VERSION 5.8 ;
BUSBITCHARS "[]" ;
DIVIDERCHAR "/" ;
UNITS
    DATABASE MICRONS 1000 ;
END UNITS

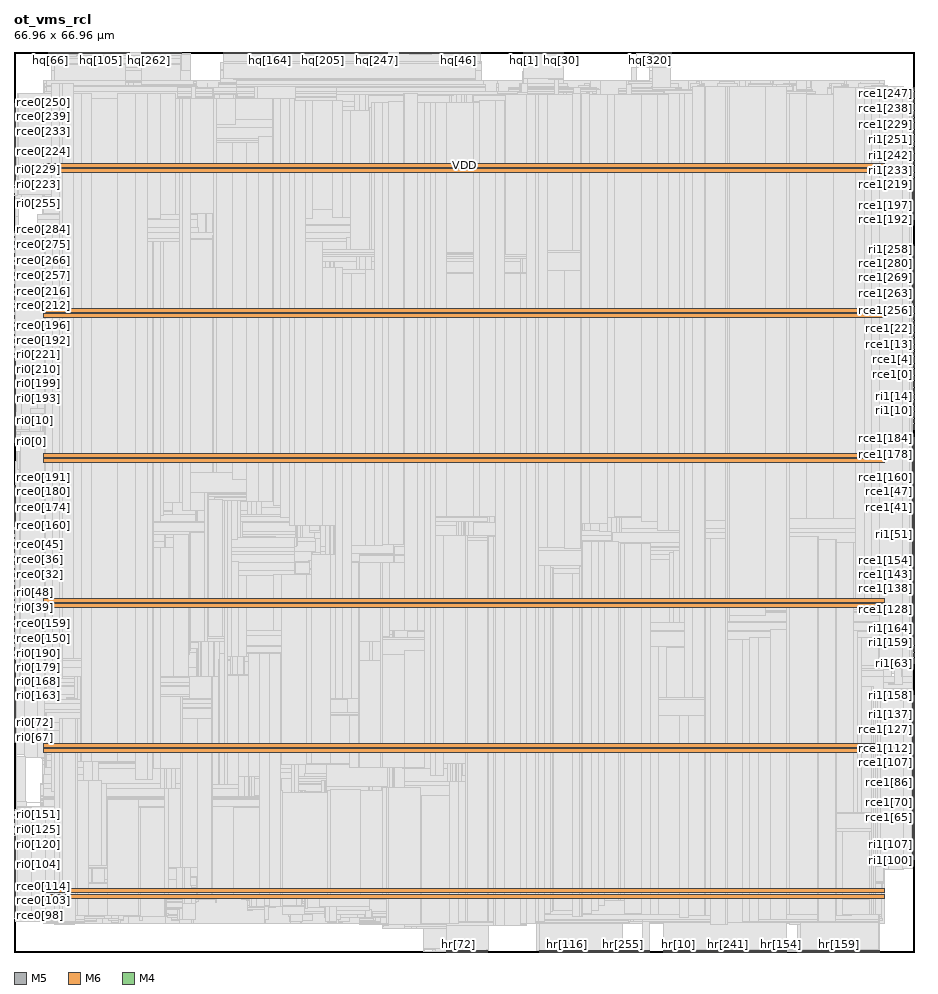
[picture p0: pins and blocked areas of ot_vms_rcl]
MACRO ot_vms_rcl
  FOREIGN ot_vms_rcl 0 0 ;
  CLASS BLOCK ;
  SIZE 66.96 BY 66.96 ;
  PIN clk
    DIRECTION INPUT ;
    USE SIGNAL ;
    PORT
      LAYER M5 ;
        RECT  48.336 0 48.36 0.084 ;
    END
  END clk
  PIN hq[0]
    DIRECTION OUTPUT ;
    USE SIGNAL ;
    PORT
      LAYER M5 ;
        RECT  37.872 66.876 37.896 66.96 ;
    END
  END hq[0]
  PIN hq[100]
    DIRECTION OUTPUT ;
    USE SIGNAL ;
    PORT
      LAYER M5 ;
        RECT  6 66.876 6.024 66.96 ;
    END
  END hq[100]
  PIN hq[101]
    DIRECTION OUTPUT ;
    USE SIGNAL ;
    PORT
      LAYER M5 ;
        RECT  6.096 66.876 6.12 66.96 ;
    END
  END hq[101]
  PIN hq[102]
    DIRECTION OUTPUT ;
    USE SIGNAL ;
    PORT
      LAYER M5 ;
        RECT  6.192 66.876 6.216 66.96 ;
    END
  END hq[102]
  PIN hq[103]
    DIRECTION OUTPUT ;
    USE SIGNAL ;
    PORT
      LAYER M5 ;
        RECT  6.288 66.876 6.312 66.96 ;
    END
  END hq[103]
  PIN hq[104]
    DIRECTION OUTPUT ;
    USE SIGNAL ;
    PORT
      LAYER M5 ;
        RECT  6.384 66.876 6.408 66.96 ;
    END
  END hq[104]
  PIN hq[105]
    DIRECTION OUTPUT ;
    USE SIGNAL ;
    PORT
      LAYER M5 ;
        RECT  6.48 66.876 6.504 66.96 ;
    END
  END hq[105]
  PIN hq[106]
    DIRECTION OUTPUT ;
    USE SIGNAL ;
    PORT
      LAYER M5 ;
        RECT  6.576 66.876 6.6 66.96 ;
    END
  END hq[106]
  PIN hq[107]
    DIRECTION OUTPUT ;
    USE SIGNAL ;
    PORT
      LAYER M5 ;
        RECT  6.672 66.876 6.696 66.96 ;
    END
  END hq[107]
  PIN hq[108]
    DIRECTION OUTPUT ;
    USE SIGNAL ;
    PORT
      LAYER M5 ;
        RECT  6.768 66.876 6.792 66.96 ;
    END
  END hq[108]
  PIN hq[109]
    DIRECTION OUTPUT ;
    USE SIGNAL ;
    PORT
      LAYER M5 ;
        RECT  6.864 66.876 6.888 66.96 ;
    END
  END hq[109]
  PIN hq[10]
    DIRECTION OUTPUT ;
    USE SIGNAL ;
    PORT
      LAYER M5 ;
        RECT  38.832 66.876 38.856 66.96 ;
    END
  END hq[10]
  PIN hq[110]
    DIRECTION OUTPUT ;
    USE SIGNAL ;
    PORT
      LAYER M5 ;
        RECT  6.96 66.876 6.984 66.96 ;
    END
  END hq[110]
  PIN hq[111]
    DIRECTION OUTPUT ;
    USE SIGNAL ;
    PORT
      LAYER M5 ;
        RECT  7.056 66.876 7.08 66.96 ;
    END
  END hq[111]
  PIN hq[112]
    DIRECTION OUTPUT ;
    USE SIGNAL ;
    PORT
      LAYER M5 ;
        RECT  7.152 66.876 7.176 66.96 ;
    END
  END hq[112]
  PIN hq[113]
    DIRECTION OUTPUT ;
    USE SIGNAL ;
    PORT
      LAYER M5 ;
        RECT  7.248 66.876 7.272 66.96 ;
    END
  END hq[113]
  PIN hq[114]
    DIRECTION OUTPUT ;
    USE SIGNAL ;
    PORT
      LAYER M5 ;
        RECT  7.344 66.876 7.368 66.96 ;
    END
  END hq[114]
  PIN hq[115]
    DIRECTION OUTPUT ;
    USE SIGNAL ;
    PORT
      LAYER M5 ;
        RECT  7.44 66.876 7.464 66.96 ;
    END
  END hq[115]
  PIN hq[116]
    DIRECTION OUTPUT ;
    USE SIGNAL ;
    PORT
      LAYER M5 ;
        RECT  7.536 66.876 7.56 66.96 ;
    END
  END hq[116]
  PIN hq[117]
    DIRECTION OUTPUT ;
    USE SIGNAL ;
    PORT
      LAYER M5 ;
        RECT  7.632 66.876 7.656 66.96 ;
    END
  END hq[117]
  PIN hq[118]
    DIRECTION OUTPUT ;
    USE SIGNAL ;
    PORT
      LAYER M5 ;
        RECT  7.728 66.876 7.752 66.96 ;
    END
  END hq[118]
  PIN hq[119]
    DIRECTION OUTPUT ;
    USE SIGNAL ;
    PORT
      LAYER M5 ;
        RECT  7.824 66.876 7.848 66.96 ;
    END
  END hq[119]
  PIN hq[11]
    DIRECTION OUTPUT ;
    USE SIGNAL ;
    PORT
      LAYER M5 ;
        RECT  38.928 66.876 38.952 66.96 ;
    END
  END hq[11]
  PIN hq[120]
    DIRECTION OUTPUT ;
    USE SIGNAL ;
    PORT
      LAYER M5 ;
        RECT  7.92 66.876 7.944 66.96 ;
    END
  END hq[120]
  PIN hq[121]
    DIRECTION OUTPUT ;
    USE SIGNAL ;
    PORT
      LAYER M5 ;
        RECT  8.016 66.876 8.04 66.96 ;
    END
  END hq[121]
  PIN hq[122]
    DIRECTION OUTPUT ;
    USE SIGNAL ;
    PORT
      LAYER M5 ;
        RECT  8.112 66.876 8.136 66.96 ;
    END
  END hq[122]
  PIN hq[123]
    DIRECTION OUTPUT ;
    USE SIGNAL ;
    PORT
      LAYER M5 ;
        RECT  8.208 66.876 8.232 66.96 ;
    END
  END hq[123]
  PIN hq[124]
    DIRECTION OUTPUT ;
    USE SIGNAL ;
    PORT
      LAYER M5 ;
        RECT  8.304 66.876 8.328 66.96 ;
    END
  END hq[124]
  PIN hq[125]
    DIRECTION OUTPUT ;
    USE SIGNAL ;
    PORT
      LAYER M5 ;
        RECT  8.4 66.876 8.424 66.96 ;
    END
  END hq[125]
  PIN hq[126]
    DIRECTION OUTPUT ;
    USE SIGNAL ;
    PORT
      LAYER M5 ;
        RECT  8.496 66.876 8.52 66.96 ;
    END
  END hq[126]
  PIN hq[127]
    DIRECTION OUTPUT ;
    USE SIGNAL ;
    PORT
      LAYER M5 ;
        RECT  8.592 66.876 8.616 66.96 ;
    END
  END hq[127]
  PIN hq[128]
    DIRECTION OUTPUT ;
    USE SIGNAL ;
    PORT
      LAYER M5 ;
        RECT  15.6 66.876 15.624 66.96 ;
    END
  END hq[128]
  PIN hq[129]
    DIRECTION OUTPUT ;
    USE SIGNAL ;
    PORT
      LAYER M5 ;
        RECT  15.696 66.876 15.72 66.96 ;
    END
  END hq[129]
  PIN hq[12]
    DIRECTION OUTPUT ;
    USE SIGNAL ;
    PORT
      LAYER M5 ;
        RECT  39.024 66.876 39.048 66.96 ;
    END
  END hq[12]
  PIN hq[130]
    DIRECTION OUTPUT ;
    USE SIGNAL ;
    PORT
      LAYER M5 ;
        RECT  15.792 66.876 15.816 66.96 ;
    END
  END hq[130]
  PIN hq[131]
    DIRECTION OUTPUT ;
    USE SIGNAL ;
    PORT
      LAYER M5 ;
        RECT  15.888 66.876 15.912 66.96 ;
    END
  END hq[131]
  PIN hq[132]
    DIRECTION OUTPUT ;
    USE SIGNAL ;
    PORT
      LAYER M5 ;
        RECT  15.984 66.876 16.008 66.96 ;
    END
  END hq[132]
  PIN hq[133]
    DIRECTION OUTPUT ;
    USE SIGNAL ;
    PORT
      LAYER M5 ;
        RECT  16.08 66.876 16.104 66.96 ;
    END
  END hq[133]
  PIN hq[134]
    DIRECTION OUTPUT ;
    USE SIGNAL ;
    PORT
      LAYER M5 ;
        RECT  16.176 66.876 16.2 66.96 ;
    END
  END hq[134]
  PIN hq[135]
    DIRECTION OUTPUT ;
    USE SIGNAL ;
    PORT
      LAYER M5 ;
        RECT  16.272 66.876 16.296 66.96 ;
    END
  END hq[135]
  PIN hq[136]
    DIRECTION OUTPUT ;
    USE SIGNAL ;
    PORT
      LAYER M5 ;
        RECT  16.368 66.876 16.392 66.96 ;
    END
  END hq[136]
  PIN hq[137]
    DIRECTION OUTPUT ;
    USE SIGNAL ;
    PORT
      LAYER M5 ;
        RECT  16.464 66.876 16.488 66.96 ;
    END
  END hq[137]
  PIN hq[138]
    DIRECTION OUTPUT ;
    USE SIGNAL ;
    PORT
      LAYER M5 ;
        RECT  16.56 66.876 16.584 66.96 ;
    END
  END hq[138]
  PIN hq[139]
    DIRECTION OUTPUT ;
    USE SIGNAL ;
    PORT
      LAYER M5 ;
        RECT  16.656 66.876 16.68 66.96 ;
    END
  END hq[139]
  PIN hq[13]
    DIRECTION OUTPUT ;
    USE SIGNAL ;
    PORT
      LAYER M5 ;
        RECT  39.12 66.876 39.144 66.96 ;
    END
  END hq[13]
  PIN hq[140]
    DIRECTION OUTPUT ;
    USE SIGNAL ;
    PORT
      LAYER M5 ;
        RECT  16.752 66.876 16.776 66.96 ;
    END
  END hq[140]
  PIN hq[141]
    DIRECTION OUTPUT ;
    USE SIGNAL ;
    PORT
      LAYER M5 ;
        RECT  16.848 66.876 16.872 66.96 ;
    END
  END hq[141]
  PIN hq[142]
    DIRECTION OUTPUT ;
    USE SIGNAL ;
    PORT
      LAYER M5 ;
        RECT  16.944 66.876 16.968 66.96 ;
    END
  END hq[142]
  PIN hq[143]
    DIRECTION OUTPUT ;
    USE SIGNAL ;
    PORT
      LAYER M5 ;
        RECT  17.04 66.876 17.064 66.96 ;
    END
  END hq[143]
  PIN hq[144]
    DIRECTION OUTPUT ;
    USE SIGNAL ;
    PORT
      LAYER M5 ;
        RECT  17.136 66.876 17.16 66.96 ;
    END
  END hq[144]
  PIN hq[145]
    DIRECTION OUTPUT ;
    USE SIGNAL ;
    PORT
      LAYER M5 ;
        RECT  17.232 66.876 17.256 66.96 ;
    END
  END hq[145]
  PIN hq[146]
    DIRECTION OUTPUT ;
    USE SIGNAL ;
    PORT
      LAYER M5 ;
        RECT  17.328 66.876 17.352 66.96 ;
    END
  END hq[146]
  PIN hq[147]
    DIRECTION OUTPUT ;
    USE SIGNAL ;
    PORT
      LAYER M5 ;
        RECT  17.424 66.876 17.448 66.96 ;
    END
  END hq[147]
  PIN hq[148]
    DIRECTION OUTPUT ;
    USE SIGNAL ;
    PORT
      LAYER M5 ;
        RECT  17.52 66.876 17.544 66.96 ;
    END
  END hq[148]
  PIN hq[149]
    DIRECTION OUTPUT ;
    USE SIGNAL ;
    PORT
      LAYER M5 ;
        RECT  17.616 66.876 17.64 66.96 ;
    END
  END hq[149]
  PIN hq[14]
    DIRECTION OUTPUT ;
    USE SIGNAL ;
    PORT
      LAYER M5 ;
        RECT  39.216 66.876 39.24 66.96 ;
    END
  END hq[14]
  PIN hq[150]
    DIRECTION OUTPUT ;
    USE SIGNAL ;
    PORT
      LAYER M5 ;
        RECT  17.712 66.876 17.736 66.96 ;
    END
  END hq[150]
  PIN hq[151]
    DIRECTION OUTPUT ;
    USE SIGNAL ;
    PORT
      LAYER M5 ;
        RECT  17.808 66.876 17.832 66.96 ;
    END
  END hq[151]
  PIN hq[152]
    DIRECTION OUTPUT ;
    USE SIGNAL ;
    PORT
      LAYER M5 ;
        RECT  17.904 66.876 17.928 66.96 ;
    END
  END hq[152]
  PIN hq[153]
    DIRECTION OUTPUT ;
    USE SIGNAL ;
    PORT
      LAYER M5 ;
        RECT  18 66.876 18.024 66.96 ;
    END
  END hq[153]
  PIN hq[154]
    DIRECTION OUTPUT ;
    USE SIGNAL ;
    PORT
      LAYER M5 ;
        RECT  18.096 66.876 18.12 66.96 ;
    END
  END hq[154]
  PIN hq[155]
    DIRECTION OUTPUT ;
    USE SIGNAL ;
    PORT
      LAYER M5 ;
        RECT  18.192 66.876 18.216 66.96 ;
    END
  END hq[155]
  PIN hq[156]
    DIRECTION OUTPUT ;
    USE SIGNAL ;
    PORT
      LAYER M5 ;
        RECT  18.288 66.876 18.312 66.96 ;
    END
  END hq[156]
  PIN hq[157]
    DIRECTION OUTPUT ;
    USE SIGNAL ;
    PORT
      LAYER M5 ;
        RECT  18.384 66.876 18.408 66.96 ;
    END
  END hq[157]
  PIN hq[158]
    DIRECTION OUTPUT ;
    USE SIGNAL ;
    PORT
      LAYER M5 ;
        RECT  18.48 66.876 18.504 66.96 ;
    END
  END hq[158]
  PIN hq[159]
    DIRECTION OUTPUT ;
    USE SIGNAL ;
    PORT
      LAYER M5 ;
        RECT  18.576 66.876 18.6 66.96 ;
    END
  END hq[159]
  PIN hq[15]
    DIRECTION OUTPUT ;
    USE SIGNAL ;
    PORT
      LAYER M5 ;
        RECT  39.312 66.876 39.336 66.96 ;
    END
  END hq[15]
  PIN hq[160]
    DIRECTION OUTPUT ;
    USE SIGNAL ;
    PORT
      LAYER M5 ;
        RECT  18.672 66.876 18.696 66.96 ;
    END
  END hq[160]
  PIN hq[161]
    DIRECTION OUTPUT ;
    USE SIGNAL ;
    PORT
      LAYER M5 ;
        RECT  18.768 66.876 18.792 66.96 ;
    END
  END hq[161]
  PIN hq[162]
    DIRECTION OUTPUT ;
    USE SIGNAL ;
    PORT
      LAYER M5 ;
        RECT  18.864 66.876 18.888 66.96 ;
    END
  END hq[162]
  PIN hq[163]
    DIRECTION OUTPUT ;
    USE SIGNAL ;
    PORT
      LAYER M5 ;
        RECT  18.96 66.876 18.984 66.96 ;
    END
  END hq[163]
  PIN hq[164]
    DIRECTION OUTPUT ;
    USE SIGNAL ;
    PORT
      LAYER M5 ;
        RECT  19.056 66.876 19.08 66.96 ;
    END
  END hq[164]
  PIN hq[165]
    DIRECTION OUTPUT ;
    USE SIGNAL ;
    PORT
      LAYER M5 ;
        RECT  19.152 66.876 19.176 66.96 ;
    END
  END hq[165]
  PIN hq[166]
    DIRECTION OUTPUT ;
    USE SIGNAL ;
    PORT
      LAYER M5 ;
        RECT  19.248 66.876 19.272 66.96 ;
    END
  END hq[166]
  PIN hq[167]
    DIRECTION OUTPUT ;
    USE SIGNAL ;
    PORT
      LAYER M5 ;
        RECT  19.344 66.876 19.368 66.96 ;
    END
  END hq[167]
  PIN hq[168]
    DIRECTION OUTPUT ;
    USE SIGNAL ;
    PORT
      LAYER M5 ;
        RECT  19.44 66.876 19.464 66.96 ;
    END
  END hq[168]
  PIN hq[169]
    DIRECTION OUTPUT ;
    USE SIGNAL ;
    PORT
      LAYER M5 ;
        RECT  19.536 66.876 19.56 66.96 ;
    END
  END hq[169]
  PIN hq[16]
    DIRECTION OUTPUT ;
    USE SIGNAL ;
    PORT
      LAYER M5 ;
        RECT  39.408 66.876 39.432 66.96 ;
    END
  END hq[16]
  PIN hq[170]
    DIRECTION OUTPUT ;
    USE SIGNAL ;
    PORT
      LAYER M5 ;
        RECT  19.632 66.876 19.656 66.96 ;
    END
  END hq[170]
  PIN hq[171]
    DIRECTION OUTPUT ;
    USE SIGNAL ;
    PORT
      LAYER M5 ;
        RECT  19.728 66.876 19.752 66.96 ;
    END
  END hq[171]
  PIN hq[172]
    DIRECTION OUTPUT ;
    USE SIGNAL ;
    PORT
      LAYER M5 ;
        RECT  19.824 66.876 19.848 66.96 ;
    END
  END hq[172]
  PIN hq[173]
    DIRECTION OUTPUT ;
    USE SIGNAL ;
    PORT
      LAYER M5 ;
        RECT  19.92 66.876 19.944 66.96 ;
    END
  END hq[173]
  PIN hq[174]
    DIRECTION OUTPUT ;
    USE SIGNAL ;
    PORT
      LAYER M5 ;
        RECT  20.016 66.876 20.04 66.96 ;
    END
  END hq[174]
  PIN hq[175]
    DIRECTION OUTPUT ;
    USE SIGNAL ;
    PORT
      LAYER M5 ;
        RECT  20.112 66.876 20.136 66.96 ;
    END
  END hq[175]
  PIN hq[176]
    DIRECTION OUTPUT ;
    USE SIGNAL ;
    PORT
      LAYER M5 ;
        RECT  20.208 66.876 20.232 66.96 ;
    END
  END hq[176]
  PIN hq[177]
    DIRECTION OUTPUT ;
    USE SIGNAL ;
    PORT
      LAYER M5 ;
        RECT  20.304 66.876 20.328 66.96 ;
    END
  END hq[177]
  PIN hq[178]
    DIRECTION OUTPUT ;
    USE SIGNAL ;
    PORT
      LAYER M5 ;
        RECT  20.4 66.876 20.424 66.96 ;
    END
  END hq[178]
  PIN hq[179]
    DIRECTION OUTPUT ;
    USE SIGNAL ;
    PORT
      LAYER M5 ;
        RECT  20.496 66.876 20.52 66.96 ;
    END
  END hq[179]
  PIN hq[17]
    DIRECTION OUTPUT ;
    USE SIGNAL ;
    PORT
      LAYER M5 ;
        RECT  39.504 66.876 39.528 66.96 ;
    END
  END hq[17]
  PIN hq[180]
    DIRECTION OUTPUT ;
    USE SIGNAL ;
    PORT
      LAYER M5 ;
        RECT  20.592 66.876 20.616 66.96 ;
    END
  END hq[180]
  PIN hq[181]
    DIRECTION OUTPUT ;
    USE SIGNAL ;
    PORT
      LAYER M5 ;
        RECT  20.688 66.876 20.712 66.96 ;
    END
  END hq[181]
  PIN hq[182]
    DIRECTION OUTPUT ;
    USE SIGNAL ;
    PORT
      LAYER M5 ;
        RECT  20.784 66.876 20.808 66.96 ;
    END
  END hq[182]
  PIN hq[183]
    DIRECTION OUTPUT ;
    USE SIGNAL ;
    PORT
      LAYER M5 ;
        RECT  20.88 66.876 20.904 66.96 ;
    END
  END hq[183]
  PIN hq[184]
    DIRECTION OUTPUT ;
    USE SIGNAL ;
    PORT
      LAYER M5 ;
        RECT  20.976 66.876 21 66.96 ;
    END
  END hq[184]
  PIN hq[185]
    DIRECTION OUTPUT ;
    USE SIGNAL ;
    PORT
      LAYER M5 ;
        RECT  21.072 66.876 21.096 66.96 ;
    END
  END hq[185]
  PIN hq[186]
    DIRECTION OUTPUT ;
    USE SIGNAL ;
    PORT
      LAYER M5 ;
        RECT  21.168 66.876 21.192 66.96 ;
    END
  END hq[186]
  PIN hq[187]
    DIRECTION OUTPUT ;
    USE SIGNAL ;
    PORT
      LAYER M5 ;
        RECT  21.264 66.876 21.288 66.96 ;
    END
  END hq[187]
  PIN hq[188]
    DIRECTION OUTPUT ;
    USE SIGNAL ;
    PORT
      LAYER M5 ;
        RECT  21.36 66.876 21.384 66.96 ;
    END
  END hq[188]
  PIN hq[189]
    DIRECTION OUTPUT ;
    USE SIGNAL ;
    PORT
      LAYER M5 ;
        RECT  21.456 66.876 21.48 66.96 ;
    END
  END hq[189]
  PIN hq[18]
    DIRECTION OUTPUT ;
    USE SIGNAL ;
    PORT
      LAYER M5 ;
        RECT  39.6 66.876 39.624 66.96 ;
    END
  END hq[18]
  PIN hq[190]
    DIRECTION OUTPUT ;
    USE SIGNAL ;
    PORT
      LAYER M5 ;
        RECT  21.552 66.876 21.576 66.96 ;
    END
  END hq[190]
  PIN hq[191]
    DIRECTION OUTPUT ;
    USE SIGNAL ;
    PORT
      LAYER M5 ;
        RECT  21.648 66.876 21.672 66.96 ;
    END
  END hq[191]
  PIN hq[192]
    DIRECTION OUTPUT ;
    USE SIGNAL ;
    PORT
      LAYER M5 ;
        RECT  21.744 66.876 21.768 66.96 ;
    END
  END hq[192]
  PIN hq[193]
    DIRECTION OUTPUT ;
    USE SIGNAL ;
    PORT
      LAYER M5 ;
        RECT  21.84 66.876 21.864 66.96 ;
    END
  END hq[193]
  PIN hq[194]
    DIRECTION OUTPUT ;
    USE SIGNAL ;
    PORT
      LAYER M5 ;
        RECT  21.936 66.876 21.96 66.96 ;
    END
  END hq[194]
  PIN hq[195]
    DIRECTION OUTPUT ;
    USE SIGNAL ;
    PORT
      LAYER M5 ;
        RECT  22.032 66.876 22.056 66.96 ;
    END
  END hq[195]
  PIN hq[196]
    DIRECTION OUTPUT ;
    USE SIGNAL ;
    PORT
      LAYER M5 ;
        RECT  22.128 66.876 22.152 66.96 ;
    END
  END hq[196]
  PIN hq[197]
    DIRECTION OUTPUT ;
    USE SIGNAL ;
    PORT
      LAYER M5 ;
        RECT  22.224 66.876 22.248 66.96 ;
    END
  END hq[197]
  PIN hq[198]
    DIRECTION OUTPUT ;
    USE SIGNAL ;
    PORT
      LAYER M5 ;
        RECT  22.32 66.876 22.344 66.96 ;
    END
  END hq[198]
  PIN hq[199]
    DIRECTION OUTPUT ;
    USE SIGNAL ;
    PORT
      LAYER M5 ;
        RECT  22.416 66.876 22.44 66.96 ;
    END
  END hq[199]
  PIN hq[19]
    DIRECTION OUTPUT ;
    USE SIGNAL ;
    PORT
      LAYER M5 ;
        RECT  39.696 66.876 39.72 66.96 ;
    END
  END hq[19]
  PIN hq[1]
    DIRECTION OUTPUT ;
    USE SIGNAL ;
    PORT
      LAYER M5 ;
        RECT  37.968 66.876 37.992 66.96 ;
    END
  END hq[1]
  PIN hq[200]
    DIRECTION OUTPUT ;
    USE SIGNAL ;
    PORT
      LAYER M5 ;
        RECT  22.512 66.876 22.536 66.96 ;
    END
  END hq[200]
  PIN hq[201]
    DIRECTION OUTPUT ;
    USE SIGNAL ;
    PORT
      LAYER M5 ;
        RECT  22.608 66.876 22.632 66.96 ;
    END
  END hq[201]
  PIN hq[202]
    DIRECTION OUTPUT ;
    USE SIGNAL ;
    PORT
      LAYER M5 ;
        RECT  22.704 66.876 22.728 66.96 ;
    END
  END hq[202]
  PIN hq[203]
    DIRECTION OUTPUT ;
    USE SIGNAL ;
    PORT
      LAYER M5 ;
        RECT  22.8 66.876 22.824 66.96 ;
    END
  END hq[203]
  PIN hq[204]
    DIRECTION OUTPUT ;
    USE SIGNAL ;
    PORT
      LAYER M5 ;
        RECT  22.896 66.876 22.92 66.96 ;
    END
  END hq[204]
  PIN hq[205]
    DIRECTION OUTPUT ;
    USE SIGNAL ;
    PORT
      LAYER M5 ;
        RECT  22.992 66.876 23.016 66.96 ;
    END
  END hq[205]
  PIN hq[206]
    DIRECTION OUTPUT ;
    USE SIGNAL ;
    PORT
      LAYER M5 ;
        RECT  23.088 66.876 23.112 66.96 ;
    END
  END hq[206]
  PIN hq[207]
    DIRECTION OUTPUT ;
    USE SIGNAL ;
    PORT
      LAYER M5 ;
        RECT  23.184 66.876 23.208 66.96 ;
    END
  END hq[207]
  PIN hq[208]
    DIRECTION OUTPUT ;
    USE SIGNAL ;
    PORT
      LAYER M5 ;
        RECT  23.28 66.876 23.304 66.96 ;
    END
  END hq[208]
  PIN hq[209]
    DIRECTION OUTPUT ;
    USE SIGNAL ;
    PORT
      LAYER M5 ;
        RECT  23.376 66.876 23.4 66.96 ;
    END
  END hq[209]
  PIN hq[20]
    DIRECTION OUTPUT ;
    USE SIGNAL ;
    PORT
      LAYER M5 ;
        RECT  39.792 66.876 39.816 66.96 ;
    END
  END hq[20]
  PIN hq[210]
    DIRECTION OUTPUT ;
    USE SIGNAL ;
    PORT
      LAYER M5 ;
        RECT  23.472 66.876 23.496 66.96 ;
    END
  END hq[210]
  PIN hq[211]
    DIRECTION OUTPUT ;
    USE SIGNAL ;
    PORT
      LAYER M5 ;
        RECT  23.568 66.876 23.592 66.96 ;
    END
  END hq[211]
  PIN hq[212]
    DIRECTION OUTPUT ;
    USE SIGNAL ;
    PORT
      LAYER M5 ;
        RECT  23.664 66.876 23.688 66.96 ;
    END
  END hq[212]
  PIN hq[213]
    DIRECTION OUTPUT ;
    USE SIGNAL ;
    PORT
      LAYER M5 ;
        RECT  23.76 66.876 23.784 66.96 ;
    END
  END hq[213]
  PIN hq[214]
    DIRECTION OUTPUT ;
    USE SIGNAL ;
    PORT
      LAYER M5 ;
        RECT  23.856 66.876 23.88 66.96 ;
    END
  END hq[214]
  PIN hq[215]
    DIRECTION OUTPUT ;
    USE SIGNAL ;
    PORT
      LAYER M5 ;
        RECT  23.952 66.876 23.976 66.96 ;
    END
  END hq[215]
  PIN hq[216]
    DIRECTION OUTPUT ;
    USE SIGNAL ;
    PORT
      LAYER M5 ;
        RECT  24.048 66.876 24.072 66.96 ;
    END
  END hq[216]
  PIN hq[217]
    DIRECTION OUTPUT ;
    USE SIGNAL ;
    PORT
      LAYER M5 ;
        RECT  24.144 66.876 24.168 66.96 ;
    END
  END hq[217]
  PIN hq[218]
    DIRECTION OUTPUT ;
    USE SIGNAL ;
    PORT
      LAYER M5 ;
        RECT  24.24 66.876 24.264 66.96 ;
    END
  END hq[218]
  PIN hq[219]
    DIRECTION OUTPUT ;
    USE SIGNAL ;
    PORT
      LAYER M5 ;
        RECT  24.336 66.876 24.36 66.96 ;
    END
  END hq[219]
  PIN hq[21]
    DIRECTION OUTPUT ;
    USE SIGNAL ;
    PORT
      LAYER M5 ;
        RECT  39.888 66.876 39.912 66.96 ;
    END
  END hq[21]
  PIN hq[220]
    DIRECTION OUTPUT ;
    USE SIGNAL ;
    PORT
      LAYER M5 ;
        RECT  24.432 66.876 24.456 66.96 ;
    END
  END hq[220]
  PIN hq[221]
    DIRECTION OUTPUT ;
    USE SIGNAL ;
    PORT
      LAYER M5 ;
        RECT  24.528 66.876 24.552 66.96 ;
    END
  END hq[221]
  PIN hq[222]
    DIRECTION OUTPUT ;
    USE SIGNAL ;
    PORT
      LAYER M5 ;
        RECT  24.624 66.876 24.648 66.96 ;
    END
  END hq[222]
  PIN hq[223]
    DIRECTION OUTPUT ;
    USE SIGNAL ;
    PORT
      LAYER M5 ;
        RECT  24.72 66.876 24.744 66.96 ;
    END
  END hq[223]
  PIN hq[224]
    DIRECTION OUTPUT ;
    USE SIGNAL ;
    PORT
      LAYER M5 ;
        RECT  24.816 66.876 24.84 66.96 ;
    END
  END hq[224]
  PIN hq[225]
    DIRECTION OUTPUT ;
    USE SIGNAL ;
    PORT
      LAYER M5 ;
        RECT  24.912 66.876 24.936 66.96 ;
    END
  END hq[225]
  PIN hq[226]
    DIRECTION OUTPUT ;
    USE SIGNAL ;
    PORT
      LAYER M5 ;
        RECT  25.008 66.876 25.032 66.96 ;
    END
  END hq[226]
  PIN hq[227]
    DIRECTION OUTPUT ;
    USE SIGNAL ;
    PORT
      LAYER M5 ;
        RECT  25.104 66.876 25.128 66.96 ;
    END
  END hq[227]
  PIN hq[228]
    DIRECTION OUTPUT ;
    USE SIGNAL ;
    PORT
      LAYER M5 ;
        RECT  25.2 66.876 25.224 66.96 ;
    END
  END hq[228]
  PIN hq[229]
    DIRECTION OUTPUT ;
    USE SIGNAL ;
    PORT
      LAYER M5 ;
        RECT  25.296 66.876 25.32 66.96 ;
    END
  END hq[229]
  PIN hq[22]
    DIRECTION OUTPUT ;
    USE SIGNAL ;
    PORT
      LAYER M5 ;
        RECT  39.984 66.876 40.008 66.96 ;
    END
  END hq[22]
  PIN hq[230]
    DIRECTION OUTPUT ;
    USE SIGNAL ;
    PORT
      LAYER M5 ;
        RECT  25.392 66.876 25.416 66.96 ;
    END
  END hq[230]
  PIN hq[231]
    DIRECTION OUTPUT ;
    USE SIGNAL ;
    PORT
      LAYER M5 ;
        RECT  25.488 66.876 25.512 66.96 ;
    END
  END hq[231]
  PIN hq[232]
    DIRECTION OUTPUT ;
    USE SIGNAL ;
    PORT
      LAYER M5 ;
        RECT  25.584 66.876 25.608 66.96 ;
    END
  END hq[232]
  PIN hq[233]
    DIRECTION OUTPUT ;
    USE SIGNAL ;
    PORT
      LAYER M5 ;
        RECT  25.68 66.876 25.704 66.96 ;
    END
  END hq[233]
  PIN hq[234]
    DIRECTION OUTPUT ;
    USE SIGNAL ;
    PORT
      LAYER M5 ;
        RECT  25.776 66.876 25.8 66.96 ;
    END
  END hq[234]
  PIN hq[235]
    DIRECTION OUTPUT ;
    USE SIGNAL ;
    PORT
      LAYER M5 ;
        RECT  25.872 66.876 25.896 66.96 ;
    END
  END hq[235]
  PIN hq[236]
    DIRECTION OUTPUT ;
    USE SIGNAL ;
    PORT
      LAYER M5 ;
        RECT  25.968 66.876 25.992 66.96 ;
    END
  END hq[236]
  PIN hq[237]
    DIRECTION OUTPUT ;
    USE SIGNAL ;
    PORT
      LAYER M5 ;
        RECT  26.064 66.876 26.088 66.96 ;
    END
  END hq[237]
  PIN hq[238]
    DIRECTION OUTPUT ;
    USE SIGNAL ;
    PORT
      LAYER M5 ;
        RECT  26.16 66.876 26.184 66.96 ;
    END
  END hq[238]
  PIN hq[239]
    DIRECTION OUTPUT ;
    USE SIGNAL ;
    PORT
      LAYER M5 ;
        RECT  26.256 66.876 26.28 66.96 ;
    END
  END hq[239]
  PIN hq[23]
    DIRECTION OUTPUT ;
    USE SIGNAL ;
    PORT
      LAYER M5 ;
        RECT  40.08 66.876 40.104 66.96 ;
    END
  END hq[23]
  PIN hq[240]
    DIRECTION OUTPUT ;
    USE SIGNAL ;
    PORT
      LAYER M5 ;
        RECT  26.352 66.876 26.376 66.96 ;
    END
  END hq[240]
  PIN hq[241]
    DIRECTION OUTPUT ;
    USE SIGNAL ;
    PORT
      LAYER M5 ;
        RECT  26.448 66.876 26.472 66.96 ;
    END
  END hq[241]
  PIN hq[242]
    DIRECTION OUTPUT ;
    USE SIGNAL ;
    PORT
      LAYER M5 ;
        RECT  26.544 66.876 26.568 66.96 ;
    END
  END hq[242]
  PIN hq[243]
    DIRECTION OUTPUT ;
    USE SIGNAL ;
    PORT
      LAYER M5 ;
        RECT  26.64 66.876 26.664 66.96 ;
    END
  END hq[243]
  PIN hq[244]
    DIRECTION OUTPUT ;
    USE SIGNAL ;
    PORT
      LAYER M5 ;
        RECT  26.736 66.876 26.76 66.96 ;
    END
  END hq[244]
  PIN hq[245]
    DIRECTION OUTPUT ;
    USE SIGNAL ;
    PORT
      LAYER M5 ;
        RECT  26.832 66.876 26.856 66.96 ;
    END
  END hq[245]
  PIN hq[246]
    DIRECTION OUTPUT ;
    USE SIGNAL ;
    PORT
      LAYER M5 ;
        RECT  26.928 66.876 26.952 66.96 ;
    END
  END hq[246]
  PIN hq[247]
    DIRECTION OUTPUT ;
    USE SIGNAL ;
    PORT
      LAYER M5 ;
        RECT  27.024 66.876 27.048 66.96 ;
    END
  END hq[247]
  PIN hq[248]
    DIRECTION OUTPUT ;
    USE SIGNAL ;
    PORT
      LAYER M5 ;
        RECT  27.12 66.876 27.144 66.96 ;
    END
  END hq[248]
  PIN hq[249]
    DIRECTION OUTPUT ;
    USE SIGNAL ;
    PORT
      LAYER M5 ;
        RECT  27.216 66.876 27.24 66.96 ;
    END
  END hq[249]
  PIN hq[24]
    DIRECTION OUTPUT ;
    USE SIGNAL ;
    PORT
      LAYER M5 ;
        RECT  40.176 66.876 40.2 66.96 ;
    END
  END hq[24]
  PIN hq[250]
    DIRECTION OUTPUT ;
    USE SIGNAL ;
    PORT
      LAYER M5 ;
        RECT  27.312 66.876 27.336 66.96 ;
    END
  END hq[250]
  PIN hq[251]
    DIRECTION OUTPUT ;
    USE SIGNAL ;
    PORT
      LAYER M5 ;
        RECT  27.408 66.876 27.432 66.96 ;
    END
  END hq[251]
  PIN hq[252]
    DIRECTION OUTPUT ;
    USE SIGNAL ;
    PORT
      LAYER M5 ;
        RECT  27.504 66.876 27.528 66.96 ;
    END
  END hq[252]
  PIN hq[253]
    DIRECTION OUTPUT ;
    USE SIGNAL ;
    PORT
      LAYER M5 ;
        RECT  27.6 66.876 27.624 66.96 ;
    END
  END hq[253]
  PIN hq[254]
    DIRECTION OUTPUT ;
    USE SIGNAL ;
    PORT
      LAYER M5 ;
        RECT  27.696 66.876 27.72 66.96 ;
    END
  END hq[254]
  PIN hq[255]
    DIRECTION OUTPUT ;
    USE SIGNAL ;
    PORT
      LAYER M5 ;
        RECT  27.792 66.876 27.816 66.96 ;
    END
  END hq[255]
  PIN hq[256]
    DIRECTION OUTPUT ;
    USE SIGNAL ;
    PORT
      LAYER M5 ;
        RECT  9.456 66.876 9.48 66.96 ;
    END
  END hq[256]
  PIN hq[257]
    DIRECTION OUTPUT ;
    USE SIGNAL ;
    PORT
      LAYER M5 ;
        RECT  9.552 66.876 9.576 66.96 ;
    END
  END hq[257]
  PIN hq[258]
    DIRECTION OUTPUT ;
    USE SIGNAL ;
    PORT
      LAYER M5 ;
        RECT  9.648 66.876 9.672 66.96 ;
    END
  END hq[258]
  PIN hq[259]
    DIRECTION OUTPUT ;
    USE SIGNAL ;
    PORT
      LAYER M5 ;
        RECT  9.744 66.876 9.768 66.96 ;
    END
  END hq[259]
  PIN hq[25]
    DIRECTION OUTPUT ;
    USE SIGNAL ;
    PORT
      LAYER M5 ;
        RECT  40.272 66.876 40.296 66.96 ;
    END
  END hq[25]
  PIN hq[260]
    DIRECTION OUTPUT ;
    USE SIGNAL ;
    PORT
      LAYER M5 ;
        RECT  9.84 66.876 9.864 66.96 ;
    END
  END hq[260]
  PIN hq[261]
    DIRECTION OUTPUT ;
    USE SIGNAL ;
    PORT
      LAYER M5 ;
        RECT  9.936 66.876 9.96 66.96 ;
    END
  END hq[261]
  PIN hq[262]
    DIRECTION OUTPUT ;
    USE SIGNAL ;
    PORT
      LAYER M5 ;
        RECT  10.032 66.876 10.056 66.96 ;
    END
  END hq[262]
  PIN hq[263]
    DIRECTION OUTPUT ;
    USE SIGNAL ;
    PORT
      LAYER M5 ;
        RECT  10.128 66.876 10.152 66.96 ;
    END
  END hq[263]
  PIN hq[264]
    DIRECTION OUTPUT ;
    USE SIGNAL ;
    PORT
      LAYER M5 ;
        RECT  10.224 66.876 10.248 66.96 ;
    END
  END hq[264]
  PIN hq[265]
    DIRECTION OUTPUT ;
    USE SIGNAL ;
    PORT
      LAYER M5 ;
        RECT  10.32 66.876 10.344 66.96 ;
    END
  END hq[265]
  PIN hq[266]
    DIRECTION OUTPUT ;
    USE SIGNAL ;
    PORT
      LAYER M5 ;
        RECT  10.416 66.876 10.44 66.96 ;
    END
  END hq[266]
  PIN hq[267]
    DIRECTION OUTPUT ;
    USE SIGNAL ;
    PORT
      LAYER M5 ;
        RECT  10.512 66.876 10.536 66.96 ;
    END
  END hq[267]
  PIN hq[268]
    DIRECTION OUTPUT ;
    USE SIGNAL ;
    PORT
      LAYER M5 ;
        RECT  10.608 66.876 10.632 66.96 ;
    END
  END hq[268]
  PIN hq[269]
    DIRECTION OUTPUT ;
    USE SIGNAL ;
    PORT
      LAYER M5 ;
        RECT  10.704 66.876 10.728 66.96 ;
    END
  END hq[269]
  PIN hq[26]
    DIRECTION OUTPUT ;
    USE SIGNAL ;
    PORT
      LAYER M5 ;
        RECT  40.368 66.876 40.392 66.96 ;
    END
  END hq[26]
  PIN hq[270]
    DIRECTION OUTPUT ;
    USE SIGNAL ;
    PORT
      LAYER M5 ;
        RECT  10.8 66.876 10.824 66.96 ;
    END
  END hq[270]
  PIN hq[271]
    DIRECTION OUTPUT ;
    USE SIGNAL ;
    PORT
      LAYER M5 ;
        RECT  10.896 66.876 10.92 66.96 ;
    END
  END hq[271]
  PIN hq[272]
    DIRECTION OUTPUT ;
    USE SIGNAL ;
    PORT
      LAYER M5 ;
        RECT  10.992 66.876 11.016 66.96 ;
    END
  END hq[272]
  PIN hq[273]
    DIRECTION OUTPUT ;
    USE SIGNAL ;
    PORT
      LAYER M5 ;
        RECT  11.088 66.876 11.112 66.96 ;
    END
  END hq[273]
  PIN hq[274]
    DIRECTION OUTPUT ;
    USE SIGNAL ;
    PORT
      LAYER M5 ;
        RECT  11.184 66.876 11.208 66.96 ;
    END
  END hq[274]
  PIN hq[275]
    DIRECTION OUTPUT ;
    USE SIGNAL ;
    PORT
      LAYER M5 ;
        RECT  11.28 66.876 11.304 66.96 ;
    END
  END hq[275]
  PIN hq[276]
    DIRECTION OUTPUT ;
    USE SIGNAL ;
    PORT
      LAYER M5 ;
        RECT  11.376 66.876 11.4 66.96 ;
    END
  END hq[276]
  PIN hq[277]
    DIRECTION OUTPUT ;
    USE SIGNAL ;
    PORT
      LAYER M5 ;
        RECT  11.472 66.876 11.496 66.96 ;
    END
  END hq[277]
  PIN hq[278]
    DIRECTION OUTPUT ;
    USE SIGNAL ;
    PORT
      LAYER M5 ;
        RECT  11.568 66.876 11.592 66.96 ;
    END
  END hq[278]
  PIN hq[279]
    DIRECTION OUTPUT ;
    USE SIGNAL ;
    PORT
      LAYER M5 ;
        RECT  11.664 66.876 11.688 66.96 ;
    END
  END hq[279]
  PIN hq[27]
    DIRECTION OUTPUT ;
    USE SIGNAL ;
    PORT
      LAYER M5 ;
        RECT  40.464 66.876 40.488 66.96 ;
    END
  END hq[27]
  PIN hq[280]
    DIRECTION OUTPUT ;
    USE SIGNAL ;
    PORT
      LAYER M5 ;
        RECT  11.76 66.876 11.784 66.96 ;
    END
  END hq[280]
  PIN hq[281]
    DIRECTION OUTPUT ;
    USE SIGNAL ;
    PORT
      LAYER M5 ;
        RECT  11.856 66.876 11.88 66.96 ;
    END
  END hq[281]
  PIN hq[282]
    DIRECTION OUTPUT ;
    USE SIGNAL ;
    PORT
      LAYER M5 ;
        RECT  11.952 66.876 11.976 66.96 ;
    END
  END hq[282]
  PIN hq[283]
    DIRECTION OUTPUT ;
    USE SIGNAL ;
    PORT
      LAYER M5 ;
        RECT  12.048 66.876 12.072 66.96 ;
    END
  END hq[283]
  PIN hq[284]
    DIRECTION OUTPUT ;
    USE SIGNAL ;
    PORT
      LAYER M5 ;
        RECT  12.144 66.876 12.168 66.96 ;
    END
  END hq[284]
  PIN hq[285]
    DIRECTION OUTPUT ;
    USE SIGNAL ;
    PORT
      LAYER M5 ;
        RECT  12.24 66.876 12.264 66.96 ;
    END
  END hq[285]
  PIN hq[286]
    DIRECTION OUTPUT ;
    USE SIGNAL ;
    PORT
      LAYER M5 ;
        RECT  12.336 66.876 12.36 66.96 ;
    END
  END hq[286]
  PIN hq[287]
    DIRECTION OUTPUT ;
    USE SIGNAL ;
    PORT
      LAYER M5 ;
        RECT  12.432 66.876 12.456 66.96 ;
    END
  END hq[287]
  PIN hq[288]
    DIRECTION OUTPUT ;
    USE SIGNAL ;
    PORT
      LAYER M5 ;
        RECT  28.656 66.876 28.68 66.96 ;
    END
  END hq[288]
  PIN hq[289]
    DIRECTION OUTPUT ;
    USE SIGNAL ;
    PORT
      LAYER M5 ;
        RECT  28.752 66.876 28.776 66.96 ;
    END
  END hq[289]
  PIN hq[28]
    DIRECTION OUTPUT ;
    USE SIGNAL ;
    PORT
      LAYER M5 ;
        RECT  40.56 66.876 40.584 66.96 ;
    END
  END hq[28]
  PIN hq[290]
    DIRECTION OUTPUT ;
    USE SIGNAL ;
    PORT
      LAYER M5 ;
        RECT  28.848 66.876 28.872 66.96 ;
    END
  END hq[290]
  PIN hq[291]
    DIRECTION OUTPUT ;
    USE SIGNAL ;
    PORT
      LAYER M5 ;
        RECT  28.944 66.876 28.968 66.96 ;
    END
  END hq[291]
  PIN hq[292]
    DIRECTION OUTPUT ;
    USE SIGNAL ;
    PORT
      LAYER M5 ;
        RECT  29.04 66.876 29.064 66.96 ;
    END
  END hq[292]
  PIN hq[293]
    DIRECTION OUTPUT ;
    USE SIGNAL ;
    PORT
      LAYER M5 ;
        RECT  29.136 66.876 29.16 66.96 ;
    END
  END hq[293]
  PIN hq[294]
    DIRECTION OUTPUT ;
    USE SIGNAL ;
    PORT
      LAYER M5 ;
        RECT  29.232 66.876 29.256 66.96 ;
    END
  END hq[294]
  PIN hq[295]
    DIRECTION OUTPUT ;
    USE SIGNAL ;
    PORT
      LAYER M5 ;
        RECT  29.328 66.876 29.352 66.96 ;
    END
  END hq[295]
  PIN hq[296]
    DIRECTION OUTPUT ;
    USE SIGNAL ;
    PORT
      LAYER M5 ;
        RECT  29.424 66.876 29.448 66.96 ;
    END
  END hq[296]
  PIN hq[297]
    DIRECTION OUTPUT ;
    USE SIGNAL ;
    PORT
      LAYER M5 ;
        RECT  29.52 66.876 29.544 66.96 ;
    END
  END hq[297]
  PIN hq[298]
    DIRECTION OUTPUT ;
    USE SIGNAL ;
    PORT
      LAYER M5 ;
        RECT  29.616 66.876 29.64 66.96 ;
    END
  END hq[298]
  PIN hq[299]
    DIRECTION OUTPUT ;
    USE SIGNAL ;
    PORT
      LAYER M5 ;
        RECT  29.712 66.876 29.736 66.96 ;
    END
  END hq[299]
  PIN hq[29]
    DIRECTION OUTPUT ;
    USE SIGNAL ;
    PORT
      LAYER M5 ;
        RECT  40.656 66.876 40.68 66.96 ;
    END
  END hq[29]
  PIN hq[2]
    DIRECTION OUTPUT ;
    USE SIGNAL ;
    PORT
      LAYER M5 ;
        RECT  38.064 66.876 38.088 66.96 ;
    END
  END hq[2]
  PIN hq[300]
    DIRECTION OUTPUT ;
    USE SIGNAL ;
    PORT
      LAYER M5 ;
        RECT  29.808 66.876 29.832 66.96 ;
    END
  END hq[300]
  PIN hq[301]
    DIRECTION OUTPUT ;
    USE SIGNAL ;
    PORT
      LAYER M5 ;
        RECT  29.904 66.876 29.928 66.96 ;
    END
  END hq[301]
  PIN hq[302]
    DIRECTION OUTPUT ;
    USE SIGNAL ;
    PORT
      LAYER M5 ;
        RECT  30 66.876 30.024 66.96 ;
    END
  END hq[302]
  PIN hq[303]
    DIRECTION OUTPUT ;
    USE SIGNAL ;
    PORT
      LAYER M5 ;
        RECT  30.096 66.876 30.12 66.96 ;
    END
  END hq[303]
  PIN hq[304]
    DIRECTION OUTPUT ;
    USE SIGNAL ;
    PORT
      LAYER M5 ;
        RECT  30.192 66.876 30.216 66.96 ;
    END
  END hq[304]
  PIN hq[305]
    DIRECTION OUTPUT ;
    USE SIGNAL ;
    PORT
      LAYER M5 ;
        RECT  30.288 66.876 30.312 66.96 ;
    END
  END hq[305]
  PIN hq[306]
    DIRECTION OUTPUT ;
    USE SIGNAL ;
    PORT
      LAYER M5 ;
        RECT  30.384 66.876 30.408 66.96 ;
    END
  END hq[306]
  PIN hq[307]
    DIRECTION OUTPUT ;
    USE SIGNAL ;
    PORT
      LAYER M5 ;
        RECT  30.48 66.876 30.504 66.96 ;
    END
  END hq[307]
  PIN hq[308]
    DIRECTION OUTPUT ;
    USE SIGNAL ;
    PORT
      LAYER M5 ;
        RECT  30.576 66.876 30.6 66.96 ;
    END
  END hq[308]
  PIN hq[309]
    DIRECTION OUTPUT ;
    USE SIGNAL ;
    PORT
      LAYER M5 ;
        RECT  30.672 66.876 30.696 66.96 ;
    END
  END hq[309]
  PIN hq[30]
    DIRECTION OUTPUT ;
    USE SIGNAL ;
    PORT
      LAYER M5 ;
        RECT  40.752 66.876 40.776 66.96 ;
    END
  END hq[30]
  PIN hq[310]
    DIRECTION OUTPUT ;
    USE SIGNAL ;
    PORT
      LAYER M5 ;
        RECT  30.768 66.876 30.792 66.96 ;
    END
  END hq[310]
  PIN hq[311]
    DIRECTION OUTPUT ;
    USE SIGNAL ;
    PORT
      LAYER M5 ;
        RECT  30.864 66.876 30.888 66.96 ;
    END
  END hq[311]
  PIN hq[312]
    DIRECTION OUTPUT ;
    USE SIGNAL ;
    PORT
      LAYER M5 ;
        RECT  30.96 66.876 30.984 66.96 ;
    END
  END hq[312]
  PIN hq[313]
    DIRECTION OUTPUT ;
    USE SIGNAL ;
    PORT
      LAYER M5 ;
        RECT  31.056 66.876 31.08 66.96 ;
    END
  END hq[313]
  PIN hq[314]
    DIRECTION OUTPUT ;
    USE SIGNAL ;
    PORT
      LAYER M5 ;
        RECT  31.152 66.876 31.176 66.96 ;
    END
  END hq[314]
  PIN hq[315]
    DIRECTION OUTPUT ;
    USE SIGNAL ;
    PORT
      LAYER M5 ;
        RECT  31.248 66.876 31.272 66.96 ;
    END
  END hq[315]
  PIN hq[316]
    DIRECTION OUTPUT ;
    USE SIGNAL ;
    PORT
      LAYER M5 ;
        RECT  31.344 66.876 31.368 66.96 ;
    END
  END hq[316]
  PIN hq[317]
    DIRECTION OUTPUT ;
    USE SIGNAL ;
    PORT
      LAYER M5 ;
        RECT  31.44 66.876 31.464 66.96 ;
    END
  END hq[317]
  PIN hq[318]
    DIRECTION OUTPUT ;
    USE SIGNAL ;
    PORT
      LAYER M5 ;
        RECT  31.536 66.876 31.56 66.96 ;
    END
  END hq[318]
  PIN hq[319]
    DIRECTION OUTPUT ;
    USE SIGNAL ;
    PORT
      LAYER M5 ;
        RECT  31.632 66.876 31.656 66.96 ;
    END
  END hq[319]
  PIN hq[31]
    DIRECTION OUTPUT ;
    USE SIGNAL ;
    PORT
      LAYER M5 ;
        RECT  40.848 66.876 40.872 66.96 ;
    END
  END hq[31]
  PIN hq[320]
    DIRECTION OUTPUT ;
    USE SIGNAL ;
    PORT
      LAYER M5 ;
        RECT  47.28 66.876 47.304 66.96 ;
    END
  END hq[320]
  PIN hq[321]
    DIRECTION OUTPUT ;
    USE SIGNAL ;
    PORT
      LAYER M5 ;
        RECT  47.376 66.876 47.4 66.96 ;
    END
  END hq[321]
  PIN hq[322]
    DIRECTION OUTPUT ;
    USE SIGNAL ;
    PORT
      LAYER M5 ;
        RECT  47.472 66.876 47.496 66.96 ;
    END
  END hq[322]
  PIN hq[323]
    DIRECTION OUTPUT ;
    USE SIGNAL ;
    PORT
      LAYER M5 ;
        RECT  47.568 66.876 47.592 66.96 ;
    END
  END hq[323]
  PIN hq[324]
    DIRECTION OUTPUT ;
    USE SIGNAL ;
    PORT
      LAYER M5 ;
        RECT  47.664 66.876 47.688 66.96 ;
    END
  END hq[324]
  PIN hq[325]
    DIRECTION OUTPUT ;
    USE SIGNAL ;
    PORT
      LAYER M5 ;
        RECT  47.76 66.876 47.784 66.96 ;
    END
  END hq[325]
  PIN hq[326]
    DIRECTION OUTPUT ;
    USE SIGNAL ;
    PORT
      LAYER M5 ;
        RECT  47.856 66.876 47.88 66.96 ;
    END
  END hq[326]
  PIN hq[327]
    DIRECTION OUTPUT ;
    USE SIGNAL ;
    PORT
      LAYER M5 ;
        RECT  47.952 66.876 47.976 66.96 ;
    END
  END hq[327]
  PIN hq[328]
    DIRECTION OUTPUT ;
    USE SIGNAL ;
    PORT
      LAYER M5 ;
        RECT  48.048 66.876 48.072 66.96 ;
    END
  END hq[328]
  PIN hq[329]
    DIRECTION OUTPUT ;
    USE SIGNAL ;
    PORT
      LAYER M5 ;
        RECT  48.144 66.876 48.168 66.96 ;
    END
  END hq[329]
  PIN hq[32]
    DIRECTION OUTPUT ;
    USE SIGNAL ;
    PORT
      LAYER M5 ;
        RECT  31.728 66.876 31.752 66.96 ;
    END
  END hq[32]
  PIN hq[330]
    DIRECTION OUTPUT ;
    USE SIGNAL ;
    PORT
      LAYER M5 ;
        RECT  48.24 66.876 48.264 66.96 ;
    END
  END hq[330]
  PIN hq[331]
    DIRECTION OUTPUT ;
    USE SIGNAL ;
    PORT
      LAYER M5 ;
        RECT  48.336 66.876 48.36 66.96 ;
    END
  END hq[331]
  PIN hq[332]
    DIRECTION OUTPUT ;
    USE SIGNAL ;
    PORT
      LAYER M5 ;
        RECT  48.432 66.876 48.456 66.96 ;
    END
  END hq[332]
  PIN hq[333]
    DIRECTION OUTPUT ;
    USE SIGNAL ;
    PORT
      LAYER M5 ;
        RECT  48.528 66.876 48.552 66.96 ;
    END
  END hq[333]
  PIN hq[334]
    DIRECTION OUTPUT ;
    USE SIGNAL ;
    PORT
      LAYER M5 ;
        RECT  48.624 66.876 48.648 66.96 ;
    END
  END hq[334]
  PIN hq[335]
    DIRECTION OUTPUT ;
    USE SIGNAL ;
    PORT
      LAYER M5 ;
        RECT  48.72 66.876 48.744 66.96 ;
    END
  END hq[335]
  PIN hq[336]
    DIRECTION OUTPUT ;
    USE SIGNAL ;
    PORT
      LAYER M5 ;
        RECT  48.816 66.876 48.84 66.96 ;
    END
  END hq[336]
  PIN hq[337]
    DIRECTION OUTPUT ;
    USE SIGNAL ;
    PORT
      LAYER M5 ;
        RECT  48.912 66.876 48.936 66.96 ;
    END
  END hq[337]
  PIN hq[33]
    DIRECTION OUTPUT ;
    USE SIGNAL ;
    PORT
      LAYER M5 ;
        RECT  31.824 66.876 31.848 66.96 ;
    END
  END hq[33]
  PIN hq[34]
    DIRECTION OUTPUT ;
    USE SIGNAL ;
    PORT
      LAYER M5 ;
        RECT  31.92 66.876 31.944 66.96 ;
    END
  END hq[34]
  PIN hq[35]
    DIRECTION OUTPUT ;
    USE SIGNAL ;
    PORT
      LAYER M5 ;
        RECT  32.016 66.876 32.04 66.96 ;
    END
  END hq[35]
  PIN hq[36]
    DIRECTION OUTPUT ;
    USE SIGNAL ;
    PORT
      LAYER M5 ;
        RECT  32.112 66.876 32.136 66.96 ;
    END
  END hq[36]
  PIN hq[37]
    DIRECTION OUTPUT ;
    USE SIGNAL ;
    PORT
      LAYER M5 ;
        RECT  32.208 66.876 32.232 66.96 ;
    END
  END hq[37]
  PIN hq[38]
    DIRECTION OUTPUT ;
    USE SIGNAL ;
    PORT
      LAYER M5 ;
        RECT  32.304 66.876 32.328 66.96 ;
    END
  END hq[38]
  PIN hq[39]
    DIRECTION OUTPUT ;
    USE SIGNAL ;
    PORT
      LAYER M5 ;
        RECT  32.4 66.876 32.424 66.96 ;
    END
  END hq[39]
  PIN hq[3]
    DIRECTION OUTPUT ;
    USE SIGNAL ;
    PORT
      LAYER M5 ;
        RECT  38.16 66.876 38.184 66.96 ;
    END
  END hq[3]
  PIN hq[40]
    DIRECTION OUTPUT ;
    USE SIGNAL ;
    PORT
      LAYER M5 ;
        RECT  32.496 66.876 32.52 66.96 ;
    END
  END hq[40]
  PIN hq[41]
    DIRECTION OUTPUT ;
    USE SIGNAL ;
    PORT
      LAYER M5 ;
        RECT  32.592 66.876 32.616 66.96 ;
    END
  END hq[41]
  PIN hq[42]
    DIRECTION OUTPUT ;
    USE SIGNAL ;
    PORT
      LAYER M5 ;
        RECT  32.688 66.876 32.712 66.96 ;
    END
  END hq[42]
  PIN hq[43]
    DIRECTION OUTPUT ;
    USE SIGNAL ;
    PORT
      LAYER M5 ;
        RECT  32.784 66.876 32.808 66.96 ;
    END
  END hq[43]
  PIN hq[44]
    DIRECTION OUTPUT ;
    USE SIGNAL ;
    PORT
      LAYER M5 ;
        RECT  32.88 66.876 32.904 66.96 ;
    END
  END hq[44]
  PIN hq[45]
    DIRECTION OUTPUT ;
    USE SIGNAL ;
    PORT
      LAYER M5 ;
        RECT  32.976 66.876 33 66.96 ;
    END
  END hq[45]
  PIN hq[46]
    DIRECTION OUTPUT ;
    USE SIGNAL ;
    PORT
      LAYER M5 ;
        RECT  33.072 66.876 33.096 66.96 ;
    END
  END hq[46]
  PIN hq[47]
    DIRECTION OUTPUT ;
    USE SIGNAL ;
    PORT
      LAYER M5 ;
        RECT  33.168 66.876 33.192 66.96 ;
    END
  END hq[47]
  PIN hq[48]
    DIRECTION OUTPUT ;
    USE SIGNAL ;
    PORT
      LAYER M5 ;
        RECT  33.264 66.876 33.288 66.96 ;
    END
  END hq[48]
  PIN hq[49]
    DIRECTION OUTPUT ;
    USE SIGNAL ;
    PORT
      LAYER M5 ;
        RECT  33.36 66.876 33.384 66.96 ;
    END
  END hq[49]
  PIN hq[4]
    DIRECTION OUTPUT ;
    USE SIGNAL ;
    PORT
      LAYER M5 ;
        RECT  38.256 66.876 38.28 66.96 ;
    END
  END hq[4]
  PIN hq[50]
    DIRECTION OUTPUT ;
    USE SIGNAL ;
    PORT
      LAYER M5 ;
        RECT  33.456 66.876 33.48 66.96 ;
    END
  END hq[50]
  PIN hq[51]
    DIRECTION OUTPUT ;
    USE SIGNAL ;
    PORT
      LAYER M5 ;
        RECT  33.552 66.876 33.576 66.96 ;
    END
  END hq[51]
  PIN hq[52]
    DIRECTION OUTPUT ;
    USE SIGNAL ;
    PORT
      LAYER M5 ;
        RECT  33.648 66.876 33.672 66.96 ;
    END
  END hq[52]
  PIN hq[53]
    DIRECTION OUTPUT ;
    USE SIGNAL ;
    PORT
      LAYER M5 ;
        RECT  33.744 66.876 33.768 66.96 ;
    END
  END hq[53]
  PIN hq[54]
    DIRECTION OUTPUT ;
    USE SIGNAL ;
    PORT
      LAYER M5 ;
        RECT  33.84 66.876 33.864 66.96 ;
    END
  END hq[54]
  PIN hq[55]
    DIRECTION OUTPUT ;
    USE SIGNAL ;
    PORT
      LAYER M5 ;
        RECT  33.936 66.876 33.96 66.96 ;
    END
  END hq[55]
  PIN hq[56]
    DIRECTION OUTPUT ;
    USE SIGNAL ;
    PORT
      LAYER M5 ;
        RECT  34.032 66.876 34.056 66.96 ;
    END
  END hq[56]
  PIN hq[57]
    DIRECTION OUTPUT ;
    USE SIGNAL ;
    PORT
      LAYER M5 ;
        RECT  34.128 66.876 34.152 66.96 ;
    END
  END hq[57]
  PIN hq[58]
    DIRECTION OUTPUT ;
    USE SIGNAL ;
    PORT
      LAYER M5 ;
        RECT  34.224 66.876 34.248 66.96 ;
    END
  END hq[58]
  PIN hq[59]
    DIRECTION OUTPUT ;
    USE SIGNAL ;
    PORT
      LAYER M5 ;
        RECT  34.32 66.876 34.344 66.96 ;
    END
  END hq[59]
  PIN hq[5]
    DIRECTION OUTPUT ;
    USE SIGNAL ;
    PORT
      LAYER M5 ;
        RECT  38.352 66.876 38.376 66.96 ;
    END
  END hq[5]
  PIN hq[60]
    DIRECTION OUTPUT ;
    USE SIGNAL ;
    PORT
      LAYER M5 ;
        RECT  34.416 66.876 34.44 66.96 ;
    END
  END hq[60]
  PIN hq[61]
    DIRECTION OUTPUT ;
    USE SIGNAL ;
    PORT
      LAYER M5 ;
        RECT  34.512 66.876 34.536 66.96 ;
    END
  END hq[61]
  PIN hq[62]
    DIRECTION OUTPUT ;
    USE SIGNAL ;
    PORT
      LAYER M5 ;
        RECT  34.608 66.876 34.632 66.96 ;
    END
  END hq[62]
  PIN hq[63]
    DIRECTION OUTPUT ;
    USE SIGNAL ;
    PORT
      LAYER M5 ;
        RECT  34.704 66.876 34.728 66.96 ;
    END
  END hq[63]
  PIN hq[64]
    DIRECTION OUTPUT ;
    USE SIGNAL ;
    PORT
      LAYER M5 ;
        RECT  2.544 66.876 2.568 66.96 ;
    END
  END hq[64]
  PIN hq[65]
    DIRECTION OUTPUT ;
    USE SIGNAL ;
    PORT
      LAYER M5 ;
        RECT  2.64 66.876 2.664 66.96 ;
    END
  END hq[65]
  PIN hq[66]
    DIRECTION OUTPUT ;
    USE SIGNAL ;
    PORT
      LAYER M5 ;
        RECT  2.736 66.876 2.76 66.96 ;
    END
  END hq[66]
  PIN hq[67]
    DIRECTION OUTPUT ;
    USE SIGNAL ;
    PORT
      LAYER M5 ;
        RECT  2.832 66.876 2.856 66.96 ;
    END
  END hq[67]
  PIN hq[68]
    DIRECTION OUTPUT ;
    USE SIGNAL ;
    PORT
      LAYER M5 ;
        RECT  2.928 66.876 2.952 66.96 ;
    END
  END hq[68]
  PIN hq[69]
    DIRECTION OUTPUT ;
    USE SIGNAL ;
    PORT
      LAYER M5 ;
        RECT  3.024 66.876 3.048 66.96 ;
    END
  END hq[69]
  PIN hq[6]
    DIRECTION OUTPUT ;
    USE SIGNAL ;
    PORT
      LAYER M5 ;
        RECT  38.448 66.876 38.472 66.96 ;
    END
  END hq[6]
  PIN hq[70]
    DIRECTION OUTPUT ;
    USE SIGNAL ;
    PORT
      LAYER M5 ;
        RECT  3.12 66.876 3.144 66.96 ;
    END
  END hq[70]
  PIN hq[71]
    DIRECTION OUTPUT ;
    USE SIGNAL ;
    PORT
      LAYER M5 ;
        RECT  3.216 66.876 3.24 66.96 ;
    END
  END hq[71]
  PIN hq[72]
    DIRECTION OUTPUT ;
    USE SIGNAL ;
    PORT
      LAYER M5 ;
        RECT  3.312 66.876 3.336 66.96 ;
    END
  END hq[72]
  PIN hq[73]
    DIRECTION OUTPUT ;
    USE SIGNAL ;
    PORT
      LAYER M5 ;
        RECT  3.408 66.876 3.432 66.96 ;
    END
  END hq[73]
  PIN hq[74]
    DIRECTION OUTPUT ;
    USE SIGNAL ;
    PORT
      LAYER M5 ;
        RECT  3.504 66.876 3.528 66.96 ;
    END
  END hq[74]
  PIN hq[75]
    DIRECTION OUTPUT ;
    USE SIGNAL ;
    PORT
      LAYER M5 ;
        RECT  3.6 66.876 3.624 66.96 ;
    END
  END hq[75]
  PIN hq[76]
    DIRECTION OUTPUT ;
    USE SIGNAL ;
    PORT
      LAYER M5 ;
        RECT  3.696 66.876 3.72 66.96 ;
    END
  END hq[76]
  PIN hq[77]
    DIRECTION OUTPUT ;
    USE SIGNAL ;
    PORT
      LAYER M5 ;
        RECT  3.792 66.876 3.816 66.96 ;
    END
  END hq[77]
  PIN hq[78]
    DIRECTION OUTPUT ;
    USE SIGNAL ;
    PORT
      LAYER M5 ;
        RECT  3.888 66.876 3.912 66.96 ;
    END
  END hq[78]
  PIN hq[79]
    DIRECTION OUTPUT ;
    USE SIGNAL ;
    PORT
      LAYER M5 ;
        RECT  3.984 66.876 4.008 66.96 ;
    END
  END hq[79]
  PIN hq[7]
    DIRECTION OUTPUT ;
    USE SIGNAL ;
    PORT
      LAYER M5 ;
        RECT  38.544 66.876 38.568 66.96 ;
    END
  END hq[7]
  PIN hq[80]
    DIRECTION OUTPUT ;
    USE SIGNAL ;
    PORT
      LAYER M5 ;
        RECT  4.08 66.876 4.104 66.96 ;
    END
  END hq[80]
  PIN hq[81]
    DIRECTION OUTPUT ;
    USE SIGNAL ;
    PORT
      LAYER M5 ;
        RECT  4.176 66.876 4.2 66.96 ;
    END
  END hq[81]
  PIN hq[82]
    DIRECTION OUTPUT ;
    USE SIGNAL ;
    PORT
      LAYER M5 ;
        RECT  4.272 66.876 4.296 66.96 ;
    END
  END hq[82]
  PIN hq[83]
    DIRECTION OUTPUT ;
    USE SIGNAL ;
    PORT
      LAYER M5 ;
        RECT  4.368 66.876 4.392 66.96 ;
    END
  END hq[83]
  PIN hq[84]
    DIRECTION OUTPUT ;
    USE SIGNAL ;
    PORT
      LAYER M5 ;
        RECT  4.464 66.876 4.488 66.96 ;
    END
  END hq[84]
  PIN hq[85]
    DIRECTION OUTPUT ;
    USE SIGNAL ;
    PORT
      LAYER M5 ;
        RECT  4.56 66.876 4.584 66.96 ;
    END
  END hq[85]
  PIN hq[86]
    DIRECTION OUTPUT ;
    USE SIGNAL ;
    PORT
      LAYER M5 ;
        RECT  4.656 66.876 4.68 66.96 ;
    END
  END hq[86]
  PIN hq[87]
    DIRECTION OUTPUT ;
    USE SIGNAL ;
    PORT
      LAYER M5 ;
        RECT  4.752 66.876 4.776 66.96 ;
    END
  END hq[87]
  PIN hq[88]
    DIRECTION OUTPUT ;
    USE SIGNAL ;
    PORT
      LAYER M5 ;
        RECT  4.848 66.876 4.872 66.96 ;
    END
  END hq[88]
  PIN hq[89]
    DIRECTION OUTPUT ;
    USE SIGNAL ;
    PORT
      LAYER M5 ;
        RECT  4.944 66.876 4.968 66.96 ;
    END
  END hq[89]
  PIN hq[8]
    DIRECTION OUTPUT ;
    USE SIGNAL ;
    PORT
      LAYER M5 ;
        RECT  38.64 66.876 38.664 66.96 ;
    END
  END hq[8]
  PIN hq[90]
    DIRECTION OUTPUT ;
    USE SIGNAL ;
    PORT
      LAYER M5 ;
        RECT  5.04 66.876 5.064 66.96 ;
    END
  END hq[90]
  PIN hq[91]
    DIRECTION OUTPUT ;
    USE SIGNAL ;
    PORT
      LAYER M5 ;
        RECT  5.136 66.876 5.16 66.96 ;
    END
  END hq[91]
  PIN hq[92]
    DIRECTION OUTPUT ;
    USE SIGNAL ;
    PORT
      LAYER M5 ;
        RECT  5.232 66.876 5.256 66.96 ;
    END
  END hq[92]
  PIN hq[93]
    DIRECTION OUTPUT ;
    USE SIGNAL ;
    PORT
      LAYER M5 ;
        RECT  5.328 66.876 5.352 66.96 ;
    END
  END hq[93]
  PIN hq[94]
    DIRECTION OUTPUT ;
    USE SIGNAL ;
    PORT
      LAYER M5 ;
        RECT  5.424 66.876 5.448 66.96 ;
    END
  END hq[94]
  PIN hq[95]
    DIRECTION OUTPUT ;
    USE SIGNAL ;
    PORT
      LAYER M5 ;
        RECT  5.52 66.876 5.544 66.96 ;
    END
  END hq[95]
  PIN hq[96]
    DIRECTION OUTPUT ;
    USE SIGNAL ;
    PORT
      LAYER M5 ;
        RECT  5.616 66.876 5.64 66.96 ;
    END
  END hq[96]
  PIN hq[97]
    DIRECTION OUTPUT ;
    USE SIGNAL ;
    PORT
      LAYER M5 ;
        RECT  5.712 66.876 5.736 66.96 ;
    END
  END hq[97]
  PIN hq[98]
    DIRECTION OUTPUT ;
    USE SIGNAL ;
    PORT
      LAYER M5 ;
        RECT  5.808 66.876 5.832 66.96 ;
    END
  END hq[98]
  PIN hq[99]
    DIRECTION OUTPUT ;
    USE SIGNAL ;
    PORT
      LAYER M5 ;
        RECT  5.904 66.876 5.928 66.96 ;
    END
  END hq[99]
  PIN hq[9]
    DIRECTION OUTPUT ;
    USE SIGNAL ;
    PORT
      LAYER M5 ;
        RECT  38.736 66.876 38.76 66.96 ;
    END
  END hq[9]
  PIN hr[0]
    DIRECTION INPUT ;
    USE SIGNAL ;
    PORT
      LAYER M5 ;
        RECT  48.432 0 48.456 0.084 ;
    END
  END hr[0]
  PIN hr[100]
    DIRECTION INPUT ;
    USE SIGNAL ;
    PORT
      LAYER M5 ;
        RECT  39.6 0 39.624 0.084 ;
    END
  END hr[100]
  PIN hr[101]
    DIRECTION INPUT ;
    USE SIGNAL ;
    PORT
      LAYER M5 ;
        RECT  39.696 0 39.72 0.084 ;
    END
  END hr[101]
  PIN hr[102]
    DIRECTION INPUT ;
    USE SIGNAL ;
    PORT
      LAYER M5 ;
        RECT  39.792 0 39.816 0.084 ;
    END
  END hr[102]
  PIN hr[103]
    DIRECTION INPUT ;
    USE SIGNAL ;
    PORT
      LAYER M5 ;
        RECT  39.888 0 39.912 0.084 ;
    END
  END hr[103]
  PIN hr[104]
    DIRECTION INPUT ;
    USE SIGNAL ;
    PORT
      LAYER M5 ;
        RECT  39.984 0 40.008 0.084 ;
    END
  END hr[104]
  PIN hr[105]
    DIRECTION INPUT ;
    USE SIGNAL ;
    PORT
      LAYER M5 ;
        RECT  40.08 0 40.104 0.084 ;
    END
  END hr[105]
  PIN hr[106]
    DIRECTION INPUT ;
    USE SIGNAL ;
    PORT
      LAYER M5 ;
        RECT  40.176 0 40.2 0.084 ;
    END
  END hr[106]
  PIN hr[107]
    DIRECTION INPUT ;
    USE SIGNAL ;
    PORT
      LAYER M5 ;
        RECT  40.272 0 40.296 0.084 ;
    END
  END hr[107]
  PIN hr[108]
    DIRECTION INPUT ;
    USE SIGNAL ;
    PORT
      LAYER M5 ;
        RECT  40.368 0 40.392 0.084 ;
    END
  END hr[108]
  PIN hr[109]
    DIRECTION INPUT ;
    USE SIGNAL ;
    PORT
      LAYER M5 ;
        RECT  40.464 0 40.488 0.084 ;
    END
  END hr[109]
  PIN hr[10]
    DIRECTION INPUT ;
    USE SIGNAL ;
    PORT
      LAYER M5 ;
        RECT  49.392 0 49.416 0.084 ;
    END
  END hr[10]
  PIN hr[110]
    DIRECTION INPUT ;
    USE SIGNAL ;
    PORT
      LAYER M5 ;
        RECT  40.56 0 40.584 0.084 ;
    END
  END hr[110]
  PIN hr[111]
    DIRECTION INPUT ;
    USE SIGNAL ;
    PORT
      LAYER M5 ;
        RECT  40.656 0 40.68 0.084 ;
    END
  END hr[111]
  PIN hr[112]
    DIRECTION INPUT ;
    USE SIGNAL ;
    PORT
      LAYER M5 ;
        RECT  40.752 0 40.776 0.084 ;
    END
  END hr[112]
  PIN hr[113]
    DIRECTION INPUT ;
    USE SIGNAL ;
    PORT
      LAYER M5 ;
        RECT  40.848 0 40.872 0.084 ;
    END
  END hr[113]
  PIN hr[114]
    DIRECTION INPUT ;
    USE SIGNAL ;
    PORT
      LAYER M5 ;
        RECT  40.944 0 40.968 0.084 ;
    END
  END hr[114]
  PIN hr[115]
    DIRECTION INPUT ;
    USE SIGNAL ;
    PORT
      LAYER M5 ;
        RECT  41.04 0 41.064 0.084 ;
    END
  END hr[115]
  PIN hr[116]
    DIRECTION INPUT ;
    USE SIGNAL ;
    PORT
      LAYER M5 ;
        RECT  41.136 0 41.16 0.084 ;
    END
  END hr[116]
  PIN hr[117]
    DIRECTION INPUT ;
    USE SIGNAL ;
    PORT
      LAYER M5 ;
        RECT  41.232 0 41.256 0.084 ;
    END
  END hr[117]
  PIN hr[118]
    DIRECTION INPUT ;
    USE SIGNAL ;
    PORT
      LAYER M5 ;
        RECT  41.328 0 41.352 0.084 ;
    END
  END hr[118]
  PIN hr[119]
    DIRECTION INPUT ;
    USE SIGNAL ;
    PORT
      LAYER M5 ;
        RECT  41.424 0 41.448 0.084 ;
    END
  END hr[119]
  PIN hr[11]
    DIRECTION INPUT ;
    USE SIGNAL ;
    PORT
      LAYER M5 ;
        RECT  49.488 0 49.512 0.084 ;
    END
  END hr[11]
  PIN hr[120]
    DIRECTION INPUT ;
    USE SIGNAL ;
    PORT
      LAYER M5 ;
        RECT  41.52 0 41.544 0.084 ;
    END
  END hr[120]
  PIN hr[121]
    DIRECTION INPUT ;
    USE SIGNAL ;
    PORT
      LAYER M5 ;
        RECT  41.616 0 41.64 0.084 ;
    END
  END hr[121]
  PIN hr[122]
    DIRECTION INPUT ;
    USE SIGNAL ;
    PORT
      LAYER M5 ;
        RECT  41.712 0 41.736 0.084 ;
    END
  END hr[122]
  PIN hr[123]
    DIRECTION INPUT ;
    USE SIGNAL ;
    PORT
      LAYER M5 ;
        RECT  41.808 0 41.832 0.084 ;
    END
  END hr[123]
  PIN hr[124]
    DIRECTION INPUT ;
    USE SIGNAL ;
    PORT
      LAYER M5 ;
        RECT  41.904 0 41.928 0.084 ;
    END
  END hr[124]
  PIN hr[125]
    DIRECTION INPUT ;
    USE SIGNAL ;
    PORT
      LAYER M5 ;
        RECT  42 0 42.024 0.084 ;
    END
  END hr[125]
  PIN hr[126]
    DIRECTION INPUT ;
    USE SIGNAL ;
    PORT
      LAYER M5 ;
        RECT  42.096 0 42.12 0.084 ;
    END
  END hr[126]
  PIN hr[127]
    DIRECTION INPUT ;
    USE SIGNAL ;
    PORT
      LAYER M5 ;
        RECT  54.48 0 54.504 0.084 ;
    END
  END hr[127]
  PIN hr[128]
    DIRECTION INPUT ;
    USE SIGNAL ;
    PORT
      LAYER M5 ;
        RECT  54.576 0 54.6 0.084 ;
    END
  END hr[128]
  PIN hr[129]
    DIRECTION INPUT ;
    USE SIGNAL ;
    PORT
      LAYER M5 ;
        RECT  54.672 0 54.696 0.084 ;
    END
  END hr[129]
  PIN hr[12]
    DIRECTION INPUT ;
    USE SIGNAL ;
    PORT
      LAYER M5 ;
        RECT  49.584 0 49.608 0.084 ;
    END
  END hr[12]
  PIN hr[130]
    DIRECTION INPUT ;
    USE SIGNAL ;
    PORT
      LAYER M5 ;
        RECT  54.768 0 54.792 0.084 ;
    END
  END hr[130]
  PIN hr[131]
    DIRECTION INPUT ;
    USE SIGNAL ;
    PORT
      LAYER M5 ;
        RECT  54.864 0 54.888 0.084 ;
    END
  END hr[131]
  PIN hr[132]
    DIRECTION INPUT ;
    USE SIGNAL ;
    PORT
      LAYER M5 ;
        RECT  54.96 0 54.984 0.084 ;
    END
  END hr[132]
  PIN hr[133]
    DIRECTION INPUT ;
    USE SIGNAL ;
    PORT
      LAYER M5 ;
        RECT  55.056 0 55.08 0.084 ;
    END
  END hr[133]
  PIN hr[134]
    DIRECTION INPUT ;
    USE SIGNAL ;
    PORT
      LAYER M5 ;
        RECT  55.152 0 55.176 0.084 ;
    END
  END hr[134]
  PIN hr[135]
    DIRECTION INPUT ;
    USE SIGNAL ;
    PORT
      LAYER M5 ;
        RECT  55.248 0 55.272 0.084 ;
    END
  END hr[135]
  PIN hr[136]
    DIRECTION INPUT ;
    USE SIGNAL ;
    PORT
      LAYER M5 ;
        RECT  55.344 0 55.368 0.084 ;
    END
  END hr[136]
  PIN hr[137]
    DIRECTION INPUT ;
    USE SIGNAL ;
    PORT
      LAYER M5 ;
        RECT  55.44 0 55.464 0.084 ;
    END
  END hr[137]
  PIN hr[138]
    DIRECTION INPUT ;
    USE SIGNAL ;
    PORT
      LAYER M5 ;
        RECT  55.536 0 55.56 0.084 ;
    END
  END hr[138]
  PIN hr[139]
    DIRECTION INPUT ;
    USE SIGNAL ;
    PORT
      LAYER M5 ;
        RECT  55.632 0 55.656 0.084 ;
    END
  END hr[139]
  PIN hr[13]
    DIRECTION INPUT ;
    USE SIGNAL ;
    PORT
      LAYER M5 ;
        RECT  49.68 0 49.704 0.084 ;
    END
  END hr[13]
  PIN hr[140]
    DIRECTION INPUT ;
    USE SIGNAL ;
    PORT
      LAYER M5 ;
        RECT  55.728 0 55.752 0.084 ;
    END
  END hr[140]
  PIN hr[141]
    DIRECTION INPUT ;
    USE SIGNAL ;
    PORT
      LAYER M5 ;
        RECT  55.824 0 55.848 0.084 ;
    END
  END hr[141]
  PIN hr[142]
    DIRECTION INPUT ;
    USE SIGNAL ;
    PORT
      LAYER M5 ;
        RECT  55.92 0 55.944 0.084 ;
    END
  END hr[142]
  PIN hr[143]
    DIRECTION INPUT ;
    USE SIGNAL ;
    PORT
      LAYER M5 ;
        RECT  56.016 0 56.04 0.084 ;
    END
  END hr[143]
  PIN hr[144]
    DIRECTION INPUT ;
    USE SIGNAL ;
    PORT
      LAYER M5 ;
        RECT  56.112 0 56.136 0.084 ;
    END
  END hr[144]
  PIN hr[145]
    DIRECTION INPUT ;
    USE SIGNAL ;
    PORT
      LAYER M5 ;
        RECT  56.208 0 56.232 0.084 ;
    END
  END hr[145]
  PIN hr[146]
    DIRECTION INPUT ;
    USE SIGNAL ;
    PORT
      LAYER M5 ;
        RECT  56.304 0 56.328 0.084 ;
    END
  END hr[146]
  PIN hr[147]
    DIRECTION INPUT ;
    USE SIGNAL ;
    PORT
      LAYER M5 ;
        RECT  56.4 0 56.424 0.084 ;
    END
  END hr[147]
  PIN hr[148]
    DIRECTION INPUT ;
    USE SIGNAL ;
    PORT
      LAYER M5 ;
        RECT  56.496 0 56.52 0.084 ;
    END
  END hr[148]
  PIN hr[149]
    DIRECTION INPUT ;
    USE SIGNAL ;
    PORT
      LAYER M5 ;
        RECT  56.592 0 56.616 0.084 ;
    END
  END hr[149]
  PIN hr[14]
    DIRECTION INPUT ;
    USE SIGNAL ;
    PORT
      LAYER M5 ;
        RECT  49.776 0 49.8 0.084 ;
    END
  END hr[14]
  PIN hr[150]
    DIRECTION INPUT ;
    USE SIGNAL ;
    PORT
      LAYER M5 ;
        RECT  56.688 0 56.712 0.084 ;
    END
  END hr[150]
  PIN hr[151]
    DIRECTION INPUT ;
    USE SIGNAL ;
    PORT
      LAYER M5 ;
        RECT  56.784 0 56.808 0.084 ;
    END
  END hr[151]
  PIN hr[152]
    DIRECTION INPUT ;
    USE SIGNAL ;
    PORT
      LAYER M5 ;
        RECT  56.88 0 56.904 0.084 ;
    END
  END hr[152]
  PIN hr[153]
    DIRECTION INPUT ;
    USE SIGNAL ;
    PORT
      LAYER M5 ;
        RECT  56.976 0 57 0.084 ;
    END
  END hr[153]
  PIN hr[154]
    DIRECTION INPUT ;
    USE SIGNAL ;
    PORT
      LAYER M5 ;
        RECT  57.072 0 57.096 0.084 ;
    END
  END hr[154]
  PIN hr[155]
    DIRECTION INPUT ;
    USE SIGNAL ;
    PORT
      LAYER M5 ;
        RECT  57.168 0 57.192 0.084 ;
    END
  END hr[155]
  PIN hr[156]
    DIRECTION INPUT ;
    USE SIGNAL ;
    PORT
      LAYER M5 ;
        RECT  57.264 0 57.288 0.084 ;
    END
  END hr[156]
  PIN hr[157]
    DIRECTION INPUT ;
    USE SIGNAL ;
    PORT
      LAYER M5 ;
        RECT  57.36 0 57.384 0.084 ;
    END
  END hr[157]
  PIN hr[158]
    DIRECTION INPUT ;
    USE SIGNAL ;
    PORT
      LAYER M5 ;
        RECT  57.456 0 57.48 0.084 ;
    END
  END hr[158]
  PIN hr[159]
    DIRECTION INPUT ;
    USE SIGNAL ;
    PORT
      LAYER M5 ;
        RECT  61.392 0 61.416 0.084 ;
    END
  END hr[159]
  PIN hr[15]
    DIRECTION INPUT ;
    USE SIGNAL ;
    PORT
      LAYER M5 ;
        RECT  49.872 0 49.896 0.084 ;
    END
  END hr[15]
  PIN hr[160]
    DIRECTION INPUT ;
    USE SIGNAL ;
    PORT
      LAYER M5 ;
        RECT  61.488 0 61.512 0.084 ;
    END
  END hr[160]
  PIN hr[161]
    DIRECTION INPUT ;
    USE SIGNAL ;
    PORT
      LAYER M5 ;
        RECT  61.584 0 61.608 0.084 ;
    END
  END hr[161]
  PIN hr[162]
    DIRECTION INPUT ;
    USE SIGNAL ;
    PORT
      LAYER M5 ;
        RECT  61.68 0 61.704 0.084 ;
    END
  END hr[162]
  PIN hr[163]
    DIRECTION INPUT ;
    USE SIGNAL ;
    PORT
      LAYER M5 ;
        RECT  61.776 0 61.8 0.084 ;
    END
  END hr[163]
  PIN hr[164]
    DIRECTION INPUT ;
    USE SIGNAL ;
    PORT
      LAYER M5 ;
        RECT  61.872 0 61.896 0.084 ;
    END
  END hr[164]
  PIN hr[165]
    DIRECTION INPUT ;
    USE SIGNAL ;
    PORT
      LAYER M5 ;
        RECT  61.968 0 61.992 0.084 ;
    END
  END hr[165]
  PIN hr[166]
    DIRECTION INPUT ;
    USE SIGNAL ;
    PORT
      LAYER M5 ;
        RECT  62.064 0 62.088 0.084 ;
    END
  END hr[166]
  PIN hr[167]
    DIRECTION INPUT ;
    USE SIGNAL ;
    PORT
      LAYER M5 ;
        RECT  62.16 0 62.184 0.084 ;
    END
  END hr[167]
  PIN hr[168]
    DIRECTION INPUT ;
    USE SIGNAL ;
    PORT
      LAYER M5 ;
        RECT  62.256 0 62.28 0.084 ;
    END
  END hr[168]
  PIN hr[169]
    DIRECTION INPUT ;
    USE SIGNAL ;
    PORT
      LAYER M5 ;
        RECT  62.352 0 62.376 0.084 ;
    END
  END hr[169]
  PIN hr[16]
    DIRECTION INPUT ;
    USE SIGNAL ;
    PORT
      LAYER M5 ;
        RECT  49.968 0 49.992 0.084 ;
    END
  END hr[16]
  PIN hr[170]
    DIRECTION INPUT ;
    USE SIGNAL ;
    PORT
      LAYER M5 ;
        RECT  62.448 0 62.472 0.084 ;
    END
  END hr[170]
  PIN hr[171]
    DIRECTION INPUT ;
    USE SIGNAL ;
    PORT
      LAYER M5 ;
        RECT  62.544 0 62.568 0.084 ;
    END
  END hr[171]
  PIN hr[172]
    DIRECTION INPUT ;
    USE SIGNAL ;
    PORT
      LAYER M5 ;
        RECT  62.64 0 62.664 0.084 ;
    END
  END hr[172]
  PIN hr[173]
    DIRECTION INPUT ;
    USE SIGNAL ;
    PORT
      LAYER M5 ;
        RECT  62.736 0 62.76 0.084 ;
    END
  END hr[173]
  PIN hr[174]
    DIRECTION INPUT ;
    USE SIGNAL ;
    PORT
      LAYER M5 ;
        RECT  62.832 0 62.856 0.084 ;
    END
  END hr[174]
  PIN hr[175]
    DIRECTION INPUT ;
    USE SIGNAL ;
    PORT
      LAYER M5 ;
        RECT  62.928 0 62.952 0.084 ;
    END
  END hr[175]
  PIN hr[176]
    DIRECTION INPUT ;
    USE SIGNAL ;
    PORT
      LAYER M5 ;
        RECT  63.024 0 63.048 0.084 ;
    END
  END hr[176]
  PIN hr[177]
    DIRECTION INPUT ;
    USE SIGNAL ;
    PORT
      LAYER M5 ;
        RECT  63.12 0 63.144 0.084 ;
    END
  END hr[177]
  PIN hr[178]
    DIRECTION INPUT ;
    USE SIGNAL ;
    PORT
      LAYER M5 ;
        RECT  63.216 0 63.24 0.084 ;
    END
  END hr[178]
  PIN hr[179]
    DIRECTION INPUT ;
    USE SIGNAL ;
    PORT
      LAYER M5 ;
        RECT  63.312 0 63.336 0.084 ;
    END
  END hr[179]
  PIN hr[17]
    DIRECTION INPUT ;
    USE SIGNAL ;
    PORT
      LAYER M5 ;
        RECT  50.064 0 50.088 0.084 ;
    END
  END hr[17]
  PIN hr[180]
    DIRECTION INPUT ;
    USE SIGNAL ;
    PORT
      LAYER M5 ;
        RECT  63.408 0 63.432 0.084 ;
    END
  END hr[180]
  PIN hr[181]
    DIRECTION INPUT ;
    USE SIGNAL ;
    PORT
      LAYER M5 ;
        RECT  63.504 0 63.528 0.084 ;
    END
  END hr[181]
  PIN hr[182]
    DIRECTION INPUT ;
    USE SIGNAL ;
    PORT
      LAYER M5 ;
        RECT  63.6 0 63.624 0.084 ;
    END
  END hr[182]
  PIN hr[183]
    DIRECTION INPUT ;
    USE SIGNAL ;
    PORT
      LAYER M5 ;
        RECT  63.696 0 63.72 0.084 ;
    END
  END hr[183]
  PIN hr[184]
    DIRECTION INPUT ;
    USE SIGNAL ;
    PORT
      LAYER M5 ;
        RECT  63.792 0 63.816 0.084 ;
    END
  END hr[184]
  PIN hr[185]
    DIRECTION INPUT ;
    USE SIGNAL ;
    PORT
      LAYER M5 ;
        RECT  63.888 0 63.912 0.084 ;
    END
  END hr[185]
  PIN hr[186]
    DIRECTION INPUT ;
    USE SIGNAL ;
    PORT
      LAYER M5 ;
        RECT  63.984 0 64.008 0.084 ;
    END
  END hr[186]
  PIN hr[187]
    DIRECTION INPUT ;
    USE SIGNAL ;
    PORT
      LAYER M5 ;
        RECT  64.08 0 64.104 0.084 ;
    END
  END hr[187]
  PIN hr[188]
    DIRECTION INPUT ;
    USE SIGNAL ;
    PORT
      LAYER M5 ;
        RECT  64.176 0 64.2 0.084 ;
    END
  END hr[188]
  PIN hr[189]
    DIRECTION INPUT ;
    USE SIGNAL ;
    PORT
      LAYER M5 ;
        RECT  64.272 0 64.296 0.084 ;
    END
  END hr[189]
  PIN hr[18]
    DIRECTION INPUT ;
    USE SIGNAL ;
    PORT
      LAYER M5 ;
        RECT  50.16 0 50.184 0.084 ;
    END
  END hr[18]
  PIN hr[190]
    DIRECTION INPUT ;
    USE SIGNAL ;
    PORT
      LAYER M5 ;
        RECT  64.368 0 64.392 0.084 ;
    END
  END hr[190]
  PIN hr[191]
    DIRECTION INPUT ;
    USE SIGNAL ;
    PORT
      LAYER M5 ;
        RECT  58.32 0 58.344 0.084 ;
    END
  END hr[191]
  PIN hr[192]
    DIRECTION INPUT ;
    USE SIGNAL ;
    PORT
      LAYER M5 ;
        RECT  58.416 0 58.44 0.084 ;
    END
  END hr[192]
  PIN hr[193]
    DIRECTION INPUT ;
    USE SIGNAL ;
    PORT
      LAYER M5 ;
        RECT  58.512 0 58.536 0.084 ;
    END
  END hr[193]
  PIN hr[194]
    DIRECTION INPUT ;
    USE SIGNAL ;
    PORT
      LAYER M5 ;
        RECT  58.608 0 58.632 0.084 ;
    END
  END hr[194]
  PIN hr[195]
    DIRECTION INPUT ;
    USE SIGNAL ;
    PORT
      LAYER M5 ;
        RECT  58.704 0 58.728 0.084 ;
    END
  END hr[195]
  PIN hr[196]
    DIRECTION INPUT ;
    USE SIGNAL ;
    PORT
      LAYER M5 ;
        RECT  58.8 0 58.824 0.084 ;
    END
  END hr[196]
  PIN hr[197]
    DIRECTION INPUT ;
    USE SIGNAL ;
    PORT
      LAYER M5 ;
        RECT  58.896 0 58.92 0.084 ;
    END
  END hr[197]
  PIN hr[198]
    DIRECTION INPUT ;
    USE SIGNAL ;
    PORT
      LAYER M5 ;
        RECT  58.992 0 59.016 0.084 ;
    END
  END hr[198]
  PIN hr[199]
    DIRECTION INPUT ;
    USE SIGNAL ;
    PORT
      LAYER M5 ;
        RECT  59.088 0 59.112 0.084 ;
    END
  END hr[199]
  PIN hr[19]
    DIRECTION INPUT ;
    USE SIGNAL ;
    PORT
      LAYER M5 ;
        RECT  50.256 0 50.28 0.084 ;
    END
  END hr[19]
  PIN hr[1]
    DIRECTION INPUT ;
    USE SIGNAL ;
    PORT
      LAYER M5 ;
        RECT  48.528 0 48.552 0.084 ;
    END
  END hr[1]
  PIN hr[200]
    DIRECTION INPUT ;
    USE SIGNAL ;
    PORT
      LAYER M5 ;
        RECT  59.184 0 59.208 0.084 ;
    END
  END hr[200]
  PIN hr[201]
    DIRECTION INPUT ;
    USE SIGNAL ;
    PORT
      LAYER M5 ;
        RECT  59.28 0 59.304 0.084 ;
    END
  END hr[201]
  PIN hr[202]
    DIRECTION INPUT ;
    USE SIGNAL ;
    PORT
      LAYER M5 ;
        RECT  59.376 0 59.4 0.084 ;
    END
  END hr[202]
  PIN hr[203]
    DIRECTION INPUT ;
    USE SIGNAL ;
    PORT
      LAYER M5 ;
        RECT  59.472 0 59.496 0.084 ;
    END
  END hr[203]
  PIN hr[204]
    DIRECTION INPUT ;
    USE SIGNAL ;
    PORT
      LAYER M5 ;
        RECT  59.568 0 59.592 0.084 ;
    END
  END hr[204]
  PIN hr[205]
    DIRECTION INPUT ;
    USE SIGNAL ;
    PORT
      LAYER M5 ;
        RECT  59.664 0 59.688 0.084 ;
    END
  END hr[205]
  PIN hr[206]
    DIRECTION INPUT ;
    USE SIGNAL ;
    PORT
      LAYER M5 ;
        RECT  59.76 0 59.784 0.084 ;
    END
  END hr[206]
  PIN hr[207]
    DIRECTION INPUT ;
    USE SIGNAL ;
    PORT
      LAYER M5 ;
        RECT  59.856 0 59.88 0.084 ;
    END
  END hr[207]
  PIN hr[208]
    DIRECTION INPUT ;
    USE SIGNAL ;
    PORT
      LAYER M5 ;
        RECT  59.952 0 59.976 0.084 ;
    END
  END hr[208]
  PIN hr[209]
    DIRECTION INPUT ;
    USE SIGNAL ;
    PORT
      LAYER M5 ;
        RECT  60.048 0 60.072 0.084 ;
    END
  END hr[209]
  PIN hr[20]
    DIRECTION INPUT ;
    USE SIGNAL ;
    PORT
      LAYER M5 ;
        RECT  50.352 0 50.376 0.084 ;
    END
  END hr[20]
  PIN hr[210]
    DIRECTION INPUT ;
    USE SIGNAL ;
    PORT
      LAYER M5 ;
        RECT  60.144 0 60.168 0.084 ;
    END
  END hr[210]
  PIN hr[211]
    DIRECTION INPUT ;
    USE SIGNAL ;
    PORT
      LAYER M5 ;
        RECT  60.24 0 60.264 0.084 ;
    END
  END hr[211]
  PIN hr[212]
    DIRECTION INPUT ;
    USE SIGNAL ;
    PORT
      LAYER M5 ;
        RECT  60.336 0 60.36 0.084 ;
    END
  END hr[212]
  PIN hr[213]
    DIRECTION INPUT ;
    USE SIGNAL ;
    PORT
      LAYER M5 ;
        RECT  60.432 0 60.456 0.084 ;
    END
  END hr[213]
  PIN hr[214]
    DIRECTION INPUT ;
    USE SIGNAL ;
    PORT
      LAYER M5 ;
        RECT  60.528 0 60.552 0.084 ;
    END
  END hr[214]
  PIN hr[215]
    DIRECTION INPUT ;
    USE SIGNAL ;
    PORT
      LAYER M5 ;
        RECT  60.624 0 60.648 0.084 ;
    END
  END hr[215]
  PIN hr[216]
    DIRECTION INPUT ;
    USE SIGNAL ;
    PORT
      LAYER M5 ;
        RECT  60.72 0 60.744 0.084 ;
    END
  END hr[216]
  PIN hr[217]
    DIRECTION INPUT ;
    USE SIGNAL ;
    PORT
      LAYER M5 ;
        RECT  60.816 0 60.84 0.084 ;
    END
  END hr[217]
  PIN hr[218]
    DIRECTION INPUT ;
    USE SIGNAL ;
    PORT
      LAYER M5 ;
        RECT  60.912 0 60.936 0.084 ;
    END
  END hr[218]
  PIN hr[219]
    DIRECTION INPUT ;
    USE SIGNAL ;
    PORT
      LAYER M5 ;
        RECT  61.008 0 61.032 0.084 ;
    END
  END hr[219]
  PIN hr[21]
    DIRECTION INPUT ;
    USE SIGNAL ;
    PORT
      LAYER M5 ;
        RECT  50.448 0 50.472 0.084 ;
    END
  END hr[21]
  PIN hr[220]
    DIRECTION INPUT ;
    USE SIGNAL ;
    PORT
      LAYER M5 ;
        RECT  61.104 0 61.128 0.084 ;
    END
  END hr[220]
  PIN hr[221]
    DIRECTION INPUT ;
    USE SIGNAL ;
    PORT
      LAYER M5 ;
        RECT  61.2 0 61.224 0.084 ;
    END
  END hr[221]
  PIN hr[222]
    DIRECTION INPUT ;
    USE SIGNAL ;
    PORT
      LAYER M5 ;
        RECT  61.296 0 61.32 0.084 ;
    END
  END hr[222]
  PIN hr[223]
    DIRECTION INPUT ;
    USE SIGNAL ;
    PORT
      LAYER M5 ;
        RECT  51.408 0 51.432 0.084 ;
    END
  END hr[223]
  PIN hr[224]
    DIRECTION INPUT ;
    USE SIGNAL ;
    PORT
      LAYER M5 ;
        RECT  51.504 0 51.528 0.084 ;
    END
  END hr[224]
  PIN hr[225]
    DIRECTION INPUT ;
    USE SIGNAL ;
    PORT
      LAYER M5 ;
        RECT  51.6 0 51.624 0.084 ;
    END
  END hr[225]
  PIN hr[226]
    DIRECTION INPUT ;
    USE SIGNAL ;
    PORT
      LAYER M5 ;
        RECT  51.696 0 51.72 0.084 ;
    END
  END hr[226]
  PIN hr[227]
    DIRECTION INPUT ;
    USE SIGNAL ;
    PORT
      LAYER M5 ;
        RECT  51.792 0 51.816 0.084 ;
    END
  END hr[227]
  PIN hr[228]
    DIRECTION INPUT ;
    USE SIGNAL ;
    PORT
      LAYER M5 ;
        RECT  51.888 0 51.912 0.084 ;
    END
  END hr[228]
  PIN hr[229]
    DIRECTION INPUT ;
    USE SIGNAL ;
    PORT
      LAYER M5 ;
        RECT  51.984 0 52.008 0.084 ;
    END
  END hr[229]
  PIN hr[22]
    DIRECTION INPUT ;
    USE SIGNAL ;
    PORT
      LAYER M5 ;
        RECT  50.544 0 50.568 0.084 ;
    END
  END hr[22]
  PIN hr[230]
    DIRECTION INPUT ;
    USE SIGNAL ;
    PORT
      LAYER M5 ;
        RECT  52.08 0 52.104 0.084 ;
    END
  END hr[230]
  PIN hr[231]
    DIRECTION INPUT ;
    USE SIGNAL ;
    PORT
      LAYER M5 ;
        RECT  52.176 0 52.2 0.084 ;
    END
  END hr[231]
  PIN hr[232]
    DIRECTION INPUT ;
    USE SIGNAL ;
    PORT
      LAYER M5 ;
        RECT  52.272 0 52.296 0.084 ;
    END
  END hr[232]
  PIN hr[233]
    DIRECTION INPUT ;
    USE SIGNAL ;
    PORT
      LAYER M5 ;
        RECT  52.368 0 52.392 0.084 ;
    END
  END hr[233]
  PIN hr[234]
    DIRECTION INPUT ;
    USE SIGNAL ;
    PORT
      LAYER M5 ;
        RECT  52.464 0 52.488 0.084 ;
    END
  END hr[234]
  PIN hr[235]
    DIRECTION INPUT ;
    USE SIGNAL ;
    PORT
      LAYER M5 ;
        RECT  52.56 0 52.584 0.084 ;
    END
  END hr[235]
  PIN hr[236]
    DIRECTION INPUT ;
    USE SIGNAL ;
    PORT
      LAYER M5 ;
        RECT  52.656 0 52.68 0.084 ;
    END
  END hr[236]
  PIN hr[237]
    DIRECTION INPUT ;
    USE SIGNAL ;
    PORT
      LAYER M5 ;
        RECT  52.752 0 52.776 0.084 ;
    END
  END hr[237]
  PIN hr[238]
    DIRECTION INPUT ;
    USE SIGNAL ;
    PORT
      LAYER M5 ;
        RECT  52.848 0 52.872 0.084 ;
    END
  END hr[238]
  PIN hr[239]
    DIRECTION INPUT ;
    USE SIGNAL ;
    PORT
      LAYER M5 ;
        RECT  52.944 0 52.968 0.084 ;
    END
  END hr[239]
  PIN hr[23]
    DIRECTION INPUT ;
    USE SIGNAL ;
    PORT
      LAYER M5 ;
        RECT  50.64 0 50.664 0.084 ;
    END
  END hr[23]
  PIN hr[240]
    DIRECTION INPUT ;
    USE SIGNAL ;
    PORT
      LAYER M5 ;
        RECT  53.04 0 53.064 0.084 ;
    END
  END hr[240]
  PIN hr[241]
    DIRECTION INPUT ;
    USE SIGNAL ;
    PORT
      LAYER M5 ;
        RECT  53.136 0 53.16 0.084 ;
    END
  END hr[241]
  PIN hr[242]
    DIRECTION INPUT ;
    USE SIGNAL ;
    PORT
      LAYER M5 ;
        RECT  53.232 0 53.256 0.084 ;
    END
  END hr[242]
  PIN hr[243]
    DIRECTION INPUT ;
    USE SIGNAL ;
    PORT
      LAYER M5 ;
        RECT  53.328 0 53.352 0.084 ;
    END
  END hr[243]
  PIN hr[244]
    DIRECTION INPUT ;
    USE SIGNAL ;
    PORT
      LAYER M5 ;
        RECT  53.424 0 53.448 0.084 ;
    END
  END hr[244]
  PIN hr[245]
    DIRECTION INPUT ;
    USE SIGNAL ;
    PORT
      LAYER M5 ;
        RECT  53.52 0 53.544 0.084 ;
    END
  END hr[245]
  PIN hr[246]
    DIRECTION INPUT ;
    USE SIGNAL ;
    PORT
      LAYER M5 ;
        RECT  53.616 0 53.64 0.084 ;
    END
  END hr[246]
  PIN hr[247]
    DIRECTION INPUT ;
    USE SIGNAL ;
    PORT
      LAYER M5 ;
        RECT  53.712 0 53.736 0.084 ;
    END
  END hr[247]
  PIN hr[248]
    DIRECTION INPUT ;
    USE SIGNAL ;
    PORT
      LAYER M5 ;
        RECT  53.808 0 53.832 0.084 ;
    END
  END hr[248]
  PIN hr[249]
    DIRECTION INPUT ;
    USE SIGNAL ;
    PORT
      LAYER M5 ;
        RECT  53.904 0 53.928 0.084 ;
    END
  END hr[249]
  PIN hr[24]
    DIRECTION INPUT ;
    USE SIGNAL ;
    PORT
      LAYER M5 ;
        RECT  50.736 0 50.76 0.084 ;
    END
  END hr[24]
  PIN hr[250]
    DIRECTION INPUT ;
    USE SIGNAL ;
    PORT
      LAYER M5 ;
        RECT  54 0 54.024 0.084 ;
    END
  END hr[250]
  PIN hr[251]
    DIRECTION INPUT ;
    USE SIGNAL ;
    PORT
      LAYER M5 ;
        RECT  54.096 0 54.12 0.084 ;
    END
  END hr[251]
  PIN hr[252]
    DIRECTION INPUT ;
    USE SIGNAL ;
    PORT
      LAYER M5 ;
        RECT  54.192 0 54.216 0.084 ;
    END
  END hr[252]
  PIN hr[253]
    DIRECTION INPUT ;
    USE SIGNAL ;
    PORT
      LAYER M5 ;
        RECT  54.288 0 54.312 0.084 ;
    END
  END hr[253]
  PIN hr[254]
    DIRECTION INPUT ;
    USE SIGNAL ;
    PORT
      LAYER M5 ;
        RECT  54.384 0 54.408 0.084 ;
    END
  END hr[254]
  PIN hr[255]
    DIRECTION INPUT ;
    USE SIGNAL ;
    PORT
      LAYER M5 ;
        RECT  45.264 0 45.288 0.084 ;
    END
  END hr[255]
  PIN hr[256]
    DIRECTION INPUT ;
    USE SIGNAL ;
    PORT
      LAYER M5 ;
        RECT  45.36 0 45.384 0.084 ;
    END
  END hr[256]
  PIN hr[257]
    DIRECTION INPUT ;
    USE SIGNAL ;
    PORT
      LAYER M5 ;
        RECT  45.456 0 45.48 0.084 ;
    END
  END hr[257]
  PIN hr[258]
    DIRECTION INPUT ;
    USE SIGNAL ;
    PORT
      LAYER M5 ;
        RECT  45.552 0 45.576 0.084 ;
    END
  END hr[258]
  PIN hr[259]
    DIRECTION INPUT ;
    USE SIGNAL ;
    PORT
      LAYER M5 ;
        RECT  45.648 0 45.672 0.084 ;
    END
  END hr[259]
  PIN hr[25]
    DIRECTION INPUT ;
    USE SIGNAL ;
    PORT
      LAYER M5 ;
        RECT  50.832 0 50.856 0.084 ;
    END
  END hr[25]
  PIN hr[260]
    DIRECTION INPUT ;
    USE SIGNAL ;
    PORT
      LAYER M5 ;
        RECT  45.744 0 45.768 0.084 ;
    END
  END hr[260]
  PIN hr[261]
    DIRECTION INPUT ;
    USE SIGNAL ;
    PORT
      LAYER M5 ;
        RECT  45.84 0 45.864 0.084 ;
    END
  END hr[261]
  PIN hr[262]
    DIRECTION INPUT ;
    USE SIGNAL ;
    PORT
      LAYER M5 ;
        RECT  45.936 0 45.96 0.084 ;
    END
  END hr[262]
  PIN hr[263]
    DIRECTION INPUT ;
    USE SIGNAL ;
    PORT
      LAYER M5 ;
        RECT  46.032 0 46.056 0.084 ;
    END
  END hr[263]
  PIN hr[264]
    DIRECTION INPUT ;
    USE SIGNAL ;
    PORT
      LAYER M5 ;
        RECT  46.128 0 46.152 0.084 ;
    END
  END hr[264]
  PIN hr[265]
    DIRECTION INPUT ;
    USE SIGNAL ;
    PORT
      LAYER M5 ;
        RECT  46.224 0 46.248 0.084 ;
    END
  END hr[265]
  PIN hr[266]
    DIRECTION INPUT ;
    USE SIGNAL ;
    PORT
      LAYER M5 ;
        RECT  46.32 0 46.344 0.084 ;
    END
  END hr[266]
  PIN hr[267]
    DIRECTION INPUT ;
    USE SIGNAL ;
    PORT
      LAYER M5 ;
        RECT  46.416 0 46.44 0.084 ;
    END
  END hr[267]
  PIN hr[268]
    DIRECTION INPUT ;
    USE SIGNAL ;
    PORT
      LAYER M5 ;
        RECT  46.512 0 46.536 0.084 ;
    END
  END hr[268]
  PIN hr[269]
    DIRECTION INPUT ;
    USE SIGNAL ;
    PORT
      LAYER M5 ;
        RECT  46.608 0 46.632 0.084 ;
    END
  END hr[269]
  PIN hr[26]
    DIRECTION INPUT ;
    USE SIGNAL ;
    PORT
      LAYER M5 ;
        RECT  50.928 0 50.952 0.084 ;
    END
  END hr[26]
  PIN hr[270]
    DIRECTION INPUT ;
    USE SIGNAL ;
    PORT
      LAYER M5 ;
        RECT  46.704 0 46.728 0.084 ;
    END
  END hr[270]
  PIN hr[271]
    DIRECTION INPUT ;
    USE SIGNAL ;
    PORT
      LAYER M5 ;
        RECT  46.8 0 46.824 0.084 ;
    END
  END hr[271]
  PIN hr[272]
    DIRECTION INPUT ;
    USE SIGNAL ;
    PORT
      LAYER M5 ;
        RECT  46.896 0 46.92 0.084 ;
    END
  END hr[272]
  PIN hr[273]
    DIRECTION INPUT ;
    USE SIGNAL ;
    PORT
      LAYER M5 ;
        RECT  46.992 0 47.016 0.084 ;
    END
  END hr[273]
  PIN hr[27]
    DIRECTION INPUT ;
    USE SIGNAL ;
    PORT
      LAYER M5 ;
        RECT  51.024 0 51.048 0.084 ;
    END
  END hr[27]
  PIN hr[28]
    DIRECTION INPUT ;
    USE SIGNAL ;
    PORT
      LAYER M5 ;
        RECT  51.12 0 51.144 0.084 ;
    END
  END hr[28]
  PIN hr[29]
    DIRECTION INPUT ;
    USE SIGNAL ;
    PORT
      LAYER M5 ;
        RECT  51.216 0 51.24 0.084 ;
    END
  END hr[29]
  PIN hr[2]
    DIRECTION INPUT ;
    USE SIGNAL ;
    PORT
      LAYER M5 ;
        RECT  48.624 0 48.648 0.084 ;
    END
  END hr[2]
  PIN hr[30]
    DIRECTION INPUT ;
    USE SIGNAL ;
    PORT
      LAYER M5 ;
        RECT  51.312 0 51.336 0.084 ;
    END
  END hr[30]
  PIN hr[31]
    DIRECTION INPUT ;
    USE SIGNAL ;
    PORT
      LAYER M5 ;
        RECT  42.192 0 42.216 0.084 ;
    END
  END hr[31]
  PIN hr[32]
    DIRECTION INPUT ;
    USE SIGNAL ;
    PORT
      LAYER M5 ;
        RECT  42.288 0 42.312 0.084 ;
    END
  END hr[32]
  PIN hr[33]
    DIRECTION INPUT ;
    USE SIGNAL ;
    PORT
      LAYER M5 ;
        RECT  42.384 0 42.408 0.084 ;
    END
  END hr[33]
  PIN hr[34]
    DIRECTION INPUT ;
    USE SIGNAL ;
    PORT
      LAYER M5 ;
        RECT  42.48 0 42.504 0.084 ;
    END
  END hr[34]
  PIN hr[35]
    DIRECTION INPUT ;
    USE SIGNAL ;
    PORT
      LAYER M5 ;
        RECT  42.576 0 42.6 0.084 ;
    END
  END hr[35]
  PIN hr[36]
    DIRECTION INPUT ;
    USE SIGNAL ;
    PORT
      LAYER M5 ;
        RECT  42.672 0 42.696 0.084 ;
    END
  END hr[36]
  PIN hr[37]
    DIRECTION INPUT ;
    USE SIGNAL ;
    PORT
      LAYER M5 ;
        RECT  42.768 0 42.792 0.084 ;
    END
  END hr[37]
  PIN hr[38]
    DIRECTION INPUT ;
    USE SIGNAL ;
    PORT
      LAYER M5 ;
        RECT  42.864 0 42.888 0.084 ;
    END
  END hr[38]
  PIN hr[39]
    DIRECTION INPUT ;
    USE SIGNAL ;
    PORT
      LAYER M5 ;
        RECT  42.96 0 42.984 0.084 ;
    END
  END hr[39]
  PIN hr[3]
    DIRECTION INPUT ;
    USE SIGNAL ;
    PORT
      LAYER M5 ;
        RECT  48.72 0 48.744 0.084 ;
    END
  END hr[3]
  PIN hr[40]
    DIRECTION INPUT ;
    USE SIGNAL ;
    PORT
      LAYER M5 ;
        RECT  43.056 0 43.08 0.084 ;
    END
  END hr[40]
  PIN hr[41]
    DIRECTION INPUT ;
    USE SIGNAL ;
    PORT
      LAYER M5 ;
        RECT  43.152 0 43.176 0.084 ;
    END
  END hr[41]
  PIN hr[42]
    DIRECTION INPUT ;
    USE SIGNAL ;
    PORT
      LAYER M5 ;
        RECT  43.248 0 43.272 0.084 ;
    END
  END hr[42]
  PIN hr[43]
    DIRECTION INPUT ;
    USE SIGNAL ;
    PORT
      LAYER M5 ;
        RECT  43.344 0 43.368 0.084 ;
    END
  END hr[43]
  PIN hr[44]
    DIRECTION INPUT ;
    USE SIGNAL ;
    PORT
      LAYER M5 ;
        RECT  43.44 0 43.464 0.084 ;
    END
  END hr[44]
  PIN hr[45]
    DIRECTION INPUT ;
    USE SIGNAL ;
    PORT
      LAYER M5 ;
        RECT  43.536 0 43.56 0.084 ;
    END
  END hr[45]
  PIN hr[46]
    DIRECTION INPUT ;
    USE SIGNAL ;
    PORT
      LAYER M5 ;
        RECT  43.632 0 43.656 0.084 ;
    END
  END hr[46]
  PIN hr[47]
    DIRECTION INPUT ;
    USE SIGNAL ;
    PORT
      LAYER M5 ;
        RECT  43.728 0 43.752 0.084 ;
    END
  END hr[47]
  PIN hr[48]
    DIRECTION INPUT ;
    USE SIGNAL ;
    PORT
      LAYER M5 ;
        RECT  43.824 0 43.848 0.084 ;
    END
  END hr[48]
  PIN hr[49]
    DIRECTION INPUT ;
    USE SIGNAL ;
    PORT
      LAYER M5 ;
        RECT  43.92 0 43.944 0.084 ;
    END
  END hr[49]
  PIN hr[4]
    DIRECTION INPUT ;
    USE SIGNAL ;
    PORT
      LAYER M5 ;
        RECT  48.816 0 48.84 0.084 ;
    END
  END hr[4]
  PIN hr[50]
    DIRECTION INPUT ;
    USE SIGNAL ;
    PORT
      LAYER M5 ;
        RECT  44.016 0 44.04 0.084 ;
    END
  END hr[50]
  PIN hr[51]
    DIRECTION INPUT ;
    USE SIGNAL ;
    PORT
      LAYER M5 ;
        RECT  44.112 0 44.136 0.084 ;
    END
  END hr[51]
  PIN hr[52]
    DIRECTION INPUT ;
    USE SIGNAL ;
    PORT
      LAYER M5 ;
        RECT  44.208 0 44.232 0.084 ;
    END
  END hr[52]
  PIN hr[53]
    DIRECTION INPUT ;
    USE SIGNAL ;
    PORT
      LAYER M5 ;
        RECT  44.304 0 44.328 0.084 ;
    END
  END hr[53]
  PIN hr[54]
    DIRECTION INPUT ;
    USE SIGNAL ;
    PORT
      LAYER M5 ;
        RECT  44.4 0 44.424 0.084 ;
    END
  END hr[54]
  PIN hr[55]
    DIRECTION INPUT ;
    USE SIGNAL ;
    PORT
      LAYER M5 ;
        RECT  44.496 0 44.52 0.084 ;
    END
  END hr[55]
  PIN hr[56]
    DIRECTION INPUT ;
    USE SIGNAL ;
    PORT
      LAYER M5 ;
        RECT  44.592 0 44.616 0.084 ;
    END
  END hr[56]
  PIN hr[57]
    DIRECTION INPUT ;
    USE SIGNAL ;
    PORT
      LAYER M5 ;
        RECT  44.688 0 44.712 0.084 ;
    END
  END hr[57]
  PIN hr[58]
    DIRECTION INPUT ;
    USE SIGNAL ;
    PORT
      LAYER M5 ;
        RECT  44.784 0 44.808 0.084 ;
    END
  END hr[58]
  PIN hr[59]
    DIRECTION INPUT ;
    USE SIGNAL ;
    PORT
      LAYER M5 ;
        RECT  44.88 0 44.904 0.084 ;
    END
  END hr[59]
  PIN hr[5]
    DIRECTION INPUT ;
    USE SIGNAL ;
    PORT
      LAYER M5 ;
        RECT  48.912 0 48.936 0.084 ;
    END
  END hr[5]
  PIN hr[60]
    DIRECTION INPUT ;
    USE SIGNAL ;
    PORT
      LAYER M5 ;
        RECT  44.976 0 45 0.084 ;
    END
  END hr[60]
  PIN hr[61]
    DIRECTION INPUT ;
    USE SIGNAL ;
    PORT
      LAYER M5 ;
        RECT  45.072 0 45.096 0.084 ;
    END
  END hr[61]
  PIN hr[62]
    DIRECTION INPUT ;
    USE SIGNAL ;
    PORT
      LAYER M5 ;
        RECT  45.168 0 45.192 0.084 ;
    END
  END hr[62]
  PIN hr[63]
    DIRECTION INPUT ;
    USE SIGNAL ;
    PORT
      LAYER M5 ;
        RECT  32.208 0 32.232 0.084 ;
    END
  END hr[63]
  PIN hr[64]
    DIRECTION INPUT ;
    USE SIGNAL ;
    PORT
      LAYER M5 ;
        RECT  32.304 0 32.328 0.084 ;
    END
  END hr[64]
  PIN hr[65]
    DIRECTION INPUT ;
    USE SIGNAL ;
    PORT
      LAYER M5 ;
        RECT  32.4 0 32.424 0.084 ;
    END
  END hr[65]
  PIN hr[66]
    DIRECTION INPUT ;
    USE SIGNAL ;
    PORT
      LAYER M5 ;
        RECT  32.496 0 32.52 0.084 ;
    END
  END hr[66]
  PIN hr[67]
    DIRECTION INPUT ;
    USE SIGNAL ;
    PORT
      LAYER M5 ;
        RECT  32.592 0 32.616 0.084 ;
    END
  END hr[67]
  PIN hr[68]
    DIRECTION INPUT ;
    USE SIGNAL ;
    PORT
      LAYER M5 ;
        RECT  32.688 0 32.712 0.084 ;
    END
  END hr[68]
  PIN hr[69]
    DIRECTION INPUT ;
    USE SIGNAL ;
    PORT
      LAYER M5 ;
        RECT  32.784 0 32.808 0.084 ;
    END
  END hr[69]
  PIN hr[6]
    DIRECTION INPUT ;
    USE SIGNAL ;
    PORT
      LAYER M5 ;
        RECT  49.008 0 49.032 0.084 ;
    END
  END hr[6]
  PIN hr[70]
    DIRECTION INPUT ;
    USE SIGNAL ;
    PORT
      LAYER M5 ;
        RECT  32.88 0 32.904 0.084 ;
    END
  END hr[70]
  PIN hr[71]
    DIRECTION INPUT ;
    USE SIGNAL ;
    PORT
      LAYER M5 ;
        RECT  32.976 0 33 0.084 ;
    END
  END hr[71]
  PIN hr[72]
    DIRECTION INPUT ;
    USE SIGNAL ;
    PORT
      LAYER M5 ;
        RECT  33.072 0 33.096 0.084 ;
    END
  END hr[72]
  PIN hr[73]
    DIRECTION INPUT ;
    USE SIGNAL ;
    PORT
      LAYER M5 ;
        RECT  33.168 0 33.192 0.084 ;
    END
  END hr[73]
  PIN hr[74]
    DIRECTION INPUT ;
    USE SIGNAL ;
    PORT
      LAYER M5 ;
        RECT  33.264 0 33.288 0.084 ;
    END
  END hr[74]
  PIN hr[75]
    DIRECTION INPUT ;
    USE SIGNAL ;
    PORT
      LAYER M5 ;
        RECT  33.36 0 33.384 0.084 ;
    END
  END hr[75]
  PIN hr[76]
    DIRECTION INPUT ;
    USE SIGNAL ;
    PORT
      LAYER M5 ;
        RECT  33.456 0 33.48 0.084 ;
    END
  END hr[76]
  PIN hr[77]
    DIRECTION INPUT ;
    USE SIGNAL ;
    PORT
      LAYER M5 ;
        RECT  33.552 0 33.576 0.084 ;
    END
  END hr[77]
  PIN hr[78]
    DIRECTION INPUT ;
    USE SIGNAL ;
    PORT
      LAYER M5 ;
        RECT  33.648 0 33.672 0.084 ;
    END
  END hr[78]
  PIN hr[79]
    DIRECTION INPUT ;
    USE SIGNAL ;
    PORT
      LAYER M5 ;
        RECT  33.744 0 33.768 0.084 ;
    END
  END hr[79]
  PIN hr[7]
    DIRECTION INPUT ;
    USE SIGNAL ;
    PORT
      LAYER M5 ;
        RECT  49.104 0 49.128 0.084 ;
    END
  END hr[7]
  PIN hr[80]
    DIRECTION INPUT ;
    USE SIGNAL ;
    PORT
      LAYER M5 ;
        RECT  33.84 0 33.864 0.084 ;
    END
  END hr[80]
  PIN hr[81]
    DIRECTION INPUT ;
    USE SIGNAL ;
    PORT
      LAYER M5 ;
        RECT  33.936 0 33.96 0.084 ;
    END
  END hr[81]
  PIN hr[82]
    DIRECTION INPUT ;
    USE SIGNAL ;
    PORT
      LAYER M5 ;
        RECT  34.032 0 34.056 0.084 ;
    END
  END hr[82]
  PIN hr[83]
    DIRECTION INPUT ;
    USE SIGNAL ;
    PORT
      LAYER M5 ;
        RECT  34.128 0 34.152 0.084 ;
    END
  END hr[83]
  PIN hr[84]
    DIRECTION INPUT ;
    USE SIGNAL ;
    PORT
      LAYER M5 ;
        RECT  34.224 0 34.248 0.084 ;
    END
  END hr[84]
  PIN hr[85]
    DIRECTION INPUT ;
    USE SIGNAL ;
    PORT
      LAYER M5 ;
        RECT  34.32 0 34.344 0.084 ;
    END
  END hr[85]
  PIN hr[86]
    DIRECTION INPUT ;
    USE SIGNAL ;
    PORT
      LAYER M5 ;
        RECT  34.416 0 34.44 0.084 ;
    END
  END hr[86]
  PIN hr[87]
    DIRECTION INPUT ;
    USE SIGNAL ;
    PORT
      LAYER M5 ;
        RECT  34.512 0 34.536 0.084 ;
    END
  END hr[87]
  PIN hr[88]
    DIRECTION INPUT ;
    USE SIGNAL ;
    PORT
      LAYER M5 ;
        RECT  34.608 0 34.632 0.084 ;
    END
  END hr[88]
  PIN hr[89]
    DIRECTION INPUT ;
    USE SIGNAL ;
    PORT
      LAYER M5 ;
        RECT  34.704 0 34.728 0.084 ;
    END
  END hr[89]
  PIN hr[8]
    DIRECTION INPUT ;
    USE SIGNAL ;
    PORT
      LAYER M5 ;
        RECT  49.2 0 49.224 0.084 ;
    END
  END hr[8]
  PIN hr[90]
    DIRECTION INPUT ;
    USE SIGNAL ;
    PORT
      LAYER M5 ;
        RECT  34.8 0 34.824 0.084 ;
    END
  END hr[90]
  PIN hr[91]
    DIRECTION INPUT ;
    USE SIGNAL ;
    PORT
      LAYER M5 ;
        RECT  34.896 0 34.92 0.084 ;
    END
  END hr[91]
  PIN hr[92]
    DIRECTION INPUT ;
    USE SIGNAL ;
    PORT
      LAYER M5 ;
        RECT  34.992 0 35.016 0.084 ;
    END
  END hr[92]
  PIN hr[93]
    DIRECTION INPUT ;
    USE SIGNAL ;
    PORT
      LAYER M5 ;
        RECT  35.088 0 35.112 0.084 ;
    END
  END hr[93]
  PIN hr[94]
    DIRECTION INPUT ;
    USE SIGNAL ;
    PORT
      LAYER M5 ;
        RECT  35.184 0 35.208 0.084 ;
    END
  END hr[94]
  PIN hr[95]
    DIRECTION INPUT ;
    USE SIGNAL ;
    PORT
      LAYER M5 ;
        RECT  39.12 0 39.144 0.084 ;
    END
  END hr[95]
  PIN hr[96]
    DIRECTION INPUT ;
    USE SIGNAL ;
    PORT
      LAYER M5 ;
        RECT  39.216 0 39.24 0.084 ;
    END
  END hr[96]
  PIN hr[97]
    DIRECTION INPUT ;
    USE SIGNAL ;
    PORT
      LAYER M5 ;
        RECT  39.312 0 39.336 0.084 ;
    END
  END hr[97]
  PIN hr[98]
    DIRECTION INPUT ;
    USE SIGNAL ;
    PORT
      LAYER M5 ;
        RECT  39.408 0 39.432 0.084 ;
    END
  END hr[98]
  PIN hr[99]
    DIRECTION INPUT ;
    USE SIGNAL ;
    PORT
      LAYER M5 ;
        RECT  39.504 0 39.528 0.084 ;
    END
  END hr[99]
  PIN hr[9]
    DIRECTION INPUT ;
    USE SIGNAL ;
    PORT
      LAYER M5 ;
        RECT  49.296 0 49.32 0.084 ;
    END
  END hr[9]
  PIN rce0[0]
    DIRECTION INPUT ;
    USE SIGNAL ;
    PORT
      LAYER M6 ;
        RECT  0 41.408 0.069 41.44 ;
    END
  END rce0[0]
  PIN rce0[100]
    DIRECTION INPUT ;
    USE SIGNAL ;
    PORT
      LAYER M4 ;
        RECT  0 2.928 0.084 2.952 ;
    END
  END rce0[100]
  PIN rce0[101]
    DIRECTION INPUT ;
    USE SIGNAL ;
    PORT
      LAYER M4 ;
        RECT  0 3.024 0.084 3.048 ;
    END
  END rce0[101]
  PIN rce0[102]
    DIRECTION INPUT ;
    USE SIGNAL ;
    PORT
      LAYER M4 ;
        RECT  0 3.12 0.084 3.144 ;
    END
  END rce0[102]
  PIN rce0[103]
    DIRECTION INPUT ;
    USE SIGNAL ;
    PORT
      LAYER M4 ;
        RECT  0 3.216 0.084 3.24 ;
    END
  END rce0[103]
  PIN rce0[104]
    DIRECTION INPUT ;
    USE SIGNAL ;
    PORT
      LAYER M4 ;
        RECT  0 3.312 0.084 3.336 ;
    END
  END rce0[104]
  PIN rce0[105]
    DIRECTION INPUT ;
    USE SIGNAL ;
    PORT
      LAYER M4 ;
        RECT  0 3.408 0.084 3.432 ;
    END
  END rce0[105]
  PIN rce0[106]
    DIRECTION INPUT ;
    USE SIGNAL ;
    PORT
      LAYER M4 ;
        RECT  0 3.504 0.084 3.528 ;
    END
  END rce0[106]
  PIN rce0[107]
    DIRECTION INPUT ;
    USE SIGNAL ;
    PORT
      LAYER M4 ;
        RECT  0 3.6 0.084 3.624 ;
    END
  END rce0[107]
  PIN rce0[108]
    DIRECTION INPUT ;
    USE SIGNAL ;
    PORT
      LAYER M4 ;
        RECT  0 3.696 0.084 3.72 ;
    END
  END rce0[108]
  PIN rce0[109]
    DIRECTION INPUT ;
    USE SIGNAL ;
    PORT
      LAYER M4 ;
        RECT  0 3.792 0.084 3.816 ;
    END
  END rce0[109]
  PIN rce0[10]
    DIRECTION INPUT ;
    USE SIGNAL ;
    PORT
      LAYER M6 ;
        RECT  0 42.688 0.069 42.72 ;
    END
  END rce0[10]
  PIN rce0[110]
    DIRECTION INPUT ;
    USE SIGNAL ;
    PORT
      LAYER M4 ;
        RECT  0 3.888 0.084 3.912 ;
    END
  END rce0[110]
  PIN rce0[111]
    DIRECTION INPUT ;
    USE SIGNAL ;
    PORT
      LAYER M4 ;
        RECT  0 3.984 0.084 4.008 ;
    END
  END rce0[111]
  PIN rce0[112]
    DIRECTION INPUT ;
    USE SIGNAL ;
    PORT
      LAYER M4 ;
        RECT  0 4.08 0.084 4.104 ;
    END
  END rce0[112]
  PIN rce0[113]
    DIRECTION INPUT ;
    USE SIGNAL ;
    PORT
      LAYER M4 ;
        RECT  0 4.176 0.084 4.2 ;
    END
  END rce0[113]
  PIN rce0[114]
    DIRECTION INPUT ;
    USE SIGNAL ;
    PORT
      LAYER M4 ;
        RECT  0 4.272 0.084 4.296 ;
    END
  END rce0[114]
  PIN rce0[115]
    DIRECTION INPUT ;
    USE SIGNAL ;
    PORT
      LAYER M4 ;
        RECT  0 4.368 0.084 4.392 ;
    END
  END rce0[115]
  PIN rce0[116]
    DIRECTION INPUT ;
    USE SIGNAL ;
    PORT
      LAYER M4 ;
        RECT  0 4.464 0.084 4.488 ;
    END
  END rce0[116]
  PIN rce0[117]
    DIRECTION INPUT ;
    USE SIGNAL ;
    PORT
      LAYER M4 ;
        RECT  0 4.56 0.084 4.584 ;
    END
  END rce0[117]
  PIN rce0[118]
    DIRECTION INPUT ;
    USE SIGNAL ;
    PORT
      LAYER M4 ;
        RECT  0 4.656 0.084 4.68 ;
    END
  END rce0[118]
  PIN rce0[119]
    DIRECTION INPUT ;
    USE SIGNAL ;
    PORT
      LAYER M4 ;
        RECT  0 4.752 0.084 4.776 ;
    END
  END rce0[119]
  PIN rce0[11]
    DIRECTION INPUT ;
    USE SIGNAL ;
    PORT
      LAYER M6 ;
        RECT  0 42.816 0.069 42.848 ;
    END
  END rce0[11]
  PIN rce0[120]
    DIRECTION INPUT ;
    USE SIGNAL ;
    PORT
      LAYER M4 ;
        RECT  0 4.848 0.084 4.872 ;
    END
  END rce0[120]
  PIN rce0[121]
    DIRECTION INPUT ;
    USE SIGNAL ;
    PORT
      LAYER M4 ;
        RECT  0 4.944 0.084 4.968 ;
    END
  END rce0[121]
  PIN rce0[122]
    DIRECTION INPUT ;
    USE SIGNAL ;
    PORT
      LAYER M4 ;
        RECT  0 5.04 0.084 5.064 ;
    END
  END rce0[122]
  PIN rce0[123]
    DIRECTION INPUT ;
    USE SIGNAL ;
    PORT
      LAYER M4 ;
        RECT  0 5.136 0.084 5.16 ;
    END
  END rce0[123]
  PIN rce0[124]
    DIRECTION INPUT ;
    USE SIGNAL ;
    PORT
      LAYER M4 ;
        RECT  0 5.232 0.084 5.256 ;
    END
  END rce0[124]
  PIN rce0[125]
    DIRECTION INPUT ;
    USE SIGNAL ;
    PORT
      LAYER M4 ;
        RECT  0 5.328 0.084 5.352 ;
    END
  END rce0[125]
  PIN rce0[126]
    DIRECTION INPUT ;
    USE SIGNAL ;
    PORT
      LAYER M4 ;
        RECT  0 5.424 0.084 5.448 ;
    END
  END rce0[126]
  PIN rce0[127]
    DIRECTION INPUT ;
    USE SIGNAL ;
    PORT
      LAYER M4 ;
        RECT  0 5.52 0.084 5.544 ;
    END
  END rce0[127]
  PIN rce0[128]
    DIRECTION INPUT ;
    USE SIGNAL ;
    PORT
      LAYER M6 ;
        RECT  0 19.904 0.069 19.936 ;
    END
  END rce0[128]
  PIN rce0[129]
    DIRECTION INPUT ;
    USE SIGNAL ;
    PORT
      LAYER M6 ;
        RECT  0 20.032 0.069 20.064 ;
    END
  END rce0[129]
  PIN rce0[12]
    DIRECTION INPUT ;
    USE SIGNAL ;
    PORT
      LAYER M6 ;
        RECT  0 42.944 0.069 42.976 ;
    END
  END rce0[12]
  PIN rce0[130]
    DIRECTION INPUT ;
    USE SIGNAL ;
    PORT
      LAYER M6 ;
        RECT  0 20.16 0.069 20.192 ;
    END
  END rce0[130]
  PIN rce0[131]
    DIRECTION INPUT ;
    USE SIGNAL ;
    PORT
      LAYER M6 ;
        RECT  0 20.288 0.069 20.32 ;
    END
  END rce0[131]
  PIN rce0[132]
    DIRECTION INPUT ;
    USE SIGNAL ;
    PORT
      LAYER M6 ;
        RECT  0 20.416 0.069 20.448 ;
    END
  END rce0[132]
  PIN rce0[133]
    DIRECTION INPUT ;
    USE SIGNAL ;
    PORT
      LAYER M6 ;
        RECT  0 20.544 0.069 20.576 ;
    END
  END rce0[133]
  PIN rce0[134]
    DIRECTION INPUT ;
    USE SIGNAL ;
    PORT
      LAYER M6 ;
        RECT  0 20.672 0.069 20.704 ;
    END
  END rce0[134]
  PIN rce0[135]
    DIRECTION INPUT ;
    USE SIGNAL ;
    PORT
      LAYER M6 ;
        RECT  0 20.8 0.069 20.832 ;
    END
  END rce0[135]
  PIN rce0[136]
    DIRECTION INPUT ;
    USE SIGNAL ;
    PORT
      LAYER M6 ;
        RECT  0 20.928 0.069 20.96 ;
    END
  END rce0[136]
  PIN rce0[137]
    DIRECTION INPUT ;
    USE SIGNAL ;
    PORT
      LAYER M6 ;
        RECT  0 21.056 0.069 21.088 ;
    END
  END rce0[137]
  PIN rce0[138]
    DIRECTION INPUT ;
    USE SIGNAL ;
    PORT
      LAYER M6 ;
        RECT  0 21.184 0.069 21.216 ;
    END
  END rce0[138]
  PIN rce0[139]
    DIRECTION INPUT ;
    USE SIGNAL ;
    PORT
      LAYER M6 ;
        RECT  0 21.312 0.069 21.344 ;
    END
  END rce0[139]
  PIN rce0[13]
    DIRECTION INPUT ;
    USE SIGNAL ;
    PORT
      LAYER M6 ;
        RECT  0 43.072 0.069 43.104 ;
    END
  END rce0[13]
  PIN rce0[140]
    DIRECTION INPUT ;
    USE SIGNAL ;
    PORT
      LAYER M6 ;
        RECT  0 21.44 0.069 21.472 ;
    END
  END rce0[140]
  PIN rce0[141]
    DIRECTION INPUT ;
    USE SIGNAL ;
    PORT
      LAYER M6 ;
        RECT  0 21.568 0.069 21.6 ;
    END
  END rce0[141]
  PIN rce0[142]
    DIRECTION INPUT ;
    USE SIGNAL ;
    PORT
      LAYER M6 ;
        RECT  0 21.696 0.069 21.728 ;
    END
  END rce0[142]
  PIN rce0[143]
    DIRECTION INPUT ;
    USE SIGNAL ;
    PORT
      LAYER M6 ;
        RECT  0 21.824 0.069 21.856 ;
    END
  END rce0[143]
  PIN rce0[144]
    DIRECTION INPUT ;
    USE SIGNAL ;
    PORT
      LAYER M6 ;
        RECT  0 21.952 0.069 21.984 ;
    END
  END rce0[144]
  PIN rce0[145]
    DIRECTION INPUT ;
    USE SIGNAL ;
    PORT
      LAYER M6 ;
        RECT  0 22.08 0.069 22.112 ;
    END
  END rce0[145]
  PIN rce0[146]
    DIRECTION INPUT ;
    USE SIGNAL ;
    PORT
      LAYER M6 ;
        RECT  0 22.208 0.069 22.24 ;
    END
  END rce0[146]
  PIN rce0[147]
    DIRECTION INPUT ;
    USE SIGNAL ;
    PORT
      LAYER M6 ;
        RECT  0 22.336 0.069 22.368 ;
    END
  END rce0[147]
  PIN rce0[148]
    DIRECTION INPUT ;
    USE SIGNAL ;
    PORT
      LAYER M6 ;
        RECT  0 22.464 0.069 22.496 ;
    END
  END rce0[148]
  PIN rce0[149]
    DIRECTION INPUT ;
    USE SIGNAL ;
    PORT
      LAYER M6 ;
        RECT  0 22.592 0.069 22.624 ;
    END
  END rce0[149]
  PIN rce0[14]
    DIRECTION INPUT ;
    USE SIGNAL ;
    PORT
      LAYER M6 ;
        RECT  0 43.2 0.069 43.232 ;
    END
  END rce0[14]
  PIN rce0[150]
    DIRECTION INPUT ;
    USE SIGNAL ;
    PORT
      LAYER M6 ;
        RECT  0 22.72 0.069 22.752 ;
    END
  END rce0[150]
  PIN rce0[151]
    DIRECTION INPUT ;
    USE SIGNAL ;
    PORT
      LAYER M6 ;
        RECT  0 22.848 0.069 22.88 ;
    END
  END rce0[151]
  PIN rce0[152]
    DIRECTION INPUT ;
    USE SIGNAL ;
    PORT
      LAYER M6 ;
        RECT  0 22.976 0.069 23.008 ;
    END
  END rce0[152]
  PIN rce0[153]
    DIRECTION INPUT ;
    USE SIGNAL ;
    PORT
      LAYER M6 ;
        RECT  0 23.104 0.069 23.136 ;
    END
  END rce0[153]
  PIN rce0[154]
    DIRECTION INPUT ;
    USE SIGNAL ;
    PORT
      LAYER M6 ;
        RECT  0 23.232 0.069 23.264 ;
    END
  END rce0[154]
  PIN rce0[155]
    DIRECTION INPUT ;
    USE SIGNAL ;
    PORT
      LAYER M6 ;
        RECT  0 23.36 0.069 23.392 ;
    END
  END rce0[155]
  PIN rce0[156]
    DIRECTION INPUT ;
    USE SIGNAL ;
    PORT
      LAYER M6 ;
        RECT  0 23.488 0.069 23.52 ;
    END
  END rce0[156]
  PIN rce0[157]
    DIRECTION INPUT ;
    USE SIGNAL ;
    PORT
      LAYER M6 ;
        RECT  0 23.616 0.069 23.648 ;
    END
  END rce0[157]
  PIN rce0[158]
    DIRECTION INPUT ;
    USE SIGNAL ;
    PORT
      LAYER M6 ;
        RECT  0 23.744 0.069 23.776 ;
    END
  END rce0[158]
  PIN rce0[159]
    DIRECTION INPUT ;
    USE SIGNAL ;
    PORT
      LAYER M6 ;
        RECT  0 23.872 0.069 23.904 ;
    END
  END rce0[159]
  PIN rce0[15]
    DIRECTION INPUT ;
    USE SIGNAL ;
    PORT
      LAYER M6 ;
        RECT  0 43.328 0.069 43.36 ;
    END
  END rce0[15]
  PIN rce0[160]
    DIRECTION INPUT ;
    USE SIGNAL ;
    PORT
      LAYER M4 ;
        RECT  0 31.728 0.084 31.752 ;
    END
  END rce0[160]
  PIN rce0[161]
    DIRECTION INPUT ;
    USE SIGNAL ;
    PORT
      LAYER M4 ;
        RECT  0 31.824 0.084 31.848 ;
    END
  END rce0[161]
  PIN rce0[162]
    DIRECTION INPUT ;
    USE SIGNAL ;
    PORT
      LAYER M4 ;
        RECT  0 31.92 0.084 31.944 ;
    END
  END rce0[162]
  PIN rce0[163]
    DIRECTION INPUT ;
    USE SIGNAL ;
    PORT
      LAYER M4 ;
        RECT  0 32.016 0.084 32.04 ;
    END
  END rce0[163]
  PIN rce0[164]
    DIRECTION INPUT ;
    USE SIGNAL ;
    PORT
      LAYER M4 ;
        RECT  0 32.112 0.084 32.136 ;
    END
  END rce0[164]
  PIN rce0[165]
    DIRECTION INPUT ;
    USE SIGNAL ;
    PORT
      LAYER M4 ;
        RECT  0 32.208 0.084 32.232 ;
    END
  END rce0[165]
  PIN rce0[166]
    DIRECTION INPUT ;
    USE SIGNAL ;
    PORT
      LAYER M4 ;
        RECT  0 32.304 0.084 32.328 ;
    END
  END rce0[166]
  PIN rce0[167]
    DIRECTION INPUT ;
    USE SIGNAL ;
    PORT
      LAYER M4 ;
        RECT  0 32.4 0.084 32.424 ;
    END
  END rce0[167]
  PIN rce0[168]
    DIRECTION INPUT ;
    USE SIGNAL ;
    PORT
      LAYER M4 ;
        RECT  0 32.496 0.084 32.52 ;
    END
  END rce0[168]
  PIN rce0[169]
    DIRECTION INPUT ;
    USE SIGNAL ;
    PORT
      LAYER M4 ;
        RECT  0 32.592 0.084 32.616 ;
    END
  END rce0[169]
  PIN rce0[16]
    DIRECTION INPUT ;
    USE SIGNAL ;
    PORT
      LAYER M6 ;
        RECT  0 43.456 0.069 43.488 ;
    END
  END rce0[16]
  PIN rce0[170]
    DIRECTION INPUT ;
    USE SIGNAL ;
    PORT
      LAYER M4 ;
        RECT  0 32.688 0.084 32.712 ;
    END
  END rce0[170]
  PIN rce0[171]
    DIRECTION INPUT ;
    USE SIGNAL ;
    PORT
      LAYER M4 ;
        RECT  0 32.784 0.084 32.808 ;
    END
  END rce0[171]
  PIN rce0[172]
    DIRECTION INPUT ;
    USE SIGNAL ;
    PORT
      LAYER M4 ;
        RECT  0 32.88 0.084 32.904 ;
    END
  END rce0[172]
  PIN rce0[173]
    DIRECTION INPUT ;
    USE SIGNAL ;
    PORT
      LAYER M4 ;
        RECT  0 32.976 0.084 33 ;
    END
  END rce0[173]
  PIN rce0[174]
    DIRECTION INPUT ;
    USE SIGNAL ;
    PORT
      LAYER M4 ;
        RECT  0 33.072 0.084 33.096 ;
    END
  END rce0[174]
  PIN rce0[175]
    DIRECTION INPUT ;
    USE SIGNAL ;
    PORT
      LAYER M4 ;
        RECT  0 33.168 0.084 33.192 ;
    END
  END rce0[175]
  PIN rce0[176]
    DIRECTION INPUT ;
    USE SIGNAL ;
    PORT
      LAYER M4 ;
        RECT  0 33.264 0.084 33.288 ;
    END
  END rce0[176]
  PIN rce0[177]
    DIRECTION INPUT ;
    USE SIGNAL ;
    PORT
      LAYER M4 ;
        RECT  0 33.36 0.084 33.384 ;
    END
  END rce0[177]
  PIN rce0[178]
    DIRECTION INPUT ;
    USE SIGNAL ;
    PORT
      LAYER M4 ;
        RECT  0 33.456 0.084 33.48 ;
    END
  END rce0[178]
  PIN rce0[179]
    DIRECTION INPUT ;
    USE SIGNAL ;
    PORT
      LAYER M4 ;
        RECT  0 33.552 0.084 33.576 ;
    END
  END rce0[179]
  PIN rce0[17]
    DIRECTION INPUT ;
    USE SIGNAL ;
    PORT
      LAYER M6 ;
        RECT  0 43.584 0.069 43.616 ;
    END
  END rce0[17]
  PIN rce0[180]
    DIRECTION INPUT ;
    USE SIGNAL ;
    PORT
      LAYER M4 ;
        RECT  0 33.648 0.084 33.672 ;
    END
  END rce0[180]
  PIN rce0[181]
    DIRECTION INPUT ;
    USE SIGNAL ;
    PORT
      LAYER M4 ;
        RECT  0 33.744 0.084 33.768 ;
    END
  END rce0[181]
  PIN rce0[182]
    DIRECTION INPUT ;
    USE SIGNAL ;
    PORT
      LAYER M4 ;
        RECT  0 33.84 0.084 33.864 ;
    END
  END rce0[182]
  PIN rce0[183]
    DIRECTION INPUT ;
    USE SIGNAL ;
    PORT
      LAYER M4 ;
        RECT  0 33.936 0.084 33.96 ;
    END
  END rce0[183]
  PIN rce0[184]
    DIRECTION INPUT ;
    USE SIGNAL ;
    PORT
      LAYER M4 ;
        RECT  0 34.032 0.084 34.056 ;
    END
  END rce0[184]
  PIN rce0[185]
    DIRECTION INPUT ;
    USE SIGNAL ;
    PORT
      LAYER M4 ;
        RECT  0 34.128 0.084 34.152 ;
    END
  END rce0[185]
  PIN rce0[186]
    DIRECTION INPUT ;
    USE SIGNAL ;
    PORT
      LAYER M4 ;
        RECT  0 34.224 0.084 34.248 ;
    END
  END rce0[186]
  PIN rce0[187]
    DIRECTION INPUT ;
    USE SIGNAL ;
    PORT
      LAYER M4 ;
        RECT  0 34.32 0.084 34.344 ;
    END
  END rce0[187]
  PIN rce0[188]
    DIRECTION INPUT ;
    USE SIGNAL ;
    PORT
      LAYER M4 ;
        RECT  0 34.416 0.084 34.44 ;
    END
  END rce0[188]
  PIN rce0[189]
    DIRECTION INPUT ;
    USE SIGNAL ;
    PORT
      LAYER M4 ;
        RECT  0 34.512 0.084 34.536 ;
    END
  END rce0[189]
  PIN rce0[18]
    DIRECTION INPUT ;
    USE SIGNAL ;
    PORT
      LAYER M6 ;
        RECT  0 43.712 0.069 43.744 ;
    END
  END rce0[18]
  PIN rce0[190]
    DIRECTION INPUT ;
    USE SIGNAL ;
    PORT
      LAYER M4 ;
        RECT  0 34.608 0.084 34.632 ;
    END
  END rce0[190]
  PIN rce0[191]
    DIRECTION INPUT ;
    USE SIGNAL ;
    PORT
      LAYER M4 ;
        RECT  0 34.704 0.084 34.728 ;
    END
  END rce0[191]
  PIN rce0[192]
    DIRECTION INPUT ;
    USE SIGNAL ;
    PORT
      LAYER M6 ;
        RECT  0 45.504 0.069 45.536 ;
    END
  END rce0[192]
  PIN rce0[193]
    DIRECTION INPUT ;
    USE SIGNAL ;
    PORT
      LAYER M6 ;
        RECT  0 45.632 0.069 45.664 ;
    END
  END rce0[193]
  PIN rce0[194]
    DIRECTION INPUT ;
    USE SIGNAL ;
    PORT
      LAYER M6 ;
        RECT  0 45.76 0.069 45.792 ;
    END
  END rce0[194]
  PIN rce0[195]
    DIRECTION INPUT ;
    USE SIGNAL ;
    PORT
      LAYER M6 ;
        RECT  0 45.888 0.069 45.92 ;
    END
  END rce0[195]
  PIN rce0[196]
    DIRECTION INPUT ;
    USE SIGNAL ;
    PORT
      LAYER M6 ;
        RECT  0 46.016 0.069 46.048 ;
    END
  END rce0[196]
  PIN rce0[197]
    DIRECTION INPUT ;
    USE SIGNAL ;
    PORT
      LAYER M6 ;
        RECT  0 46.144 0.069 46.176 ;
    END
  END rce0[197]
  PIN rce0[198]
    DIRECTION INPUT ;
    USE SIGNAL ;
    PORT
      LAYER M6 ;
        RECT  0 46.272 0.069 46.304 ;
    END
  END rce0[198]
  PIN rce0[199]
    DIRECTION INPUT ;
    USE SIGNAL ;
    PORT
      LAYER M6 ;
        RECT  0 46.4 0.069 46.432 ;
    END
  END rce0[199]
  PIN rce0[19]
    DIRECTION INPUT ;
    USE SIGNAL ;
    PORT
      LAYER M6 ;
        RECT  0 43.84 0.069 43.872 ;
    END
  END rce0[19]
  PIN rce0[1]
    DIRECTION INPUT ;
    USE SIGNAL ;
    PORT
      LAYER M6 ;
        RECT  0 41.536 0.069 41.568 ;
    END
  END rce0[1]
  PIN rce0[200]
    DIRECTION INPUT ;
    USE SIGNAL ;
    PORT
      LAYER M6 ;
        RECT  0 46.528 0.069 46.56 ;
    END
  END rce0[200]
  PIN rce0[201]
    DIRECTION INPUT ;
    USE SIGNAL ;
    PORT
      LAYER M6 ;
        RECT  0 46.656 0.069 46.688 ;
    END
  END rce0[201]
  PIN rce0[202]
    DIRECTION INPUT ;
    USE SIGNAL ;
    PORT
      LAYER M6 ;
        RECT  0 46.784 0.069 46.816 ;
    END
  END rce0[202]
  PIN rce0[203]
    DIRECTION INPUT ;
    USE SIGNAL ;
    PORT
      LAYER M6 ;
        RECT  0 46.912 0.069 46.944 ;
    END
  END rce0[203]
  PIN rce0[204]
    DIRECTION INPUT ;
    USE SIGNAL ;
    PORT
      LAYER M6 ;
        RECT  0 47.04 0.069 47.072 ;
    END
  END rce0[204]
  PIN rce0[205]
    DIRECTION INPUT ;
    USE SIGNAL ;
    PORT
      LAYER M6 ;
        RECT  0 47.168 0.069 47.2 ;
    END
  END rce0[205]
  PIN rce0[206]
    DIRECTION INPUT ;
    USE SIGNAL ;
    PORT
      LAYER M6 ;
        RECT  0 47.296 0.069 47.328 ;
    END
  END rce0[206]
  PIN rce0[207]
    DIRECTION INPUT ;
    USE SIGNAL ;
    PORT
      LAYER M6 ;
        RECT  0 47.424 0.069 47.456 ;
    END
  END rce0[207]
  PIN rce0[208]
    DIRECTION INPUT ;
    USE SIGNAL ;
    PORT
      LAYER M6 ;
        RECT  0 47.552 0.069 47.584 ;
    END
  END rce0[208]
  PIN rce0[209]
    DIRECTION INPUT ;
    USE SIGNAL ;
    PORT
      LAYER M6 ;
        RECT  0 47.68 0.069 47.712 ;
    END
  END rce0[209]
  PIN rce0[20]
    DIRECTION INPUT ;
    USE SIGNAL ;
    PORT
      LAYER M6 ;
        RECT  0 43.968 0.069 44 ;
    END
  END rce0[20]
  PIN rce0[210]
    DIRECTION INPUT ;
    USE SIGNAL ;
    PORT
      LAYER M6 ;
        RECT  0 47.808 0.069 47.84 ;
    END
  END rce0[210]
  PIN rce0[211]
    DIRECTION INPUT ;
    USE SIGNAL ;
    PORT
      LAYER M6 ;
        RECT  0 47.936 0.069 47.968 ;
    END
  END rce0[211]
  PIN rce0[212]
    DIRECTION INPUT ;
    USE SIGNAL ;
    PORT
      LAYER M6 ;
        RECT  0 48.064 0.069 48.096 ;
    END
  END rce0[212]
  PIN rce0[213]
    DIRECTION INPUT ;
    USE SIGNAL ;
    PORT
      LAYER M6 ;
        RECT  0 48.192 0.069 48.224 ;
    END
  END rce0[213]
  PIN rce0[214]
    DIRECTION INPUT ;
    USE SIGNAL ;
    PORT
      LAYER M6 ;
        RECT  0 48.32 0.069 48.352 ;
    END
  END rce0[214]
  PIN rce0[215]
    DIRECTION INPUT ;
    USE SIGNAL ;
    PORT
      LAYER M6 ;
        RECT  0 48.448 0.069 48.48 ;
    END
  END rce0[215]
  PIN rce0[216]
    DIRECTION INPUT ;
    USE SIGNAL ;
    PORT
      LAYER M6 ;
        RECT  0 48.576 0.069 48.608 ;
    END
  END rce0[216]
  PIN rce0[217]
    DIRECTION INPUT ;
    USE SIGNAL ;
    PORT
      LAYER M6 ;
        RECT  0 48.704 0.069 48.736 ;
    END
  END rce0[217]
  PIN rce0[218]
    DIRECTION INPUT ;
    USE SIGNAL ;
    PORT
      LAYER M6 ;
        RECT  0 48.832 0.069 48.864 ;
    END
  END rce0[218]
  PIN rce0[219]
    DIRECTION INPUT ;
    USE SIGNAL ;
    PORT
      LAYER M6 ;
        RECT  0 48.96 0.069 48.992 ;
    END
  END rce0[219]
  PIN rce0[21]
    DIRECTION INPUT ;
    USE SIGNAL ;
    PORT
      LAYER M6 ;
        RECT  0 44.096 0.069 44.128 ;
    END
  END rce0[21]
  PIN rce0[220]
    DIRECTION INPUT ;
    USE SIGNAL ;
    PORT
      LAYER M6 ;
        RECT  0 49.088 0.069 49.12 ;
    END
  END rce0[220]
  PIN rce0[221]
    DIRECTION INPUT ;
    USE SIGNAL ;
    PORT
      LAYER M6 ;
        RECT  0 49.216 0.069 49.248 ;
    END
  END rce0[221]
  PIN rce0[222]
    DIRECTION INPUT ;
    USE SIGNAL ;
    PORT
      LAYER M6 ;
        RECT  0 49.344 0.069 49.376 ;
    END
  END rce0[222]
  PIN rce0[223]
    DIRECTION INPUT ;
    USE SIGNAL ;
    PORT
      LAYER M6 ;
        RECT  0 49.472 0.069 49.504 ;
    END
  END rce0[223]
  PIN rce0[224]
    DIRECTION INPUT ;
    USE SIGNAL ;
    PORT
      LAYER M4 ;
        RECT  0 60.144 0.084 60.168 ;
    END
  END rce0[224]
  PIN rce0[225]
    DIRECTION INPUT ;
    USE SIGNAL ;
    PORT
      LAYER M4 ;
        RECT  0 60.24 0.084 60.264 ;
    END
  END rce0[225]
  PIN rce0[226]
    DIRECTION INPUT ;
    USE SIGNAL ;
    PORT
      LAYER M4 ;
        RECT  0 60.336 0.084 60.36 ;
    END
  END rce0[226]
  PIN rce0[227]
    DIRECTION INPUT ;
    USE SIGNAL ;
    PORT
      LAYER M4 ;
        RECT  0 60.432 0.084 60.456 ;
    END
  END rce0[227]
  PIN rce0[228]
    DIRECTION INPUT ;
    USE SIGNAL ;
    PORT
      LAYER M4 ;
        RECT  0 60.528 0.084 60.552 ;
    END
  END rce0[228]
  PIN rce0[229]
    DIRECTION INPUT ;
    USE SIGNAL ;
    PORT
      LAYER M4 ;
        RECT  0 60.624 0.084 60.648 ;
    END
  END rce0[229]
  PIN rce0[22]
    DIRECTION INPUT ;
    USE SIGNAL ;
    PORT
      LAYER M6 ;
        RECT  0 44.224 0.069 44.256 ;
    END
  END rce0[22]
  PIN rce0[230]
    DIRECTION INPUT ;
    USE SIGNAL ;
    PORT
      LAYER M4 ;
        RECT  0 60.72 0.084 60.744 ;
    END
  END rce0[230]
  PIN rce0[231]
    DIRECTION INPUT ;
    USE SIGNAL ;
    PORT
      LAYER M4 ;
        RECT  0 60.816 0.084 60.84 ;
    END
  END rce0[231]
  PIN rce0[232]
    DIRECTION INPUT ;
    USE SIGNAL ;
    PORT
      LAYER M4 ;
        RECT  0 60.912 0.084 60.936 ;
    END
  END rce0[232]
  PIN rce0[233]
    DIRECTION INPUT ;
    USE SIGNAL ;
    PORT
      LAYER M4 ;
        RECT  0 61.008 0.084 61.032 ;
    END
  END rce0[233]
  PIN rce0[234]
    DIRECTION INPUT ;
    USE SIGNAL ;
    PORT
      LAYER M4 ;
        RECT  0 61.104 0.084 61.128 ;
    END
  END rce0[234]
  PIN rce0[235]
    DIRECTION INPUT ;
    USE SIGNAL ;
    PORT
      LAYER M4 ;
        RECT  0 61.2 0.084 61.224 ;
    END
  END rce0[235]
  PIN rce0[236]
    DIRECTION INPUT ;
    USE SIGNAL ;
    PORT
      LAYER M4 ;
        RECT  0 61.296 0.084 61.32 ;
    END
  END rce0[236]
  PIN rce0[237]
    DIRECTION INPUT ;
    USE SIGNAL ;
    PORT
      LAYER M4 ;
        RECT  0 61.392 0.084 61.416 ;
    END
  END rce0[237]
  PIN rce0[238]
    DIRECTION INPUT ;
    USE SIGNAL ;
    PORT
      LAYER M4 ;
        RECT  0 61.488 0.084 61.512 ;
    END
  END rce0[238]
  PIN rce0[239]
    DIRECTION INPUT ;
    USE SIGNAL ;
    PORT
      LAYER M4 ;
        RECT  0 61.584 0.084 61.608 ;
    END
  END rce0[239]
  PIN rce0[23]
    DIRECTION INPUT ;
    USE SIGNAL ;
    PORT
      LAYER M6 ;
        RECT  0 44.352 0.069 44.384 ;
    END
  END rce0[23]
  PIN rce0[240]
    DIRECTION INPUT ;
    USE SIGNAL ;
    PORT
      LAYER M4 ;
        RECT  0 61.68 0.084 61.704 ;
    END
  END rce0[240]
  PIN rce0[241]
    DIRECTION INPUT ;
    USE SIGNAL ;
    PORT
      LAYER M4 ;
        RECT  0 61.776 0.084 61.8 ;
    END
  END rce0[241]
  PIN rce0[242]
    DIRECTION INPUT ;
    USE SIGNAL ;
    PORT
      LAYER M4 ;
        RECT  0 61.872 0.084 61.896 ;
    END
  END rce0[242]
  PIN rce0[243]
    DIRECTION INPUT ;
    USE SIGNAL ;
    PORT
      LAYER M4 ;
        RECT  0 61.968 0.084 61.992 ;
    END
  END rce0[243]
  PIN rce0[244]
    DIRECTION INPUT ;
    USE SIGNAL ;
    PORT
      LAYER M4 ;
        RECT  0 62.064 0.084 62.088 ;
    END
  END rce0[244]
  PIN rce0[245]
    DIRECTION INPUT ;
    USE SIGNAL ;
    PORT
      LAYER M4 ;
        RECT  0 62.16 0.084 62.184 ;
    END
  END rce0[245]
  PIN rce0[246]
    DIRECTION INPUT ;
    USE SIGNAL ;
    PORT
      LAYER M4 ;
        RECT  0 62.256 0.084 62.28 ;
    END
  END rce0[246]
  PIN rce0[247]
    DIRECTION INPUT ;
    USE SIGNAL ;
    PORT
      LAYER M4 ;
        RECT  0 62.352 0.084 62.376 ;
    END
  END rce0[247]
  PIN rce0[248]
    DIRECTION INPUT ;
    USE SIGNAL ;
    PORT
      LAYER M4 ;
        RECT  0 62.448 0.084 62.472 ;
    END
  END rce0[248]
  PIN rce0[249]
    DIRECTION INPUT ;
    USE SIGNAL ;
    PORT
      LAYER M4 ;
        RECT  0 62.544 0.084 62.568 ;
    END
  END rce0[249]
  PIN rce0[24]
    DIRECTION INPUT ;
    USE SIGNAL ;
    PORT
      LAYER M6 ;
        RECT  0 44.48 0.069 44.512 ;
    END
  END rce0[24]
  PIN rce0[250]
    DIRECTION INPUT ;
    USE SIGNAL ;
    PORT
      LAYER M4 ;
        RECT  0 62.64 0.084 62.664 ;
    END
  END rce0[250]
  PIN rce0[251]
    DIRECTION INPUT ;
    USE SIGNAL ;
    PORT
      LAYER M4 ;
        RECT  0 62.736 0.084 62.76 ;
    END
  END rce0[251]
  PIN rce0[252]
    DIRECTION INPUT ;
    USE SIGNAL ;
    PORT
      LAYER M4 ;
        RECT  0 62.832 0.084 62.856 ;
    END
  END rce0[252]
  PIN rce0[253]
    DIRECTION INPUT ;
    USE SIGNAL ;
    PORT
      LAYER M4 ;
        RECT  0 62.928 0.084 62.952 ;
    END
  END rce0[253]
  PIN rce0[254]
    DIRECTION INPUT ;
    USE SIGNAL ;
    PORT
      LAYER M4 ;
        RECT  0 63.024 0.084 63.048 ;
    END
  END rce0[254]
  PIN rce0[255]
    DIRECTION INPUT ;
    USE SIGNAL ;
    PORT
      LAYER M4 ;
        RECT  0 63.12 0.084 63.144 ;
    END
  END rce0[255]
  PIN rce0[256]
    DIRECTION INPUT ;
    USE SIGNAL ;
    PORT
      LAYER M6 ;
        RECT  0 49.6 0.069 49.632 ;
    END
  END rce0[256]
  PIN rce0[257]
    DIRECTION INPUT ;
    USE SIGNAL ;
    PORT
      LAYER M6 ;
        RECT  0 49.728 0.069 49.76 ;
    END
  END rce0[257]
  PIN rce0[258]
    DIRECTION INPUT ;
    USE SIGNAL ;
    PORT
      LAYER M6 ;
        RECT  0 49.856 0.069 49.888 ;
    END
  END rce0[258]
  PIN rce0[259]
    DIRECTION INPUT ;
    USE SIGNAL ;
    PORT
      LAYER M6 ;
        RECT  0 49.984 0.069 50.016 ;
    END
  END rce0[259]
  PIN rce0[25]
    DIRECTION INPUT ;
    USE SIGNAL ;
    PORT
      LAYER M6 ;
        RECT  0 44.608 0.069 44.64 ;
    END
  END rce0[25]
  PIN rce0[260]
    DIRECTION INPUT ;
    USE SIGNAL ;
    PORT
      LAYER M6 ;
        RECT  0 50.112 0.069 50.144 ;
    END
  END rce0[260]
  PIN rce0[261]
    DIRECTION INPUT ;
    USE SIGNAL ;
    PORT
      LAYER M6 ;
        RECT  0 50.24 0.069 50.272 ;
    END
  END rce0[261]
  PIN rce0[262]
    DIRECTION INPUT ;
    USE SIGNAL ;
    PORT
      LAYER M6 ;
        RECT  0 50.368 0.069 50.4 ;
    END
  END rce0[262]
  PIN rce0[263]
    DIRECTION INPUT ;
    USE SIGNAL ;
    PORT
      LAYER M6 ;
        RECT  0 50.496 0.069 50.528 ;
    END
  END rce0[263]
  PIN rce0[264]
    DIRECTION INPUT ;
    USE SIGNAL ;
    PORT
      LAYER M6 ;
        RECT  0 50.624 0.069 50.656 ;
    END
  END rce0[264]
  PIN rce0[265]
    DIRECTION INPUT ;
    USE SIGNAL ;
    PORT
      LAYER M6 ;
        RECT  0 50.752 0.069 50.784 ;
    END
  END rce0[265]
  PIN rce0[266]
    DIRECTION INPUT ;
    USE SIGNAL ;
    PORT
      LAYER M6 ;
        RECT  0 50.88 0.069 50.912 ;
    END
  END rce0[266]
  PIN rce0[267]
    DIRECTION INPUT ;
    USE SIGNAL ;
    PORT
      LAYER M6 ;
        RECT  0 51.008 0.069 51.04 ;
    END
  END rce0[267]
  PIN rce0[268]
    DIRECTION INPUT ;
    USE SIGNAL ;
    PORT
      LAYER M6 ;
        RECT  0 51.136 0.069 51.168 ;
    END
  END rce0[268]
  PIN rce0[269]
    DIRECTION INPUT ;
    USE SIGNAL ;
    PORT
      LAYER M6 ;
        RECT  0 51.264 0.069 51.296 ;
    END
  END rce0[269]
  PIN rce0[26]
    DIRECTION INPUT ;
    USE SIGNAL ;
    PORT
      LAYER M6 ;
        RECT  0 44.736 0.069 44.768 ;
    END
  END rce0[26]
  PIN rce0[270]
    DIRECTION INPUT ;
    USE SIGNAL ;
    PORT
      LAYER M6 ;
        RECT  0 51.392 0.069 51.424 ;
    END
  END rce0[270]
  PIN rce0[271]
    DIRECTION INPUT ;
    USE SIGNAL ;
    PORT
      LAYER M6 ;
        RECT  0 51.52 0.069 51.552 ;
    END
  END rce0[271]
  PIN rce0[272]
    DIRECTION INPUT ;
    USE SIGNAL ;
    PORT
      LAYER M6 ;
        RECT  0 51.648 0.069 51.68 ;
    END
  END rce0[272]
  PIN rce0[273]
    DIRECTION INPUT ;
    USE SIGNAL ;
    PORT
      LAYER M6 ;
        RECT  0 51.776 0.069 51.808 ;
    END
  END rce0[273]
  PIN rce0[274]
    DIRECTION INPUT ;
    USE SIGNAL ;
    PORT
      LAYER M6 ;
        RECT  0 51.904 0.069 51.936 ;
    END
  END rce0[274]
  PIN rce0[275]
    DIRECTION INPUT ;
    USE SIGNAL ;
    PORT
      LAYER M6 ;
        RECT  0 52.032 0.069 52.064 ;
    END
  END rce0[275]
  PIN rce0[276]
    DIRECTION INPUT ;
    USE SIGNAL ;
    PORT
      LAYER M6 ;
        RECT  0 52.16 0.069 52.192 ;
    END
  END rce0[276]
  PIN rce0[277]
    DIRECTION INPUT ;
    USE SIGNAL ;
    PORT
      LAYER M6 ;
        RECT  0 52.288 0.069 52.32 ;
    END
  END rce0[277]
  PIN rce0[278]
    DIRECTION INPUT ;
    USE SIGNAL ;
    PORT
      LAYER M6 ;
        RECT  0 52.416 0.069 52.448 ;
    END
  END rce0[278]
  PIN rce0[279]
    DIRECTION INPUT ;
    USE SIGNAL ;
    PORT
      LAYER M6 ;
        RECT  0 52.544 0.069 52.576 ;
    END
  END rce0[279]
  PIN rce0[27]
    DIRECTION INPUT ;
    USE SIGNAL ;
    PORT
      LAYER M6 ;
        RECT  0 44.864 0.069 44.896 ;
    END
  END rce0[27]
  PIN rce0[280]
    DIRECTION INPUT ;
    USE SIGNAL ;
    PORT
      LAYER M6 ;
        RECT  0 52.672 0.069 52.704 ;
    END
  END rce0[280]
  PIN rce0[281]
    DIRECTION INPUT ;
    USE SIGNAL ;
    PORT
      LAYER M6 ;
        RECT  0 52.8 0.069 52.832 ;
    END
  END rce0[281]
  PIN rce0[282]
    DIRECTION INPUT ;
    USE SIGNAL ;
    PORT
      LAYER M6 ;
        RECT  0 52.928 0.069 52.96 ;
    END
  END rce0[282]
  PIN rce0[283]
    DIRECTION INPUT ;
    USE SIGNAL ;
    PORT
      LAYER M6 ;
        RECT  0 53.056 0.069 53.088 ;
    END
  END rce0[283]
  PIN rce0[284]
    DIRECTION INPUT ;
    USE SIGNAL ;
    PORT
      LAYER M6 ;
        RECT  0 53.184 0.069 53.216 ;
    END
  END rce0[284]
  PIN rce0[285]
    DIRECTION INPUT ;
    USE SIGNAL ;
    PORT
      LAYER M6 ;
        RECT  0 53.312 0.069 53.344 ;
    END
  END rce0[285]
  PIN rce0[286]
    DIRECTION INPUT ;
    USE SIGNAL ;
    PORT
      LAYER M6 ;
        RECT  0 53.44 0.069 53.472 ;
    END
  END rce0[286]
  PIN rce0[287]
    DIRECTION INPUT ;
    USE SIGNAL ;
    PORT
      LAYER M6 ;
        RECT  0 53.568 0.069 53.6 ;
    END
  END rce0[287]
  PIN rce0[28]
    DIRECTION INPUT ;
    USE SIGNAL ;
    PORT
      LAYER M6 ;
        RECT  0 44.992 0.069 45.024 ;
    END
  END rce0[28]
  PIN rce0[29]
    DIRECTION INPUT ;
    USE SIGNAL ;
    PORT
      LAYER M6 ;
        RECT  0 45.12 0.069 45.152 ;
    END
  END rce0[29]
  PIN rce0[2]
    DIRECTION INPUT ;
    USE SIGNAL ;
    PORT
      LAYER M6 ;
        RECT  0 41.664 0.069 41.696 ;
    END
  END rce0[2]
  PIN rce0[30]
    DIRECTION INPUT ;
    USE SIGNAL ;
    PORT
      LAYER M6 ;
        RECT  0 45.248 0.069 45.28 ;
    END
  END rce0[30]
  PIN rce0[31]
    DIRECTION INPUT ;
    USE SIGNAL ;
    PORT
      LAYER M6 ;
        RECT  0 45.376 0.069 45.408 ;
    END
  END rce0[31]
  PIN rce0[32]
    DIRECTION INPUT ;
    USE SIGNAL ;
    PORT
      LAYER M6 ;
        RECT  0 28.096 0.069 28.128 ;
    END
  END rce0[32]
  PIN rce0[33]
    DIRECTION INPUT ;
    USE SIGNAL ;
    PORT
      LAYER M6 ;
        RECT  0 28.224 0.069 28.256 ;
    END
  END rce0[33]
  PIN rce0[34]
    DIRECTION INPUT ;
    USE SIGNAL ;
    PORT
      LAYER M6 ;
        RECT  0 28.352 0.069 28.384 ;
    END
  END rce0[34]
  PIN rce0[35]
    DIRECTION INPUT ;
    USE SIGNAL ;
    PORT
      LAYER M6 ;
        RECT  0 28.48 0.069 28.512 ;
    END
  END rce0[35]
  PIN rce0[36]
    DIRECTION INPUT ;
    USE SIGNAL ;
    PORT
      LAYER M6 ;
        RECT  0 28.608 0.069 28.64 ;
    END
  END rce0[36]
  PIN rce0[37]
    DIRECTION INPUT ;
    USE SIGNAL ;
    PORT
      LAYER M6 ;
        RECT  0 28.736 0.069 28.768 ;
    END
  END rce0[37]
  PIN rce0[38]
    DIRECTION INPUT ;
    USE SIGNAL ;
    PORT
      LAYER M6 ;
        RECT  0 28.864 0.069 28.896 ;
    END
  END rce0[38]
  PIN rce0[39]
    DIRECTION INPUT ;
    USE SIGNAL ;
    PORT
      LAYER M6 ;
        RECT  0 28.992 0.069 29.024 ;
    END
  END rce0[39]
  PIN rce0[3]
    DIRECTION INPUT ;
    USE SIGNAL ;
    PORT
      LAYER M6 ;
        RECT  0 41.792 0.069 41.824 ;
    END
  END rce0[3]
  PIN rce0[40]
    DIRECTION INPUT ;
    USE SIGNAL ;
    PORT
      LAYER M6 ;
        RECT  0 29.12 0.069 29.152 ;
    END
  END rce0[40]
  PIN rce0[41]
    DIRECTION INPUT ;
    USE SIGNAL ;
    PORT
      LAYER M6 ;
        RECT  0 29.248 0.069 29.28 ;
    END
  END rce0[41]
  PIN rce0[42]
    DIRECTION INPUT ;
    USE SIGNAL ;
    PORT
      LAYER M6 ;
        RECT  0 29.376 0.069 29.408 ;
    END
  END rce0[42]
  PIN rce0[43]
    DIRECTION INPUT ;
    USE SIGNAL ;
    PORT
      LAYER M6 ;
        RECT  0 29.504 0.069 29.536 ;
    END
  END rce0[43]
  PIN rce0[44]
    DIRECTION INPUT ;
    USE SIGNAL ;
    PORT
      LAYER M6 ;
        RECT  0 29.632 0.069 29.664 ;
    END
  END rce0[44]
  PIN rce0[45]
    DIRECTION INPUT ;
    USE SIGNAL ;
    PORT
      LAYER M6 ;
        RECT  0 29.76 0.069 29.792 ;
    END
  END rce0[45]
  PIN rce0[46]
    DIRECTION INPUT ;
    USE SIGNAL ;
    PORT
      LAYER M6 ;
        RECT  0 29.888 0.069 29.92 ;
    END
  END rce0[46]
  PIN rce0[47]
    DIRECTION INPUT ;
    USE SIGNAL ;
    PORT
      LAYER M6 ;
        RECT  0 30.016 0.069 30.048 ;
    END
  END rce0[47]
  PIN rce0[48]
    DIRECTION INPUT ;
    USE SIGNAL ;
    PORT
      LAYER M6 ;
        RECT  0 30.144 0.069 30.176 ;
    END
  END rce0[48]
  PIN rce0[49]
    DIRECTION INPUT ;
    USE SIGNAL ;
    PORT
      LAYER M6 ;
        RECT  0 30.272 0.069 30.304 ;
    END
  END rce0[49]
  PIN rce0[4]
    DIRECTION INPUT ;
    USE SIGNAL ;
    PORT
      LAYER M6 ;
        RECT  0 41.92 0.069 41.952 ;
    END
  END rce0[4]
  PIN rce0[50]
    DIRECTION INPUT ;
    USE SIGNAL ;
    PORT
      LAYER M6 ;
        RECT  0 30.4 0.069 30.432 ;
    END
  END rce0[50]
  PIN rce0[51]
    DIRECTION INPUT ;
    USE SIGNAL ;
    PORT
      LAYER M6 ;
        RECT  0 30.528 0.069 30.56 ;
    END
  END rce0[51]
  PIN rce0[52]
    DIRECTION INPUT ;
    USE SIGNAL ;
    PORT
      LAYER M6 ;
        RECT  0 30.656 0.069 30.688 ;
    END
  END rce0[52]
  PIN rce0[53]
    DIRECTION INPUT ;
    USE SIGNAL ;
    PORT
      LAYER M6 ;
        RECT  0 30.784 0.069 30.816 ;
    END
  END rce0[53]
  PIN rce0[54]
    DIRECTION INPUT ;
    USE SIGNAL ;
    PORT
      LAYER M6 ;
        RECT  0 30.912 0.069 30.944 ;
    END
  END rce0[54]
  PIN rce0[55]
    DIRECTION INPUT ;
    USE SIGNAL ;
    PORT
      LAYER M6 ;
        RECT  0 31.04 0.069 31.072 ;
    END
  END rce0[55]
  PIN rce0[56]
    DIRECTION INPUT ;
    USE SIGNAL ;
    PORT
      LAYER M6 ;
        RECT  0 31.168 0.069 31.2 ;
    END
  END rce0[56]
  PIN rce0[57]
    DIRECTION INPUT ;
    USE SIGNAL ;
    PORT
      LAYER M6 ;
        RECT  0 31.296 0.069 31.328 ;
    END
  END rce0[57]
  PIN rce0[58]
    DIRECTION INPUT ;
    USE SIGNAL ;
    PORT
      LAYER M6 ;
        RECT  0 31.424 0.069 31.456 ;
    END
  END rce0[58]
  PIN rce0[59]
    DIRECTION INPUT ;
    USE SIGNAL ;
    PORT
      LAYER M6 ;
        RECT  0 31.552 0.069 31.584 ;
    END
  END rce0[59]
  PIN rce0[5]
    DIRECTION INPUT ;
    USE SIGNAL ;
    PORT
      LAYER M6 ;
        RECT  0 42.048 0.069 42.08 ;
    END
  END rce0[5]
  PIN rce0[60]
    DIRECTION INPUT ;
    USE SIGNAL ;
    PORT
      LAYER M6 ;
        RECT  0 31.68 0.069 31.712 ;
    END
  END rce0[60]
  PIN rce0[61]
    DIRECTION INPUT ;
    USE SIGNAL ;
    PORT
      LAYER M6 ;
        RECT  0 31.808 0.069 31.84 ;
    END
  END rce0[61]
  PIN rce0[62]
    DIRECTION INPUT ;
    USE SIGNAL ;
    PORT
      LAYER M6 ;
        RECT  0 31.936 0.069 31.968 ;
    END
  END rce0[62]
  PIN rce0[63]
    DIRECTION INPUT ;
    USE SIGNAL ;
    PORT
      LAYER M6 ;
        RECT  0 32.064 0.069 32.096 ;
    END
  END rce0[63]
  PIN rce0[64]
    DIRECTION INPUT ;
    USE SIGNAL ;
    PORT
      LAYER M6 ;
        RECT  0 2.496 0.069 2.528 ;
    END
  END rce0[64]
  PIN rce0[65]
    DIRECTION INPUT ;
    USE SIGNAL ;
    PORT
      LAYER M6 ;
        RECT  0 2.624 0.069 2.656 ;
    END
  END rce0[65]
  PIN rce0[66]
    DIRECTION INPUT ;
    USE SIGNAL ;
    PORT
      LAYER M6 ;
        RECT  0 2.752 0.069 2.784 ;
    END
  END rce0[66]
  PIN rce0[67]
    DIRECTION INPUT ;
    USE SIGNAL ;
    PORT
      LAYER M6 ;
        RECT  0 2.88 0.069 2.912 ;
    END
  END rce0[67]
  PIN rce0[68]
    DIRECTION INPUT ;
    USE SIGNAL ;
    PORT
      LAYER M6 ;
        RECT  0 3.008 0.069 3.04 ;
    END
  END rce0[68]
  PIN rce0[69]
    DIRECTION INPUT ;
    USE SIGNAL ;
    PORT
      LAYER M6 ;
        RECT  0 3.136 0.069 3.168 ;
    END
  END rce0[69]
  PIN rce0[6]
    DIRECTION INPUT ;
    USE SIGNAL ;
    PORT
      LAYER M6 ;
        RECT  0 42.176 0.069 42.208 ;
    END
  END rce0[6]
  PIN rce0[70]
    DIRECTION INPUT ;
    USE SIGNAL ;
    PORT
      LAYER M6 ;
        RECT  0 3.264 0.069 3.296 ;
    END
  END rce0[70]
  PIN rce0[71]
    DIRECTION INPUT ;
    USE SIGNAL ;
    PORT
      LAYER M6 ;
        RECT  0 3.392 0.069 3.424 ;
    END
  END rce0[71]
  PIN rce0[72]
    DIRECTION INPUT ;
    USE SIGNAL ;
    PORT
      LAYER M6 ;
        RECT  0 3.52 0.069 3.552 ;
    END
  END rce0[72]
  PIN rce0[73]
    DIRECTION INPUT ;
    USE SIGNAL ;
    PORT
      LAYER M6 ;
        RECT  0 3.648 0.069 3.68 ;
    END
  END rce0[73]
  PIN rce0[74]
    DIRECTION INPUT ;
    USE SIGNAL ;
    PORT
      LAYER M6 ;
        RECT  0 3.776 0.069 3.808 ;
    END
  END rce0[74]
  PIN rce0[75]
    DIRECTION INPUT ;
    USE SIGNAL ;
    PORT
      LAYER M6 ;
        RECT  0 3.904 0.069 3.936 ;
    END
  END rce0[75]
  PIN rce0[76]
    DIRECTION INPUT ;
    USE SIGNAL ;
    PORT
      LAYER M6 ;
        RECT  0 4.032 0.069 4.064 ;
    END
  END rce0[76]
  PIN rce0[77]
    DIRECTION INPUT ;
    USE SIGNAL ;
    PORT
      LAYER M6 ;
        RECT  0 4.16 0.069 4.192 ;
    END
  END rce0[77]
  PIN rce0[78]
    DIRECTION INPUT ;
    USE SIGNAL ;
    PORT
      LAYER M6 ;
        RECT  0 4.288 0.069 4.32 ;
    END
  END rce0[78]
  PIN rce0[79]
    DIRECTION INPUT ;
    USE SIGNAL ;
    PORT
      LAYER M6 ;
        RECT  0 4.416 0.069 4.448 ;
    END
  END rce0[79]
  PIN rce0[7]
    DIRECTION INPUT ;
    USE SIGNAL ;
    PORT
      LAYER M6 ;
        RECT  0 42.304 0.069 42.336 ;
    END
  END rce0[7]
  PIN rce0[80]
    DIRECTION INPUT ;
    USE SIGNAL ;
    PORT
      LAYER M6 ;
        RECT  0 4.544 0.069 4.576 ;
    END
  END rce0[80]
  PIN rce0[81]
    DIRECTION INPUT ;
    USE SIGNAL ;
    PORT
      LAYER M6 ;
        RECT  0 4.672 0.069 4.704 ;
    END
  END rce0[81]
  PIN rce0[82]
    DIRECTION INPUT ;
    USE SIGNAL ;
    PORT
      LAYER M6 ;
        RECT  0 4.8 0.069 4.832 ;
    END
  END rce0[82]
  PIN rce0[83]
    DIRECTION INPUT ;
    USE SIGNAL ;
    PORT
      LAYER M6 ;
        RECT  0 4.928 0.069 4.96 ;
    END
  END rce0[83]
  PIN rce0[84]
    DIRECTION INPUT ;
    USE SIGNAL ;
    PORT
      LAYER M6 ;
        RECT  0 5.056 0.069 5.088 ;
    END
  END rce0[84]
  PIN rce0[85]
    DIRECTION INPUT ;
    USE SIGNAL ;
    PORT
      LAYER M6 ;
        RECT  0 5.184 0.069 5.216 ;
    END
  END rce0[85]
  PIN rce0[86]
    DIRECTION INPUT ;
    USE SIGNAL ;
    PORT
      LAYER M6 ;
        RECT  0 5.312 0.069 5.344 ;
    END
  END rce0[86]
  PIN rce0[87]
    DIRECTION INPUT ;
    USE SIGNAL ;
    PORT
      LAYER M6 ;
        RECT  0 5.44 0.069 5.472 ;
    END
  END rce0[87]
  PIN rce0[88]
    DIRECTION INPUT ;
    USE SIGNAL ;
    PORT
      LAYER M6 ;
        RECT  0 5.568 0.069 5.6 ;
    END
  END rce0[88]
  PIN rce0[89]
    DIRECTION INPUT ;
    USE SIGNAL ;
    PORT
      LAYER M6 ;
        RECT  0 5.696 0.069 5.728 ;
    END
  END rce0[89]
  PIN rce0[8]
    DIRECTION INPUT ;
    USE SIGNAL ;
    PORT
      LAYER M6 ;
        RECT  0 42.432 0.069 42.464 ;
    END
  END rce0[8]
  PIN rce0[90]
    DIRECTION INPUT ;
    USE SIGNAL ;
    PORT
      LAYER M6 ;
        RECT  0 5.824 0.069 5.856 ;
    END
  END rce0[90]
  PIN rce0[91]
    DIRECTION INPUT ;
    USE SIGNAL ;
    PORT
      LAYER M6 ;
        RECT  0 5.952 0.069 5.984 ;
    END
  END rce0[91]
  PIN rce0[92]
    DIRECTION INPUT ;
    USE SIGNAL ;
    PORT
      LAYER M6 ;
        RECT  0 6.08 0.069 6.112 ;
    END
  END rce0[92]
  PIN rce0[93]
    DIRECTION INPUT ;
    USE SIGNAL ;
    PORT
      LAYER M6 ;
        RECT  0 6.208 0.069 6.24 ;
    END
  END rce0[93]
  PIN rce0[94]
    DIRECTION INPUT ;
    USE SIGNAL ;
    PORT
      LAYER M6 ;
        RECT  0 6.336 0.069 6.368 ;
    END
  END rce0[94]
  PIN rce0[95]
    DIRECTION INPUT ;
    USE SIGNAL ;
    PORT
      LAYER M6 ;
        RECT  0 6.464 0.069 6.496 ;
    END
  END rce0[95]
  PIN rce0[96]
    DIRECTION INPUT ;
    USE SIGNAL ;
    PORT
      LAYER M4 ;
        RECT  0 2.544 0.084 2.568 ;
    END
  END rce0[96]
  PIN rce0[97]
    DIRECTION INPUT ;
    USE SIGNAL ;
    PORT
      LAYER M4 ;
        RECT  0 2.64 0.084 2.664 ;
    END
  END rce0[97]
  PIN rce0[98]
    DIRECTION INPUT ;
    USE SIGNAL ;
    PORT
      LAYER M4 ;
        RECT  0 2.736 0.084 2.76 ;
    END
  END rce0[98]
  PIN rce0[99]
    DIRECTION INPUT ;
    USE SIGNAL ;
    PORT
      LAYER M4 ;
        RECT  0 2.832 0.084 2.856 ;
    END
  END rce0[99]
  PIN rce0[9]
    DIRECTION INPUT ;
    USE SIGNAL ;
    PORT
      LAYER M6 ;
        RECT  0 42.56 0.069 42.592 ;
    END
  END rce0[9]
  PIN rce0_cr
    DIRECTION OUTPUT ;
    USE SIGNAL ;
    PORT
      LAYER M4 ;
        RECT  0 37.872 0.084 37.896 ;
    END
  END rce0_cr
  PIN rce1[0]
    DIRECTION INPUT ;
    USE SIGNAL ;
    PORT
      LAYER M6 ;
        RECT  66.891 42.944 66.96 42.976 ;
    END
  END rce1[0]
  PIN rce1[100]
    DIRECTION INPUT ;
    USE SIGNAL ;
    PORT
      LAYER M4 ;
        RECT  66.876 13.392 66.96 13.416 ;
    END
  END rce1[100]
  PIN rce1[101]
    DIRECTION INPUT ;
    USE SIGNAL ;
    PORT
      LAYER M4 ;
        RECT  66.876 13.488 66.96 13.512 ;
    END
  END rce1[101]
  PIN rce1[102]
    DIRECTION INPUT ;
    USE SIGNAL ;
    PORT
      LAYER M4 ;
        RECT  66.876 13.584 66.96 13.608 ;
    END
  END rce1[102]
  PIN rce1[103]
    DIRECTION INPUT ;
    USE SIGNAL ;
    PORT
      LAYER M4 ;
        RECT  66.876 13.68 66.96 13.704 ;
    END
  END rce1[103]
  PIN rce1[104]
    DIRECTION INPUT ;
    USE SIGNAL ;
    PORT
      LAYER M4 ;
        RECT  66.876 13.776 66.96 13.8 ;
    END
  END rce1[104]
  PIN rce1[105]
    DIRECTION INPUT ;
    USE SIGNAL ;
    PORT
      LAYER M4 ;
        RECT  66.876 13.872 66.96 13.896 ;
    END
  END rce1[105]
  PIN rce1[106]
    DIRECTION INPUT ;
    USE SIGNAL ;
    PORT
      LAYER M4 ;
        RECT  66.876 13.968 66.96 13.992 ;
    END
  END rce1[106]
  PIN rce1[107]
    DIRECTION INPUT ;
    USE SIGNAL ;
    PORT
      LAYER M4 ;
        RECT  66.876 14.064 66.96 14.088 ;
    END
  END rce1[107]
  PIN rce1[108]
    DIRECTION INPUT ;
    USE SIGNAL ;
    PORT
      LAYER M4 ;
        RECT  66.876 14.16 66.96 14.184 ;
    END
  END rce1[108]
  PIN rce1[109]
    DIRECTION INPUT ;
    USE SIGNAL ;
    PORT
      LAYER M4 ;
        RECT  66.876 14.256 66.96 14.28 ;
    END
  END rce1[109]
  PIN rce1[10]
    DIRECTION INPUT ;
    USE SIGNAL ;
    PORT
      LAYER M6 ;
        RECT  66.891 44.224 66.96 44.256 ;
    END
  END rce1[10]
  PIN rce1[110]
    DIRECTION INPUT ;
    USE SIGNAL ;
    PORT
      LAYER M4 ;
        RECT  66.876 14.352 66.96 14.376 ;
    END
  END rce1[110]
  PIN rce1[111]
    DIRECTION INPUT ;
    USE SIGNAL ;
    PORT
      LAYER M4 ;
        RECT  66.876 14.448 66.96 14.472 ;
    END
  END rce1[111]
  PIN rce1[112]
    DIRECTION INPUT ;
    USE SIGNAL ;
    PORT
      LAYER M4 ;
        RECT  66.876 14.544 66.96 14.568 ;
    END
  END rce1[112]
  PIN rce1[113]
    DIRECTION INPUT ;
    USE SIGNAL ;
    PORT
      LAYER M4 ;
        RECT  66.876 14.64 66.96 14.664 ;
    END
  END rce1[113]
  PIN rce1[114]
    DIRECTION INPUT ;
    USE SIGNAL ;
    PORT
      LAYER M4 ;
        RECT  66.876 14.736 66.96 14.76 ;
    END
  END rce1[114]
  PIN rce1[115]
    DIRECTION INPUT ;
    USE SIGNAL ;
    PORT
      LAYER M4 ;
        RECT  66.876 14.832 66.96 14.856 ;
    END
  END rce1[115]
  PIN rce1[116]
    DIRECTION INPUT ;
    USE SIGNAL ;
    PORT
      LAYER M4 ;
        RECT  66.876 14.928 66.96 14.952 ;
    END
  END rce1[116]
  PIN rce1[117]
    DIRECTION INPUT ;
    USE SIGNAL ;
    PORT
      LAYER M4 ;
        RECT  66.876 15.024 66.96 15.048 ;
    END
  END rce1[117]
  PIN rce1[118]
    DIRECTION INPUT ;
    USE SIGNAL ;
    PORT
      LAYER M4 ;
        RECT  66.876 15.12 66.96 15.144 ;
    END
  END rce1[118]
  PIN rce1[119]
    DIRECTION INPUT ;
    USE SIGNAL ;
    PORT
      LAYER M4 ;
        RECT  66.876 15.216 66.96 15.24 ;
    END
  END rce1[119]
  PIN rce1[11]
    DIRECTION INPUT ;
    USE SIGNAL ;
    PORT
      LAYER M6 ;
        RECT  66.891 44.352 66.96 44.384 ;
    END
  END rce1[11]
  PIN rce1[120]
    DIRECTION INPUT ;
    USE SIGNAL ;
    PORT
      LAYER M4 ;
        RECT  66.876 15.312 66.96 15.336 ;
    END
  END rce1[120]
  PIN rce1[121]
    DIRECTION INPUT ;
    USE SIGNAL ;
    PORT
      LAYER M4 ;
        RECT  66.876 15.408 66.96 15.432 ;
    END
  END rce1[121]
  PIN rce1[122]
    DIRECTION INPUT ;
    USE SIGNAL ;
    PORT
      LAYER M4 ;
        RECT  66.876 15.504 66.96 15.528 ;
    END
  END rce1[122]
  PIN rce1[123]
    DIRECTION INPUT ;
    USE SIGNAL ;
    PORT
      LAYER M4 ;
        RECT  66.876 15.6 66.96 15.624 ;
    END
  END rce1[123]
  PIN rce1[124]
    DIRECTION INPUT ;
    USE SIGNAL ;
    PORT
      LAYER M4 ;
        RECT  66.876 15.696 66.96 15.72 ;
    END
  END rce1[124]
  PIN rce1[125]
    DIRECTION INPUT ;
    USE SIGNAL ;
    PORT
      LAYER M4 ;
        RECT  66.876 15.792 66.96 15.816 ;
    END
  END rce1[125]
  PIN rce1[126]
    DIRECTION INPUT ;
    USE SIGNAL ;
    PORT
      LAYER M4 ;
        RECT  66.876 15.888 66.96 15.912 ;
    END
  END rce1[126]
  PIN rce1[127]
    DIRECTION INPUT ;
    USE SIGNAL ;
    PORT
      LAYER M4 ;
        RECT  66.876 15.984 66.96 16.008 ;
    END
  END rce1[127]
  PIN rce1[128]
    DIRECTION INPUT ;
    USE SIGNAL ;
    PORT
      LAYER M4 ;
        RECT  66.876 26.064 66.96 26.088 ;
    END
  END rce1[128]
  PIN rce1[129]
    DIRECTION INPUT ;
    USE SIGNAL ;
    PORT
      LAYER M4 ;
        RECT  66.876 26.16 66.96 26.184 ;
    END
  END rce1[129]
  PIN rce1[12]
    DIRECTION INPUT ;
    USE SIGNAL ;
    PORT
      LAYER M6 ;
        RECT  66.891 44.48 66.96 44.512 ;
    END
  END rce1[12]
  PIN rce1[130]
    DIRECTION INPUT ;
    USE SIGNAL ;
    PORT
      LAYER M4 ;
        RECT  66.876 26.256 66.96 26.28 ;
    END
  END rce1[130]
  PIN rce1[131]
    DIRECTION INPUT ;
    USE SIGNAL ;
    PORT
      LAYER M4 ;
        RECT  66.876 26.352 66.96 26.376 ;
    END
  END rce1[131]
  PIN rce1[132]
    DIRECTION INPUT ;
    USE SIGNAL ;
    PORT
      LAYER M4 ;
        RECT  66.876 26.448 66.96 26.472 ;
    END
  END rce1[132]
  PIN rce1[133]
    DIRECTION INPUT ;
    USE SIGNAL ;
    PORT
      LAYER M4 ;
        RECT  66.876 26.544 66.96 26.568 ;
    END
  END rce1[133]
  PIN rce1[134]
    DIRECTION INPUT ;
    USE SIGNAL ;
    PORT
      LAYER M4 ;
        RECT  66.876 26.64 66.96 26.664 ;
    END
  END rce1[134]
  PIN rce1[135]
    DIRECTION INPUT ;
    USE SIGNAL ;
    PORT
      LAYER M4 ;
        RECT  66.876 26.736 66.96 26.76 ;
    END
  END rce1[135]
  PIN rce1[136]
    DIRECTION INPUT ;
    USE SIGNAL ;
    PORT
      LAYER M4 ;
        RECT  66.876 26.832 66.96 26.856 ;
    END
  END rce1[136]
  PIN rce1[137]
    DIRECTION INPUT ;
    USE SIGNAL ;
    PORT
      LAYER M4 ;
        RECT  66.876 26.928 66.96 26.952 ;
    END
  END rce1[137]
  PIN rce1[138]
    DIRECTION INPUT ;
    USE SIGNAL ;
    PORT
      LAYER M4 ;
        RECT  66.876 27.024 66.96 27.048 ;
    END
  END rce1[138]
  PIN rce1[139]
    DIRECTION INPUT ;
    USE SIGNAL ;
    PORT
      LAYER M4 ;
        RECT  66.876 27.12 66.96 27.144 ;
    END
  END rce1[139]
  PIN rce1[13]
    DIRECTION INPUT ;
    USE SIGNAL ;
    PORT
      LAYER M6 ;
        RECT  66.891 44.608 66.96 44.64 ;
    END
  END rce1[13]
  PIN rce1[140]
    DIRECTION INPUT ;
    USE SIGNAL ;
    PORT
      LAYER M4 ;
        RECT  66.876 27.216 66.96 27.24 ;
    END
  END rce1[140]
  PIN rce1[141]
    DIRECTION INPUT ;
    USE SIGNAL ;
    PORT
      LAYER M4 ;
        RECT  66.876 27.312 66.96 27.336 ;
    END
  END rce1[141]
  PIN rce1[142]
    DIRECTION INPUT ;
    USE SIGNAL ;
    PORT
      LAYER M4 ;
        RECT  66.876 27.408 66.96 27.432 ;
    END
  END rce1[142]
  PIN rce1[143]
    DIRECTION INPUT ;
    USE SIGNAL ;
    PORT
      LAYER M4 ;
        RECT  66.876 27.504 66.96 27.528 ;
    END
  END rce1[143]
  PIN rce1[144]
    DIRECTION INPUT ;
    USE SIGNAL ;
    PORT
      LAYER M4 ;
        RECT  66.876 27.6 66.96 27.624 ;
    END
  END rce1[144]
  PIN rce1[145]
    DIRECTION INPUT ;
    USE SIGNAL ;
    PORT
      LAYER M4 ;
        RECT  66.876 27.696 66.96 27.72 ;
    END
  END rce1[145]
  PIN rce1[146]
    DIRECTION INPUT ;
    USE SIGNAL ;
    PORT
      LAYER M4 ;
        RECT  66.876 27.792 66.96 27.816 ;
    END
  END rce1[146]
  PIN rce1[147]
    DIRECTION INPUT ;
    USE SIGNAL ;
    PORT
      LAYER M4 ;
        RECT  66.876 27.888 66.96 27.912 ;
    END
  END rce1[147]
  PIN rce1[148]
    DIRECTION INPUT ;
    USE SIGNAL ;
    PORT
      LAYER M4 ;
        RECT  66.876 27.984 66.96 28.008 ;
    END
  END rce1[148]
  PIN rce1[149]
    DIRECTION INPUT ;
    USE SIGNAL ;
    PORT
      LAYER M4 ;
        RECT  66.876 28.08 66.96 28.104 ;
    END
  END rce1[149]
  PIN rce1[14]
    DIRECTION INPUT ;
    USE SIGNAL ;
    PORT
      LAYER M6 ;
        RECT  66.891 44.736 66.96 44.768 ;
    END
  END rce1[14]
  PIN rce1[150]
    DIRECTION INPUT ;
    USE SIGNAL ;
    PORT
      LAYER M4 ;
        RECT  66.876 28.176 66.96 28.2 ;
    END
  END rce1[150]
  PIN rce1[151]
    DIRECTION INPUT ;
    USE SIGNAL ;
    PORT
      LAYER M4 ;
        RECT  66.876 28.272 66.96 28.296 ;
    END
  END rce1[151]
  PIN rce1[152]
    DIRECTION INPUT ;
    USE SIGNAL ;
    PORT
      LAYER M4 ;
        RECT  66.876 28.368 66.96 28.392 ;
    END
  END rce1[152]
  PIN rce1[153]
    DIRECTION INPUT ;
    USE SIGNAL ;
    PORT
      LAYER M4 ;
        RECT  66.876 28.464 66.96 28.488 ;
    END
  END rce1[153]
  PIN rce1[154]
    DIRECTION INPUT ;
    USE SIGNAL ;
    PORT
      LAYER M4 ;
        RECT  66.876 28.56 66.96 28.584 ;
    END
  END rce1[154]
  PIN rce1[155]
    DIRECTION INPUT ;
    USE SIGNAL ;
    PORT
      LAYER M4 ;
        RECT  66.876 28.656 66.96 28.68 ;
    END
  END rce1[155]
  PIN rce1[156]
    DIRECTION INPUT ;
    USE SIGNAL ;
    PORT
      LAYER M4 ;
        RECT  66.876 28.752 66.96 28.776 ;
    END
  END rce1[156]
  PIN rce1[157]
    DIRECTION INPUT ;
    USE SIGNAL ;
    PORT
      LAYER M4 ;
        RECT  66.876 28.848 66.96 28.872 ;
    END
  END rce1[157]
  PIN rce1[158]
    DIRECTION INPUT ;
    USE SIGNAL ;
    PORT
      LAYER M4 ;
        RECT  66.876 28.944 66.96 28.968 ;
    END
  END rce1[158]
  PIN rce1[159]
    DIRECTION INPUT ;
    USE SIGNAL ;
    PORT
      LAYER M4 ;
        RECT  66.876 29.04 66.96 29.064 ;
    END
  END rce1[159]
  PIN rce1[15]
    DIRECTION INPUT ;
    USE SIGNAL ;
    PORT
      LAYER M6 ;
        RECT  66.891 44.864 66.96 44.896 ;
    END
  END rce1[15]
  PIN rce1[160]
    DIRECTION INPUT ;
    USE SIGNAL ;
    PORT
      LAYER M4 ;
        RECT  66.876 35.28 66.96 35.304 ;
    END
  END rce1[160]
  PIN rce1[161]
    DIRECTION INPUT ;
    USE SIGNAL ;
    PORT
      LAYER M4 ;
        RECT  66.876 35.376 66.96 35.4 ;
    END
  END rce1[161]
  PIN rce1[162]
    DIRECTION INPUT ;
    USE SIGNAL ;
    PORT
      LAYER M4 ;
        RECT  66.876 35.472 66.96 35.496 ;
    END
  END rce1[162]
  PIN rce1[163]
    DIRECTION INPUT ;
    USE SIGNAL ;
    PORT
      LAYER M4 ;
        RECT  66.876 35.568 66.96 35.592 ;
    END
  END rce1[163]
  PIN rce1[164]
    DIRECTION INPUT ;
    USE SIGNAL ;
    PORT
      LAYER M4 ;
        RECT  66.876 35.664 66.96 35.688 ;
    END
  END rce1[164]
  PIN rce1[165]
    DIRECTION INPUT ;
    USE SIGNAL ;
    PORT
      LAYER M4 ;
        RECT  66.876 35.76 66.96 35.784 ;
    END
  END rce1[165]
  PIN rce1[166]
    DIRECTION INPUT ;
    USE SIGNAL ;
    PORT
      LAYER M4 ;
        RECT  66.876 35.856 66.96 35.88 ;
    END
  END rce1[166]
  PIN rce1[167]
    DIRECTION INPUT ;
    USE SIGNAL ;
    PORT
      LAYER M4 ;
        RECT  66.876 35.952 66.96 35.976 ;
    END
  END rce1[167]
  PIN rce1[168]
    DIRECTION INPUT ;
    USE SIGNAL ;
    PORT
      LAYER M4 ;
        RECT  66.876 36.048 66.96 36.072 ;
    END
  END rce1[168]
  PIN rce1[169]
    DIRECTION INPUT ;
    USE SIGNAL ;
    PORT
      LAYER M4 ;
        RECT  66.876 36.144 66.96 36.168 ;
    END
  END rce1[169]
  PIN rce1[16]
    DIRECTION INPUT ;
    USE SIGNAL ;
    PORT
      LAYER M6 ;
        RECT  66.891 44.992 66.96 45.024 ;
    END
  END rce1[16]
  PIN rce1[170]
    DIRECTION INPUT ;
    USE SIGNAL ;
    PORT
      LAYER M4 ;
        RECT  66.876 36.24 66.96 36.264 ;
    END
  END rce1[170]
  PIN rce1[171]
    DIRECTION INPUT ;
    USE SIGNAL ;
    PORT
      LAYER M4 ;
        RECT  66.876 36.336 66.96 36.36 ;
    END
  END rce1[171]
  PIN rce1[172]
    DIRECTION INPUT ;
    USE SIGNAL ;
    PORT
      LAYER M4 ;
        RECT  66.876 36.432 66.96 36.456 ;
    END
  END rce1[172]
  PIN rce1[173]
    DIRECTION INPUT ;
    USE SIGNAL ;
    PORT
      LAYER M4 ;
        RECT  66.876 36.528 66.96 36.552 ;
    END
  END rce1[173]
  PIN rce1[174]
    DIRECTION INPUT ;
    USE SIGNAL ;
    PORT
      LAYER M4 ;
        RECT  66.876 36.624 66.96 36.648 ;
    END
  END rce1[174]
  PIN rce1[175]
    DIRECTION INPUT ;
    USE SIGNAL ;
    PORT
      LAYER M4 ;
        RECT  66.876 36.72 66.96 36.744 ;
    END
  END rce1[175]
  PIN rce1[176]
    DIRECTION INPUT ;
    USE SIGNAL ;
    PORT
      LAYER M4 ;
        RECT  66.876 36.816 66.96 36.84 ;
    END
  END rce1[176]
  PIN rce1[177]
    DIRECTION INPUT ;
    USE SIGNAL ;
    PORT
      LAYER M4 ;
        RECT  66.876 36.912 66.96 36.936 ;
    END
  END rce1[177]
  PIN rce1[178]
    DIRECTION INPUT ;
    USE SIGNAL ;
    PORT
      LAYER M4 ;
        RECT  66.876 37.008 66.96 37.032 ;
    END
  END rce1[178]
  PIN rce1[179]
    DIRECTION INPUT ;
    USE SIGNAL ;
    PORT
      LAYER M4 ;
        RECT  66.876 37.104 66.96 37.128 ;
    END
  END rce1[179]
  PIN rce1[17]
    DIRECTION INPUT ;
    USE SIGNAL ;
    PORT
      LAYER M6 ;
        RECT  66.891 45.12 66.96 45.152 ;
    END
  END rce1[17]
  PIN rce1[180]
    DIRECTION INPUT ;
    USE SIGNAL ;
    PORT
      LAYER M4 ;
        RECT  66.876 37.2 66.96 37.224 ;
    END
  END rce1[180]
  PIN rce1[181]
    DIRECTION INPUT ;
    USE SIGNAL ;
    PORT
      LAYER M4 ;
        RECT  66.876 37.296 66.96 37.32 ;
    END
  END rce1[181]
  PIN rce1[182]
    DIRECTION INPUT ;
    USE SIGNAL ;
    PORT
      LAYER M4 ;
        RECT  66.876 37.392 66.96 37.416 ;
    END
  END rce1[182]
  PIN rce1[183]
    DIRECTION INPUT ;
    USE SIGNAL ;
    PORT
      LAYER M4 ;
        RECT  66.876 37.488 66.96 37.512 ;
    END
  END rce1[183]
  PIN rce1[184]
    DIRECTION INPUT ;
    USE SIGNAL ;
    PORT
      LAYER M4 ;
        RECT  66.876 37.584 66.96 37.608 ;
    END
  END rce1[184]
  PIN rce1[185]
    DIRECTION INPUT ;
    USE SIGNAL ;
    PORT
      LAYER M4 ;
        RECT  66.876 37.68 66.96 37.704 ;
    END
  END rce1[185]
  PIN rce1[186]
    DIRECTION INPUT ;
    USE SIGNAL ;
    PORT
      LAYER M4 ;
        RECT  66.876 37.776 66.96 37.8 ;
    END
  END rce1[186]
  PIN rce1[187]
    DIRECTION INPUT ;
    USE SIGNAL ;
    PORT
      LAYER M4 ;
        RECT  66.876 37.872 66.96 37.896 ;
    END
  END rce1[187]
  PIN rce1[188]
    DIRECTION INPUT ;
    USE SIGNAL ;
    PORT
      LAYER M4 ;
        RECT  66.876 37.968 66.96 37.992 ;
    END
  END rce1[188]
  PIN rce1[189]
    DIRECTION INPUT ;
    USE SIGNAL ;
    PORT
      LAYER M4 ;
        RECT  66.876 38.064 66.96 38.088 ;
    END
  END rce1[189]
  PIN rce1[18]
    DIRECTION INPUT ;
    USE SIGNAL ;
    PORT
      LAYER M6 ;
        RECT  66.891 45.248 66.96 45.28 ;
    END
  END rce1[18]
  PIN rce1[190]
    DIRECTION INPUT ;
    USE SIGNAL ;
    PORT
      LAYER M4 ;
        RECT  66.876 38.16 66.96 38.184 ;
    END
  END rce1[190]
  PIN rce1[191]
    DIRECTION INPUT ;
    USE SIGNAL ;
    PORT
      LAYER M4 ;
        RECT  66.876 38.256 66.96 38.28 ;
    END
  END rce1[191]
  PIN rce1[192]
    DIRECTION INPUT ;
    USE SIGNAL ;
    PORT
      LAYER M4 ;
        RECT  66.876 54.48 66.96 54.504 ;
    END
  END rce1[192]
  PIN rce1[193]
    DIRECTION INPUT ;
    USE SIGNAL ;
    PORT
      LAYER M4 ;
        RECT  66.876 54.576 66.96 54.6 ;
    END
  END rce1[193]
  PIN rce1[194]
    DIRECTION INPUT ;
    USE SIGNAL ;
    PORT
      LAYER M4 ;
        RECT  66.876 54.672 66.96 54.696 ;
    END
  END rce1[194]
  PIN rce1[195]
    DIRECTION INPUT ;
    USE SIGNAL ;
    PORT
      LAYER M4 ;
        RECT  66.876 54.768 66.96 54.792 ;
    END
  END rce1[195]
  PIN rce1[196]
    DIRECTION INPUT ;
    USE SIGNAL ;
    PORT
      LAYER M4 ;
        RECT  66.876 54.864 66.96 54.888 ;
    END
  END rce1[196]
  PIN rce1[197]
    DIRECTION INPUT ;
    USE SIGNAL ;
    PORT
      LAYER M4 ;
        RECT  66.876 54.96 66.96 54.984 ;
    END
  END rce1[197]
  PIN rce1[198]
    DIRECTION INPUT ;
    USE SIGNAL ;
    PORT
      LAYER M4 ;
        RECT  66.876 55.056 66.96 55.08 ;
    END
  END rce1[198]
  PIN rce1[199]
    DIRECTION INPUT ;
    USE SIGNAL ;
    PORT
      LAYER M4 ;
        RECT  66.876 55.152 66.96 55.176 ;
    END
  END rce1[199]
  PIN rce1[19]
    DIRECTION INPUT ;
    USE SIGNAL ;
    PORT
      LAYER M6 ;
        RECT  66.891 45.376 66.96 45.408 ;
    END
  END rce1[19]
  PIN rce1[1]
    DIRECTION INPUT ;
    USE SIGNAL ;
    PORT
      LAYER M6 ;
        RECT  66.891 43.072 66.96 43.104 ;
    END
  END rce1[1]
  PIN rce1[200]
    DIRECTION INPUT ;
    USE SIGNAL ;
    PORT
      LAYER M4 ;
        RECT  66.876 55.248 66.96 55.272 ;
    END
  END rce1[200]
  PIN rce1[201]
    DIRECTION INPUT ;
    USE SIGNAL ;
    PORT
      LAYER M4 ;
        RECT  66.876 55.344 66.96 55.368 ;
    END
  END rce1[201]
  PIN rce1[202]
    DIRECTION INPUT ;
    USE SIGNAL ;
    PORT
      LAYER M4 ;
        RECT  66.876 55.44 66.96 55.464 ;
    END
  END rce1[202]
  PIN rce1[203]
    DIRECTION INPUT ;
    USE SIGNAL ;
    PORT
      LAYER M4 ;
        RECT  66.876 55.536 66.96 55.56 ;
    END
  END rce1[203]
  PIN rce1[204]
    DIRECTION INPUT ;
    USE SIGNAL ;
    PORT
      LAYER M4 ;
        RECT  66.876 55.632 66.96 55.656 ;
    END
  END rce1[204]
  PIN rce1[205]
    DIRECTION INPUT ;
    USE SIGNAL ;
    PORT
      LAYER M4 ;
        RECT  66.876 55.728 66.96 55.752 ;
    END
  END rce1[205]
  PIN rce1[206]
    DIRECTION INPUT ;
    USE SIGNAL ;
    PORT
      LAYER M4 ;
        RECT  66.876 55.824 66.96 55.848 ;
    END
  END rce1[206]
  PIN rce1[207]
    DIRECTION INPUT ;
    USE SIGNAL ;
    PORT
      LAYER M4 ;
        RECT  66.876 55.92 66.96 55.944 ;
    END
  END rce1[207]
  PIN rce1[208]
    DIRECTION INPUT ;
    USE SIGNAL ;
    PORT
      LAYER M4 ;
        RECT  66.876 56.016 66.96 56.04 ;
    END
  END rce1[208]
  PIN rce1[209]
    DIRECTION INPUT ;
    USE SIGNAL ;
    PORT
      LAYER M4 ;
        RECT  66.876 56.112 66.96 56.136 ;
    END
  END rce1[209]
  PIN rce1[20]
    DIRECTION INPUT ;
    USE SIGNAL ;
    PORT
      LAYER M6 ;
        RECT  66.891 45.504 66.96 45.536 ;
    END
  END rce1[20]
  PIN rce1[210]
    DIRECTION INPUT ;
    USE SIGNAL ;
    PORT
      LAYER M4 ;
        RECT  66.876 56.208 66.96 56.232 ;
    END
  END rce1[210]
  PIN rce1[211]
    DIRECTION INPUT ;
    USE SIGNAL ;
    PORT
      LAYER M4 ;
        RECT  66.876 56.304 66.96 56.328 ;
    END
  END rce1[211]
  PIN rce1[212]
    DIRECTION INPUT ;
    USE SIGNAL ;
    PORT
      LAYER M4 ;
        RECT  66.876 56.4 66.96 56.424 ;
    END
  END rce1[212]
  PIN rce1[213]
    DIRECTION INPUT ;
    USE SIGNAL ;
    PORT
      LAYER M4 ;
        RECT  66.876 56.496 66.96 56.52 ;
    END
  END rce1[213]
  PIN rce1[214]
    DIRECTION INPUT ;
    USE SIGNAL ;
    PORT
      LAYER M4 ;
        RECT  66.876 56.592 66.96 56.616 ;
    END
  END rce1[214]
  PIN rce1[215]
    DIRECTION INPUT ;
    USE SIGNAL ;
    PORT
      LAYER M4 ;
        RECT  66.876 56.688 66.96 56.712 ;
    END
  END rce1[215]
  PIN rce1[216]
    DIRECTION INPUT ;
    USE SIGNAL ;
    PORT
      LAYER M4 ;
        RECT  66.876 56.784 66.96 56.808 ;
    END
  END rce1[216]
  PIN rce1[217]
    DIRECTION INPUT ;
    USE SIGNAL ;
    PORT
      LAYER M4 ;
        RECT  66.876 56.88 66.96 56.904 ;
    END
  END rce1[217]
  PIN rce1[218]
    DIRECTION INPUT ;
    USE SIGNAL ;
    PORT
      LAYER M4 ;
        RECT  66.876 56.976 66.96 57 ;
    END
  END rce1[218]
  PIN rce1[219]
    DIRECTION INPUT ;
    USE SIGNAL ;
    PORT
      LAYER M4 ;
        RECT  66.876 57.072 66.96 57.096 ;
    END
  END rce1[219]
  PIN rce1[21]
    DIRECTION INPUT ;
    USE SIGNAL ;
    PORT
      LAYER M6 ;
        RECT  66.891 45.632 66.96 45.664 ;
    END
  END rce1[21]
  PIN rce1[220]
    DIRECTION INPUT ;
    USE SIGNAL ;
    PORT
      LAYER M4 ;
        RECT  66.876 57.168 66.96 57.192 ;
    END
  END rce1[220]
  PIN rce1[221]
    DIRECTION INPUT ;
    USE SIGNAL ;
    PORT
      LAYER M4 ;
        RECT  66.876 57.264 66.96 57.288 ;
    END
  END rce1[221]
  PIN rce1[222]
    DIRECTION INPUT ;
    USE SIGNAL ;
    PORT
      LAYER M4 ;
        RECT  66.876 57.36 66.96 57.384 ;
    END
  END rce1[222]
  PIN rce1[223]
    DIRECTION INPUT ;
    USE SIGNAL ;
    PORT
      LAYER M4 ;
        RECT  66.876 57.456 66.96 57.48 ;
    END
  END rce1[223]
  PIN rce1[224]
    DIRECTION INPUT ;
    USE SIGNAL ;
    PORT
      LAYER M6 ;
        RECT  66.891 60.352 66.96 60.384 ;
    END
  END rce1[224]
  PIN rce1[225]
    DIRECTION INPUT ;
    USE SIGNAL ;
    PORT
      LAYER M6 ;
        RECT  66.891 60.48 66.96 60.512 ;
    END
  END rce1[225]
  PIN rce1[226]
    DIRECTION INPUT ;
    USE SIGNAL ;
    PORT
      LAYER M6 ;
        RECT  66.891 60.608 66.96 60.64 ;
    END
  END rce1[226]
  PIN rce1[227]
    DIRECTION INPUT ;
    USE SIGNAL ;
    PORT
      LAYER M6 ;
        RECT  66.891 60.736 66.96 60.768 ;
    END
  END rce1[227]
  PIN rce1[228]
    DIRECTION INPUT ;
    USE SIGNAL ;
    PORT
      LAYER M6 ;
        RECT  66.891 60.864 66.96 60.896 ;
    END
  END rce1[228]
  PIN rce1[229]
    DIRECTION INPUT ;
    USE SIGNAL ;
    PORT
      LAYER M6 ;
        RECT  66.891 60.992 66.96 61.024 ;
    END
  END rce1[229]
  PIN rce1[22]
    DIRECTION INPUT ;
    USE SIGNAL ;
    PORT
      LAYER M6 ;
        RECT  66.891 45.76 66.96 45.792 ;
    END
  END rce1[22]
  PIN rce1[230]
    DIRECTION INPUT ;
    USE SIGNAL ;
    PORT
      LAYER M6 ;
        RECT  66.891 61.12 66.96 61.152 ;
    END
  END rce1[230]
  PIN rce1[231]
    DIRECTION INPUT ;
    USE SIGNAL ;
    PORT
      LAYER M6 ;
        RECT  66.891 61.248 66.96 61.28 ;
    END
  END rce1[231]
  PIN rce1[232]
    DIRECTION INPUT ;
    USE SIGNAL ;
    PORT
      LAYER M6 ;
        RECT  66.891 61.376 66.96 61.408 ;
    END
  END rce1[232]
  PIN rce1[233]
    DIRECTION INPUT ;
    USE SIGNAL ;
    PORT
      LAYER M6 ;
        RECT  66.891 61.504 66.96 61.536 ;
    END
  END rce1[233]
  PIN rce1[234]
    DIRECTION INPUT ;
    USE SIGNAL ;
    PORT
      LAYER M6 ;
        RECT  66.891 61.632 66.96 61.664 ;
    END
  END rce1[234]
  PIN rce1[235]
    DIRECTION INPUT ;
    USE SIGNAL ;
    PORT
      LAYER M6 ;
        RECT  66.891 61.76 66.96 61.792 ;
    END
  END rce1[235]
  PIN rce1[236]
    DIRECTION INPUT ;
    USE SIGNAL ;
    PORT
      LAYER M6 ;
        RECT  66.891 61.888 66.96 61.92 ;
    END
  END rce1[236]
  PIN rce1[237]
    DIRECTION INPUT ;
    USE SIGNAL ;
    PORT
      LAYER M6 ;
        RECT  66.891 62.016 66.96 62.048 ;
    END
  END rce1[237]
  PIN rce1[238]
    DIRECTION INPUT ;
    USE SIGNAL ;
    PORT
      LAYER M6 ;
        RECT  66.891 62.144 66.96 62.176 ;
    END
  END rce1[238]
  PIN rce1[239]
    DIRECTION INPUT ;
    USE SIGNAL ;
    PORT
      LAYER M6 ;
        RECT  66.891 62.272 66.96 62.304 ;
    END
  END rce1[239]
  PIN rce1[23]
    DIRECTION INPUT ;
    USE SIGNAL ;
    PORT
      LAYER M6 ;
        RECT  66.891 45.888 66.96 45.92 ;
    END
  END rce1[23]
  PIN rce1[240]
    DIRECTION INPUT ;
    USE SIGNAL ;
    PORT
      LAYER M6 ;
        RECT  66.891 62.4 66.96 62.432 ;
    END
  END rce1[240]
  PIN rce1[241]
    DIRECTION INPUT ;
    USE SIGNAL ;
    PORT
      LAYER M6 ;
        RECT  66.891 62.528 66.96 62.56 ;
    END
  END rce1[241]
  PIN rce1[242]
    DIRECTION INPUT ;
    USE SIGNAL ;
    PORT
      LAYER M6 ;
        RECT  66.891 62.656 66.96 62.688 ;
    END
  END rce1[242]
  PIN rce1[243]
    DIRECTION INPUT ;
    USE SIGNAL ;
    PORT
      LAYER M6 ;
        RECT  66.891 62.784 66.96 62.816 ;
    END
  END rce1[243]
  PIN rce1[244]
    DIRECTION INPUT ;
    USE SIGNAL ;
    PORT
      LAYER M6 ;
        RECT  66.891 62.912 66.96 62.944 ;
    END
  END rce1[244]
  PIN rce1[245]
    DIRECTION INPUT ;
    USE SIGNAL ;
    PORT
      LAYER M6 ;
        RECT  66.891 63.04 66.96 63.072 ;
    END
  END rce1[245]
  PIN rce1[246]
    DIRECTION INPUT ;
    USE SIGNAL ;
    PORT
      LAYER M6 ;
        RECT  66.891 63.168 66.96 63.2 ;
    END
  END rce1[246]
  PIN rce1[247]
    DIRECTION INPUT ;
    USE SIGNAL ;
    PORT
      LAYER M6 ;
        RECT  66.891 63.296 66.96 63.328 ;
    END
  END rce1[247]
  PIN rce1[248]
    DIRECTION INPUT ;
    USE SIGNAL ;
    PORT
      LAYER M6 ;
        RECT  66.891 63.424 66.96 63.456 ;
    END
  END rce1[248]
  PIN rce1[249]
    DIRECTION INPUT ;
    USE SIGNAL ;
    PORT
      LAYER M6 ;
        RECT  66.891 63.552 66.96 63.584 ;
    END
  END rce1[249]
  PIN rce1[24]
    DIRECTION INPUT ;
    USE SIGNAL ;
    PORT
      LAYER M6 ;
        RECT  66.891 46.016 66.96 46.048 ;
    END
  END rce1[24]
  PIN rce1[250]
    DIRECTION INPUT ;
    USE SIGNAL ;
    PORT
      LAYER M6 ;
        RECT  66.891 63.68 66.96 63.712 ;
    END
  END rce1[250]
  PIN rce1[251]
    DIRECTION INPUT ;
    USE SIGNAL ;
    PORT
      LAYER M6 ;
        RECT  66.891 63.808 66.96 63.84 ;
    END
  END rce1[251]
  PIN rce1[252]
    DIRECTION INPUT ;
    USE SIGNAL ;
    PORT
      LAYER M6 ;
        RECT  66.891 63.936 66.96 63.968 ;
    END
  END rce1[252]
  PIN rce1[253]
    DIRECTION INPUT ;
    USE SIGNAL ;
    PORT
      LAYER M6 ;
        RECT  66.891 64.064 66.96 64.096 ;
    END
  END rce1[253]
  PIN rce1[254]
    DIRECTION INPUT ;
    USE SIGNAL ;
    PORT
      LAYER M6 ;
        RECT  66.891 64.192 66.96 64.224 ;
    END
  END rce1[254]
  PIN rce1[255]
    DIRECTION INPUT ;
    USE SIGNAL ;
    PORT
      LAYER M6 ;
        RECT  66.891 64.32 66.96 64.352 ;
    END
  END rce1[255]
  PIN rce1[256]
    DIRECTION INPUT ;
    USE SIGNAL ;
    PORT
      LAYER M4 ;
        RECT  66.876 48.336 66.96 48.36 ;
    END
  END rce1[256]
  PIN rce1[257]
    DIRECTION INPUT ;
    USE SIGNAL ;
    PORT
      LAYER M4 ;
        RECT  66.876 48.432 66.96 48.456 ;
    END
  END rce1[257]
  PIN rce1[258]
    DIRECTION INPUT ;
    USE SIGNAL ;
    PORT
      LAYER M4 ;
        RECT  66.876 48.528 66.96 48.552 ;
    END
  END rce1[258]
  PIN rce1[259]
    DIRECTION INPUT ;
    USE SIGNAL ;
    PORT
      LAYER M4 ;
        RECT  66.876 48.624 66.96 48.648 ;
    END
  END rce1[259]
  PIN rce1[25]
    DIRECTION INPUT ;
    USE SIGNAL ;
    PORT
      LAYER M6 ;
        RECT  66.891 46.144 66.96 46.176 ;
    END
  END rce1[25]
  PIN rce1[260]
    DIRECTION INPUT ;
    USE SIGNAL ;
    PORT
      LAYER M4 ;
        RECT  66.876 48.72 66.96 48.744 ;
    END
  END rce1[260]
  PIN rce1[261]
    DIRECTION INPUT ;
    USE SIGNAL ;
    PORT
      LAYER M4 ;
        RECT  66.876 48.816 66.96 48.84 ;
    END
  END rce1[261]
  PIN rce1[262]
    DIRECTION INPUT ;
    USE SIGNAL ;
    PORT
      LAYER M4 ;
        RECT  66.876 48.912 66.96 48.936 ;
    END
  END rce1[262]
  PIN rce1[263]
    DIRECTION INPUT ;
    USE SIGNAL ;
    PORT
      LAYER M4 ;
        RECT  66.876 49.008 66.96 49.032 ;
    END
  END rce1[263]
  PIN rce1[264]
    DIRECTION INPUT ;
    USE SIGNAL ;
    PORT
      LAYER M4 ;
        RECT  66.876 49.104 66.96 49.128 ;
    END
  END rce1[264]
  PIN rce1[265]
    DIRECTION INPUT ;
    USE SIGNAL ;
    PORT
      LAYER M4 ;
        RECT  66.876 49.2 66.96 49.224 ;
    END
  END rce1[265]
  PIN rce1[266]
    DIRECTION INPUT ;
    USE SIGNAL ;
    PORT
      LAYER M4 ;
        RECT  66.876 49.296 66.96 49.32 ;
    END
  END rce1[266]
  PIN rce1[267]
    DIRECTION INPUT ;
    USE SIGNAL ;
    PORT
      LAYER M4 ;
        RECT  66.876 49.392 66.96 49.416 ;
    END
  END rce1[267]
  PIN rce1[268]
    DIRECTION INPUT ;
    USE SIGNAL ;
    PORT
      LAYER M4 ;
        RECT  66.876 49.488 66.96 49.512 ;
    END
  END rce1[268]
  PIN rce1[269]
    DIRECTION INPUT ;
    USE SIGNAL ;
    PORT
      LAYER M4 ;
        RECT  66.876 49.584 66.96 49.608 ;
    END
  END rce1[269]
  PIN rce1[26]
    DIRECTION INPUT ;
    USE SIGNAL ;
    PORT
      LAYER M6 ;
        RECT  66.891 46.272 66.96 46.304 ;
    END
  END rce1[26]
  PIN rce1[270]
    DIRECTION INPUT ;
    USE SIGNAL ;
    PORT
      LAYER M4 ;
        RECT  66.876 49.68 66.96 49.704 ;
    END
  END rce1[270]
  PIN rce1[271]
    DIRECTION INPUT ;
    USE SIGNAL ;
    PORT
      LAYER M4 ;
        RECT  66.876 49.776 66.96 49.8 ;
    END
  END rce1[271]
  PIN rce1[272]
    DIRECTION INPUT ;
    USE SIGNAL ;
    PORT
      LAYER M4 ;
        RECT  66.876 49.872 66.96 49.896 ;
    END
  END rce1[272]
  PIN rce1[273]
    DIRECTION INPUT ;
    USE SIGNAL ;
    PORT
      LAYER M4 ;
        RECT  66.876 49.968 66.96 49.992 ;
    END
  END rce1[273]
  PIN rce1[274]
    DIRECTION INPUT ;
    USE SIGNAL ;
    PORT
      LAYER M4 ;
        RECT  66.876 50.064 66.96 50.088 ;
    END
  END rce1[274]
  PIN rce1[275]
    DIRECTION INPUT ;
    USE SIGNAL ;
    PORT
      LAYER M4 ;
        RECT  66.876 50.16 66.96 50.184 ;
    END
  END rce1[275]
  PIN rce1[276]
    DIRECTION INPUT ;
    USE SIGNAL ;
    PORT
      LAYER M4 ;
        RECT  66.876 50.256 66.96 50.28 ;
    END
  END rce1[276]
  PIN rce1[277]
    DIRECTION INPUT ;
    USE SIGNAL ;
    PORT
      LAYER M4 ;
        RECT  66.876 50.352 66.96 50.376 ;
    END
  END rce1[277]
  PIN rce1[278]
    DIRECTION INPUT ;
    USE SIGNAL ;
    PORT
      LAYER M4 ;
        RECT  66.876 50.448 66.96 50.472 ;
    END
  END rce1[278]
  PIN rce1[279]
    DIRECTION INPUT ;
    USE SIGNAL ;
    PORT
      LAYER M4 ;
        RECT  66.876 50.544 66.96 50.568 ;
    END
  END rce1[279]
  PIN rce1[27]
    DIRECTION INPUT ;
    USE SIGNAL ;
    PORT
      LAYER M6 ;
        RECT  66.891 46.4 66.96 46.432 ;
    END
  END rce1[27]
  PIN rce1[280]
    DIRECTION INPUT ;
    USE SIGNAL ;
    PORT
      LAYER M4 ;
        RECT  66.876 50.64 66.96 50.664 ;
    END
  END rce1[280]
  PIN rce1[281]
    DIRECTION INPUT ;
    USE SIGNAL ;
    PORT
      LAYER M4 ;
        RECT  66.876 50.736 66.96 50.76 ;
    END
  END rce1[281]
  PIN rce1[282]
    DIRECTION INPUT ;
    USE SIGNAL ;
    PORT
      LAYER M4 ;
        RECT  66.876 50.832 66.96 50.856 ;
    END
  END rce1[282]
  PIN rce1[283]
    DIRECTION INPUT ;
    USE SIGNAL ;
    PORT
      LAYER M4 ;
        RECT  66.876 50.928 66.96 50.952 ;
    END
  END rce1[283]
  PIN rce1[284]
    DIRECTION INPUT ;
    USE SIGNAL ;
    PORT
      LAYER M4 ;
        RECT  66.876 51.024 66.96 51.048 ;
    END
  END rce1[284]
  PIN rce1[285]
    DIRECTION INPUT ;
    USE SIGNAL ;
    PORT
      LAYER M4 ;
        RECT  66.876 51.12 66.96 51.144 ;
    END
  END rce1[285]
  PIN rce1[286]
    DIRECTION INPUT ;
    USE SIGNAL ;
    PORT
      LAYER M4 ;
        RECT  66.876 51.216 66.96 51.24 ;
    END
  END rce1[286]
  PIN rce1[287]
    DIRECTION INPUT ;
    USE SIGNAL ;
    PORT
      LAYER M4 ;
        RECT  66.876 51.312 66.96 51.336 ;
    END
  END rce1[287]
  PIN rce1[28]
    DIRECTION INPUT ;
    USE SIGNAL ;
    PORT
      LAYER M6 ;
        RECT  66.891 46.528 66.96 46.56 ;
    END
  END rce1[28]
  PIN rce1[29]
    DIRECTION INPUT ;
    USE SIGNAL ;
    PORT
      LAYER M6 ;
        RECT  66.891 46.656 66.96 46.688 ;
    END
  END rce1[29]
  PIN rce1[2]
    DIRECTION INPUT ;
    USE SIGNAL ;
    PORT
      LAYER M6 ;
        RECT  66.891 43.2 66.96 43.232 ;
    END
  END rce1[2]
  PIN rce1[30]
    DIRECTION INPUT ;
    USE SIGNAL ;
    PORT
      LAYER M6 ;
        RECT  66.891 46.784 66.96 46.816 ;
    END
  END rce1[30]
  PIN rce1[31]
    DIRECTION INPUT ;
    USE SIGNAL ;
    PORT
      LAYER M6 ;
        RECT  66.891 46.912 66.96 46.944 ;
    END
  END rce1[31]
  PIN rce1[32]
    DIRECTION INPUT ;
    USE SIGNAL ;
    PORT
      LAYER M4 ;
        RECT  66.876 32.208 66.96 32.232 ;
    END
  END rce1[32]
  PIN rce1[33]
    DIRECTION INPUT ;
    USE SIGNAL ;
    PORT
      LAYER M4 ;
        RECT  66.876 32.304 66.96 32.328 ;
    END
  END rce1[33]
  PIN rce1[34]
    DIRECTION INPUT ;
    USE SIGNAL ;
    PORT
      LAYER M4 ;
        RECT  66.876 32.4 66.96 32.424 ;
    END
  END rce1[34]
  PIN rce1[35]
    DIRECTION INPUT ;
    USE SIGNAL ;
    PORT
      LAYER M4 ;
        RECT  66.876 32.496 66.96 32.52 ;
    END
  END rce1[35]
  PIN rce1[36]
    DIRECTION INPUT ;
    USE SIGNAL ;
    PORT
      LAYER M4 ;
        RECT  66.876 32.592 66.96 32.616 ;
    END
  END rce1[36]
  PIN rce1[37]
    DIRECTION INPUT ;
    USE SIGNAL ;
    PORT
      LAYER M4 ;
        RECT  66.876 32.688 66.96 32.712 ;
    END
  END rce1[37]
  PIN rce1[38]
    DIRECTION INPUT ;
    USE SIGNAL ;
    PORT
      LAYER M4 ;
        RECT  66.876 32.784 66.96 32.808 ;
    END
  END rce1[38]
  PIN rce1[39]
    DIRECTION INPUT ;
    USE SIGNAL ;
    PORT
      LAYER M4 ;
        RECT  66.876 32.88 66.96 32.904 ;
    END
  END rce1[39]
  PIN rce1[3]
    DIRECTION INPUT ;
    USE SIGNAL ;
    PORT
      LAYER M6 ;
        RECT  66.891 43.328 66.96 43.36 ;
    END
  END rce1[3]
  PIN rce1[40]
    DIRECTION INPUT ;
    USE SIGNAL ;
    PORT
      LAYER M4 ;
        RECT  66.876 32.976 66.96 33 ;
    END
  END rce1[40]
  PIN rce1[41]
    DIRECTION INPUT ;
    USE SIGNAL ;
    PORT
      LAYER M4 ;
        RECT  66.876 33.072 66.96 33.096 ;
    END
  END rce1[41]
  PIN rce1[42]
    DIRECTION INPUT ;
    USE SIGNAL ;
    PORT
      LAYER M4 ;
        RECT  66.876 33.168 66.96 33.192 ;
    END
  END rce1[42]
  PIN rce1[43]
    DIRECTION INPUT ;
    USE SIGNAL ;
    PORT
      LAYER M4 ;
        RECT  66.876 33.264 66.96 33.288 ;
    END
  END rce1[43]
  PIN rce1[44]
    DIRECTION INPUT ;
    USE SIGNAL ;
    PORT
      LAYER M4 ;
        RECT  66.876 33.36 66.96 33.384 ;
    END
  END rce1[44]
  PIN rce1[45]
    DIRECTION INPUT ;
    USE SIGNAL ;
    PORT
      LAYER M4 ;
        RECT  66.876 33.456 66.96 33.48 ;
    END
  END rce1[45]
  PIN rce1[46]
    DIRECTION INPUT ;
    USE SIGNAL ;
    PORT
      LAYER M4 ;
        RECT  66.876 33.552 66.96 33.576 ;
    END
  END rce1[46]
  PIN rce1[47]
    DIRECTION INPUT ;
    USE SIGNAL ;
    PORT
      LAYER M4 ;
        RECT  66.876 33.648 66.96 33.672 ;
    END
  END rce1[47]
  PIN rce1[48]
    DIRECTION INPUT ;
    USE SIGNAL ;
    PORT
      LAYER M4 ;
        RECT  66.876 33.744 66.96 33.768 ;
    END
  END rce1[48]
  PIN rce1[49]
    DIRECTION INPUT ;
    USE SIGNAL ;
    PORT
      LAYER M4 ;
        RECT  66.876 33.84 66.96 33.864 ;
    END
  END rce1[49]
  PIN rce1[4]
    DIRECTION INPUT ;
    USE SIGNAL ;
    PORT
      LAYER M6 ;
        RECT  66.891 43.456 66.96 43.488 ;
    END
  END rce1[4]
  PIN rce1[50]
    DIRECTION INPUT ;
    USE SIGNAL ;
    PORT
      LAYER M4 ;
        RECT  66.876 33.936 66.96 33.96 ;
    END
  END rce1[50]
  PIN rce1[51]
    DIRECTION INPUT ;
    USE SIGNAL ;
    PORT
      LAYER M4 ;
        RECT  66.876 34.032 66.96 34.056 ;
    END
  END rce1[51]
  PIN rce1[52]
    DIRECTION INPUT ;
    USE SIGNAL ;
    PORT
      LAYER M4 ;
        RECT  66.876 34.128 66.96 34.152 ;
    END
  END rce1[52]
  PIN rce1[53]
    DIRECTION INPUT ;
    USE SIGNAL ;
    PORT
      LAYER M4 ;
        RECT  66.876 34.224 66.96 34.248 ;
    END
  END rce1[53]
  PIN rce1[54]
    DIRECTION INPUT ;
    USE SIGNAL ;
    PORT
      LAYER M4 ;
        RECT  66.876 34.32 66.96 34.344 ;
    END
  END rce1[54]
  PIN rce1[55]
    DIRECTION INPUT ;
    USE SIGNAL ;
    PORT
      LAYER M4 ;
        RECT  66.876 34.416 66.96 34.44 ;
    END
  END rce1[55]
  PIN rce1[56]
    DIRECTION INPUT ;
    USE SIGNAL ;
    PORT
      LAYER M4 ;
        RECT  66.876 34.512 66.96 34.536 ;
    END
  END rce1[56]
  PIN rce1[57]
    DIRECTION INPUT ;
    USE SIGNAL ;
    PORT
      LAYER M4 ;
        RECT  66.876 34.608 66.96 34.632 ;
    END
  END rce1[57]
  PIN rce1[58]
    DIRECTION INPUT ;
    USE SIGNAL ;
    PORT
      LAYER M4 ;
        RECT  66.876 34.704 66.96 34.728 ;
    END
  END rce1[58]
  PIN rce1[59]
    DIRECTION INPUT ;
    USE SIGNAL ;
    PORT
      LAYER M4 ;
        RECT  66.876 34.8 66.96 34.824 ;
    END
  END rce1[59]
  PIN rce1[5]
    DIRECTION INPUT ;
    USE SIGNAL ;
    PORT
      LAYER M6 ;
        RECT  66.891 43.584 66.96 43.616 ;
    END
  END rce1[5]
  PIN rce1[60]
    DIRECTION INPUT ;
    USE SIGNAL ;
    PORT
      LAYER M4 ;
        RECT  66.876 34.896 66.96 34.92 ;
    END
  END rce1[60]
  PIN rce1[61]
    DIRECTION INPUT ;
    USE SIGNAL ;
    PORT
      LAYER M4 ;
        RECT  66.876 34.992 66.96 35.016 ;
    END
  END rce1[61]
  PIN rce1[62]
    DIRECTION INPUT ;
    USE SIGNAL ;
    PORT
      LAYER M4 ;
        RECT  66.876 35.088 66.96 35.112 ;
    END
  END rce1[62]
  PIN rce1[63]
    DIRECTION INPUT ;
    USE SIGNAL ;
    PORT
      LAYER M4 ;
        RECT  66.876 35.184 66.96 35.208 ;
    END
  END rce1[63]
  PIN rce1[64]
    DIRECTION INPUT ;
    USE SIGNAL ;
    PORT
      LAYER M4 ;
        RECT  66.876 9.936 66.96 9.96 ;
    END
  END rce1[64]
  PIN rce1[65]
    DIRECTION INPUT ;
    USE SIGNAL ;
    PORT
      LAYER M4 ;
        RECT  66.876 10.032 66.96 10.056 ;
    END
  END rce1[65]
  PIN rce1[66]
    DIRECTION INPUT ;
    USE SIGNAL ;
    PORT
      LAYER M4 ;
        RECT  66.876 10.128 66.96 10.152 ;
    END
  END rce1[66]
  PIN rce1[67]
    DIRECTION INPUT ;
    USE SIGNAL ;
    PORT
      LAYER M4 ;
        RECT  66.876 10.224 66.96 10.248 ;
    END
  END rce1[67]
  PIN rce1[68]
    DIRECTION INPUT ;
    USE SIGNAL ;
    PORT
      LAYER M4 ;
        RECT  66.876 10.32 66.96 10.344 ;
    END
  END rce1[68]
  PIN rce1[69]
    DIRECTION INPUT ;
    USE SIGNAL ;
    PORT
      LAYER M4 ;
        RECT  66.876 10.416 66.96 10.44 ;
    END
  END rce1[69]
  PIN rce1[6]
    DIRECTION INPUT ;
    USE SIGNAL ;
    PORT
      LAYER M6 ;
        RECT  66.891 43.712 66.96 43.744 ;
    END
  END rce1[6]
  PIN rce1[70]
    DIRECTION INPUT ;
    USE SIGNAL ;
    PORT
      LAYER M4 ;
        RECT  66.876 10.512 66.96 10.536 ;
    END
  END rce1[70]
  PIN rce1[71]
    DIRECTION INPUT ;
    USE SIGNAL ;
    PORT
      LAYER M4 ;
        RECT  66.876 10.608 66.96 10.632 ;
    END
  END rce1[71]
  PIN rce1[72]
    DIRECTION INPUT ;
    USE SIGNAL ;
    PORT
      LAYER M4 ;
        RECT  66.876 10.704 66.96 10.728 ;
    END
  END rce1[72]
  PIN rce1[73]
    DIRECTION INPUT ;
    USE SIGNAL ;
    PORT
      LAYER M4 ;
        RECT  66.876 10.8 66.96 10.824 ;
    END
  END rce1[73]
  PIN rce1[74]
    DIRECTION INPUT ;
    USE SIGNAL ;
    PORT
      LAYER M4 ;
        RECT  66.876 10.896 66.96 10.92 ;
    END
  END rce1[74]
  PIN rce1[75]
    DIRECTION INPUT ;
    USE SIGNAL ;
    PORT
      LAYER M4 ;
        RECT  66.876 10.992 66.96 11.016 ;
    END
  END rce1[75]
  PIN rce1[76]
    DIRECTION INPUT ;
    USE SIGNAL ;
    PORT
      LAYER M4 ;
        RECT  66.876 11.088 66.96 11.112 ;
    END
  END rce1[76]
  PIN rce1[77]
    DIRECTION INPUT ;
    USE SIGNAL ;
    PORT
      LAYER M4 ;
        RECT  66.876 11.184 66.96 11.208 ;
    END
  END rce1[77]
  PIN rce1[78]
    DIRECTION INPUT ;
    USE SIGNAL ;
    PORT
      LAYER M4 ;
        RECT  66.876 11.28 66.96 11.304 ;
    END
  END rce1[78]
  PIN rce1[79]
    DIRECTION INPUT ;
    USE SIGNAL ;
    PORT
      LAYER M4 ;
        RECT  66.876 11.376 66.96 11.4 ;
    END
  END rce1[79]
  PIN rce1[7]
    DIRECTION INPUT ;
    USE SIGNAL ;
    PORT
      LAYER M6 ;
        RECT  66.891 43.84 66.96 43.872 ;
    END
  END rce1[7]
  PIN rce1[80]
    DIRECTION INPUT ;
    USE SIGNAL ;
    PORT
      LAYER M4 ;
        RECT  66.876 11.472 66.96 11.496 ;
    END
  END rce1[80]
  PIN rce1[81]
    DIRECTION INPUT ;
    USE SIGNAL ;
    PORT
      LAYER M4 ;
        RECT  66.876 11.568 66.96 11.592 ;
    END
  END rce1[81]
  PIN rce1[82]
    DIRECTION INPUT ;
    USE SIGNAL ;
    PORT
      LAYER M4 ;
        RECT  66.876 11.664 66.96 11.688 ;
    END
  END rce1[82]
  PIN rce1[83]
    DIRECTION INPUT ;
    USE SIGNAL ;
    PORT
      LAYER M4 ;
        RECT  66.876 11.76 66.96 11.784 ;
    END
  END rce1[83]
  PIN rce1[84]
    DIRECTION INPUT ;
    USE SIGNAL ;
    PORT
      LAYER M4 ;
        RECT  66.876 11.856 66.96 11.88 ;
    END
  END rce1[84]
  PIN rce1[85]
    DIRECTION INPUT ;
    USE SIGNAL ;
    PORT
      LAYER M4 ;
        RECT  66.876 11.952 66.96 11.976 ;
    END
  END rce1[85]
  PIN rce1[86]
    DIRECTION INPUT ;
    USE SIGNAL ;
    PORT
      LAYER M4 ;
        RECT  66.876 12.048 66.96 12.072 ;
    END
  END rce1[86]
  PIN rce1[87]
    DIRECTION INPUT ;
    USE SIGNAL ;
    PORT
      LAYER M4 ;
        RECT  66.876 12.144 66.96 12.168 ;
    END
  END rce1[87]
  PIN rce1[88]
    DIRECTION INPUT ;
    USE SIGNAL ;
    PORT
      LAYER M4 ;
        RECT  66.876 12.24 66.96 12.264 ;
    END
  END rce1[88]
  PIN rce1[89]
    DIRECTION INPUT ;
    USE SIGNAL ;
    PORT
      LAYER M4 ;
        RECT  66.876 12.336 66.96 12.36 ;
    END
  END rce1[89]
  PIN rce1[8]
    DIRECTION INPUT ;
    USE SIGNAL ;
    PORT
      LAYER M6 ;
        RECT  66.891 43.968 66.96 44 ;
    END
  END rce1[8]
  PIN rce1[90]
    DIRECTION INPUT ;
    USE SIGNAL ;
    PORT
      LAYER M4 ;
        RECT  66.876 12.432 66.96 12.456 ;
    END
  END rce1[90]
  PIN rce1[91]
    DIRECTION INPUT ;
    USE SIGNAL ;
    PORT
      LAYER M4 ;
        RECT  66.876 12.528 66.96 12.552 ;
    END
  END rce1[91]
  PIN rce1[92]
    DIRECTION INPUT ;
    USE SIGNAL ;
    PORT
      LAYER M4 ;
        RECT  66.876 12.624 66.96 12.648 ;
    END
  END rce1[92]
  PIN rce1[93]
    DIRECTION INPUT ;
    USE SIGNAL ;
    PORT
      LAYER M4 ;
        RECT  66.876 12.72 66.96 12.744 ;
    END
  END rce1[93]
  PIN rce1[94]
    DIRECTION INPUT ;
    USE SIGNAL ;
    PORT
      LAYER M4 ;
        RECT  66.876 12.816 66.96 12.84 ;
    END
  END rce1[94]
  PIN rce1[95]
    DIRECTION INPUT ;
    USE SIGNAL ;
    PORT
      LAYER M4 ;
        RECT  66.876 12.912 66.96 12.936 ;
    END
  END rce1[95]
  PIN rce1[96]
    DIRECTION INPUT ;
    USE SIGNAL ;
    PORT
      LAYER M4 ;
        RECT  66.876 13.008 66.96 13.032 ;
    END
  END rce1[96]
  PIN rce1[97]
    DIRECTION INPUT ;
    USE SIGNAL ;
    PORT
      LAYER M4 ;
        RECT  66.876 13.104 66.96 13.128 ;
    END
  END rce1[97]
  PIN rce1[98]
    DIRECTION INPUT ;
    USE SIGNAL ;
    PORT
      LAYER M4 ;
        RECT  66.876 13.2 66.96 13.224 ;
    END
  END rce1[98]
  PIN rce1[99]
    DIRECTION INPUT ;
    USE SIGNAL ;
    PORT
      LAYER M4 ;
        RECT  66.876 13.296 66.96 13.32 ;
    END
  END rce1[99]
  PIN rce1[9]
    DIRECTION INPUT ;
    USE SIGNAL ;
    PORT
      LAYER M6 ;
        RECT  66.891 44.096 66.96 44.128 ;
    END
  END rce1[9]
  PIN rce1_cr
    DIRECTION OUTPUT ;
    USE SIGNAL ;
    PORT
      LAYER M6 ;
        RECT  66.891 38.848 66.96 38.88 ;
    END
  END rce1_cr
  PIN ri0[0]
    DIRECTION OUTPUT ;
    USE SIGNAL ;
    PORT
      LAYER M4 ;
        RECT  0 37.968 0.084 37.992 ;
    END
  END ri0[0]
  PIN ri0[100]
    DIRECTION OUTPUT ;
    USE SIGNAL ;
    PORT
      LAYER M4 ;
        RECT  0 6.096 0.084 6.12 ;
    END
  END ri0[100]
  PIN ri0[101]
    DIRECTION OUTPUT ;
    USE SIGNAL ;
    PORT
      LAYER M4 ;
        RECT  0 6.192 0.084 6.216 ;
    END
  END ri0[101]
  PIN ri0[102]
    DIRECTION OUTPUT ;
    USE SIGNAL ;
    PORT
      LAYER M4 ;
        RECT  0 6.288 0.084 6.312 ;
    END
  END ri0[102]
  PIN ri0[103]
    DIRECTION OUTPUT ;
    USE SIGNAL ;
    PORT
      LAYER M4 ;
        RECT  0 6.384 0.084 6.408 ;
    END
  END ri0[103]
  PIN ri0[104]
    DIRECTION OUTPUT ;
    USE SIGNAL ;
    PORT
      LAYER M4 ;
        RECT  0 6.48 0.084 6.504 ;
    END
  END ri0[104]
  PIN ri0[105]
    DIRECTION OUTPUT ;
    USE SIGNAL ;
    PORT
      LAYER M4 ;
        RECT  0 6.576 0.084 6.6 ;
    END
  END ri0[105]
  PIN ri0[106]
    DIRECTION OUTPUT ;
    USE SIGNAL ;
    PORT
      LAYER M4 ;
        RECT  0 6.672 0.084 6.696 ;
    END
  END ri0[106]
  PIN ri0[107]
    DIRECTION OUTPUT ;
    USE SIGNAL ;
    PORT
      LAYER M4 ;
        RECT  0 6.768 0.084 6.792 ;
    END
  END ri0[107]
  PIN ri0[108]
    DIRECTION OUTPUT ;
    USE SIGNAL ;
    PORT
      LAYER M4 ;
        RECT  0 6.864 0.084 6.888 ;
    END
  END ri0[108]
  PIN ri0[109]
    DIRECTION OUTPUT ;
    USE SIGNAL ;
    PORT
      LAYER M4 ;
        RECT  0 6.96 0.084 6.984 ;
    END
  END ri0[109]
  PIN ri0[10]
    DIRECTION OUTPUT ;
    USE SIGNAL ;
    PORT
      LAYER M4 ;
        RECT  0 38.928 0.084 38.952 ;
    END
  END ri0[10]
  PIN ri0[110]
    DIRECTION OUTPUT ;
    USE SIGNAL ;
    PORT
      LAYER M4 ;
        RECT  0 7.056 0.084 7.08 ;
    END
  END ri0[110]
  PIN ri0[111]
    DIRECTION OUTPUT ;
    USE SIGNAL ;
    PORT
      LAYER M4 ;
        RECT  0 7.152 0.084 7.176 ;
    END
  END ri0[111]
  PIN ri0[112]
    DIRECTION OUTPUT ;
    USE SIGNAL ;
    PORT
      LAYER M4 ;
        RECT  0 7.248 0.084 7.272 ;
    END
  END ri0[112]
  PIN ri0[113]
    DIRECTION OUTPUT ;
    USE SIGNAL ;
    PORT
      LAYER M4 ;
        RECT  0 7.344 0.084 7.368 ;
    END
  END ri0[113]
  PIN ri0[114]
    DIRECTION OUTPUT ;
    USE SIGNAL ;
    PORT
      LAYER M4 ;
        RECT  0 7.44 0.084 7.464 ;
    END
  END ri0[114]
  PIN ri0[115]
    DIRECTION OUTPUT ;
    USE SIGNAL ;
    PORT
      LAYER M4 ;
        RECT  0 7.536 0.084 7.56 ;
    END
  END ri0[115]
  PIN ri0[116]
    DIRECTION OUTPUT ;
    USE SIGNAL ;
    PORT
      LAYER M4 ;
        RECT  0 7.632 0.084 7.656 ;
    END
  END ri0[116]
  PIN ri0[117]
    DIRECTION OUTPUT ;
    USE SIGNAL ;
    PORT
      LAYER M4 ;
        RECT  0 7.728 0.084 7.752 ;
    END
  END ri0[117]
  PIN ri0[118]
    DIRECTION OUTPUT ;
    USE SIGNAL ;
    PORT
      LAYER M4 ;
        RECT  0 7.824 0.084 7.848 ;
    END
  END ri0[118]
  PIN ri0[119]
    DIRECTION OUTPUT ;
    USE SIGNAL ;
    PORT
      LAYER M4 ;
        RECT  0 7.92 0.084 7.944 ;
    END
  END ri0[119]
  PIN ri0[11]
    DIRECTION OUTPUT ;
    USE SIGNAL ;
    PORT
      LAYER M4 ;
        RECT  0 39.024 0.084 39.048 ;
    END
  END ri0[11]
  PIN ri0[120]
    DIRECTION OUTPUT ;
    USE SIGNAL ;
    PORT
      LAYER M4 ;
        RECT  0 8.016 0.084 8.04 ;
    END
  END ri0[120]
  PIN ri0[121]
    DIRECTION OUTPUT ;
    USE SIGNAL ;
    PORT
      LAYER M4 ;
        RECT  0 8.112 0.084 8.136 ;
    END
  END ri0[121]
  PIN ri0[122]
    DIRECTION OUTPUT ;
    USE SIGNAL ;
    PORT
      LAYER M4 ;
        RECT  0 8.208 0.084 8.232 ;
    END
  END ri0[122]
  PIN ri0[123]
    DIRECTION OUTPUT ;
    USE SIGNAL ;
    PORT
      LAYER M4 ;
        RECT  0 8.304 0.084 8.328 ;
    END
  END ri0[123]
  PIN ri0[124]
    DIRECTION OUTPUT ;
    USE SIGNAL ;
    PORT
      LAYER M4 ;
        RECT  0 8.4 0.084 8.424 ;
    END
  END ri0[124]
  PIN ri0[125]
    DIRECTION OUTPUT ;
    USE SIGNAL ;
    PORT
      LAYER M4 ;
        RECT  0 8.496 0.084 8.52 ;
    END
  END ri0[125]
  PIN ri0[126]
    DIRECTION OUTPUT ;
    USE SIGNAL ;
    PORT
      LAYER M4 ;
        RECT  0 8.592 0.084 8.616 ;
    END
  END ri0[126]
  PIN ri0[127]
    DIRECTION OUTPUT ;
    USE SIGNAL ;
    PORT
      LAYER M6 ;
        RECT  0 6.592 0.069 6.624 ;
    END
  END ri0[127]
  PIN ri0[128]
    DIRECTION OUTPUT ;
    USE SIGNAL ;
    PORT
      LAYER M6 ;
        RECT  0 6.72 0.069 6.752 ;
    END
  END ri0[128]
  PIN ri0[129]
    DIRECTION OUTPUT ;
    USE SIGNAL ;
    PORT
      LAYER M6 ;
        RECT  0 6.848 0.069 6.88 ;
    END
  END ri0[129]
  PIN ri0[12]
    DIRECTION OUTPUT ;
    USE SIGNAL ;
    PORT
      LAYER M4 ;
        RECT  0 39.12 0.084 39.144 ;
    END
  END ri0[12]
  PIN ri0[130]
    DIRECTION OUTPUT ;
    USE SIGNAL ;
    PORT
      LAYER M6 ;
        RECT  0 6.976 0.069 7.008 ;
    END
  END ri0[130]
  PIN ri0[131]
    DIRECTION OUTPUT ;
    USE SIGNAL ;
    PORT
      LAYER M6 ;
        RECT  0 7.104 0.069 7.136 ;
    END
  END ri0[131]
  PIN ri0[132]
    DIRECTION OUTPUT ;
    USE SIGNAL ;
    PORT
      LAYER M6 ;
        RECT  0 7.232 0.069 7.264 ;
    END
  END ri0[132]
  PIN ri0[133]
    DIRECTION OUTPUT ;
    USE SIGNAL ;
    PORT
      LAYER M6 ;
        RECT  0 7.36 0.069 7.392 ;
    END
  END ri0[133]
  PIN ri0[134]
    DIRECTION OUTPUT ;
    USE SIGNAL ;
    PORT
      LAYER M6 ;
        RECT  0 7.488 0.069 7.52 ;
    END
  END ri0[134]
  PIN ri0[135]
    DIRECTION OUTPUT ;
    USE SIGNAL ;
    PORT
      LAYER M6 ;
        RECT  0 7.616 0.069 7.648 ;
    END
  END ri0[135]
  PIN ri0[136]
    DIRECTION OUTPUT ;
    USE SIGNAL ;
    PORT
      LAYER M6 ;
        RECT  0 7.744 0.069 7.776 ;
    END
  END ri0[136]
  PIN ri0[137]
    DIRECTION OUTPUT ;
    USE SIGNAL ;
    PORT
      LAYER M6 ;
        RECT  0 7.872 0.069 7.904 ;
    END
  END ri0[137]
  PIN ri0[138]
    DIRECTION OUTPUT ;
    USE SIGNAL ;
    PORT
      LAYER M6 ;
        RECT  0 8 0.069 8.032 ;
    END
  END ri0[138]
  PIN ri0[139]
    DIRECTION OUTPUT ;
    USE SIGNAL ;
    PORT
      LAYER M6 ;
        RECT  0 8.128 0.069 8.16 ;
    END
  END ri0[139]
  PIN ri0[13]
    DIRECTION OUTPUT ;
    USE SIGNAL ;
    PORT
      LAYER M4 ;
        RECT  0 39.216 0.084 39.24 ;
    END
  END ri0[13]
  PIN ri0[140]
    DIRECTION OUTPUT ;
    USE SIGNAL ;
    PORT
      LAYER M6 ;
        RECT  0 8.256 0.069 8.288 ;
    END
  END ri0[140]
  PIN ri0[141]
    DIRECTION OUTPUT ;
    USE SIGNAL ;
    PORT
      LAYER M6 ;
        RECT  0 8.384 0.069 8.416 ;
    END
  END ri0[141]
  PIN ri0[142]
    DIRECTION OUTPUT ;
    USE SIGNAL ;
    PORT
      LAYER M6 ;
        RECT  0 8.512 0.069 8.544 ;
    END
  END ri0[142]
  PIN ri0[143]
    DIRECTION OUTPUT ;
    USE SIGNAL ;
    PORT
      LAYER M6 ;
        RECT  0 8.64 0.069 8.672 ;
    END
  END ri0[143]
  PIN ri0[144]
    DIRECTION OUTPUT ;
    USE SIGNAL ;
    PORT
      LAYER M6 ;
        RECT  0 8.768 0.069 8.8 ;
    END
  END ri0[144]
  PIN ri0[145]
    DIRECTION OUTPUT ;
    USE SIGNAL ;
    PORT
      LAYER M6 ;
        RECT  0 8.896 0.069 8.928 ;
    END
  END ri0[145]
  PIN ri0[146]
    DIRECTION OUTPUT ;
    USE SIGNAL ;
    PORT
      LAYER M6 ;
        RECT  0 9.024 0.069 9.056 ;
    END
  END ri0[146]
  PIN ri0[147]
    DIRECTION OUTPUT ;
    USE SIGNAL ;
    PORT
      LAYER M6 ;
        RECT  0 9.152 0.069 9.184 ;
    END
  END ri0[147]
  PIN ri0[148]
    DIRECTION OUTPUT ;
    USE SIGNAL ;
    PORT
      LAYER M6 ;
        RECT  0 9.28 0.069 9.312 ;
    END
  END ri0[148]
  PIN ri0[149]
    DIRECTION OUTPUT ;
    USE SIGNAL ;
    PORT
      LAYER M6 ;
        RECT  0 9.408 0.069 9.44 ;
    END
  END ri0[149]
  PIN ri0[14]
    DIRECTION OUTPUT ;
    USE SIGNAL ;
    PORT
      LAYER M4 ;
        RECT  0 39.312 0.084 39.336 ;
    END
  END ri0[14]
  PIN ri0[150]
    DIRECTION OUTPUT ;
    USE SIGNAL ;
    PORT
      LAYER M6 ;
        RECT  0 9.536 0.069 9.568 ;
    END
  END ri0[150]
  PIN ri0[151]
    DIRECTION OUTPUT ;
    USE SIGNAL ;
    PORT
      LAYER M6 ;
        RECT  0 9.664 0.069 9.696 ;
    END
  END ri0[151]
  PIN ri0[152]
    DIRECTION OUTPUT ;
    USE SIGNAL ;
    PORT
      LAYER M6 ;
        RECT  0 9.792 0.069 9.824 ;
    END
  END ri0[152]
  PIN ri0[153]
    DIRECTION OUTPUT ;
    USE SIGNAL ;
    PORT
      LAYER M6 ;
        RECT  0 9.92 0.069 9.952 ;
    END
  END ri0[153]
  PIN ri0[154]
    DIRECTION OUTPUT ;
    USE SIGNAL ;
    PORT
      LAYER M6 ;
        RECT  0 10.048 0.069 10.08 ;
    END
  END ri0[154]
  PIN ri0[155]
    DIRECTION OUTPUT ;
    USE SIGNAL ;
    PORT
      LAYER M6 ;
        RECT  0 10.176 0.069 10.208 ;
    END
  END ri0[155]
  PIN ri0[156]
    DIRECTION OUTPUT ;
    USE SIGNAL ;
    PORT
      LAYER M6 ;
        RECT  0 10.304 0.069 10.336 ;
    END
  END ri0[156]
  PIN ri0[157]
    DIRECTION OUTPUT ;
    USE SIGNAL ;
    PORT
      LAYER M6 ;
        RECT  0 10.432 0.069 10.464 ;
    END
  END ri0[157]
  PIN ri0[158]
    DIRECTION OUTPUT ;
    USE SIGNAL ;
    PORT
      LAYER M6 ;
        RECT  0 10.56 0.069 10.592 ;
    END
  END ri0[158]
  PIN ri0[159]
    DIRECTION OUTPUT ;
    USE SIGNAL ;
    PORT
      LAYER M4 ;
        RECT  0 18.672 0.084 18.696 ;
    END
  END ri0[159]
  PIN ri0[15]
    DIRECTION OUTPUT ;
    USE SIGNAL ;
    PORT
      LAYER M4 ;
        RECT  0 39.408 0.084 39.432 ;
    END
  END ri0[15]
  PIN ri0[160]
    DIRECTION OUTPUT ;
    USE SIGNAL ;
    PORT
      LAYER M4 ;
        RECT  0 18.768 0.084 18.792 ;
    END
  END ri0[160]
  PIN ri0[161]
    DIRECTION OUTPUT ;
    USE SIGNAL ;
    PORT
      LAYER M4 ;
        RECT  0 18.864 0.084 18.888 ;
    END
  END ri0[161]
  PIN ri0[162]
    DIRECTION OUTPUT ;
    USE SIGNAL ;
    PORT
      LAYER M4 ;
        RECT  0 18.96 0.084 18.984 ;
    END
  END ri0[162]
  PIN ri0[163]
    DIRECTION OUTPUT ;
    USE SIGNAL ;
    PORT
      LAYER M4 ;
        RECT  0 19.056 0.084 19.08 ;
    END
  END ri0[163]
  PIN ri0[164]
    DIRECTION OUTPUT ;
    USE SIGNAL ;
    PORT
      LAYER M4 ;
        RECT  0 19.152 0.084 19.176 ;
    END
  END ri0[164]
  PIN ri0[165]
    DIRECTION OUTPUT ;
    USE SIGNAL ;
    PORT
      LAYER M4 ;
        RECT  0 19.248 0.084 19.272 ;
    END
  END ri0[165]
  PIN ri0[166]
    DIRECTION OUTPUT ;
    USE SIGNAL ;
    PORT
      LAYER M4 ;
        RECT  0 19.344 0.084 19.368 ;
    END
  END ri0[166]
  PIN ri0[167]
    DIRECTION OUTPUT ;
    USE SIGNAL ;
    PORT
      LAYER M4 ;
        RECT  0 19.44 0.084 19.464 ;
    END
  END ri0[167]
  PIN ri0[168]
    DIRECTION OUTPUT ;
    USE SIGNAL ;
    PORT
      LAYER M4 ;
        RECT  0 19.536 0.084 19.56 ;
    END
  END ri0[168]
  PIN ri0[169]
    DIRECTION OUTPUT ;
    USE SIGNAL ;
    PORT
      LAYER M4 ;
        RECT  0 19.632 0.084 19.656 ;
    END
  END ri0[169]
  PIN ri0[16]
    DIRECTION OUTPUT ;
    USE SIGNAL ;
    PORT
      LAYER M4 ;
        RECT  0 39.504 0.084 39.528 ;
    END
  END ri0[16]
  PIN ri0[170]
    DIRECTION OUTPUT ;
    USE SIGNAL ;
    PORT
      LAYER M4 ;
        RECT  0 19.728 0.084 19.752 ;
    END
  END ri0[170]
  PIN ri0[171]
    DIRECTION OUTPUT ;
    USE SIGNAL ;
    PORT
      LAYER M4 ;
        RECT  0 19.824 0.084 19.848 ;
    END
  END ri0[171]
  PIN ri0[172]
    DIRECTION OUTPUT ;
    USE SIGNAL ;
    PORT
      LAYER M4 ;
        RECT  0 19.92 0.084 19.944 ;
    END
  END ri0[172]
  PIN ri0[173]
    DIRECTION OUTPUT ;
    USE SIGNAL ;
    PORT
      LAYER M4 ;
        RECT  0 20.016 0.084 20.04 ;
    END
  END ri0[173]
  PIN ri0[174]
    DIRECTION OUTPUT ;
    USE SIGNAL ;
    PORT
      LAYER M4 ;
        RECT  0 20.112 0.084 20.136 ;
    END
  END ri0[174]
  PIN ri0[175]
    DIRECTION OUTPUT ;
    USE SIGNAL ;
    PORT
      LAYER M4 ;
        RECT  0 20.208 0.084 20.232 ;
    END
  END ri0[175]
  PIN ri0[176]
    DIRECTION OUTPUT ;
    USE SIGNAL ;
    PORT
      LAYER M4 ;
        RECT  0 20.304 0.084 20.328 ;
    END
  END ri0[176]
  PIN ri0[177]
    DIRECTION OUTPUT ;
    USE SIGNAL ;
    PORT
      LAYER M4 ;
        RECT  0 20.4 0.084 20.424 ;
    END
  END ri0[177]
  PIN ri0[178]
    DIRECTION OUTPUT ;
    USE SIGNAL ;
    PORT
      LAYER M4 ;
        RECT  0 20.496 0.084 20.52 ;
    END
  END ri0[178]
  PIN ri0[179]
    DIRECTION OUTPUT ;
    USE SIGNAL ;
    PORT
      LAYER M4 ;
        RECT  0 20.592 0.084 20.616 ;
    END
  END ri0[179]
  PIN ri0[17]
    DIRECTION OUTPUT ;
    USE SIGNAL ;
    PORT
      LAYER M4 ;
        RECT  0 39.6 0.084 39.624 ;
    END
  END ri0[17]
  PIN ri0[180]
    DIRECTION OUTPUT ;
    USE SIGNAL ;
    PORT
      LAYER M4 ;
        RECT  0 20.688 0.084 20.712 ;
    END
  END ri0[180]
  PIN ri0[181]
    DIRECTION OUTPUT ;
    USE SIGNAL ;
    PORT
      LAYER M4 ;
        RECT  0 20.784 0.084 20.808 ;
    END
  END ri0[181]
  PIN ri0[182]
    DIRECTION OUTPUT ;
    USE SIGNAL ;
    PORT
      LAYER M4 ;
        RECT  0 20.88 0.084 20.904 ;
    END
  END ri0[182]
  PIN ri0[183]
    DIRECTION OUTPUT ;
    USE SIGNAL ;
    PORT
      LAYER M4 ;
        RECT  0 20.976 0.084 21 ;
    END
  END ri0[183]
  PIN ri0[184]
    DIRECTION OUTPUT ;
    USE SIGNAL ;
    PORT
      LAYER M4 ;
        RECT  0 21.072 0.084 21.096 ;
    END
  END ri0[184]
  PIN ri0[185]
    DIRECTION OUTPUT ;
    USE SIGNAL ;
    PORT
      LAYER M4 ;
        RECT  0 21.168 0.084 21.192 ;
    END
  END ri0[185]
  PIN ri0[186]
    DIRECTION OUTPUT ;
    USE SIGNAL ;
    PORT
      LAYER M4 ;
        RECT  0 21.264 0.084 21.288 ;
    END
  END ri0[186]
  PIN ri0[187]
    DIRECTION OUTPUT ;
    USE SIGNAL ;
    PORT
      LAYER M4 ;
        RECT  0 21.36 0.084 21.384 ;
    END
  END ri0[187]
  PIN ri0[188]
    DIRECTION OUTPUT ;
    USE SIGNAL ;
    PORT
      LAYER M4 ;
        RECT  0 21.456 0.084 21.48 ;
    END
  END ri0[188]
  PIN ri0[189]
    DIRECTION OUTPUT ;
    USE SIGNAL ;
    PORT
      LAYER M4 ;
        RECT  0 21.552 0.084 21.576 ;
    END
  END ri0[189]
  PIN ri0[18]
    DIRECTION OUTPUT ;
    USE SIGNAL ;
    PORT
      LAYER M4 ;
        RECT  0 39.696 0.084 39.72 ;
    END
  END ri0[18]
  PIN ri0[190]
    DIRECTION OUTPUT ;
    USE SIGNAL ;
    PORT
      LAYER M4 ;
        RECT  0 21.648 0.084 21.672 ;
    END
  END ri0[190]
  PIN ri0[191]
    DIRECTION OUTPUT ;
    USE SIGNAL ;
    PORT
      LAYER M4 ;
        RECT  0 40.944 0.084 40.968 ;
    END
  END ri0[191]
  PIN ri0[192]
    DIRECTION OUTPUT ;
    USE SIGNAL ;
    PORT
      LAYER M4 ;
        RECT  0 41.04 0.084 41.064 ;
    END
  END ri0[192]
  PIN ri0[193]
    DIRECTION OUTPUT ;
    USE SIGNAL ;
    PORT
      LAYER M4 ;
        RECT  0 41.136 0.084 41.16 ;
    END
  END ri0[193]
  PIN ri0[194]
    DIRECTION OUTPUT ;
    USE SIGNAL ;
    PORT
      LAYER M4 ;
        RECT  0 41.232 0.084 41.256 ;
    END
  END ri0[194]
  PIN ri0[195]
    DIRECTION OUTPUT ;
    USE SIGNAL ;
    PORT
      LAYER M4 ;
        RECT  0 41.328 0.084 41.352 ;
    END
  END ri0[195]
  PIN ri0[196]
    DIRECTION OUTPUT ;
    USE SIGNAL ;
    PORT
      LAYER M4 ;
        RECT  0 41.424 0.084 41.448 ;
    END
  END ri0[196]
  PIN ri0[197]
    DIRECTION OUTPUT ;
    USE SIGNAL ;
    PORT
      LAYER M4 ;
        RECT  0 41.52 0.084 41.544 ;
    END
  END ri0[197]
  PIN ri0[198]
    DIRECTION OUTPUT ;
    USE SIGNAL ;
    PORT
      LAYER M4 ;
        RECT  0 41.616 0.084 41.64 ;
    END
  END ri0[198]
  PIN ri0[199]
    DIRECTION OUTPUT ;
    USE SIGNAL ;
    PORT
      LAYER M4 ;
        RECT  0 41.712 0.084 41.736 ;
    END
  END ri0[199]
  PIN ri0[19]
    DIRECTION OUTPUT ;
    USE SIGNAL ;
    PORT
      LAYER M4 ;
        RECT  0 39.792 0.084 39.816 ;
    END
  END ri0[19]
  PIN ri0[1]
    DIRECTION OUTPUT ;
    USE SIGNAL ;
    PORT
      LAYER M4 ;
        RECT  0 38.064 0.084 38.088 ;
    END
  END ri0[1]
  PIN ri0[200]
    DIRECTION OUTPUT ;
    USE SIGNAL ;
    PORT
      LAYER M4 ;
        RECT  0 41.808 0.084 41.832 ;
    END
  END ri0[200]
  PIN ri0[201]
    DIRECTION OUTPUT ;
    USE SIGNAL ;
    PORT
      LAYER M4 ;
        RECT  0 41.904 0.084 41.928 ;
    END
  END ri0[201]
  PIN ri0[202]
    DIRECTION OUTPUT ;
    USE SIGNAL ;
    PORT
      LAYER M4 ;
        RECT  0 42 0.084 42.024 ;
    END
  END ri0[202]
  PIN ri0[203]
    DIRECTION OUTPUT ;
    USE SIGNAL ;
    PORT
      LAYER M4 ;
        RECT  0 42.096 0.084 42.12 ;
    END
  END ri0[203]
  PIN ri0[204]
    DIRECTION OUTPUT ;
    USE SIGNAL ;
    PORT
      LAYER M4 ;
        RECT  0 42.192 0.084 42.216 ;
    END
  END ri0[204]
  PIN ri0[205]
    DIRECTION OUTPUT ;
    USE SIGNAL ;
    PORT
      LAYER M4 ;
        RECT  0 42.288 0.084 42.312 ;
    END
  END ri0[205]
  PIN ri0[206]
    DIRECTION OUTPUT ;
    USE SIGNAL ;
    PORT
      LAYER M4 ;
        RECT  0 42.384 0.084 42.408 ;
    END
  END ri0[206]
  PIN ri0[207]
    DIRECTION OUTPUT ;
    USE SIGNAL ;
    PORT
      LAYER M4 ;
        RECT  0 42.48 0.084 42.504 ;
    END
  END ri0[207]
  PIN ri0[208]
    DIRECTION OUTPUT ;
    USE SIGNAL ;
    PORT
      LAYER M4 ;
        RECT  0 42.576 0.084 42.6 ;
    END
  END ri0[208]
  PIN ri0[209]
    DIRECTION OUTPUT ;
    USE SIGNAL ;
    PORT
      LAYER M4 ;
        RECT  0 42.672 0.084 42.696 ;
    END
  END ri0[209]
  PIN ri0[20]
    DIRECTION OUTPUT ;
    USE SIGNAL ;
    PORT
      LAYER M4 ;
        RECT  0 39.888 0.084 39.912 ;
    END
  END ri0[20]
  PIN ri0[210]
    DIRECTION OUTPUT ;
    USE SIGNAL ;
    PORT
      LAYER M4 ;
        RECT  0 42.768 0.084 42.792 ;
    END
  END ri0[210]
  PIN ri0[211]
    DIRECTION OUTPUT ;
    USE SIGNAL ;
    PORT
      LAYER M4 ;
        RECT  0 42.864 0.084 42.888 ;
    END
  END ri0[211]
  PIN ri0[212]
    DIRECTION OUTPUT ;
    USE SIGNAL ;
    PORT
      LAYER M4 ;
        RECT  0 42.96 0.084 42.984 ;
    END
  END ri0[212]
  PIN ri0[213]
    DIRECTION OUTPUT ;
    USE SIGNAL ;
    PORT
      LAYER M4 ;
        RECT  0 43.056 0.084 43.08 ;
    END
  END ri0[213]
  PIN ri0[214]
    DIRECTION OUTPUT ;
    USE SIGNAL ;
    PORT
      LAYER M4 ;
        RECT  0 43.152 0.084 43.176 ;
    END
  END ri0[214]
  PIN ri0[215]
    DIRECTION OUTPUT ;
    USE SIGNAL ;
    PORT
      LAYER M4 ;
        RECT  0 43.248 0.084 43.272 ;
    END
  END ri0[215]
  PIN ri0[216]
    DIRECTION OUTPUT ;
    USE SIGNAL ;
    PORT
      LAYER M4 ;
        RECT  0 43.344 0.084 43.368 ;
    END
  END ri0[216]
  PIN ri0[217]
    DIRECTION OUTPUT ;
    USE SIGNAL ;
    PORT
      LAYER M4 ;
        RECT  0 43.44 0.084 43.464 ;
    END
  END ri0[217]
  PIN ri0[218]
    DIRECTION OUTPUT ;
    USE SIGNAL ;
    PORT
      LAYER M4 ;
        RECT  0 43.536 0.084 43.56 ;
    END
  END ri0[218]
  PIN ri0[219]
    DIRECTION OUTPUT ;
    USE SIGNAL ;
    PORT
      LAYER M4 ;
        RECT  0 43.632 0.084 43.656 ;
    END
  END ri0[219]
  PIN ri0[21]
    DIRECTION OUTPUT ;
    USE SIGNAL ;
    PORT
      LAYER M4 ;
        RECT  0 39.984 0.084 40.008 ;
    END
  END ri0[21]
  PIN ri0[220]
    DIRECTION OUTPUT ;
    USE SIGNAL ;
    PORT
      LAYER M4 ;
        RECT  0 43.728 0.084 43.752 ;
    END
  END ri0[220]
  PIN ri0[221]
    DIRECTION OUTPUT ;
    USE SIGNAL ;
    PORT
      LAYER M4 ;
        RECT  0 43.824 0.084 43.848 ;
    END
  END ri0[221]
  PIN ri0[222]
    DIRECTION OUTPUT ;
    USE SIGNAL ;
    PORT
      LAYER M4 ;
        RECT  0 43.92 0.084 43.944 ;
    END
  END ri0[222]
  PIN ri0[223]
    DIRECTION OUTPUT ;
    USE SIGNAL ;
    PORT
      LAYER M4 ;
        RECT  0 57.072 0.084 57.096 ;
    END
  END ri0[223]
  PIN ri0[224]
    DIRECTION OUTPUT ;
    USE SIGNAL ;
    PORT
      LAYER M4 ;
        RECT  0 57.168 0.084 57.192 ;
    END
  END ri0[224]
  PIN ri0[225]
    DIRECTION OUTPUT ;
    USE SIGNAL ;
    PORT
      LAYER M4 ;
        RECT  0 57.264 0.084 57.288 ;
    END
  END ri0[225]
  PIN ri0[226]
    DIRECTION OUTPUT ;
    USE SIGNAL ;
    PORT
      LAYER M4 ;
        RECT  0 57.36 0.084 57.384 ;
    END
  END ri0[226]
  PIN ri0[227]
    DIRECTION OUTPUT ;
    USE SIGNAL ;
    PORT
      LAYER M4 ;
        RECT  0 57.456 0.084 57.48 ;
    END
  END ri0[227]
  PIN ri0[228]
    DIRECTION OUTPUT ;
    USE SIGNAL ;
    PORT
      LAYER M4 ;
        RECT  0 57.552 0.084 57.576 ;
    END
  END ri0[228]
  PIN ri0[229]
    DIRECTION OUTPUT ;
    USE SIGNAL ;
    PORT
      LAYER M4 ;
        RECT  0 57.648 0.084 57.672 ;
    END
  END ri0[229]
  PIN ri0[22]
    DIRECTION OUTPUT ;
    USE SIGNAL ;
    PORT
      LAYER M4 ;
        RECT  0 40.08 0.084 40.104 ;
    END
  END ri0[22]
  PIN ri0[230]
    DIRECTION OUTPUT ;
    USE SIGNAL ;
    PORT
      LAYER M4 ;
        RECT  0 57.744 0.084 57.768 ;
    END
  END ri0[230]
  PIN ri0[231]
    DIRECTION OUTPUT ;
    USE SIGNAL ;
    PORT
      LAYER M4 ;
        RECT  0 57.84 0.084 57.864 ;
    END
  END ri0[231]
  PIN ri0[232]
    DIRECTION OUTPUT ;
    USE SIGNAL ;
    PORT
      LAYER M4 ;
        RECT  0 57.936 0.084 57.96 ;
    END
  END ri0[232]
  PIN ri0[233]
    DIRECTION OUTPUT ;
    USE SIGNAL ;
    PORT
      LAYER M4 ;
        RECT  0 58.032 0.084 58.056 ;
    END
  END ri0[233]
  PIN ri0[234]
    DIRECTION OUTPUT ;
    USE SIGNAL ;
    PORT
      LAYER M4 ;
        RECT  0 58.128 0.084 58.152 ;
    END
  END ri0[234]
  PIN ri0[235]
    DIRECTION OUTPUT ;
    USE SIGNAL ;
    PORT
      LAYER M4 ;
        RECT  0 58.224 0.084 58.248 ;
    END
  END ri0[235]
  PIN ri0[236]
    DIRECTION OUTPUT ;
    USE SIGNAL ;
    PORT
      LAYER M4 ;
        RECT  0 58.32 0.084 58.344 ;
    END
  END ri0[236]
  PIN ri0[237]
    DIRECTION OUTPUT ;
    USE SIGNAL ;
    PORT
      LAYER M4 ;
        RECT  0 58.416 0.084 58.44 ;
    END
  END ri0[237]
  PIN ri0[238]
    DIRECTION OUTPUT ;
    USE SIGNAL ;
    PORT
      LAYER M4 ;
        RECT  0 58.512 0.084 58.536 ;
    END
  END ri0[238]
  PIN ri0[239]
    DIRECTION OUTPUT ;
    USE SIGNAL ;
    PORT
      LAYER M4 ;
        RECT  0 58.608 0.084 58.632 ;
    END
  END ri0[239]
  PIN ri0[23]
    DIRECTION OUTPUT ;
    USE SIGNAL ;
    PORT
      LAYER M4 ;
        RECT  0 40.176 0.084 40.2 ;
    END
  END ri0[23]
  PIN ri0[240]
    DIRECTION OUTPUT ;
    USE SIGNAL ;
    PORT
      LAYER M4 ;
        RECT  0 58.704 0.084 58.728 ;
    END
  END ri0[240]
  PIN ri0[241]
    DIRECTION OUTPUT ;
    USE SIGNAL ;
    PORT
      LAYER M4 ;
        RECT  0 58.8 0.084 58.824 ;
    END
  END ri0[241]
  PIN ri0[242]
    DIRECTION OUTPUT ;
    USE SIGNAL ;
    PORT
      LAYER M4 ;
        RECT  0 58.896 0.084 58.92 ;
    END
  END ri0[242]
  PIN ri0[243]
    DIRECTION OUTPUT ;
    USE SIGNAL ;
    PORT
      LAYER M4 ;
        RECT  0 58.992 0.084 59.016 ;
    END
  END ri0[243]
  PIN ri0[244]
    DIRECTION OUTPUT ;
    USE SIGNAL ;
    PORT
      LAYER M4 ;
        RECT  0 59.088 0.084 59.112 ;
    END
  END ri0[244]
  PIN ri0[245]
    DIRECTION OUTPUT ;
    USE SIGNAL ;
    PORT
      LAYER M4 ;
        RECT  0 59.184 0.084 59.208 ;
    END
  END ri0[245]
  PIN ri0[246]
    DIRECTION OUTPUT ;
    USE SIGNAL ;
    PORT
      LAYER M4 ;
        RECT  0 59.28 0.084 59.304 ;
    END
  END ri0[246]
  PIN ri0[247]
    DIRECTION OUTPUT ;
    USE SIGNAL ;
    PORT
      LAYER M4 ;
        RECT  0 59.376 0.084 59.4 ;
    END
  END ri0[247]
  PIN ri0[248]
    DIRECTION OUTPUT ;
    USE SIGNAL ;
    PORT
      LAYER M4 ;
        RECT  0 59.472 0.084 59.496 ;
    END
  END ri0[248]
  PIN ri0[249]
    DIRECTION OUTPUT ;
    USE SIGNAL ;
    PORT
      LAYER M4 ;
        RECT  0 59.568 0.084 59.592 ;
    END
  END ri0[249]
  PIN ri0[24]
    DIRECTION OUTPUT ;
    USE SIGNAL ;
    PORT
      LAYER M4 ;
        RECT  0 40.272 0.084 40.296 ;
    END
  END ri0[24]
  PIN ri0[250]
    DIRECTION OUTPUT ;
    USE SIGNAL ;
    PORT
      LAYER M4 ;
        RECT  0 59.664 0.084 59.688 ;
    END
  END ri0[250]
  PIN ri0[251]
    DIRECTION OUTPUT ;
    USE SIGNAL ;
    PORT
      LAYER M4 ;
        RECT  0 59.76 0.084 59.784 ;
    END
  END ri0[251]
  PIN ri0[252]
    DIRECTION OUTPUT ;
    USE SIGNAL ;
    PORT
      LAYER M4 ;
        RECT  0 59.856 0.084 59.88 ;
    END
  END ri0[252]
  PIN ri0[253]
    DIRECTION OUTPUT ;
    USE SIGNAL ;
    PORT
      LAYER M4 ;
        RECT  0 59.952 0.084 59.976 ;
    END
  END ri0[253]
  PIN ri0[254]
    DIRECTION OUTPUT ;
    USE SIGNAL ;
    PORT
      LAYER M4 ;
        RECT  0 60.048 0.084 60.072 ;
    END
  END ri0[254]
  PIN ri0[255]
    DIRECTION OUTPUT ;
    USE SIGNAL ;
    PORT
      LAYER M6 ;
        RECT  0 56.256 0.069 56.288 ;
    END
  END ri0[255]
  PIN ri0[256]
    DIRECTION OUTPUT ;
    USE SIGNAL ;
    PORT
      LAYER M6 ;
        RECT  0 56.384 0.069 56.416 ;
    END
  END ri0[256]
  PIN ri0[257]
    DIRECTION OUTPUT ;
    USE SIGNAL ;
    PORT
      LAYER M6 ;
        RECT  0 56.512 0.069 56.544 ;
    END
  END ri0[257]
  PIN ri0[258]
    DIRECTION OUTPUT ;
    USE SIGNAL ;
    PORT
      LAYER M6 ;
        RECT  0 56.64 0.069 56.672 ;
    END
  END ri0[258]
  PIN ri0[259]
    DIRECTION OUTPUT ;
    USE SIGNAL ;
    PORT
      LAYER M6 ;
        RECT  0 56.768 0.069 56.8 ;
    END
  END ri0[259]
  PIN ri0[25]
    DIRECTION OUTPUT ;
    USE SIGNAL ;
    PORT
      LAYER M4 ;
        RECT  0 40.368 0.084 40.392 ;
    END
  END ri0[25]
  PIN ri0[260]
    DIRECTION OUTPUT ;
    USE SIGNAL ;
    PORT
      LAYER M6 ;
        RECT  0 56.896 0.069 56.928 ;
    END
  END ri0[260]
  PIN ri0[261]
    DIRECTION OUTPUT ;
    USE SIGNAL ;
    PORT
      LAYER M6 ;
        RECT  0 57.024 0.069 57.056 ;
    END
  END ri0[261]
  PIN ri0[262]
    DIRECTION OUTPUT ;
    USE SIGNAL ;
    PORT
      LAYER M6 ;
        RECT  0 57.152 0.069 57.184 ;
    END
  END ri0[262]
  PIN ri0[263]
    DIRECTION OUTPUT ;
    USE SIGNAL ;
    PORT
      LAYER M6 ;
        RECT  0 57.28 0.069 57.312 ;
    END
  END ri0[263]
  PIN ri0[264]
    DIRECTION OUTPUT ;
    USE SIGNAL ;
    PORT
      LAYER M6 ;
        RECT  0 57.408 0.069 57.44 ;
    END
  END ri0[264]
  PIN ri0[265]
    DIRECTION OUTPUT ;
    USE SIGNAL ;
    PORT
      LAYER M6 ;
        RECT  0 57.536 0.069 57.568 ;
    END
  END ri0[265]
  PIN ri0[26]
    DIRECTION OUTPUT ;
    USE SIGNAL ;
    PORT
      LAYER M4 ;
        RECT  0 40.464 0.084 40.488 ;
    END
  END ri0[26]
  PIN ri0[27]
    DIRECTION OUTPUT ;
    USE SIGNAL ;
    PORT
      LAYER M4 ;
        RECT  0 40.56 0.084 40.584 ;
    END
  END ri0[27]
  PIN ri0[28]
    DIRECTION OUTPUT ;
    USE SIGNAL ;
    PORT
      LAYER M4 ;
        RECT  0 40.656 0.084 40.68 ;
    END
  END ri0[28]
  PIN ri0[29]
    DIRECTION OUTPUT ;
    USE SIGNAL ;
    PORT
      LAYER M4 ;
        RECT  0 40.752 0.084 40.776 ;
    END
  END ri0[29]
  PIN ri0[2]
    DIRECTION OUTPUT ;
    USE SIGNAL ;
    PORT
      LAYER M4 ;
        RECT  0 38.16 0.084 38.184 ;
    END
  END ri0[2]
  PIN ri0[30]
    DIRECTION OUTPUT ;
    USE SIGNAL ;
    PORT
      LAYER M4 ;
        RECT  0 40.848 0.084 40.872 ;
    END
  END ri0[30]
  PIN ri0[31]
    DIRECTION OUTPUT ;
    USE SIGNAL ;
    PORT
      LAYER M6 ;
        RECT  0 24 0.069 24.032 ;
    END
  END ri0[31]
  PIN ri0[32]
    DIRECTION OUTPUT ;
    USE SIGNAL ;
    PORT
      LAYER M6 ;
        RECT  0 24.128 0.069 24.16 ;
    END
  END ri0[32]
  PIN ri0[33]
    DIRECTION OUTPUT ;
    USE SIGNAL ;
    PORT
      LAYER M6 ;
        RECT  0 24.256 0.069 24.288 ;
    END
  END ri0[33]
  PIN ri0[34]
    DIRECTION OUTPUT ;
    USE SIGNAL ;
    PORT
      LAYER M6 ;
        RECT  0 24.384 0.069 24.416 ;
    END
  END ri0[34]
  PIN ri0[35]
    DIRECTION OUTPUT ;
    USE SIGNAL ;
    PORT
      LAYER M6 ;
        RECT  0 24.512 0.069 24.544 ;
    END
  END ri0[35]
  PIN ri0[36]
    DIRECTION OUTPUT ;
    USE SIGNAL ;
    PORT
      LAYER M6 ;
        RECT  0 24.64 0.069 24.672 ;
    END
  END ri0[36]
  PIN ri0[37]
    DIRECTION OUTPUT ;
    USE SIGNAL ;
    PORT
      LAYER M6 ;
        RECT  0 24.768 0.069 24.8 ;
    END
  END ri0[37]
  PIN ri0[38]
    DIRECTION OUTPUT ;
    USE SIGNAL ;
    PORT
      LAYER M6 ;
        RECT  0 24.896 0.069 24.928 ;
    END
  END ri0[38]
  PIN ri0[39]
    DIRECTION OUTPUT ;
    USE SIGNAL ;
    PORT
      LAYER M6 ;
        RECT  0 25.024 0.069 25.056 ;
    END
  END ri0[39]
  PIN ri0[3]
    DIRECTION OUTPUT ;
    USE SIGNAL ;
    PORT
      LAYER M4 ;
        RECT  0 38.256 0.084 38.28 ;
    END
  END ri0[3]
  PIN ri0[40]
    DIRECTION OUTPUT ;
    USE SIGNAL ;
    PORT
      LAYER M6 ;
        RECT  0 25.152 0.069 25.184 ;
    END
  END ri0[40]
  PIN ri0[41]
    DIRECTION OUTPUT ;
    USE SIGNAL ;
    PORT
      LAYER M6 ;
        RECT  0 25.28 0.069 25.312 ;
    END
  END ri0[41]
  PIN ri0[42]
    DIRECTION OUTPUT ;
    USE SIGNAL ;
    PORT
      LAYER M6 ;
        RECT  0 25.408 0.069 25.44 ;
    END
  END ri0[42]
  PIN ri0[43]
    DIRECTION OUTPUT ;
    USE SIGNAL ;
    PORT
      LAYER M6 ;
        RECT  0 25.536 0.069 25.568 ;
    END
  END ri0[43]
  PIN ri0[44]
    DIRECTION OUTPUT ;
    USE SIGNAL ;
    PORT
      LAYER M6 ;
        RECT  0 25.664 0.069 25.696 ;
    END
  END ri0[44]
  PIN ri0[45]
    DIRECTION OUTPUT ;
    USE SIGNAL ;
    PORT
      LAYER M6 ;
        RECT  0 25.792 0.069 25.824 ;
    END
  END ri0[45]
  PIN ri0[46]
    DIRECTION OUTPUT ;
    USE SIGNAL ;
    PORT
      LAYER M6 ;
        RECT  0 25.92 0.069 25.952 ;
    END
  END ri0[46]
  PIN ri0[47]
    DIRECTION OUTPUT ;
    USE SIGNAL ;
    PORT
      LAYER M6 ;
        RECT  0 26.048 0.069 26.08 ;
    END
  END ri0[47]
  PIN ri0[48]
    DIRECTION OUTPUT ;
    USE SIGNAL ;
    PORT
      LAYER M6 ;
        RECT  0 26.176 0.069 26.208 ;
    END
  END ri0[48]
  PIN ri0[49]
    DIRECTION OUTPUT ;
    USE SIGNAL ;
    PORT
      LAYER M6 ;
        RECT  0 26.304 0.069 26.336 ;
    END
  END ri0[49]
  PIN ri0[4]
    DIRECTION OUTPUT ;
    USE SIGNAL ;
    PORT
      LAYER M4 ;
        RECT  0 38.352 0.084 38.376 ;
    END
  END ri0[4]
  PIN ri0[50]
    DIRECTION OUTPUT ;
    USE SIGNAL ;
    PORT
      LAYER M6 ;
        RECT  0 26.432 0.069 26.464 ;
    END
  END ri0[50]
  PIN ri0[51]
    DIRECTION OUTPUT ;
    USE SIGNAL ;
    PORT
      LAYER M6 ;
        RECT  0 26.56 0.069 26.592 ;
    END
  END ri0[51]
  PIN ri0[52]
    DIRECTION OUTPUT ;
    USE SIGNAL ;
    PORT
      LAYER M6 ;
        RECT  0 26.688 0.069 26.72 ;
    END
  END ri0[52]
  PIN ri0[53]
    DIRECTION OUTPUT ;
    USE SIGNAL ;
    PORT
      LAYER M6 ;
        RECT  0 26.816 0.069 26.848 ;
    END
  END ri0[53]
  PIN ri0[54]
    DIRECTION OUTPUT ;
    USE SIGNAL ;
    PORT
      LAYER M6 ;
        RECT  0 26.944 0.069 26.976 ;
    END
  END ri0[54]
  PIN ri0[55]
    DIRECTION OUTPUT ;
    USE SIGNAL ;
    PORT
      LAYER M6 ;
        RECT  0 27.072 0.069 27.104 ;
    END
  END ri0[55]
  PIN ri0[56]
    DIRECTION OUTPUT ;
    USE SIGNAL ;
    PORT
      LAYER M6 ;
        RECT  0 27.2 0.069 27.232 ;
    END
  END ri0[56]
  PIN ri0[57]
    DIRECTION OUTPUT ;
    USE SIGNAL ;
    PORT
      LAYER M6 ;
        RECT  0 27.328 0.069 27.36 ;
    END
  END ri0[57]
  PIN ri0[58]
    DIRECTION OUTPUT ;
    USE SIGNAL ;
    PORT
      LAYER M6 ;
        RECT  0 27.456 0.069 27.488 ;
    END
  END ri0[58]
  PIN ri0[59]
    DIRECTION OUTPUT ;
    USE SIGNAL ;
    PORT
      LAYER M6 ;
        RECT  0 27.584 0.069 27.616 ;
    END
  END ri0[59]
  PIN ri0[5]
    DIRECTION OUTPUT ;
    USE SIGNAL ;
    PORT
      LAYER M4 ;
        RECT  0 38.448 0.084 38.472 ;
    END
  END ri0[5]
  PIN ri0[60]
    DIRECTION OUTPUT ;
    USE SIGNAL ;
    PORT
      LAYER M6 ;
        RECT  0 27.712 0.069 27.744 ;
    END
  END ri0[60]
  PIN ri0[61]
    DIRECTION OUTPUT ;
    USE SIGNAL ;
    PORT
      LAYER M6 ;
        RECT  0 27.84 0.069 27.872 ;
    END
  END ri0[61]
  PIN ri0[62]
    DIRECTION OUTPUT ;
    USE SIGNAL ;
    PORT
      LAYER M6 ;
        RECT  0 27.968 0.069 28 ;
    END
  END ri0[62]
  PIN ri0[63]
    DIRECTION OUTPUT ;
    USE SIGNAL ;
    PORT
      LAYER M4 ;
        RECT  0 15.6 0.084 15.624 ;
    END
  END ri0[63]
  PIN ri0[64]
    DIRECTION OUTPUT ;
    USE SIGNAL ;
    PORT
      LAYER M4 ;
        RECT  0 15.696 0.084 15.72 ;
    END
  END ri0[64]
  PIN ri0[65]
    DIRECTION OUTPUT ;
    USE SIGNAL ;
    PORT
      LAYER M4 ;
        RECT  0 15.792 0.084 15.816 ;
    END
  END ri0[65]
  PIN ri0[66]
    DIRECTION OUTPUT ;
    USE SIGNAL ;
    PORT
      LAYER M4 ;
        RECT  0 15.888 0.084 15.912 ;
    END
  END ri0[66]
  PIN ri0[67]
    DIRECTION OUTPUT ;
    USE SIGNAL ;
    PORT
      LAYER M4 ;
        RECT  0 15.984 0.084 16.008 ;
    END
  END ri0[67]
  PIN ri0[68]
    DIRECTION OUTPUT ;
    USE SIGNAL ;
    PORT
      LAYER M4 ;
        RECT  0 16.08 0.084 16.104 ;
    END
  END ri0[68]
  PIN ri0[69]
    DIRECTION OUTPUT ;
    USE SIGNAL ;
    PORT
      LAYER M4 ;
        RECT  0 16.176 0.084 16.2 ;
    END
  END ri0[69]
  PIN ri0[6]
    DIRECTION OUTPUT ;
    USE SIGNAL ;
    PORT
      LAYER M4 ;
        RECT  0 38.544 0.084 38.568 ;
    END
  END ri0[6]
  PIN ri0[70]
    DIRECTION OUTPUT ;
    USE SIGNAL ;
    PORT
      LAYER M4 ;
        RECT  0 16.272 0.084 16.296 ;
    END
  END ri0[70]
  PIN ri0[71]
    DIRECTION OUTPUT ;
    USE SIGNAL ;
    PORT
      LAYER M4 ;
        RECT  0 16.368 0.084 16.392 ;
    END
  END ri0[71]
  PIN ri0[72]
    DIRECTION OUTPUT ;
    USE SIGNAL ;
    PORT
      LAYER M4 ;
        RECT  0 16.464 0.084 16.488 ;
    END
  END ri0[72]
  PIN ri0[73]
    DIRECTION OUTPUT ;
    USE SIGNAL ;
    PORT
      LAYER M4 ;
        RECT  0 16.56 0.084 16.584 ;
    END
  END ri0[73]
  PIN ri0[74]
    DIRECTION OUTPUT ;
    USE SIGNAL ;
    PORT
      LAYER M4 ;
        RECT  0 16.656 0.084 16.68 ;
    END
  END ri0[74]
  PIN ri0[75]
    DIRECTION OUTPUT ;
    USE SIGNAL ;
    PORT
      LAYER M4 ;
        RECT  0 16.752 0.084 16.776 ;
    END
  END ri0[75]
  PIN ri0[76]
    DIRECTION OUTPUT ;
    USE SIGNAL ;
    PORT
      LAYER M4 ;
        RECT  0 16.848 0.084 16.872 ;
    END
  END ri0[76]
  PIN ri0[77]
    DIRECTION OUTPUT ;
    USE SIGNAL ;
    PORT
      LAYER M4 ;
        RECT  0 16.944 0.084 16.968 ;
    END
  END ri0[77]
  PIN ri0[78]
    DIRECTION OUTPUT ;
    USE SIGNAL ;
    PORT
      LAYER M4 ;
        RECT  0 17.04 0.084 17.064 ;
    END
  END ri0[78]
  PIN ri0[79]
    DIRECTION OUTPUT ;
    USE SIGNAL ;
    PORT
      LAYER M4 ;
        RECT  0 17.136 0.084 17.16 ;
    END
  END ri0[79]
  PIN ri0[7]
    DIRECTION OUTPUT ;
    USE SIGNAL ;
    PORT
      LAYER M4 ;
        RECT  0 38.64 0.084 38.664 ;
    END
  END ri0[7]
  PIN ri0[80]
    DIRECTION OUTPUT ;
    USE SIGNAL ;
    PORT
      LAYER M4 ;
        RECT  0 17.232 0.084 17.256 ;
    END
  END ri0[80]
  PIN ri0[81]
    DIRECTION OUTPUT ;
    USE SIGNAL ;
    PORT
      LAYER M4 ;
        RECT  0 17.328 0.084 17.352 ;
    END
  END ri0[81]
  PIN ri0[82]
    DIRECTION OUTPUT ;
    USE SIGNAL ;
    PORT
      LAYER M4 ;
        RECT  0 17.424 0.084 17.448 ;
    END
  END ri0[82]
  PIN ri0[83]
    DIRECTION OUTPUT ;
    USE SIGNAL ;
    PORT
      LAYER M4 ;
        RECT  0 17.52 0.084 17.544 ;
    END
  END ri0[83]
  PIN ri0[84]
    DIRECTION OUTPUT ;
    USE SIGNAL ;
    PORT
      LAYER M4 ;
        RECT  0 17.616 0.084 17.64 ;
    END
  END ri0[84]
  PIN ri0[85]
    DIRECTION OUTPUT ;
    USE SIGNAL ;
    PORT
      LAYER M4 ;
        RECT  0 17.712 0.084 17.736 ;
    END
  END ri0[85]
  PIN ri0[86]
    DIRECTION OUTPUT ;
    USE SIGNAL ;
    PORT
      LAYER M4 ;
        RECT  0 17.808 0.084 17.832 ;
    END
  END ri0[86]
  PIN ri0[87]
    DIRECTION OUTPUT ;
    USE SIGNAL ;
    PORT
      LAYER M4 ;
        RECT  0 17.904 0.084 17.928 ;
    END
  END ri0[87]
  PIN ri0[88]
    DIRECTION OUTPUT ;
    USE SIGNAL ;
    PORT
      LAYER M4 ;
        RECT  0 18 0.084 18.024 ;
    END
  END ri0[88]
  PIN ri0[89]
    DIRECTION OUTPUT ;
    USE SIGNAL ;
    PORT
      LAYER M4 ;
        RECT  0 18.096 0.084 18.12 ;
    END
  END ri0[89]
  PIN ri0[8]
    DIRECTION OUTPUT ;
    USE SIGNAL ;
    PORT
      LAYER M4 ;
        RECT  0 38.736 0.084 38.76 ;
    END
  END ri0[8]
  PIN ri0[90]
    DIRECTION OUTPUT ;
    USE SIGNAL ;
    PORT
      LAYER M4 ;
        RECT  0 18.192 0.084 18.216 ;
    END
  END ri0[90]
  PIN ri0[91]
    DIRECTION OUTPUT ;
    USE SIGNAL ;
    PORT
      LAYER M4 ;
        RECT  0 18.288 0.084 18.312 ;
    END
  END ri0[91]
  PIN ri0[92]
    DIRECTION OUTPUT ;
    USE SIGNAL ;
    PORT
      LAYER M4 ;
        RECT  0 18.384 0.084 18.408 ;
    END
  END ri0[92]
  PIN ri0[93]
    DIRECTION OUTPUT ;
    USE SIGNAL ;
    PORT
      LAYER M4 ;
        RECT  0 18.48 0.084 18.504 ;
    END
  END ri0[93]
  PIN ri0[94]
    DIRECTION OUTPUT ;
    USE SIGNAL ;
    PORT
      LAYER M4 ;
        RECT  0 18.576 0.084 18.6 ;
    END
  END ri0[94]
  PIN ri0[95]
    DIRECTION OUTPUT ;
    USE SIGNAL ;
    PORT
      LAYER M4 ;
        RECT  0 5.616 0.084 5.64 ;
    END
  END ri0[95]
  PIN ri0[96]
    DIRECTION OUTPUT ;
    USE SIGNAL ;
    PORT
      LAYER M4 ;
        RECT  0 5.712 0.084 5.736 ;
    END
  END ri0[96]
  PIN ri0[97]
    DIRECTION OUTPUT ;
    USE SIGNAL ;
    PORT
      LAYER M4 ;
        RECT  0 5.808 0.084 5.832 ;
    END
  END ri0[97]
  PIN ri0[98]
    DIRECTION OUTPUT ;
    USE SIGNAL ;
    PORT
      LAYER M4 ;
        RECT  0 5.904 0.084 5.928 ;
    END
  END ri0[98]
  PIN ri0[99]
    DIRECTION OUTPUT ;
    USE SIGNAL ;
    PORT
      LAYER M4 ;
        RECT  0 6 0.084 6.024 ;
    END
  END ri0[99]
  PIN ri0[9]
    DIRECTION OUTPUT ;
    USE SIGNAL ;
    PORT
      LAYER M4 ;
        RECT  0 38.832 0.084 38.856 ;
    END
  END ri0[9]
  PIN ri0_cr
    DIRECTION INPUT ;
    USE SIGNAL ;
    PORT
      LAYER M6 ;
        RECT  0 57.664 0.069 57.696 ;
    END
  END ri0_cr
  PIN ri1[0]
    DIRECTION OUTPUT ;
    USE SIGNAL ;
    PORT
      LAYER M6 ;
        RECT  66.891 38.976 66.96 39.008 ;
    END
  END ri1[0]
  PIN ri1[100]
    DIRECTION OUTPUT ;
    USE SIGNAL ;
    PORT
      LAYER M4 ;
        RECT  66.876 7.344 66.96 7.368 ;
    END
  END ri1[100]
  PIN ri1[101]
    DIRECTION OUTPUT ;
    USE SIGNAL ;
    PORT
      LAYER M4 ;
        RECT  66.876 7.44 66.96 7.464 ;
    END
  END ri1[101]
  PIN ri1[102]
    DIRECTION OUTPUT ;
    USE SIGNAL ;
    PORT
      LAYER M4 ;
        RECT  66.876 7.536 66.96 7.56 ;
    END
  END ri1[102]
  PIN ri1[103]
    DIRECTION OUTPUT ;
    USE SIGNAL ;
    PORT
      LAYER M4 ;
        RECT  66.876 7.632 66.96 7.656 ;
    END
  END ri1[103]
  PIN ri1[104]
    DIRECTION OUTPUT ;
    USE SIGNAL ;
    PORT
      LAYER M4 ;
        RECT  66.876 7.728 66.96 7.752 ;
    END
  END ri1[104]
  PIN ri1[105]
    DIRECTION OUTPUT ;
    USE SIGNAL ;
    PORT
      LAYER M4 ;
        RECT  66.876 7.824 66.96 7.848 ;
    END
  END ri1[105]
  PIN ri1[106]
    DIRECTION OUTPUT ;
    USE SIGNAL ;
    PORT
      LAYER M4 ;
        RECT  66.876 7.92 66.96 7.944 ;
    END
  END ri1[106]
  PIN ri1[107]
    DIRECTION OUTPUT ;
    USE SIGNAL ;
    PORT
      LAYER M4 ;
        RECT  66.876 8.016 66.96 8.04 ;
    END
  END ri1[107]
  PIN ri1[108]
    DIRECTION OUTPUT ;
    USE SIGNAL ;
    PORT
      LAYER M4 ;
        RECT  66.876 8.112 66.96 8.136 ;
    END
  END ri1[108]
  PIN ri1[109]
    DIRECTION OUTPUT ;
    USE SIGNAL ;
    PORT
      LAYER M4 ;
        RECT  66.876 8.208 66.96 8.232 ;
    END
  END ri1[109]
  PIN ri1[10]
    DIRECTION OUTPUT ;
    USE SIGNAL ;
    PORT
      LAYER M6 ;
        RECT  66.891 40.256 66.96 40.288 ;
    END
  END ri1[10]
  PIN ri1[110]
    DIRECTION OUTPUT ;
    USE SIGNAL ;
    PORT
      LAYER M4 ;
        RECT  66.876 8.304 66.96 8.328 ;
    END
  END ri1[110]
  PIN ri1[111]
    DIRECTION OUTPUT ;
    USE SIGNAL ;
    PORT
      LAYER M4 ;
        RECT  66.876 8.4 66.96 8.424 ;
    END
  END ri1[111]
  PIN ri1[112]
    DIRECTION OUTPUT ;
    USE SIGNAL ;
    PORT
      LAYER M4 ;
        RECT  66.876 8.496 66.96 8.52 ;
    END
  END ri1[112]
  PIN ri1[113]
    DIRECTION OUTPUT ;
    USE SIGNAL ;
    PORT
      LAYER M4 ;
        RECT  66.876 8.592 66.96 8.616 ;
    END
  END ri1[113]
  PIN ri1[114]
    DIRECTION OUTPUT ;
    USE SIGNAL ;
    PORT
      LAYER M4 ;
        RECT  66.876 8.688 66.96 8.712 ;
    END
  END ri1[114]
  PIN ri1[115]
    DIRECTION OUTPUT ;
    USE SIGNAL ;
    PORT
      LAYER M4 ;
        RECT  66.876 8.784 66.96 8.808 ;
    END
  END ri1[115]
  PIN ri1[116]
    DIRECTION OUTPUT ;
    USE SIGNAL ;
    PORT
      LAYER M4 ;
        RECT  66.876 8.88 66.96 8.904 ;
    END
  END ri1[116]
  PIN ri1[117]
    DIRECTION OUTPUT ;
    USE SIGNAL ;
    PORT
      LAYER M4 ;
        RECT  66.876 8.976 66.96 9 ;
    END
  END ri1[117]
  PIN ri1[118]
    DIRECTION OUTPUT ;
    USE SIGNAL ;
    PORT
      LAYER M4 ;
        RECT  66.876 9.072 66.96 9.096 ;
    END
  END ri1[118]
  PIN ri1[119]
    DIRECTION OUTPUT ;
    USE SIGNAL ;
    PORT
      LAYER M4 ;
        RECT  66.876 9.168 66.96 9.192 ;
    END
  END ri1[119]
  PIN ri1[11]
    DIRECTION OUTPUT ;
    USE SIGNAL ;
    PORT
      LAYER M6 ;
        RECT  66.891 40.384 66.96 40.416 ;
    END
  END ri1[11]
  PIN ri1[120]
    DIRECTION OUTPUT ;
    USE SIGNAL ;
    PORT
      LAYER M4 ;
        RECT  66.876 9.264 66.96 9.288 ;
    END
  END ri1[120]
  PIN ri1[121]
    DIRECTION OUTPUT ;
    USE SIGNAL ;
    PORT
      LAYER M4 ;
        RECT  66.876 9.36 66.96 9.384 ;
    END
  END ri1[121]
  PIN ri1[122]
    DIRECTION OUTPUT ;
    USE SIGNAL ;
    PORT
      LAYER M4 ;
        RECT  66.876 9.456 66.96 9.48 ;
    END
  END ri1[122]
  PIN ri1[123]
    DIRECTION OUTPUT ;
    USE SIGNAL ;
    PORT
      LAYER M4 ;
        RECT  66.876 9.552 66.96 9.576 ;
    END
  END ri1[123]
  PIN ri1[124]
    DIRECTION OUTPUT ;
    USE SIGNAL ;
    PORT
      LAYER M4 ;
        RECT  66.876 9.648 66.96 9.672 ;
    END
  END ri1[124]
  PIN ri1[125]
    DIRECTION OUTPUT ;
    USE SIGNAL ;
    PORT
      LAYER M4 ;
        RECT  66.876 9.744 66.96 9.768 ;
    END
  END ri1[125]
  PIN ri1[126]
    DIRECTION OUTPUT ;
    USE SIGNAL ;
    PORT
      LAYER M4 ;
        RECT  66.876 9.84 66.96 9.864 ;
    END
  END ri1[126]
  PIN ri1[127]
    DIRECTION OUTPUT ;
    USE SIGNAL ;
    PORT
      LAYER M4 ;
        RECT  66.876 16.08 66.96 16.104 ;
    END
  END ri1[127]
  PIN ri1[128]
    DIRECTION OUTPUT ;
    USE SIGNAL ;
    PORT
      LAYER M4 ;
        RECT  66.876 16.176 66.96 16.2 ;
    END
  END ri1[128]
  PIN ri1[129]
    DIRECTION OUTPUT ;
    USE SIGNAL ;
    PORT
      LAYER M4 ;
        RECT  66.876 16.272 66.96 16.296 ;
    END
  END ri1[129]
  PIN ri1[12]
    DIRECTION OUTPUT ;
    USE SIGNAL ;
    PORT
      LAYER M6 ;
        RECT  66.891 40.512 66.96 40.544 ;
    END
  END ri1[12]
  PIN ri1[130]
    DIRECTION OUTPUT ;
    USE SIGNAL ;
    PORT
      LAYER M4 ;
        RECT  66.876 16.368 66.96 16.392 ;
    END
  END ri1[130]
  PIN ri1[131]
    DIRECTION OUTPUT ;
    USE SIGNAL ;
    PORT
      LAYER M4 ;
        RECT  66.876 16.464 66.96 16.488 ;
    END
  END ri1[131]
  PIN ri1[132]
    DIRECTION OUTPUT ;
    USE SIGNAL ;
    PORT
      LAYER M4 ;
        RECT  66.876 16.56 66.96 16.584 ;
    END
  END ri1[132]
  PIN ri1[133]
    DIRECTION OUTPUT ;
    USE SIGNAL ;
    PORT
      LAYER M4 ;
        RECT  66.876 16.656 66.96 16.68 ;
    END
  END ri1[133]
  PIN ri1[134]
    DIRECTION OUTPUT ;
    USE SIGNAL ;
    PORT
      LAYER M4 ;
        RECT  66.876 16.752 66.96 16.776 ;
    END
  END ri1[134]
  PIN ri1[135]
    DIRECTION OUTPUT ;
    USE SIGNAL ;
    PORT
      LAYER M4 ;
        RECT  66.876 16.848 66.96 16.872 ;
    END
  END ri1[135]
  PIN ri1[136]
    DIRECTION OUTPUT ;
    USE SIGNAL ;
    PORT
      LAYER M4 ;
        RECT  66.876 16.944 66.96 16.968 ;
    END
  END ri1[136]
  PIN ri1[137]
    DIRECTION OUTPUT ;
    USE SIGNAL ;
    PORT
      LAYER M4 ;
        RECT  66.876 17.04 66.96 17.064 ;
    END
  END ri1[137]
  PIN ri1[138]
    DIRECTION OUTPUT ;
    USE SIGNAL ;
    PORT
      LAYER M4 ;
        RECT  66.876 17.136 66.96 17.16 ;
    END
  END ri1[138]
  PIN ri1[139]
    DIRECTION OUTPUT ;
    USE SIGNAL ;
    PORT
      LAYER M4 ;
        RECT  66.876 17.232 66.96 17.256 ;
    END
  END ri1[139]
  PIN ri1[13]
    DIRECTION OUTPUT ;
    USE SIGNAL ;
    PORT
      LAYER M6 ;
        RECT  66.891 40.64 66.96 40.672 ;
    END
  END ri1[13]
  PIN ri1[140]
    DIRECTION OUTPUT ;
    USE SIGNAL ;
    PORT
      LAYER M4 ;
        RECT  66.876 17.328 66.96 17.352 ;
    END
  END ri1[140]
  PIN ri1[141]
    DIRECTION OUTPUT ;
    USE SIGNAL ;
    PORT
      LAYER M4 ;
        RECT  66.876 17.424 66.96 17.448 ;
    END
  END ri1[141]
  PIN ri1[142]
    DIRECTION OUTPUT ;
    USE SIGNAL ;
    PORT
      LAYER M4 ;
        RECT  66.876 17.52 66.96 17.544 ;
    END
  END ri1[142]
  PIN ri1[143]
    DIRECTION OUTPUT ;
    USE SIGNAL ;
    PORT
      LAYER M4 ;
        RECT  66.876 17.616 66.96 17.64 ;
    END
  END ri1[143]
  PIN ri1[144]
    DIRECTION OUTPUT ;
    USE SIGNAL ;
    PORT
      LAYER M4 ;
        RECT  66.876 17.712 66.96 17.736 ;
    END
  END ri1[144]
  PIN ri1[145]
    DIRECTION OUTPUT ;
    USE SIGNAL ;
    PORT
      LAYER M4 ;
        RECT  66.876 17.808 66.96 17.832 ;
    END
  END ri1[145]
  PIN ri1[146]
    DIRECTION OUTPUT ;
    USE SIGNAL ;
    PORT
      LAYER M4 ;
        RECT  66.876 17.904 66.96 17.928 ;
    END
  END ri1[146]
  PIN ri1[147]
    DIRECTION OUTPUT ;
    USE SIGNAL ;
    PORT
      LAYER M4 ;
        RECT  66.876 18 66.96 18.024 ;
    END
  END ri1[147]
  PIN ri1[148]
    DIRECTION OUTPUT ;
    USE SIGNAL ;
    PORT
      LAYER M4 ;
        RECT  66.876 18.096 66.96 18.12 ;
    END
  END ri1[148]
  PIN ri1[149]
    DIRECTION OUTPUT ;
    USE SIGNAL ;
    PORT
      LAYER M4 ;
        RECT  66.876 18.192 66.96 18.216 ;
    END
  END ri1[149]
  PIN ri1[14]
    DIRECTION OUTPUT ;
    USE SIGNAL ;
    PORT
      LAYER M6 ;
        RECT  66.891 40.768 66.96 40.8 ;
    END
  END ri1[14]
  PIN ri1[150]
    DIRECTION OUTPUT ;
    USE SIGNAL ;
    PORT
      LAYER M4 ;
        RECT  66.876 18.288 66.96 18.312 ;
    END
  END ri1[150]
  PIN ri1[151]
    DIRECTION OUTPUT ;
    USE SIGNAL ;
    PORT
      LAYER M4 ;
        RECT  66.876 18.384 66.96 18.408 ;
    END
  END ri1[151]
  PIN ri1[152]
    DIRECTION OUTPUT ;
    USE SIGNAL ;
    PORT
      LAYER M4 ;
        RECT  66.876 18.48 66.96 18.504 ;
    END
  END ri1[152]
  PIN ri1[153]
    DIRECTION OUTPUT ;
    USE SIGNAL ;
    PORT
      LAYER M4 ;
        RECT  66.876 18.576 66.96 18.6 ;
    END
  END ri1[153]
  PIN ri1[154]
    DIRECTION OUTPUT ;
    USE SIGNAL ;
    PORT
      LAYER M4 ;
        RECT  66.876 18.672 66.96 18.696 ;
    END
  END ri1[154]
  PIN ri1[155]
    DIRECTION OUTPUT ;
    USE SIGNAL ;
    PORT
      LAYER M4 ;
        RECT  66.876 18.768 66.96 18.792 ;
    END
  END ri1[155]
  PIN ri1[156]
    DIRECTION OUTPUT ;
    USE SIGNAL ;
    PORT
      LAYER M4 ;
        RECT  66.876 18.864 66.96 18.888 ;
    END
  END ri1[156]
  PIN ri1[157]
    DIRECTION OUTPUT ;
    USE SIGNAL ;
    PORT
      LAYER M4 ;
        RECT  66.876 18.96 66.96 18.984 ;
    END
  END ri1[157]
  PIN ri1[158]
    DIRECTION OUTPUT ;
    USE SIGNAL ;
    PORT
      LAYER M4 ;
        RECT  66.876 19.056 66.96 19.08 ;
    END
  END ri1[158]
  PIN ri1[159]
    DIRECTION OUTPUT ;
    USE SIGNAL ;
    PORT
      LAYER M4 ;
        RECT  66.876 22.992 66.96 23.016 ;
    END
  END ri1[159]
  PIN ri1[15]
    DIRECTION OUTPUT ;
    USE SIGNAL ;
    PORT
      LAYER M6 ;
        RECT  66.891 40.896 66.96 40.928 ;
    END
  END ri1[15]
  PIN ri1[160]
    DIRECTION OUTPUT ;
    USE SIGNAL ;
    PORT
      LAYER M4 ;
        RECT  66.876 23.088 66.96 23.112 ;
    END
  END ri1[160]
  PIN ri1[161]
    DIRECTION OUTPUT ;
    USE SIGNAL ;
    PORT
      LAYER M4 ;
        RECT  66.876 23.184 66.96 23.208 ;
    END
  END ri1[161]
  PIN ri1[162]
    DIRECTION OUTPUT ;
    USE SIGNAL ;
    PORT
      LAYER M4 ;
        RECT  66.876 23.28 66.96 23.304 ;
    END
  END ri1[162]
  PIN ri1[163]
    DIRECTION OUTPUT ;
    USE SIGNAL ;
    PORT
      LAYER M4 ;
        RECT  66.876 23.376 66.96 23.4 ;
    END
  END ri1[163]
  PIN ri1[164]
    DIRECTION OUTPUT ;
    USE SIGNAL ;
    PORT
      LAYER M4 ;
        RECT  66.876 23.472 66.96 23.496 ;
    END
  END ri1[164]
  PIN ri1[165]
    DIRECTION OUTPUT ;
    USE SIGNAL ;
    PORT
      LAYER M4 ;
        RECT  66.876 23.568 66.96 23.592 ;
    END
  END ri1[165]
  PIN ri1[166]
    DIRECTION OUTPUT ;
    USE SIGNAL ;
    PORT
      LAYER M4 ;
        RECT  66.876 23.664 66.96 23.688 ;
    END
  END ri1[166]
  PIN ri1[167]
    DIRECTION OUTPUT ;
    USE SIGNAL ;
    PORT
      LAYER M4 ;
        RECT  66.876 23.76 66.96 23.784 ;
    END
  END ri1[167]
  PIN ri1[168]
    DIRECTION OUTPUT ;
    USE SIGNAL ;
    PORT
      LAYER M4 ;
        RECT  66.876 23.856 66.96 23.88 ;
    END
  END ri1[168]
  PIN ri1[169]
    DIRECTION OUTPUT ;
    USE SIGNAL ;
    PORT
      LAYER M4 ;
        RECT  66.876 23.952 66.96 23.976 ;
    END
  END ri1[169]
  PIN ri1[16]
    DIRECTION OUTPUT ;
    USE SIGNAL ;
    PORT
      LAYER M6 ;
        RECT  66.891 41.024 66.96 41.056 ;
    END
  END ri1[16]
  PIN ri1[170]
    DIRECTION OUTPUT ;
    USE SIGNAL ;
    PORT
      LAYER M4 ;
        RECT  66.876 24.048 66.96 24.072 ;
    END
  END ri1[170]
  PIN ri1[171]
    DIRECTION OUTPUT ;
    USE SIGNAL ;
    PORT
      LAYER M4 ;
        RECT  66.876 24.144 66.96 24.168 ;
    END
  END ri1[171]
  PIN ri1[172]
    DIRECTION OUTPUT ;
    USE SIGNAL ;
    PORT
      LAYER M4 ;
        RECT  66.876 24.24 66.96 24.264 ;
    END
  END ri1[172]
  PIN ri1[173]
    DIRECTION OUTPUT ;
    USE SIGNAL ;
    PORT
      LAYER M4 ;
        RECT  66.876 24.336 66.96 24.36 ;
    END
  END ri1[173]
  PIN ri1[174]
    DIRECTION OUTPUT ;
    USE SIGNAL ;
    PORT
      LAYER M4 ;
        RECT  66.876 24.432 66.96 24.456 ;
    END
  END ri1[174]
  PIN ri1[175]
    DIRECTION OUTPUT ;
    USE SIGNAL ;
    PORT
      LAYER M4 ;
        RECT  66.876 24.528 66.96 24.552 ;
    END
  END ri1[175]
  PIN ri1[176]
    DIRECTION OUTPUT ;
    USE SIGNAL ;
    PORT
      LAYER M4 ;
        RECT  66.876 24.624 66.96 24.648 ;
    END
  END ri1[176]
  PIN ri1[177]
    DIRECTION OUTPUT ;
    USE SIGNAL ;
    PORT
      LAYER M4 ;
        RECT  66.876 24.72 66.96 24.744 ;
    END
  END ri1[177]
  PIN ri1[178]
    DIRECTION OUTPUT ;
    USE SIGNAL ;
    PORT
      LAYER M4 ;
        RECT  66.876 24.816 66.96 24.84 ;
    END
  END ri1[178]
  PIN ri1[179]
    DIRECTION OUTPUT ;
    USE SIGNAL ;
    PORT
      LAYER M4 ;
        RECT  66.876 24.912 66.96 24.936 ;
    END
  END ri1[179]
  PIN ri1[17]
    DIRECTION OUTPUT ;
    USE SIGNAL ;
    PORT
      LAYER M6 ;
        RECT  66.891 41.152 66.96 41.184 ;
    END
  END ri1[17]
  PIN ri1[180]
    DIRECTION OUTPUT ;
    USE SIGNAL ;
    PORT
      LAYER M4 ;
        RECT  66.876 25.008 66.96 25.032 ;
    END
  END ri1[180]
  PIN ri1[181]
    DIRECTION OUTPUT ;
    USE SIGNAL ;
    PORT
      LAYER M4 ;
        RECT  66.876 25.104 66.96 25.128 ;
    END
  END ri1[181]
  PIN ri1[182]
    DIRECTION OUTPUT ;
    USE SIGNAL ;
    PORT
      LAYER M4 ;
        RECT  66.876 25.2 66.96 25.224 ;
    END
  END ri1[182]
  PIN ri1[183]
    DIRECTION OUTPUT ;
    USE SIGNAL ;
    PORT
      LAYER M4 ;
        RECT  66.876 25.296 66.96 25.32 ;
    END
  END ri1[183]
  PIN ri1[184]
    DIRECTION OUTPUT ;
    USE SIGNAL ;
    PORT
      LAYER M4 ;
        RECT  66.876 25.392 66.96 25.416 ;
    END
  END ri1[184]
  PIN ri1[185]
    DIRECTION OUTPUT ;
    USE SIGNAL ;
    PORT
      LAYER M4 ;
        RECT  66.876 25.488 66.96 25.512 ;
    END
  END ri1[185]
  PIN ri1[186]
    DIRECTION OUTPUT ;
    USE SIGNAL ;
    PORT
      LAYER M4 ;
        RECT  66.876 25.584 66.96 25.608 ;
    END
  END ri1[186]
  PIN ri1[187]
    DIRECTION OUTPUT ;
    USE SIGNAL ;
    PORT
      LAYER M4 ;
        RECT  66.876 25.68 66.96 25.704 ;
    END
  END ri1[187]
  PIN ri1[188]
    DIRECTION OUTPUT ;
    USE SIGNAL ;
    PORT
      LAYER M4 ;
        RECT  66.876 25.776 66.96 25.8 ;
    END
  END ri1[188]
  PIN ri1[189]
    DIRECTION OUTPUT ;
    USE SIGNAL ;
    PORT
      LAYER M4 ;
        RECT  66.876 25.872 66.96 25.896 ;
    END
  END ri1[189]
  PIN ri1[18]
    DIRECTION OUTPUT ;
    USE SIGNAL ;
    PORT
      LAYER M6 ;
        RECT  66.891 41.28 66.96 41.312 ;
    END
  END ri1[18]
  PIN ri1[190]
    DIRECTION OUTPUT ;
    USE SIGNAL ;
    PORT
      LAYER M4 ;
        RECT  66.876 25.968 66.96 25.992 ;
    END
  END ri1[190]
  PIN ri1[191]
    DIRECTION OUTPUT ;
    USE SIGNAL ;
    PORT
      LAYER M6 ;
        RECT  66.891 47.04 66.96 47.072 ;
    END
  END ri1[191]
  PIN ri1[192]
    DIRECTION OUTPUT ;
    USE SIGNAL ;
    PORT
      LAYER M6 ;
        RECT  66.891 47.168 66.96 47.2 ;
    END
  END ri1[192]
  PIN ri1[193]
    DIRECTION OUTPUT ;
    USE SIGNAL ;
    PORT
      LAYER M6 ;
        RECT  66.891 47.296 66.96 47.328 ;
    END
  END ri1[193]
  PIN ri1[194]
    DIRECTION OUTPUT ;
    USE SIGNAL ;
    PORT
      LAYER M6 ;
        RECT  66.891 47.424 66.96 47.456 ;
    END
  END ri1[194]
  PIN ri1[195]
    DIRECTION OUTPUT ;
    USE SIGNAL ;
    PORT
      LAYER M6 ;
        RECT  66.891 47.552 66.96 47.584 ;
    END
  END ri1[195]
  PIN ri1[196]
    DIRECTION OUTPUT ;
    USE SIGNAL ;
    PORT
      LAYER M6 ;
        RECT  66.891 47.68 66.96 47.712 ;
    END
  END ri1[196]
  PIN ri1[197]
    DIRECTION OUTPUT ;
    USE SIGNAL ;
    PORT
      LAYER M6 ;
        RECT  66.891 47.808 66.96 47.84 ;
    END
  END ri1[197]
  PIN ri1[198]
    DIRECTION OUTPUT ;
    USE SIGNAL ;
    PORT
      LAYER M6 ;
        RECT  66.891 47.936 66.96 47.968 ;
    END
  END ri1[198]
  PIN ri1[199]
    DIRECTION OUTPUT ;
    USE SIGNAL ;
    PORT
      LAYER M6 ;
        RECT  66.891 48.064 66.96 48.096 ;
    END
  END ri1[199]
  PIN ri1[19]
    DIRECTION OUTPUT ;
    USE SIGNAL ;
    PORT
      LAYER M6 ;
        RECT  66.891 41.408 66.96 41.44 ;
    END
  END ri1[19]
  PIN ri1[1]
    DIRECTION OUTPUT ;
    USE SIGNAL ;
    PORT
      LAYER M6 ;
        RECT  66.891 39.104 66.96 39.136 ;
    END
  END ri1[1]
  PIN ri1[200]
    DIRECTION OUTPUT ;
    USE SIGNAL ;
    PORT
      LAYER M6 ;
        RECT  66.891 48.192 66.96 48.224 ;
    END
  END ri1[200]
  PIN ri1[201]
    DIRECTION OUTPUT ;
    USE SIGNAL ;
    PORT
      LAYER M6 ;
        RECT  66.891 48.32 66.96 48.352 ;
    END
  END ri1[201]
  PIN ri1[202]
    DIRECTION OUTPUT ;
    USE SIGNAL ;
    PORT
      LAYER M6 ;
        RECT  66.891 48.448 66.96 48.48 ;
    END
  END ri1[202]
  PIN ri1[203]
    DIRECTION OUTPUT ;
    USE SIGNAL ;
    PORT
      LAYER M6 ;
        RECT  66.891 48.576 66.96 48.608 ;
    END
  END ri1[203]
  PIN ri1[204]
    DIRECTION OUTPUT ;
    USE SIGNAL ;
    PORT
      LAYER M6 ;
        RECT  66.891 48.704 66.96 48.736 ;
    END
  END ri1[204]
  PIN ri1[205]
    DIRECTION OUTPUT ;
    USE SIGNAL ;
    PORT
      LAYER M6 ;
        RECT  66.891 48.832 66.96 48.864 ;
    END
  END ri1[205]
  PIN ri1[206]
    DIRECTION OUTPUT ;
    USE SIGNAL ;
    PORT
      LAYER M6 ;
        RECT  66.891 48.96 66.96 48.992 ;
    END
  END ri1[206]
  PIN ri1[207]
    DIRECTION OUTPUT ;
    USE SIGNAL ;
    PORT
      LAYER M6 ;
        RECT  66.891 49.088 66.96 49.12 ;
    END
  END ri1[207]
  PIN ri1[208]
    DIRECTION OUTPUT ;
    USE SIGNAL ;
    PORT
      LAYER M6 ;
        RECT  66.891 49.216 66.96 49.248 ;
    END
  END ri1[208]
  PIN ri1[209]
    DIRECTION OUTPUT ;
    USE SIGNAL ;
    PORT
      LAYER M6 ;
        RECT  66.891 49.344 66.96 49.376 ;
    END
  END ri1[209]
  PIN ri1[20]
    DIRECTION OUTPUT ;
    USE SIGNAL ;
    PORT
      LAYER M6 ;
        RECT  66.891 41.536 66.96 41.568 ;
    END
  END ri1[20]
  PIN ri1[210]
    DIRECTION OUTPUT ;
    USE SIGNAL ;
    PORT
      LAYER M6 ;
        RECT  66.891 49.472 66.96 49.504 ;
    END
  END ri1[210]
  PIN ri1[211]
    DIRECTION OUTPUT ;
    USE SIGNAL ;
    PORT
      LAYER M6 ;
        RECT  66.891 49.6 66.96 49.632 ;
    END
  END ri1[211]
  PIN ri1[212]
    DIRECTION OUTPUT ;
    USE SIGNAL ;
    PORT
      LAYER M6 ;
        RECT  66.891 49.728 66.96 49.76 ;
    END
  END ri1[212]
  PIN ri1[213]
    DIRECTION OUTPUT ;
    USE SIGNAL ;
    PORT
      LAYER M6 ;
        RECT  66.891 49.856 66.96 49.888 ;
    END
  END ri1[213]
  PIN ri1[214]
    DIRECTION OUTPUT ;
    USE SIGNAL ;
    PORT
      LAYER M6 ;
        RECT  66.891 49.984 66.96 50.016 ;
    END
  END ri1[214]
  PIN ri1[215]
    DIRECTION OUTPUT ;
    USE SIGNAL ;
    PORT
      LAYER M6 ;
        RECT  66.891 50.112 66.96 50.144 ;
    END
  END ri1[215]
  PIN ri1[216]
    DIRECTION OUTPUT ;
    USE SIGNAL ;
    PORT
      LAYER M6 ;
        RECT  66.891 50.24 66.96 50.272 ;
    END
  END ri1[216]
  PIN ri1[217]
    DIRECTION OUTPUT ;
    USE SIGNAL ;
    PORT
      LAYER M6 ;
        RECT  66.891 50.368 66.96 50.4 ;
    END
  END ri1[217]
  PIN ri1[218]
    DIRECTION OUTPUT ;
    USE SIGNAL ;
    PORT
      LAYER M6 ;
        RECT  66.891 50.496 66.96 50.528 ;
    END
  END ri1[218]
  PIN ri1[219]
    DIRECTION OUTPUT ;
    USE SIGNAL ;
    PORT
      LAYER M6 ;
        RECT  66.891 50.624 66.96 50.656 ;
    END
  END ri1[219]
  PIN ri1[21]
    DIRECTION OUTPUT ;
    USE SIGNAL ;
    PORT
      LAYER M6 ;
        RECT  66.891 41.664 66.96 41.696 ;
    END
  END ri1[21]
  PIN ri1[220]
    DIRECTION OUTPUT ;
    USE SIGNAL ;
    PORT
      LAYER M6 ;
        RECT  66.891 50.752 66.96 50.784 ;
    END
  END ri1[220]
  PIN ri1[221]
    DIRECTION OUTPUT ;
    USE SIGNAL ;
    PORT
      LAYER M6 ;
        RECT  66.891 50.88 66.96 50.912 ;
    END
  END ri1[221]
  PIN ri1[222]
    DIRECTION OUTPUT ;
    USE SIGNAL ;
    PORT
      LAYER M6 ;
        RECT  66.891 51.008 66.96 51.04 ;
    END
  END ri1[222]
  PIN ri1[223]
    DIRECTION OUTPUT ;
    USE SIGNAL ;
    PORT
      LAYER M6 ;
        RECT  66.891 56.256 66.96 56.288 ;
    END
  END ri1[223]
  PIN ri1[224]
    DIRECTION OUTPUT ;
    USE SIGNAL ;
    PORT
      LAYER M6 ;
        RECT  66.891 56.384 66.96 56.416 ;
    END
  END ri1[224]
  PIN ri1[225]
    DIRECTION OUTPUT ;
    USE SIGNAL ;
    PORT
      LAYER M6 ;
        RECT  66.891 56.512 66.96 56.544 ;
    END
  END ri1[225]
  PIN ri1[226]
    DIRECTION OUTPUT ;
    USE SIGNAL ;
    PORT
      LAYER M6 ;
        RECT  66.891 56.64 66.96 56.672 ;
    END
  END ri1[226]
  PIN ri1[227]
    DIRECTION OUTPUT ;
    USE SIGNAL ;
    PORT
      LAYER M6 ;
        RECT  66.891 56.768 66.96 56.8 ;
    END
  END ri1[227]
  PIN ri1[228]
    DIRECTION OUTPUT ;
    USE SIGNAL ;
    PORT
      LAYER M6 ;
        RECT  66.891 56.896 66.96 56.928 ;
    END
  END ri1[228]
  PIN ri1[229]
    DIRECTION OUTPUT ;
    USE SIGNAL ;
    PORT
      LAYER M6 ;
        RECT  66.891 57.024 66.96 57.056 ;
    END
  END ri1[229]
  PIN ri1[22]
    DIRECTION OUTPUT ;
    USE SIGNAL ;
    PORT
      LAYER M6 ;
        RECT  66.891 41.792 66.96 41.824 ;
    END
  END ri1[22]
  PIN ri1[230]
    DIRECTION OUTPUT ;
    USE SIGNAL ;
    PORT
      LAYER M6 ;
        RECT  66.891 57.152 66.96 57.184 ;
    END
  END ri1[230]
  PIN ri1[231]
    DIRECTION OUTPUT ;
    USE SIGNAL ;
    PORT
      LAYER M6 ;
        RECT  66.891 57.28 66.96 57.312 ;
    END
  END ri1[231]
  PIN ri1[232]
    DIRECTION OUTPUT ;
    USE SIGNAL ;
    PORT
      LAYER M6 ;
        RECT  66.891 57.408 66.96 57.44 ;
    END
  END ri1[232]
  PIN ri1[233]
    DIRECTION OUTPUT ;
    USE SIGNAL ;
    PORT
      LAYER M6 ;
        RECT  66.891 57.536 66.96 57.568 ;
    END
  END ri1[233]
  PIN ri1[234]
    DIRECTION OUTPUT ;
    USE SIGNAL ;
    PORT
      LAYER M6 ;
        RECT  66.891 57.664 66.96 57.696 ;
    END
  END ri1[234]
  PIN ri1[235]
    DIRECTION OUTPUT ;
    USE SIGNAL ;
    PORT
      LAYER M6 ;
        RECT  66.891 57.792 66.96 57.824 ;
    END
  END ri1[235]
  PIN ri1[236]
    DIRECTION OUTPUT ;
    USE SIGNAL ;
    PORT
      LAYER M6 ;
        RECT  66.891 57.92 66.96 57.952 ;
    END
  END ri1[236]
  PIN ri1[237]
    DIRECTION OUTPUT ;
    USE SIGNAL ;
    PORT
      LAYER M6 ;
        RECT  66.891 58.048 66.96 58.08 ;
    END
  END ri1[237]
  PIN ri1[238]
    DIRECTION OUTPUT ;
    USE SIGNAL ;
    PORT
      LAYER M6 ;
        RECT  66.891 58.176 66.96 58.208 ;
    END
  END ri1[238]
  PIN ri1[239]
    DIRECTION OUTPUT ;
    USE SIGNAL ;
    PORT
      LAYER M6 ;
        RECT  66.891 58.304 66.96 58.336 ;
    END
  END ri1[239]
  PIN ri1[23]
    DIRECTION OUTPUT ;
    USE SIGNAL ;
    PORT
      LAYER M6 ;
        RECT  66.891 41.92 66.96 41.952 ;
    END
  END ri1[23]
  PIN ri1[240]
    DIRECTION OUTPUT ;
    USE SIGNAL ;
    PORT
      LAYER M6 ;
        RECT  66.891 58.432 66.96 58.464 ;
    END
  END ri1[240]
  PIN ri1[241]
    DIRECTION OUTPUT ;
    USE SIGNAL ;
    PORT
      LAYER M6 ;
        RECT  66.891 58.56 66.96 58.592 ;
    END
  END ri1[241]
  PIN ri1[242]
    DIRECTION OUTPUT ;
    USE SIGNAL ;
    PORT
      LAYER M6 ;
        RECT  66.891 58.688 66.96 58.72 ;
    END
  END ri1[242]
  PIN ri1[243]
    DIRECTION OUTPUT ;
    USE SIGNAL ;
    PORT
      LAYER M6 ;
        RECT  66.891 58.816 66.96 58.848 ;
    END
  END ri1[243]
  PIN ri1[244]
    DIRECTION OUTPUT ;
    USE SIGNAL ;
    PORT
      LAYER M6 ;
        RECT  66.891 58.944 66.96 58.976 ;
    END
  END ri1[244]
  PIN ri1[245]
    DIRECTION OUTPUT ;
    USE SIGNAL ;
    PORT
      LAYER M6 ;
        RECT  66.891 59.072 66.96 59.104 ;
    END
  END ri1[245]
  PIN ri1[246]
    DIRECTION OUTPUT ;
    USE SIGNAL ;
    PORT
      LAYER M6 ;
        RECT  66.891 59.2 66.96 59.232 ;
    END
  END ri1[246]
  PIN ri1[247]
    DIRECTION OUTPUT ;
    USE SIGNAL ;
    PORT
      LAYER M6 ;
        RECT  66.891 59.328 66.96 59.36 ;
    END
  END ri1[247]
  PIN ri1[248]
    DIRECTION OUTPUT ;
    USE SIGNAL ;
    PORT
      LAYER M6 ;
        RECT  66.891 59.456 66.96 59.488 ;
    END
  END ri1[248]
  PIN ri1[249]
    DIRECTION OUTPUT ;
    USE SIGNAL ;
    PORT
      LAYER M6 ;
        RECT  66.891 59.584 66.96 59.616 ;
    END
  END ri1[249]
  PIN ri1[24]
    DIRECTION OUTPUT ;
    USE SIGNAL ;
    PORT
      LAYER M6 ;
        RECT  66.891 42.048 66.96 42.08 ;
    END
  END ri1[24]
  PIN ri1[250]
    DIRECTION OUTPUT ;
    USE SIGNAL ;
    PORT
      LAYER M6 ;
        RECT  66.891 59.712 66.96 59.744 ;
    END
  END ri1[250]
  PIN ri1[251]
    DIRECTION OUTPUT ;
    USE SIGNAL ;
    PORT
      LAYER M6 ;
        RECT  66.891 59.84 66.96 59.872 ;
    END
  END ri1[251]
  PIN ri1[252]
    DIRECTION OUTPUT ;
    USE SIGNAL ;
    PORT
      LAYER M6 ;
        RECT  66.891 59.968 66.96 60 ;
    END
  END ri1[252]
  PIN ri1[253]
    DIRECTION OUTPUT ;
    USE SIGNAL ;
    PORT
      LAYER M6 ;
        RECT  66.891 60.096 66.96 60.128 ;
    END
  END ri1[253]
  PIN ri1[254]
    DIRECTION OUTPUT ;
    USE SIGNAL ;
    PORT
      LAYER M6 ;
        RECT  66.891 60.224 66.96 60.256 ;
    END
  END ri1[254]
  PIN ri1[255]
    DIRECTION OUTPUT ;
    USE SIGNAL ;
    PORT
      LAYER M4 ;
        RECT  66.876 51.408 66.96 51.432 ;
    END
  END ri1[255]
  PIN ri1[256]
    DIRECTION OUTPUT ;
    USE SIGNAL ;
    PORT
      LAYER M4 ;
        RECT  66.876 51.504 66.96 51.528 ;
    END
  END ri1[256]
  PIN ri1[257]
    DIRECTION OUTPUT ;
    USE SIGNAL ;
    PORT
      LAYER M4 ;
        RECT  66.876 51.6 66.96 51.624 ;
    END
  END ri1[257]
  PIN ri1[258]
    DIRECTION OUTPUT ;
    USE SIGNAL ;
    PORT
      LAYER M4 ;
        RECT  66.876 51.696 66.96 51.72 ;
    END
  END ri1[258]
  PIN ri1[259]
    DIRECTION OUTPUT ;
    USE SIGNAL ;
    PORT
      LAYER M4 ;
        RECT  66.876 51.792 66.96 51.816 ;
    END
  END ri1[259]
  PIN ri1[25]
    DIRECTION OUTPUT ;
    USE SIGNAL ;
    PORT
      LAYER M6 ;
        RECT  66.891 42.176 66.96 42.208 ;
    END
  END ri1[25]
  PIN ri1[260]
    DIRECTION OUTPUT ;
    USE SIGNAL ;
    PORT
      LAYER M4 ;
        RECT  66.876 51.888 66.96 51.912 ;
    END
  END ri1[260]
  PIN ri1[261]
    DIRECTION OUTPUT ;
    USE SIGNAL ;
    PORT
      LAYER M4 ;
        RECT  66.876 51.984 66.96 52.008 ;
    END
  END ri1[261]
  PIN ri1[262]
    DIRECTION OUTPUT ;
    USE SIGNAL ;
    PORT
      LAYER M4 ;
        RECT  66.876 52.08 66.96 52.104 ;
    END
  END ri1[262]
  PIN ri1[263]
    DIRECTION OUTPUT ;
    USE SIGNAL ;
    PORT
      LAYER M4 ;
        RECT  66.876 52.176 66.96 52.2 ;
    END
  END ri1[263]
  PIN ri1[264]
    DIRECTION OUTPUT ;
    USE SIGNAL ;
    PORT
      LAYER M4 ;
        RECT  66.876 52.272 66.96 52.296 ;
    END
  END ri1[264]
  PIN ri1[265]
    DIRECTION OUTPUT ;
    USE SIGNAL ;
    PORT
      LAYER M4 ;
        RECT  66.876 52.368 66.96 52.392 ;
    END
  END ri1[265]
  PIN ri1[26]
    DIRECTION OUTPUT ;
    USE SIGNAL ;
    PORT
      LAYER M6 ;
        RECT  66.891 42.304 66.96 42.336 ;
    END
  END ri1[26]
  PIN ri1[27]
    DIRECTION OUTPUT ;
    USE SIGNAL ;
    PORT
      LAYER M6 ;
        RECT  66.891 42.432 66.96 42.464 ;
    END
  END ri1[27]
  PIN ri1[28]
    DIRECTION OUTPUT ;
    USE SIGNAL ;
    PORT
      LAYER M6 ;
        RECT  66.891 42.56 66.96 42.592 ;
    END
  END ri1[28]
  PIN ri1[29]
    DIRECTION OUTPUT ;
    USE SIGNAL ;
    PORT
      LAYER M6 ;
        RECT  66.891 42.688 66.96 42.72 ;
    END
  END ri1[29]
  PIN ri1[2]
    DIRECTION OUTPUT ;
    USE SIGNAL ;
    PORT
      LAYER M6 ;
        RECT  66.891 39.232 66.96 39.264 ;
    END
  END ri1[2]
  PIN ri1[30]
    DIRECTION OUTPUT ;
    USE SIGNAL ;
    PORT
      LAYER M6 ;
        RECT  66.891 42.816 66.96 42.848 ;
    END
  END ri1[30]
  PIN ri1[31]
    DIRECTION OUTPUT ;
    USE SIGNAL ;
    PORT
      LAYER M4 ;
        RECT  66.876 29.136 66.96 29.16 ;
    END
  END ri1[31]
  PIN ri1[32]
    DIRECTION OUTPUT ;
    USE SIGNAL ;
    PORT
      LAYER M4 ;
        RECT  66.876 29.232 66.96 29.256 ;
    END
  END ri1[32]
  PIN ri1[33]
    DIRECTION OUTPUT ;
    USE SIGNAL ;
    PORT
      LAYER M4 ;
        RECT  66.876 29.328 66.96 29.352 ;
    END
  END ri1[33]
  PIN ri1[34]
    DIRECTION OUTPUT ;
    USE SIGNAL ;
    PORT
      LAYER M4 ;
        RECT  66.876 29.424 66.96 29.448 ;
    END
  END ri1[34]
  PIN ri1[35]
    DIRECTION OUTPUT ;
    USE SIGNAL ;
    PORT
      LAYER M4 ;
        RECT  66.876 29.52 66.96 29.544 ;
    END
  END ri1[35]
  PIN ri1[36]
    DIRECTION OUTPUT ;
    USE SIGNAL ;
    PORT
      LAYER M4 ;
        RECT  66.876 29.616 66.96 29.64 ;
    END
  END ri1[36]
  PIN ri1[37]
    DIRECTION OUTPUT ;
    USE SIGNAL ;
    PORT
      LAYER M4 ;
        RECT  66.876 29.712 66.96 29.736 ;
    END
  END ri1[37]
  PIN ri1[38]
    DIRECTION OUTPUT ;
    USE SIGNAL ;
    PORT
      LAYER M4 ;
        RECT  66.876 29.808 66.96 29.832 ;
    END
  END ri1[38]
  PIN ri1[39]
    DIRECTION OUTPUT ;
    USE SIGNAL ;
    PORT
      LAYER M4 ;
        RECT  66.876 29.904 66.96 29.928 ;
    END
  END ri1[39]
  PIN ri1[3]
    DIRECTION OUTPUT ;
    USE SIGNAL ;
    PORT
      LAYER M6 ;
        RECT  66.891 39.36 66.96 39.392 ;
    END
  END ri1[3]
  PIN ri1[40]
    DIRECTION OUTPUT ;
    USE SIGNAL ;
    PORT
      LAYER M4 ;
        RECT  66.876 30 66.96 30.024 ;
    END
  END ri1[40]
  PIN ri1[41]
    DIRECTION OUTPUT ;
    USE SIGNAL ;
    PORT
      LAYER M4 ;
        RECT  66.876 30.096 66.96 30.12 ;
    END
  END ri1[41]
  PIN ri1[42]
    DIRECTION OUTPUT ;
    USE SIGNAL ;
    PORT
      LAYER M4 ;
        RECT  66.876 30.192 66.96 30.216 ;
    END
  END ri1[42]
  PIN ri1[43]
    DIRECTION OUTPUT ;
    USE SIGNAL ;
    PORT
      LAYER M4 ;
        RECT  66.876 30.288 66.96 30.312 ;
    END
  END ri1[43]
  PIN ri1[44]
    DIRECTION OUTPUT ;
    USE SIGNAL ;
    PORT
      LAYER M4 ;
        RECT  66.876 30.384 66.96 30.408 ;
    END
  END ri1[44]
  PIN ri1[45]
    DIRECTION OUTPUT ;
    USE SIGNAL ;
    PORT
      LAYER M4 ;
        RECT  66.876 30.48 66.96 30.504 ;
    END
  END ri1[45]
  PIN ri1[46]
    DIRECTION OUTPUT ;
    USE SIGNAL ;
    PORT
      LAYER M4 ;
        RECT  66.876 30.576 66.96 30.6 ;
    END
  END ri1[46]
  PIN ri1[47]
    DIRECTION OUTPUT ;
    USE SIGNAL ;
    PORT
      LAYER M4 ;
        RECT  66.876 30.672 66.96 30.696 ;
    END
  END ri1[47]
  PIN ri1[48]
    DIRECTION OUTPUT ;
    USE SIGNAL ;
    PORT
      LAYER M4 ;
        RECT  66.876 30.768 66.96 30.792 ;
    END
  END ri1[48]
  PIN ri1[49]
    DIRECTION OUTPUT ;
    USE SIGNAL ;
    PORT
      LAYER M4 ;
        RECT  66.876 30.864 66.96 30.888 ;
    END
  END ri1[49]
  PIN ri1[4]
    DIRECTION OUTPUT ;
    USE SIGNAL ;
    PORT
      LAYER M6 ;
        RECT  66.891 39.488 66.96 39.52 ;
    END
  END ri1[4]
  PIN ri1[50]
    DIRECTION OUTPUT ;
    USE SIGNAL ;
    PORT
      LAYER M4 ;
        RECT  66.876 30.96 66.96 30.984 ;
    END
  END ri1[50]
  PIN ri1[51]
    DIRECTION OUTPUT ;
    USE SIGNAL ;
    PORT
      LAYER M4 ;
        RECT  66.876 31.056 66.96 31.08 ;
    END
  END ri1[51]
  PIN ri1[52]
    DIRECTION OUTPUT ;
    USE SIGNAL ;
    PORT
      LAYER M4 ;
        RECT  66.876 31.152 66.96 31.176 ;
    END
  END ri1[52]
  PIN ri1[53]
    DIRECTION OUTPUT ;
    USE SIGNAL ;
    PORT
      LAYER M4 ;
        RECT  66.876 31.248 66.96 31.272 ;
    END
  END ri1[53]
  PIN ri1[54]
    DIRECTION OUTPUT ;
    USE SIGNAL ;
    PORT
      LAYER M4 ;
        RECT  66.876 31.344 66.96 31.368 ;
    END
  END ri1[54]
  PIN ri1[55]
    DIRECTION OUTPUT ;
    USE SIGNAL ;
    PORT
      LAYER M4 ;
        RECT  66.876 31.44 66.96 31.464 ;
    END
  END ri1[55]
  PIN ri1[56]
    DIRECTION OUTPUT ;
    USE SIGNAL ;
    PORT
      LAYER M4 ;
        RECT  66.876 31.536 66.96 31.56 ;
    END
  END ri1[56]
  PIN ri1[57]
    DIRECTION OUTPUT ;
    USE SIGNAL ;
    PORT
      LAYER M4 ;
        RECT  66.876 31.632 66.96 31.656 ;
    END
  END ri1[57]
  PIN ri1[58]
    DIRECTION OUTPUT ;
    USE SIGNAL ;
    PORT
      LAYER M4 ;
        RECT  66.876 31.728 66.96 31.752 ;
    END
  END ri1[58]
  PIN ri1[59]
    DIRECTION OUTPUT ;
    USE SIGNAL ;
    PORT
      LAYER M4 ;
        RECT  66.876 31.824 66.96 31.848 ;
    END
  END ri1[59]
  PIN ri1[5]
    DIRECTION OUTPUT ;
    USE SIGNAL ;
    PORT
      LAYER M6 ;
        RECT  66.891 39.616 66.96 39.648 ;
    END
  END ri1[5]
  PIN ri1[60]
    DIRECTION OUTPUT ;
    USE SIGNAL ;
    PORT
      LAYER M4 ;
        RECT  66.876 31.92 66.96 31.944 ;
    END
  END ri1[60]
  PIN ri1[61]
    DIRECTION OUTPUT ;
    USE SIGNAL ;
    PORT
      LAYER M4 ;
        RECT  66.876 32.016 66.96 32.04 ;
    END
  END ri1[61]
  PIN ri1[62]
    DIRECTION OUTPUT ;
    USE SIGNAL ;
    PORT
      LAYER M4 ;
        RECT  66.876 32.112 66.96 32.136 ;
    END
  END ri1[62]
  PIN ri1[63]
    DIRECTION OUTPUT ;
    USE SIGNAL ;
    PORT
      LAYER M6 ;
        RECT  66.891 21.44 66.96 21.472 ;
    END
  END ri1[63]
  PIN ri1[64]
    DIRECTION OUTPUT ;
    USE SIGNAL ;
    PORT
      LAYER M6 ;
        RECT  66.891 21.568 66.96 21.6 ;
    END
  END ri1[64]
  PIN ri1[65]
    DIRECTION OUTPUT ;
    USE SIGNAL ;
    PORT
      LAYER M6 ;
        RECT  66.891 21.696 66.96 21.728 ;
    END
  END ri1[65]
  PIN ri1[66]
    DIRECTION OUTPUT ;
    USE SIGNAL ;
    PORT
      LAYER M6 ;
        RECT  66.891 21.824 66.96 21.856 ;
    END
  END ri1[66]
  PIN ri1[67]
    DIRECTION OUTPUT ;
    USE SIGNAL ;
    PORT
      LAYER M6 ;
        RECT  66.891 21.952 66.96 21.984 ;
    END
  END ri1[67]
  PIN ri1[68]
    DIRECTION OUTPUT ;
    USE SIGNAL ;
    PORT
      LAYER M6 ;
        RECT  66.891 22.08 66.96 22.112 ;
    END
  END ri1[68]
  PIN ri1[69]
    DIRECTION OUTPUT ;
    USE SIGNAL ;
    PORT
      LAYER M6 ;
        RECT  66.891 22.208 66.96 22.24 ;
    END
  END ri1[69]
  PIN ri1[6]
    DIRECTION OUTPUT ;
    USE SIGNAL ;
    PORT
      LAYER M6 ;
        RECT  66.891 39.744 66.96 39.776 ;
    END
  END ri1[6]
  PIN ri1[70]
    DIRECTION OUTPUT ;
    USE SIGNAL ;
    PORT
      LAYER M6 ;
        RECT  66.891 22.336 66.96 22.368 ;
    END
  END ri1[70]
  PIN ri1[71]
    DIRECTION OUTPUT ;
    USE SIGNAL ;
    PORT
      LAYER M6 ;
        RECT  66.891 22.464 66.96 22.496 ;
    END
  END ri1[71]
  PIN ri1[72]
    DIRECTION OUTPUT ;
    USE SIGNAL ;
    PORT
      LAYER M6 ;
        RECT  66.891 22.592 66.96 22.624 ;
    END
  END ri1[72]
  PIN ri1[73]
    DIRECTION OUTPUT ;
    USE SIGNAL ;
    PORT
      LAYER M6 ;
        RECT  66.891 22.72 66.96 22.752 ;
    END
  END ri1[73]
  PIN ri1[74]
    DIRECTION OUTPUT ;
    USE SIGNAL ;
    PORT
      LAYER M6 ;
        RECT  66.891 22.848 66.96 22.88 ;
    END
  END ri1[74]
  PIN ri1[75]
    DIRECTION OUTPUT ;
    USE SIGNAL ;
    PORT
      LAYER M6 ;
        RECT  66.891 22.976 66.96 23.008 ;
    END
  END ri1[75]
  PIN ri1[76]
    DIRECTION OUTPUT ;
    USE SIGNAL ;
    PORT
      LAYER M6 ;
        RECT  66.891 23.104 66.96 23.136 ;
    END
  END ri1[76]
  PIN ri1[77]
    DIRECTION OUTPUT ;
    USE SIGNAL ;
    PORT
      LAYER M6 ;
        RECT  66.891 23.232 66.96 23.264 ;
    END
  END ri1[77]
  PIN ri1[78]
    DIRECTION OUTPUT ;
    USE SIGNAL ;
    PORT
      LAYER M6 ;
        RECT  66.891 23.36 66.96 23.392 ;
    END
  END ri1[78]
  PIN ri1[79]
    DIRECTION OUTPUT ;
    USE SIGNAL ;
    PORT
      LAYER M6 ;
        RECT  66.891 23.488 66.96 23.52 ;
    END
  END ri1[79]
  PIN ri1[7]
    DIRECTION OUTPUT ;
    USE SIGNAL ;
    PORT
      LAYER M6 ;
        RECT  66.891 39.872 66.96 39.904 ;
    END
  END ri1[7]
  PIN ri1[80]
    DIRECTION OUTPUT ;
    USE SIGNAL ;
    PORT
      LAYER M6 ;
        RECT  66.891 23.616 66.96 23.648 ;
    END
  END ri1[80]
  PIN ri1[81]
    DIRECTION OUTPUT ;
    USE SIGNAL ;
    PORT
      LAYER M6 ;
        RECT  66.891 23.744 66.96 23.776 ;
    END
  END ri1[81]
  PIN ri1[82]
    DIRECTION OUTPUT ;
    USE SIGNAL ;
    PORT
      LAYER M6 ;
        RECT  66.891 23.872 66.96 23.904 ;
    END
  END ri1[82]
  PIN ri1[83]
    DIRECTION OUTPUT ;
    USE SIGNAL ;
    PORT
      LAYER M6 ;
        RECT  66.891 24 66.96 24.032 ;
    END
  END ri1[83]
  PIN ri1[84]
    DIRECTION OUTPUT ;
    USE SIGNAL ;
    PORT
      LAYER M6 ;
        RECT  66.891 24.128 66.96 24.16 ;
    END
  END ri1[84]
  PIN ri1[85]
    DIRECTION OUTPUT ;
    USE SIGNAL ;
    PORT
      LAYER M6 ;
        RECT  66.891 24.256 66.96 24.288 ;
    END
  END ri1[85]
  PIN ri1[86]
    DIRECTION OUTPUT ;
    USE SIGNAL ;
    PORT
      LAYER M6 ;
        RECT  66.891 24.384 66.96 24.416 ;
    END
  END ri1[86]
  PIN ri1[87]
    DIRECTION OUTPUT ;
    USE SIGNAL ;
    PORT
      LAYER M6 ;
        RECT  66.891 24.512 66.96 24.544 ;
    END
  END ri1[87]
  PIN ri1[88]
    DIRECTION OUTPUT ;
    USE SIGNAL ;
    PORT
      LAYER M6 ;
        RECT  66.891 24.64 66.96 24.672 ;
    END
  END ri1[88]
  PIN ri1[89]
    DIRECTION OUTPUT ;
    USE SIGNAL ;
    PORT
      LAYER M6 ;
        RECT  66.891 24.768 66.96 24.8 ;
    END
  END ri1[89]
  PIN ri1[8]
    DIRECTION OUTPUT ;
    USE SIGNAL ;
    PORT
      LAYER M6 ;
        RECT  66.891 40 66.96 40.032 ;
    END
  END ri1[8]
  PIN ri1[90]
    DIRECTION OUTPUT ;
    USE SIGNAL ;
    PORT
      LAYER M6 ;
        RECT  66.891 24.896 66.96 24.928 ;
    END
  END ri1[90]
  PIN ri1[91]
    DIRECTION OUTPUT ;
    USE SIGNAL ;
    PORT
      LAYER M6 ;
        RECT  66.891 25.024 66.96 25.056 ;
    END
  END ri1[91]
  PIN ri1[92]
    DIRECTION OUTPUT ;
    USE SIGNAL ;
    PORT
      LAYER M6 ;
        RECT  66.891 25.152 66.96 25.184 ;
    END
  END ri1[92]
  PIN ri1[93]
    DIRECTION OUTPUT ;
    USE SIGNAL ;
    PORT
      LAYER M6 ;
        RECT  66.891 25.28 66.96 25.312 ;
    END
  END ri1[93]
  PIN ri1[94]
    DIRECTION OUTPUT ;
    USE SIGNAL ;
    PORT
      LAYER M6 ;
        RECT  66.891 25.408 66.96 25.44 ;
    END
  END ri1[94]
  PIN ri1[95]
    DIRECTION OUTPUT ;
    USE SIGNAL ;
    PORT
      LAYER M4 ;
        RECT  66.876 6.864 66.96 6.888 ;
    END
  END ri1[95]
  PIN ri1[96]
    DIRECTION OUTPUT ;
    USE SIGNAL ;
    PORT
      LAYER M4 ;
        RECT  66.876 6.96 66.96 6.984 ;
    END
  END ri1[96]
  PIN ri1[97]
    DIRECTION OUTPUT ;
    USE SIGNAL ;
    PORT
      LAYER M4 ;
        RECT  66.876 7.056 66.96 7.08 ;
    END
  END ri1[97]
  PIN ri1[98]
    DIRECTION OUTPUT ;
    USE SIGNAL ;
    PORT
      LAYER M4 ;
        RECT  66.876 7.152 66.96 7.176 ;
    END
  END ri1[98]
  PIN ri1[99]
    DIRECTION OUTPUT ;
    USE SIGNAL ;
    PORT
      LAYER M4 ;
        RECT  66.876 7.248 66.96 7.272 ;
    END
  END ri1[99]
  PIN ri1[9]
    DIRECTION OUTPUT ;
    USE SIGNAL ;
    PORT
      LAYER M6 ;
        RECT  66.891 40.128 66.96 40.16 ;
    END
  END ri1[9]
  PIN ri1_cr
    DIRECTION INPUT ;
    USE SIGNAL ;
    PORT
      LAYER M4 ;
        RECT  66.876 52.464 66.96 52.488 ;
    END
  END ri1_cr
  PIN rst_n
    DIRECTION INPUT ;
    USE SIGNAL ;
    PORT
      LAYER M5 ;
        RECT  47.088 0 47.112 0.084 ;
    END
  END rst_n
  PIN sid[0]
    DIRECTION INPUT ;
    USE SIGNAL ;
    PORT
      LAYER M5 ;
        RECT  47.184 0 47.208 0.084 ;
    END
  END sid[0]
  PIN sid[1]
    DIRECTION INPUT ;
    USE SIGNAL ;
    PORT
      LAYER M5 ;
        RECT  47.28 0 47.304 0.084 ;
    END
  END sid[1]
  PIN VDD
    DIRECTION INOUT ;
    USE POWER ;
    PORT
      LAYER M6 ;
        RECT  2.16 58.4 64.8 58.688 ;
        RECT  2.16 47.6 64.8 47.888 ;
        RECT  2.16 36.8 64.8 37.088 ;
        RECT  2.16 26 64.8 26.288 ;
        RECT  2.16 15.2 64.8 15.488 ;
        RECT  2.16 4.4 64.8 4.688 ;
    END
  END VDD
  PIN VSS
    DIRECTION INOUT ;
    USE GROUND ;
    PORT
      LAYER M6 ;
        RECT  2.16 58.016 64.8 58.304 ;
        RECT  2.16 47.216 64.8 47.504 ;
        RECT  2.16 36.416 64.8 36.704 ;
        RECT  2.16 25.616 64.8 25.904 ;
        RECT  2.16 14.816 64.8 15.104 ;
        RECT  2.16 4.016 64.8 4.304 ;
    END
  END VSS
  OBS
    LAYER RVTN ;
     RECT  2.16 2.16 64.8 2.295 ;
     RECT  2.16 2.565 64.8 2.835 ;
     RECT  2.16 3.105 64.8 3.375 ;
     RECT  2.16 3.645 64.8 3.915 ;
     RECT  2.16 4.185 64.8 4.455 ;
     RECT  2.16 4.725 64.8 4.995 ;
     RECT  2.16 5.265 64.8 5.535 ;
     RECT  2.16 5.805 64.8 6.075 ;
     RECT  2.16 6.345 64.8 6.615 ;
     RECT  2.16 6.885 64.8 7.155 ;
     RECT  2.16 7.425 64.8 7.695 ;
     RECT  2.16 7.965 64.8 8.235 ;
     RECT  2.16 8.505 64.8 8.775 ;
     RECT  2.16 9.045 64.8 9.315 ;
     RECT  2.16 9.585 64.8 9.855 ;
     RECT  2.16 10.125 64.8 10.395 ;
     RECT  2.16 10.665 64.8 10.935 ;
     RECT  2.16 11.205 64.8 11.475 ;
     RECT  2.16 11.745 64.8 12.015 ;
     RECT  2.16 12.285 64.8 12.555 ;
     RECT  2.16 12.825 64.8 13.095 ;
     RECT  2.16 13.365 64.8 13.635 ;
     RECT  2.16 13.905 64.8 14.175 ;
     RECT  2.16 14.445 64.8 14.715 ;
     RECT  2.16 14.985 64.8 15.255 ;
     RECT  2.16 15.525 64.8 15.795 ;
     RECT  2.16 16.065 64.8 16.335 ;
     RECT  2.16 16.605 64.8 16.875 ;
     RECT  2.16 17.145 64.8 17.415 ;
     RECT  2.16 17.685 64.8 17.955 ;
     RECT  2.16 18.225 64.8 18.495 ;
     RECT  2.16 18.765 64.8 19.035 ;
     RECT  2.16 19.305 64.8 19.575 ;
     RECT  2.16 19.845 64.8 20.115 ;
     RECT  2.16 20.385 64.8 20.655 ;
     RECT  2.16 20.925 64.8 21.195 ;
     RECT  2.16 21.465 64.8 21.735 ;
     RECT  2.16 22.005 64.8 22.275 ;
     RECT  2.16 22.545 64.8 22.815 ;
     RECT  2.16 23.085 64.8 23.355 ;
     RECT  2.16 23.625 64.8 23.895 ;
     RECT  2.16 24.165 64.8 24.435 ;
     RECT  2.16 24.705 64.8 24.975 ;
     RECT  2.16 25.245 64.8 25.515 ;
     RECT  2.16 25.785 64.8 26.055 ;
     RECT  2.16 26.325 64.8 26.595 ;
     RECT  2.16 26.865 64.8 27.135 ;
     RECT  2.16 27.405 64.8 27.675 ;
     RECT  2.16 27.945 64.8 28.215 ;
     RECT  2.16 28.485 64.8 28.755 ;
     RECT  2.16 29.025 64.8 29.295 ;
     RECT  2.16 29.565 64.8 29.835 ;
     RECT  2.16 30.105 64.8 30.375 ;
     RECT  2.16 30.645 64.8 30.915 ;
     RECT  2.16 31.185 64.8 31.455 ;
     RECT  2.16 31.725 64.8 31.995 ;
     RECT  2.16 32.265 64.8 32.535 ;
     RECT  2.16 32.805 64.8 33.075 ;
     RECT  2.16 33.345 64.8 33.615 ;
     RECT  2.16 33.885 64.8 34.155 ;
     RECT  2.16 34.425 64.8 34.695 ;
     RECT  2.16 34.965 64.8 35.235 ;
     RECT  2.16 35.505 64.8 35.775 ;
     RECT  2.16 36.045 64.8 36.315 ;
     RECT  2.16 36.585 64.8 36.855 ;
     RECT  2.16 37.125 64.8 37.395 ;
     RECT  2.16 37.665 64.8 37.935 ;
     RECT  2.16 38.205 64.8 38.475 ;
     RECT  2.16 38.745 64.8 39.015 ;
     RECT  2.16 39.285 64.8 39.555 ;
     RECT  2.16 39.825 64.8 40.095 ;
     RECT  2.16 40.365 64.8 40.635 ;
     RECT  2.16 40.905 64.8 41.175 ;
     RECT  2.16 41.445 64.8 41.715 ;
     RECT  2.16 41.985 64.8 42.255 ;
     RECT  2.16 42.525 64.8 42.795 ;
     RECT  2.16 43.065 64.8 43.335 ;
     RECT  2.16 43.605 64.8 43.875 ;
     RECT  2.16 44.145 64.8 44.415 ;
     RECT  2.16 44.685 64.8 44.955 ;
     RECT  2.16 45.225 64.8 45.495 ;
     RECT  2.16 45.765 64.8 46.035 ;
     RECT  2.16 46.305 64.8 46.575 ;
     RECT  2.16 46.845 64.8 47.115 ;
     RECT  2.16 47.385 64.8 47.655 ;
     RECT  2.16 47.925 64.8 48.195 ;
     RECT  2.16 48.465 64.8 48.735 ;
     RECT  2.16 49.005 64.8 49.275 ;
     RECT  2.16 49.545 64.8 49.815 ;
     RECT  2.16 50.085 64.8 50.355 ;
     RECT  2.16 50.625 64.8 50.895 ;
     RECT  2.16 51.165 64.8 51.435 ;
     RECT  2.16 51.705 64.8 51.975 ;
     RECT  2.16 52.245 64.8 52.515 ;
     RECT  2.16 52.785 64.8 53.055 ;
     RECT  2.16 53.325 64.8 53.595 ;
     RECT  2.16 53.865 64.8 54.135 ;
     RECT  2.16 54.405 64.8 54.675 ;
     RECT  2.16 54.945 64.8 55.215 ;
     RECT  2.16 55.485 64.8 55.755 ;
     RECT  2.16 56.025 64.8 56.295 ;
     RECT  2.16 56.565 64.8 56.835 ;
     RECT  2.16 57.105 64.8 57.375 ;
     RECT  2.16 57.645 64.8 57.915 ;
     RECT  2.16 58.185 64.8 58.455 ;
     RECT  2.16 58.725 64.8 58.995 ;
     RECT  2.16 59.265 64.8 59.535 ;
     RECT  2.16 59.805 64.8 60.075 ;
     RECT  2.16 60.345 64.8 60.615 ;
     RECT  2.16 60.885 64.8 61.155 ;
     RECT  2.16 61.425 64.8 61.695 ;
     RECT  2.16 61.965 64.8 62.235 ;
     RECT  2.16 62.505 64.8 62.775 ;
     RECT  2.16 63.045 64.8 63.315 ;
     RECT  2.16 63.585 64.8 63.855 ;
     RECT  2.16 64.125 64.8 64.395 ;
     RECT  2.16 64.665 64.8 64.8 ;
    LAYER RVTP ;
     RECT  2.16 2.295 64.8 2.565 ;
     RECT  2.16 2.835 64.8 3.105 ;
     RECT  2.16 3.375 64.8 3.645 ;
     RECT  2.16 3.915 64.8 4.185 ;
     RECT  2.16 4.455 64.8 4.725 ;
     RECT  2.16 4.995 64.8 5.265 ;
     RECT  2.16 5.535 64.8 5.805 ;
     RECT  2.16 6.075 64.8 6.345 ;
     RECT  2.16 6.615 64.8 6.885 ;
     RECT  2.16 7.155 64.8 7.425 ;
     RECT  2.16 7.695 64.8 7.965 ;
     RECT  2.16 8.235 64.8 8.505 ;
     RECT  2.16 8.775 64.8 9.045 ;
     RECT  2.16 9.315 64.8 9.585 ;
     RECT  2.16 9.855 64.8 10.125 ;
     RECT  2.16 10.395 64.8 10.665 ;
     RECT  2.16 10.935 64.8 11.205 ;
     RECT  2.16 11.475 64.8 11.745 ;
     RECT  2.16 12.015 64.8 12.285 ;
     RECT  2.16 12.555 64.8 12.825 ;
     RECT  2.16 13.095 64.8 13.365 ;
     RECT  2.16 13.635 64.8 13.905 ;
     RECT  2.16 14.175 64.8 14.445 ;
     RECT  2.16 14.715 64.8 14.985 ;
     RECT  2.16 15.255 64.8 15.525 ;
     RECT  2.16 15.795 64.8 16.065 ;
     RECT  2.16 16.335 64.8 16.605 ;
     RECT  2.16 16.875 64.8 17.145 ;
     RECT  2.16 17.415 64.8 17.685 ;
     RECT  2.16 17.955 64.8 18.225 ;
     RECT  2.16 18.495 64.8 18.765 ;
     RECT  2.16 19.035 64.8 19.305 ;
     RECT  2.16 19.575 64.8 19.845 ;
     RECT  2.16 20.115 64.8 20.385 ;
     RECT  2.16 20.655 64.8 20.925 ;
     RECT  2.16 21.195 64.8 21.465 ;
     RECT  2.16 21.735 64.8 22.005 ;
     RECT  2.16 22.275 64.8 22.545 ;
     RECT  2.16 22.815 64.8 23.085 ;
     RECT  2.16 23.355 64.8 23.625 ;
     RECT  2.16 23.895 64.8 24.165 ;
     RECT  2.16 24.435 64.8 24.705 ;
     RECT  2.16 24.975 64.8 25.245 ;
     RECT  2.16 25.515 64.8 25.785 ;
     RECT  2.16 26.055 64.8 26.325 ;
     RECT  2.16 26.595 64.8 26.865 ;
     RECT  2.16 27.135 64.8 27.405 ;
     RECT  2.16 27.675 64.8 27.945 ;
     RECT  2.16 28.215 64.8 28.485 ;
     RECT  2.16 28.755 64.8 29.025 ;
     RECT  2.16 29.295 64.8 29.565 ;
     RECT  2.16 29.835 64.8 30.105 ;
     RECT  2.16 30.375 64.8 30.645 ;
     RECT  2.16 30.915 64.8 31.185 ;
     RECT  2.16 31.455 64.8 31.725 ;
     RECT  2.16 31.995 64.8 32.265 ;
     RECT  2.16 32.535 64.8 32.805 ;
     RECT  2.16 33.075 64.8 33.345 ;
     RECT  2.16 33.615 64.8 33.885 ;
     RECT  2.16 34.155 64.8 34.425 ;
     RECT  2.16 34.695 64.8 34.965 ;
     RECT  2.16 35.235 64.8 35.505 ;
     RECT  2.16 35.775 64.8 36.045 ;
     RECT  2.16 36.315 64.8 36.585 ;
     RECT  2.16 36.855 64.8 37.125 ;
     RECT  2.16 37.395 64.8 37.665 ;
     RECT  2.16 37.935 64.8 38.205 ;
     RECT  2.16 38.475 64.8 38.745 ;
     RECT  2.16 39.015 64.8 39.285 ;
     RECT  2.16 39.555 64.8 39.825 ;
     RECT  2.16 40.095 64.8 40.365 ;
     RECT  2.16 40.635 64.8 40.905 ;
     RECT  2.16 41.175 64.8 41.445 ;
     RECT  2.16 41.715 64.8 41.985 ;
     RECT  2.16 42.255 64.8 42.525 ;
     RECT  2.16 42.795 64.8 43.065 ;
     RECT  2.16 43.335 64.8 43.605 ;
     RECT  2.16 43.875 64.8 44.145 ;
     RECT  2.16 44.415 64.8 44.685 ;
     RECT  2.16 44.955 64.8 45.225 ;
     RECT  2.16 45.495 64.8 45.765 ;
     RECT  2.16 46.035 64.8 46.305 ;
     RECT  2.16 46.575 64.8 46.845 ;
     RECT  2.16 47.115 64.8 47.385 ;
     RECT  2.16 47.655 64.8 47.925 ;
     RECT  2.16 48.195 64.8 48.465 ;
     RECT  2.16 48.735 64.8 49.005 ;
     RECT  2.16 49.275 64.8 49.545 ;
     RECT  2.16 49.815 64.8 50.085 ;
     RECT  2.16 50.355 64.8 50.625 ;
     RECT  2.16 50.895 64.8 51.165 ;
     RECT  2.16 51.435 64.8 51.705 ;
     RECT  2.16 51.975 64.8 52.245 ;
     RECT  2.16 52.515 64.8 52.785 ;
     RECT  2.16 53.055 64.8 53.325 ;
     RECT  2.16 53.595 64.8 53.865 ;
     RECT  2.16 54.135 64.8 54.405 ;
     RECT  2.16 54.675 64.8 54.945 ;
     RECT  2.16 55.215 64.8 55.485 ;
     RECT  2.16 55.755 64.8 56.025 ;
     RECT  2.16 56.295 64.8 56.565 ;
     RECT  2.16 56.835 64.8 57.105 ;
     RECT  2.16 57.375 64.8 57.645 ;
     RECT  2.16 57.915 64.8 58.185 ;
     RECT  2.16 58.455 64.8 58.725 ;
     RECT  2.16 58.995 64.8 59.265 ;
     RECT  2.16 59.535 64.8 59.805 ;
     RECT  2.16 60.075 64.8 60.345 ;
     RECT  2.16 60.615 64.8 60.885 ;
     RECT  2.16 61.155 64.8 61.425 ;
     RECT  2.16 61.695 64.8 61.965 ;
     RECT  2.16 62.235 64.8 62.505 ;
     RECT  2.16 62.775 64.8 63.045 ;
     RECT  2.16 63.315 64.8 63.585 ;
     RECT  2.16 63.855 64.8 64.125 ;
     RECT  2.16 64.395 64.8 64.665 ;
    LAYER M1 ;
     RECT  2.16 2.151 64.8 64.809 ;
    LAYER M2 ;
     RECT  0.031 46.701 0.131 46.719 ;
     RECT  0.103 8.55 0.139 8.568 ;
     RECT  0.067 41.841 0.139 41.859 ;
     RECT  0.139 41.22 0.167 41.859 ;
     RECT  0.103 20.43 0.203 20.448 ;
     RECT  0.175 6.66 0.211 6.678 ;
     RECT  0.103 21.474 0.211 21.492 ;
     RECT  0.103 19.278 0.239 19.602 ;
     RECT  0.103 59.508 0.239 59.526 ;
     RECT  0.211 15.876 0.311 15.894 ;
     RECT  0.211 6.588 0.347 6.678 ;
     RECT  0.103 38.52 0.347 38.538 ;
     RECT  0.103 40.302 0.347 40.32 ;
     RECT  0.167 41.22 0.347 41.238 ;
     RECT  0.347 6.588 0.355 6.606 ;
     RECT  0.139 57.276 0.355 57.294 ;
     RECT  0.355 6.084 0.383 6.606 ;
     RECT  0.239 19.548 0.383 19.602 ;
     RECT  0.175 42.3 0.383 42.318 ;
     RECT  0.355 56.844 0.383 57.294 ;
     RECT  0.499 39.366 0.535 39.384 ;
     RECT  0.139 43.956 0.535 43.974 ;
     RECT  0.383 56.844 1.111 56.862 ;
     RECT  0.383 6.084 1.147 6.102 ;
     RECT  0.103 17.046 1.147 17.064 ;
     RECT  1.147 5.976 1.183 6.102 ;
     RECT  0.139 8.55 1.183 9.144 ;
     RECT  1.183 8.55 1.211 9.504 ;
     RECT  1.147 16.146 1.399 17.064 ;
     RECT  1.183 5.976 1.687 6.264 ;
     RECT  1.687 5.706 1.867 6.264 ;
     RECT  1.867 5.706 1.975 6.912 ;
     RECT  1.211 8.55 1.975 8.568 ;
     RECT  1.211 9.486 1.975 9.504 ;
     RECT  1.975 8.55 2.083 9.504 ;
     RECT  2.083 8.55 2.119 9.882 ;
     RECT  1.975 12.492 2.119 12.51 ;
     RECT  1.975 5.706 2.155 7.488 ;
     RECT  2.047 11.682 2.155 11.7 ;
     RECT  0.535 4.536 2.16 4.554 ;
     RECT  2.155 5.706 2.16 7.614 ;
     RECT  2.119 8.514 2.16 9.882 ;
     RECT  2.155 10.944 2.16 11.7 ;
     RECT  2.119 12.492 2.16 12.852 ;
     RECT  2.083 14.382 2.16 14.4 ;
     RECT  1.399 16.146 2.16 17.442 ;
     RECT  1.147 18.396 2.16 18.414 ;
     RECT  0.383 19.584 2.16 19.602 ;
     RECT  0.211 21.204 2.16 21.492 ;
     RECT  0.571 22.356 2.16 22.374 ;
     RECT  0.823 23.634 2.16 23.652 ;
     RECT  2.155 37.206 2.16 37.224 ;
     RECT  0.535 38.79 2.16 39.384 ;
     RECT  1.723 40.806 2.16 40.824 ;
     RECT  2.155 42.696 2.16 42.714 ;
     RECT  0.535 43.65 2.16 43.974 ;
     RECT  0.067 45.036 2.16 45.054 ;
     RECT  1.111 56.844 2.16 57.564 ;
     RECT  2.119 59.742 2.16 59.76 ;
     RECT  2.16 2.151 3.019 64.809 ;
     RECT  3.019 2.034 3.947 64.809 ;
     RECT  3.947 2.07 4.487 64.809 ;
     RECT  4.487 2.106 4.891 64.809 ;
     RECT  4.891 2.106 5.279 64.926 ;
     RECT  5.279 2.151 6.575 64.926 ;
     RECT  6.575 2.151 7.519 64.854 ;
     RECT  7.519 2.151 8.519 64.89 ;
     RECT  8.519 2.151 11.263 64.854 ;
     RECT  11.263 2.151 12.299 64.926 ;
     RECT  12.299 2.151 23.359 64.809 ;
     RECT  23.359 2.106 23.999 64.809 ;
     RECT  23.999 2.151 25.735 64.809 ;
     RECT  25.735 2.07 26.779 64.809 ;
     RECT  26.779 2.034 27.391 64.809 ;
     RECT  27.391 1.764 29.587 64.809 ;
     RECT  29.587 1.764 29.975 64.854 ;
     RECT  29.975 1.836 31.487 64.809 ;
     RECT  31.487 2.106 32.755 64.809 ;
     RECT  32.755 2.034 33.251 64.809 ;
     RECT  33.251 2.106 33.655 64.809 ;
     RECT  33.655 2.106 33.755 64.962 ;
     RECT  33.755 2.106 34.583 64.809 ;
     RECT  34.583 2.151 35.995 64.809 ;
     RECT  35.995 1.962 38.111 64.809 ;
     RECT  38.111 2.106 38.507 64.809 ;
     RECT  38.507 2.151 42.907 64.809 ;
     RECT  42.907 2.106 43.655 64.809 ;
     RECT  43.655 2.151 46.867 64.809 ;
     RECT  46.867 2.106 48.155 64.809 ;
     RECT  49.999 1.152 50.135 1.17 ;
     RECT  48.155 2.151 50.179 64.809 ;
     RECT  50.179 1.998 52.699 64.809 ;
     RECT  52.699 1.962 53.987 64.809 ;
     RECT  53.987 1.998 54.455 64.809 ;
     RECT  54.455 2.034 54.779 64.809 ;
     RECT  54.779 2.106 56.263 64.809 ;
     RECT  56.263 2.07 56.471 64.809 ;
     RECT  56.471 2.151 57.703 64.809 ;
     RECT  57.703 2.034 58.235 64.809 ;
     RECT  58.235 2.106 58.991 64.809 ;
     RECT  58.991 2.151 64.8 64.809 ;
     RECT  64.8 30.888 64.859 43.434 ;
     RECT  64.8 44.19 64.967 53.28 ;
     RECT  64.8 59.886 64.967 64.386 ;
     RECT  64.859 30.888 65.003 39.852 ;
     RECT  64.8 6.156 65.039 19.944 ;
     RECT  65.003 30.888 65.075 39.384 ;
     RECT  65.039 9.36 65.255 19.944 ;
     RECT  64.8 20.736 65.543 30.096 ;
     RECT  64.859 40.644 65.543 43.434 ;
     RECT  65.543 27.99 65.579 30.096 ;
     RECT  65.075 30.888 65.579 39.042 ;
     RECT  65.543 40.644 65.579 41.814 ;
     RECT  64.8 54.45 65.579 59.094 ;
     RECT  64.967 59.886 65.579 61.956 ;
     RECT  65.255 9.36 65.831 19.062 ;
     RECT  65.543 21.942 65.831 27.234 ;
     RECT  65.831 11.826 65.903 19.062 ;
     RECT  65.903 12.366 65.975 19.062 ;
     RECT  64.967 44.19 66.047 52.74 ;
     RECT  65.831 23.166 66.083 27.234 ;
     RECT  65.579 54.45 66.083 58.14 ;
     RECT  65.039 6.156 66.119 8.532 ;
     RECT  65.975 12.762 66.119 19.062 ;
     RECT  65.831 21.942 66.119 22.194 ;
     RECT  66.083 25.956 66.119 27.234 ;
     RECT  65.579 34.092 66.119 36.306 ;
     RECT  65.579 37.062 66.119 39.042 ;
     RECT  65.543 42.606 66.119 43.434 ;
     RECT  66.047 44.19 66.119 47.07 ;
     RECT  66.047 48.096 66.119 52.74 ;
     RECT  65.579 58.896 66.119 59.094 ;
     RECT  65.579 59.886 66.119 60.84 ;
     RECT  65.579 61.632 66.119 61.956 ;
     RECT  64.967 62.748 66.119 64.386 ;
     RECT  66.119 6.156 66.155 7.758 ;
     RECT  65.831 9.36 66.155 10.998 ;
     RECT  66.119 12.834 66.155 17.712 ;
     RECT  65.543 20.736 66.155 20.754 ;
     RECT  66.119 22.176 66.155 22.194 ;
     RECT  66.083 23.166 66.155 25.074 ;
     RECT  66.119 26.676 66.155 27.234 ;
     RECT  65.579 28.386 66.155 30.096 ;
     RECT  66.119 38.214 66.155 39.042 ;
     RECT  66.119 43.11 66.155 43.434 ;
     RECT  66.119 44.19 66.155 45.288 ;
     RECT  66.119 46.854 66.155 47.07 ;
     RECT  66.119 48.636 66.155 52.47 ;
     RECT  66.083 54.45 66.155 57.6 ;
     RECT  66.119 63.558 66.155 64.386 ;
     RECT  66.155 9.36 66.191 10.728 ;
     RECT  66.155 27.18 66.191 27.234 ;
     RECT  66.155 54.882 66.191 55.746 ;
     RECT  66.191 9.792 66.227 10.728 ;
     RECT  66.119 18.54 66.227 19.062 ;
     RECT  66.227 10.098 66.263 10.116 ;
     RECT  65.255 19.926 66.515 19.944 ;
     RECT  66.155 28.566 66.559 30.096 ;
     RECT  65.579 30.888 66.559 33.3 ;
     RECT  66.155 12.834 66.731 16.83 ;
     RECT  66.155 23.166 66.731 23.724 ;
     RECT  66.155 17.586 66.767 17.712 ;
     RECT  66.731 23.166 66.767 23.184 ;
     RECT  66.155 38.412 66.767 39.042 ;
     RECT  66.155 48.672 66.767 52.47 ;
     RECT  66.731 14.112 66.803 16.83 ;
     RECT  66.767 38.412 66.803 38.97 ;
     RECT  66.767 48.672 66.803 50.85 ;
     RECT  66.155 6.246 66.839 7.254 ;
     RECT  66.731 12.834 66.839 13.086 ;
     RECT  66.803 14.112 66.839 14.67 ;
     RECT  66.803 15.732 66.839 16.02 ;
     RECT  66.803 16.776 66.839 16.83 ;
     RECT  66.119 34.902 66.839 36.306 ;
     RECT  66.119 37.062 66.839 37.35 ;
     RECT  66.803 38.484 66.839 38.97 ;
     RECT  65.579 41.796 66.839 41.814 ;
     RECT  66.119 46.044 66.839 46.062 ;
     RECT  66.155 47.052 66.839 47.07 ;
     RECT  66.803 49.482 66.839 50.616 ;
     RECT  66.767 51.642 66.839 52.47 ;
     RECT  66.155 63.558 66.839 63.918 ;
     RECT  66.839 6.246 66.875 6.264 ;
     RECT  66.839 7.236 66.875 7.254 ;
     RECT  66.119 8.514 66.875 8.532 ;
     RECT  66.839 12.906 66.875 13.086 ;
     RECT  66.839 14.112 66.875 14.13 ;
     RECT  66.839 15.732 66.875 15.75 ;
     RECT  66.839 16.812 66.875 16.83 ;
     RECT  66.227 19.044 66.875 19.062 ;
     RECT  66.155 24.48 66.875 25.074 ;
     RECT  66.191 27.18 66.875 27.198 ;
     RECT  66.559 28.566 66.875 33.3 ;
     RECT  66.119 34.092 66.875 34.11 ;
     RECT  66.839 34.902 66.875 35.46 ;
     RECT  66.839 36.288 66.875 36.306 ;
     RECT  66.839 37.332 66.875 37.35 ;
     RECT  66.839 38.484 66.875 38.502 ;
     RECT  66.803 48.708 66.875 48.726 ;
     RECT  66.839 50.022 66.875 50.31 ;
     RECT  66.839 52.182 66.875 52.47 ;
     RECT  66.191 54.882 66.875 55.476 ;
     RECT  66.155 57.078 66.875 57.6 ;
     RECT  66.119 59.076 66.875 59.094 ;
     RECT  66.119 60.552 66.875 60.57 ;
     RECT  66.119 61.938 66.875 61.956 ;
     RECT  66.119 62.748 66.875 62.766 ;
     RECT  66.839 63.9 66.875 63.918 ;
     RECT  66.875 12.906 66.947 12.924 ;
     RECT  66.767 17.694 66.947 17.712 ;
     RECT  66.875 29.691 66.947 29.709 ;
     RECT  66.875 50.292 66.947 50.31 ;
     RECT  66.875 52.452 66.947 52.47 ;
    LAYER M3 ;
     RECT  33.048 0.043 33.066 0.091 ;
     RECT  31.968 0.091 34.218 0.139 ;
     RECT  45 0.091 45.018 0.139 ;
     RECT  53.676 0.091 54.162 0.139 ;
     RECT  55.116 0.091 55.134 0.139 ;
     RECT  55.908 0.091 55.926 0.139 ;
     RECT  56.772 0.091 56.79 0.139 ;
     RECT  30.492 0.043 30.51 0.187 ;
     RECT  53.676 0.139 55.926 0.187 ;
     RECT  56.772 0.139 56.898 0.187 ;
     RECT  30.492 0.187 31.158 0.235 ;
     RECT  31.968 0.139 34.326 0.235 ;
     RECT  60.84 0.091 60.858 0.235 ;
     RECT  61.776 0.091 62.766 0.235 ;
     RECT  51.624 0.091 51.642 0.475 ;
     RECT  50.364 0.091 50.382 0.523 ;
     RECT  52.812 0.427 52.83 0.523 ;
     RECT  53.676 0.187 56.898 0.523 ;
     RECT  50.004 0.523 50.382 1.175 ;
     RECT  30.492 0.235 34.326 1.759 ;
     RECT  29.016 1.831 29.034 1.876 ;
     RECT  29.952 1.759 34.326 1.876 ;
     RECT  27.396 1.759 27.414 1.921 ;
     RECT  50.112 1.175 50.382 1.963 ;
     RECT  51.444 0.475 51.642 1.963 ;
     RECT  27.396 1.921 27.522 1.993 ;
     RECT  50.112 1.963 51.642 1.993 ;
     RECT  52.416 0.523 56.898 1.993 ;
     RECT  29.016 1.876 34.326 2.011 ;
     RECT  27.396 1.993 27.846 2.029 ;
     RECT  29.016 2.011 34.974 2.029 ;
     RECT  36 1.957 36.018 2.029 ;
     RECT  38.088 1.957 38.106 2.029 ;
     RECT  58.32 0.091 59.49 2.029 ;
     RECT  3.024 2.029 3.042 2.065 ;
     RECT  3.924 2.029 3.942 2.065 ;
     RECT  25.74 2.065 25.758 2.101 ;
     RECT  26.784 2.029 34.974 2.101 ;
     RECT  36 2.029 36.594 2.101 ;
     RECT  37.584 2.029 38.106 2.101 ;
     RECT  38.88 0.091 43.938 2.101 ;
     RECT  48.708 0.091 48.726 2.101 ;
     RECT  3.024 2.065 4.482 2.143 ;
     RECT  23.364 2.101 23.994 2.143 ;
     RECT  45 0.139 45.306 2.143 ;
     RECT  2.415 2.143 4.482 2.191 ;
     RECT  5.256 2.101 5.274 2.191 ;
     RECT  23.364 2.143 24.105 2.191 ;
     RECT  25.74 2.101 34.974 2.191 ;
     RECT  36 2.101 43.938 2.191 ;
     RECT  45 2.143 45.705 2.191 ;
     RECT  46.872 2.101 47.358 2.191 ;
     RECT  48.132 2.101 48.726 2.191 ;
     RECT  57.708 2.029 59.49 2.191 ;
     RECT  25.74 2.191 35.226 2.203 ;
     RECT  36 2.191 45.81 2.203 ;
     RECT  7.815 2.143 7.905 2.227 ;
     RECT  23.364 2.191 24.174 2.227 ;
     RECT  46.872 2.191 48.726 2.227 ;
     RECT  50.112 1.993 56.898 2.227 ;
     RECT  23.364 2.227 24.462 2.251 ;
     RECT  2.415 2.191 5.274 2.263 ;
     RECT  20.556 2.191 20.574 2.263 ;
     RECT  46.728 2.227 48.726 2.263 ;
     RECT  50.004 2.227 56.898 2.263 ;
     RECT  57.708 2.191 59.958 2.263 ;
     RECT  2.415 2.263 6.174 2.299 ;
     RECT  23.184 2.251 24.462 2.299 ;
     RECT  25.74 2.203 45.81 2.299 ;
     RECT  46.62 2.263 48.726 2.299 ;
     RECT  50.004 2.263 59.958 2.299 ;
     RECT  60.84 0.235 62.766 2.299 ;
     RECT  63.864 0.091 64.386 2.299 ;
     RECT  2.376 2.299 6.174 2.335 ;
     RECT  7.272 2.227 7.905 2.371 ;
     RECT  9.36 2.335 9.378 2.371 ;
     RECT  11.736 2.335 12.078 2.371 ;
     RECT  21.348 2.227 21.366 2.371 ;
     RECT  22.176 2.335 22.194 2.371 ;
     RECT  25.74 2.299 64.386 2.371 ;
     RECT  13.215 2.143 13.305 2.413 ;
     RECT  18.615 2.143 18.705 2.413 ;
     RECT  11.736 2.371 12.294 2.429 ;
     RECT  2.304 2.335 6.174 2.491 ;
     RECT  7.02 2.371 8.154 2.491 ;
     RECT  25.74 2.371 64.602 2.525 ;
     RECT  11.736 2.429 12.186 2.569 ;
     RECT  23.184 2.299 24.966 2.587 ;
     RECT  20.52 2.263 20.574 2.605 ;
     RECT  23.112 2.587 24.966 2.605 ;
     RECT  25.74 2.525 64.53 2.605 ;
     RECT  2.304 2.491 8.154 2.641 ;
     RECT  9.36 2.371 9.594 2.641 ;
     RECT  2.304 2.641 9.774 2.683 ;
     RECT  11.412 2.569 12.186 2.731 ;
     RECT  20.448 2.605 20.574 2.803 ;
     RECT  21.348 2.371 22.194 2.803 ;
     RECT  20.448 2.803 22.194 2.861 ;
     RECT  23.112 2.605 64.53 2.861 ;
     RECT  20.52 2.861 22.194 2.875 ;
     RECT  23.112 2.861 64.422 2.875 ;
     RECT  20.52 2.875 64.422 3.029 ;
     RECT  17.748 3.073 17.766 3.109 ;
     RECT  17.352 3.109 17.766 3.145 ;
     RECT  11.16 2.731 12.186 3.181 ;
     RECT  17.352 3.145 17.802 3.181 ;
     RECT  18.615 2.413 18.897 3.181 ;
     RECT  2.268 2.683 9.774 3.245 ;
     RECT  11.124 3.181 12.33 3.271 ;
     RECT  13.215 2.413 13.497 3.271 ;
     RECT  2.304 3.245 9.774 3.307 ;
     RECT  11.124 3.271 13.497 3.307 ;
     RECT  17.352 3.181 18.897 3.307 ;
     RECT  2.304 3.307 9.846 3.343 ;
     RECT  17.352 3.307 18.954 3.343 ;
     RECT  17.352 3.343 19.458 3.451 ;
     RECT  2.304 3.343 10.026 3.685 ;
     RECT  10.836 3.307 13.497 3.685 ;
     RECT  2.304 3.685 13.59 3.721 ;
     RECT  15.012 3.685 15.03 3.721 ;
     RECT  0.36 3.643 0.378 3.787 ;
     RECT  17.352 3.451 19.71 3.847 ;
     RECT  2.304 3.721 13.734 3.875 ;
     RECT  10.8 3.875 13.734 3.883 ;
     RECT  14.976 3.721 15.03 3.883 ;
     RECT  17.316 3.847 19.71 3.883 ;
     RECT  21.096 3.029 64.422 3.931 ;
     RECT  16.92 3.883 19.71 3.955 ;
     RECT  21.024 3.931 64.422 3.979 ;
     RECT  10.8 3.883 15.03 3.991 ;
     RECT  16.848 3.955 19.71 4.081 ;
     RECT  21.024 3.979 64.494 4.081 ;
     RECT  0.216 3.787 0.378 4.171 ;
     RECT  2.304 3.875 10.026 4.181 ;
     RECT  16.74 4.081 64.494 4.225 ;
     RECT  16.56 4.225 64.494 4.379 ;
     RECT  0.144 4.171 0.378 4.531 ;
     RECT  21.06 4.379 64.494 4.531 ;
     RECT  10.8 3.991 15.39 4.657 ;
     RECT  16.56 4.379 20.322 4.693 ;
     RECT  5.328 4.181 10.026 4.729 ;
     RECT  10.764 4.657 15.39 4.729 ;
     RECT  5.328 4.729 15.39 4.765 ;
     RECT  5.328 4.765 15.498 4.801 ;
     RECT  16.452 4.693 20.322 4.801 ;
     RECT  5.328 4.801 20.322 4.919 ;
     RECT  2.304 4.181 4.59 4.927 ;
     RECT  5.328 4.919 19.386 4.927 ;
     RECT  0.144 4.531 0.558 4.987 ;
     RECT  2.304 4.927 19.386 4.987 ;
     RECT  21.06 4.531 64.638 5.071 ;
     RECT  21.06 5.071 64.674 5.117 ;
     RECT  20.16 4.919 20.322 5.161 ;
     RECT  21.06 5.117 64.638 5.161 ;
     RECT  0.144 4.987 0.63 5.309 ;
     RECT  0.144 5.309 0.378 5.405 ;
     RECT  2.124 4.987 19.386 5.405 ;
     RECT  2.124 5.405 9.774 5.701 ;
     RECT  10.548 5.405 19.386 5.809 ;
     RECT  20.16 5.161 64.638 5.809 ;
     RECT  1.692 5.701 9.774 5.899 ;
     RECT  1.152 5.899 9.774 6.029 ;
     RECT  2.124 6.029 9.774 6.151 ;
     RECT  66.132 6.151 66.15 6.241 ;
     RECT  2.124 6.151 9.81 6.283 ;
     RECT  10.548 5.809 64.638 6.283 ;
     RECT  2.124 6.283 64.638 6.653 ;
     RECT  66.132 6.241 66.87 6.691 ;
     RECT  2.124 6.653 19.566 6.809 ;
     RECT  0.18 5.405 0.378 6.859 ;
     RECT  1.152 6.029 1.386 6.859 ;
     RECT  2.124 6.809 9.81 6.859 ;
     RECT  20.34 6.653 64.638 6.889 ;
     RECT  65.556 6.691 66.87 6.889 ;
     RECT  1.152 6.859 9.81 6.917 ;
     RECT  0.144 6.859 0.378 6.955 ;
     RECT  1.152 6.917 1.17 6.955 ;
     RECT  0.144 6.955 1.17 7.181 ;
     RECT  0.144 7.181 0.378 7.229 ;
     RECT  20.34 6.889 66.87 7.373 ;
     RECT  66.096 7.373 66.87 7.469 ;
     RECT  1.98 6.917 9.81 7.493 ;
     RECT  2.052 7.493 9.81 7.565 ;
     RECT  2.16 7.565 9.81 7.627 ;
     RECT  2.16 7.627 9.846 7.661 ;
     RECT  10.656 6.809 19.566 7.897 ;
     RECT  20.34 7.373 65.034 7.897 ;
     RECT  10.656 7.897 65.034 7.997 ;
     RECT  2.196 7.661 9.846 8.005 ;
     RECT  10.656 7.997 11.682 8.005 ;
     RECT  0.144 7.229 0.342 8.011 ;
     RECT  12.636 7.997 65.034 8.159 ;
     RECT  66.096 7.469 66.15 8.159 ;
     RECT  1.152 7.181 1.17 8.203 ;
     RECT  0.108 8.011 0.342 8.299 ;
     RECT  1.152 8.203 1.278 8.299 ;
     RECT  2.196 8.005 11.682 8.509 ;
     RECT  66.132 8.159 66.15 8.509 ;
     RECT  0.108 8.299 1.278 8.525 ;
     RECT  0.108 8.525 1.206 8.573 ;
     RECT  18.396 8.159 65.034 8.699 ;
     RECT  66.132 8.509 66.87 8.717 ;
     RECT  20.7 8.699 65.034 8.807 ;
     RECT  18.396 8.699 19.962 8.969 ;
     RECT  20.736 8.807 65.034 9.005 ;
     RECT  2.124 8.509 11.682 9.085 ;
     RECT  0.144 8.573 1.206 9.101 ;
     RECT  0.144 9.101 0.234 9.113 ;
     RECT  2.052 9.085 11.718 9.121 ;
     RECT  12.636 8.159 17.658 9.121 ;
     RECT  18.396 8.969 19.89 9.121 ;
     RECT  0.144 9.113 0.162 9.149 ;
     RECT  1.98 9.121 11.718 9.239 ;
     RECT  20.88 9.005 65.034 9.311 ;
     RECT  66.132 8.717 66.798 9.355 ;
     RECT  10.584 9.239 11.718 9.391 ;
     RECT  12.636 9.121 19.89 9.391 ;
     RECT  65.52 9.355 66.798 9.419 ;
     RECT  1.188 9.101 1.206 9.509 ;
     RECT  66.024 9.419 66.798 9.581 ;
     RECT  66.024 9.581 66.258 9.677 ;
     RECT  10.584 9.391 19.89 9.739 ;
     RECT  20.88 9.311 64.674 9.739 ;
     RECT  10.584 9.739 64.674 9.821 ;
     RECT  1.152 9.835 1.17 10.013 ;
     RECT  1.98 9.239 9.81 10.021 ;
     RECT  10.584 9.821 20.358 10.021 ;
     RECT  21.168 9.821 64.674 10.085 ;
     RECT  66.132 9.677 66.258 10.121 ;
     RECT  1.98 10.021 20.358 10.355 ;
     RECT  13.104 10.355 20.358 10.493 ;
     RECT  19.98 10.493 20.322 10.499 ;
     RECT  21.312 10.085 64.674 10.685 ;
     RECT  21.564 10.685 64.674 11.011 ;
     RECT  1.98 10.355 12.222 11.101 ;
     RECT  13.104 10.493 19.242 11.101 ;
     RECT  66.132 10.121 66.222 11.101 ;
     RECT  1.98 11.101 19.242 11.275 ;
     RECT  19.98 10.499 20.25 11.275 ;
     RECT  1.98 11.275 20.25 11.281 ;
     RECT  1.98 11.281 20.538 11.371 ;
     RECT  65.808 11.101 66.222 11.405 ;
     RECT  1.98 11.371 20.61 11.419 ;
     RECT  21.564 11.011 65.07 11.419 ;
     RECT  1.98 11.419 65.07 11.549 ;
     RECT  66.636 11.467 66.654 11.563 ;
     RECT  1.98 11.549 65.034 11.645 ;
     RECT  1.98 11.645 20.214 11.669 ;
     RECT  66.636 11.563 66.726 11.741 ;
     RECT  20.952 11.645 65.034 11.885 ;
     RECT  65.808 11.405 65.898 12.331 ;
     RECT  1.98 11.669 20.178 12.487 ;
     RECT  20.952 11.885 64.674 12.487 ;
     RECT  1.98 12.487 64.674 12.515 ;
     RECT  2.088 12.515 64.674 12.715 ;
     RECT  65.808 12.331 66.114 12.715 ;
     RECT  65.808 12.715 66.654 12.811 ;
     RECT  65.808 12.811 66.834 12.901 ;
     RECT  2.088 12.715 64.962 12.941 ;
     RECT  2.088 12.941 64.782 13.085 ;
     RECT  21.636 13.085 64.782 13.289 ;
     RECT  2.088 13.085 20.754 13.915 ;
     RECT  2.088 13.915 20.826 14.251 ;
     RECT  21.672 13.289 64.782 14.251 ;
     RECT  2.088 14.251 64.782 14.405 ;
     RECT  2.16 14.405 64.782 14.429 ;
     RECT  14.832 14.429 64.782 14.683 ;
     RECT  2.16 14.429 13.986 15.053 ;
     RECT  13.215 15.053 13.986 15.187 ;
     RECT  14.832 14.683 64.854 15.187 ;
     RECT  0.216 15.547 0.234 15.595 ;
     RECT  0.144 15.595 0.234 15.773 ;
     RECT  0.216 15.773 0.234 15.835 ;
     RECT  2.16 15.053 12.438 15.871 ;
     RECT  13.215 15.187 64.854 15.871 ;
     RECT  0.216 15.835 0.306 15.899 ;
     RECT  0.216 15.899 0.234 15.917 ;
     RECT  2.16 15.871 64.854 16.205 ;
     RECT  1.152 16.141 1.17 16.231 ;
     RECT  2.16 16.205 64.782 16.231 ;
     RECT  65.808 12.901 66.942 16.375 ;
     RECT  65.772 16.375 66.942 16.411 ;
     RECT  1.152 16.231 64.782 16.907 ;
     RECT  1.26 16.907 64.782 16.973 ;
     RECT  1.404 16.973 64.782 17.035 ;
     RECT  65.628 16.411 66.942 17.035 ;
     RECT  0.108 17.041 0.126 17.165 ;
     RECT  1.404 17.035 66.942 17.549 ;
     RECT  1.98 17.549 66.942 17.717 ;
     RECT  1.98 17.717 66.87 17.741 ;
     RECT  0.828 18.091 0.846 18.235 ;
     RECT  0.324 18.235 0.846 18.283 ;
     RECT  0.216 18.283 0.846 18.379 ;
     RECT  0.216 18.379 1.17 18.419 ;
     RECT  0.216 18.419 0.846 18.859 ;
     RECT  1.98 17.741 66.834 19.039 ;
     RECT  1.98 19.039 66.87 19.085 ;
     RECT  0.144 18.859 0.846 19.243 ;
     RECT  1.98 19.085 66.834 19.535 ;
     RECT  4.68 19.535 66.834 19.571 ;
     RECT  13.215 19.571 66.834 20.039 ;
     RECT  1.98 19.535 3.906 20.299 ;
     RECT  4.68 19.571 12.474 20.299 ;
     RECT  13.215 20.039 27.018 20.299 ;
     RECT  27.864 20.039 66.834 20.525 ;
     RECT  1.98 20.299 27.018 21.001 ;
     RECT  27.864 20.525 65.25 21.001 ;
     RECT  1.98 21.001 65.25 21.155 ;
     RECT  1.98 21.155 27.486 21.263 ;
     RECT  28.26 21.155 65.25 21.469 ;
     RECT  66.132 20.525 66.834 21.469 ;
     RECT  2.304 21.263 27.486 22.045 ;
     RECT  28.26 21.469 66.834 22.045 ;
     RECT  0.108 19.243 0.846 22.349 ;
     RECT  0.576 22.349 0.846 22.379 ;
     RECT  2.304 22.045 66.834 22.925 ;
     RECT  2.304 22.925 66.762 23.179 ;
     RECT  2.268 23.179 66.762 23.315 ;
     RECT  0.828 22.379 0.846 23.657 ;
     RECT  2.304 23.315 28.566 23.819 ;
     RECT  7.128 23.819 26.622 23.855 ;
     RECT  29.304 23.315 66.762 24.197 ;
     RECT  27.396 23.819 28.566 24.241 ;
     RECT  29.304 24.197 66.114 24.241 ;
     RECT  27.396 24.241 66.114 24.665 ;
     RECT  34.668 24.665 66.114 24.701 ;
     RECT  2.304 23.819 6.39 24.749 ;
     RECT  7.128 23.855 26.19 24.763 ;
     RECT  6.264 24.749 6.39 24.773 ;
     RECT  7.128 24.763 26.478 24.781 ;
     RECT  27.396 24.665 33.894 24.781 ;
     RECT  34.74 24.701 66.114 24.845 ;
     RECT  34.74 24.845 64.998 24.941 ;
     RECT  6.336 24.773 6.39 25.003 ;
     RECT  7.128 24.781 26.622 25.003 ;
     RECT  2.304 24.749 5.454 25.051 ;
     RECT  6.336 25.003 26.622 25.051 ;
     RECT  27.36 24.781 33.894 25.051 ;
     RECT  2.268 25.051 5.454 25.147 ;
     RECT  2.232 25.147 5.454 25.205 ;
     RECT  66.852 24.475 66.87 25.229 ;
     RECT  6.336 25.051 33.894 25.475 ;
     RECT  65.988 24.845 66.114 25.579 ;
     RECT  2.268 25.205 5.454 25.591 ;
     RECT  6.336 25.475 32.022 25.619 ;
     RECT  2.268 25.591 5.562 25.681 ;
     RECT  6.336 25.619 31.986 25.681 ;
     RECT  34.74 24.941 64.53 25.681 ;
     RECT  2.268 25.681 31.986 25.709 ;
     RECT  32.94 25.475 33.894 25.723 ;
     RECT  65.52 25.579 66.114 25.753 ;
     RECT  32.94 25.723 33.93 25.853 ;
     RECT  2.268 25.709 31.95 26.087 ;
     RECT  2.304 26.087 31.95 26.093 ;
     RECT  65.484 25.753 66.114 26.159 ;
     RECT  34.74 25.681 64.602 26.249 ;
     RECT  34.74 26.249 64.53 26.357 ;
     RECT  32.94 25.853 33.822 26.395 ;
     RECT  32.904 26.395 33.822 26.401 ;
     RECT  27.72 26.093 31.95 26.491 ;
     RECT  32.832 26.401 33.822 26.491 ;
     RECT  34.74 26.357 64.494 26.491 ;
     RECT  65.52 26.159 66.114 26.491 ;
     RECT  66.924 25.531 66.942 26.491 ;
     RECT  34.704 26.491 64.494 26.671 ;
     RECT  2.304 26.093 26.874 26.833 ;
     RECT  27.72 26.491 33.822 26.833 ;
     RECT  34.668 26.671 64.494 27.163 ;
     RECT  34.668 27.163 64.53 27.211 ;
     RECT  2.304 26.833 33.822 27.301 ;
     RECT  34.668 27.211 64.566 27.301 ;
     RECT  2.304 27.301 64.566 27.341 ;
     RECT  36.648 27.341 64.566 27.445 ;
     RECT  36.648 27.445 64.602 27.499 ;
     RECT  65.52 26.491 66.942 27.499 ;
     RECT  2.304 27.341 35.91 28.147 ;
     RECT  36.648 27.499 66.942 28.147 ;
     RECT  2.304 28.147 66.942 28.175 ;
     RECT  65.556 28.175 66.942 28.205 ;
     RECT  2.304 28.175 64.422 28.985 ;
     RECT  66.132 28.205 66.942 29.029 ;
     RECT  2.304 28.985 64.278 29.057 ;
     RECT  65.556 29.029 66.942 29.165 ;
     RECT  66.024 29.165 66.942 29.645 ;
     RECT  66.204 29.645 66.942 29.714 ;
     RECT  2.304 29.057 64.206 29.795 ;
     RECT  34.776 29.795 64.206 29.875 ;
     RECT  34.776 29.875 64.242 29.947 ;
     RECT  34.776 29.947 64.314 30.145 ;
     RECT  34.776 30.145 64.458 30.415 ;
     RECT  34.776 30.415 64.53 30.451 ;
     RECT  2.304 29.795 34.038 30.569 ;
     RECT  31.104 30.569 34.038 30.649 ;
     RECT  34.776 30.451 64.602 30.649 ;
     RECT  66.204 29.714 66.87 30.859 ;
     RECT  31.104 30.649 64.602 30.955 ;
     RECT  2.304 30.569 30.33 31.387 ;
     RECT  31.104 30.955 64.998 31.387 ;
     RECT  2.304 31.387 64.998 31.949 ;
     RECT  2.304 31.949 64.674 32.099 ;
     RECT  47.988 32.099 64.674 32.531 ;
     RECT  2.304 32.099 47.214 32.765 ;
     RECT  66.132 30.859 66.87 32.813 ;
     RECT  36.864 32.765 47.214 33.019 ;
     RECT  47.988 32.531 64.494 33.019 ;
     RECT  2.304 32.765 36.018 33.575 ;
     RECT  30.852 33.575 36.018 33.853 ;
     RECT  30.852 33.853 36.054 33.889 ;
     RECT  30.852 33.889 36.09 33.925 ;
     RECT  36.864 33.019 64.494 33.925 ;
     RECT  65.556 33.853 65.574 33.931 ;
     RECT  65.556 33.931 66.114 34.061 ;
     RECT  30.852 33.925 64.494 34.159 ;
     RECT  66.096 34.061 66.114 34.385 ;
     RECT  2.304 33.575 30.114 34.429 ;
     RECT  30.852 34.159 64.53 34.429 ;
     RECT  0.144 33.979 0.162 34.493 ;
     RECT  2.304 34.429 64.53 34.735 ;
     RECT  2.304 34.735 64.674 34.781 ;
     RECT  66.852 32.813 66.87 34.891 ;
     RECT  2.304 34.781 64.458 34.925 ;
     RECT  66.816 34.891 66.87 35.371 ;
     RECT  66.096 35.371 66.87 35.735 ;
     RECT  32.472 34.925 64.458 35.899 ;
     RECT  2.304 34.925 31.626 35.941 ;
     RECT  32.472 35.899 64.674 35.941 ;
     RECT  2.304 35.941 64.674 36.121 ;
     RECT  2.268 36.121 64.674 36.475 ;
     RECT  2.268 36.475 64.962 36.545 ;
     RECT  2.268 36.545 64.674 36.931 ;
     RECT  65.556 36.859 65.574 37.037 ;
     RECT  2.196 36.931 64.674 37.201 ;
     RECT  66.816 35.735 66.87 37.483 ;
     RECT  2.16 37.201 64.674 37.613 ;
     RECT  66.096 37.483 66.87 37.895 ;
     RECT  66.132 37.895 66.87 38.237 ;
     RECT  0.144 37.915 0.162 38.347 ;
     RECT  0.144 38.347 0.342 38.443 ;
     RECT  66.744 38.237 66.87 38.507 ;
     RECT  2.16 37.613 35.658 38.515 ;
     RECT  36.396 37.613 64.674 38.515 ;
     RECT  0.108 38.443 0.342 38.543 ;
     RECT  1.152 38.251 1.35 38.573 ;
     RECT  2.16 38.515 64.674 38.683 ;
     RECT  2.16 38.683 64.962 38.717 ;
     RECT  41.724 38.717 64.962 38.779 ;
     RECT  0.144 38.543 0.342 38.785 ;
     RECT  1.152 38.573 1.314 38.785 ;
     RECT  66.744 38.507 66.834 38.975 ;
     RECT  66.744 38.975 66.762 39.047 ;
     RECT  2.16 38.717 40.842 39.245 ;
     RECT  41.724 38.779 65.538 39.245 ;
     RECT  2.34 39.245 40.842 39.499 ;
     RECT  41.724 39.245 65.07 39.499 ;
     RECT  2.34 39.499 65.07 39.677 ;
     RECT  0.144 38.785 1.314 39.821 ;
     RECT  1.152 39.821 1.314 39.883 ;
     RECT  2.34 39.677 64.998 39.917 ;
     RECT  2.34 39.917 64.854 40.055 ;
     RECT  2.34 40.055 64.674 40.135 ;
     RECT  0.144 39.821 0.342 40.267 ;
     RECT  0.108 40.267 0.342 40.325 ;
     RECT  1.152 39.883 1.386 40.397 ;
     RECT  2.304 40.135 64.674 40.507 ;
     RECT  2.268 40.507 64.674 40.747 ;
     RECT  1.728 40.747 64.674 40.829 ;
     RECT  2.268 40.829 64.674 40.901 ;
     RECT  44.172 40.901 64.674 40.981 ;
     RECT  65.556 40.639 65.574 40.981 ;
     RECT  44.172 40.981 65.574 41.021 ;
     RECT  0.216 40.325 0.342 41.131 ;
     RECT  44.172 41.021 64.674 41.171 ;
     RECT  65.52 41.021 65.574 41.243 ;
     RECT  2.268 40.901 43.362 41.405 ;
     RECT  2.304 41.405 43.362 41.647 ;
     RECT  44.172 41.171 64.602 41.647 ;
     RECT  0.144 41.131 0.342 41.836 ;
     RECT  2.304 41.647 64.602 42.221 ;
     RECT  0.072 41.836 0.342 42.295 ;
     RECT  44.64 42.221 64.602 42.295 ;
     RECT  0.072 42.295 0.378 42.509 ;
     RECT  65.52 41.243 65.538 42.521 ;
     RECT  66.816 41.791 66.834 42.557 ;
     RECT  2.304 42.221 43.65 42.667 ;
     RECT  2.16 42.667 43.65 42.719 ;
     RECT  0.072 42.509 0.342 42.893 ;
     RECT  65.556 42.601 66.15 42.941 ;
     RECT  44.64 42.295 64.674 43.373 ;
     RECT  2.304 42.719 43.65 43.411 ;
     RECT  44.64 43.373 64.602 43.411 ;
     RECT  2.304 43.411 64.602 43.529 ;
     RECT  0.072 42.893 0.27 43.645 ;
     RECT  2.304 43.529 43.938 43.805 ;
     RECT  0.072 43.645 0.558 43.949 ;
     RECT  0.072 43.949 0.162 43.979 ;
     RECT  66.132 42.941 66.15 44.347 ;
     RECT  66.096 44.347 66.15 44.381 ;
     RECT  44.82 43.529 64.602 44.419 ;
     RECT  2.304 43.805 43.794 44.447 ;
     RECT  44.82 44.419 64.674 44.645 ;
     RECT  0.072 43.979 0.126 45.059 ;
     RECT  66.132 44.381 66.15 45.403 ;
     RECT  2.304 44.447 43.722 45.427 ;
     RECT  66.096 45.403 66.15 45.491 ;
     RECT  2.304 45.427 43.794 45.571 ;
     RECT  44.856 44.645 64.674 45.571 ;
     RECT  66.132 45.491 66.15 45.629 ;
     RECT  2.304 45.571 64.674 45.931 ;
     RECT  2.304 45.931 64.998 45.965 ;
     RECT  66.024 46.411 66.042 46.535 ;
     RECT  0.108 45.059 0.126 46.696 ;
     RECT  0.036 46.696 0.126 46.724 ;
     RECT  66.816 46.027 66.834 46.747 ;
     RECT  66.096 46.747 66.834 47.075 ;
     RECT  66.096 47.075 66.15 47.317 ;
     RECT  2.304 45.965 64.566 47.323 ;
     RECT  65.88 47.317 66.15 47.357 ;
     RECT  66.024 47.357 66.15 47.405 ;
     RECT  66.024 47.405 66.114 47.615 ;
     RECT  66.096 47.615 66.114 48.469 ;
     RECT  65.556 48.469 66.114 48.523 ;
     RECT  66.852 48.331 66.87 48.523 ;
     RECT  2.304 47.323 64.602 48.541 ;
     RECT  65.556 48.523 66.87 48.845 ;
     RECT  66.096 48.845 66.87 48.989 ;
     RECT  0.036 46.724 0.054 49.277 ;
     RECT  2.304 48.541 64.674 49.505 ;
     RECT  66.708 48.989 66.87 50.287 ;
     RECT  66.708 50.287 66.942 50.315 ;
     RECT  2.304 49.505 54.522 50.395 ;
     RECT  55.296 49.505 64.674 50.395 ;
     RECT  2.304 50.395 64.674 50.549 ;
     RECT  2.304 50.549 64.53 51.451 ;
     RECT  2.304 51.451 64.89 51.539 ;
     RECT  66.744 50.315 66.942 51.595 ;
     RECT  66.672 51.595 66.942 51.725 ;
     RECT  66.78 51.725 66.942 52.169 ;
     RECT  66.852 52.169 66.942 52.205 ;
     RECT  65.448 51.787 65.574 52.459 ;
     RECT  66.924 52.205 66.942 52.475 ;
     RECT  65.448 52.459 66.114 52.511 ;
     RECT  66.096 52.511 66.114 52.745 ;
     RECT  2.304 51.539 64.674 52.877 ;
     RECT  2.304 52.877 44.586 52.979 ;
     RECT  45.36 52.877 64.674 53.083 ;
     RECT  2.304 52.979 44.478 53.095 ;
     RECT  2.232 53.095 44.478 53.213 ;
     RECT  45.36 53.083 64.962 53.285 ;
     RECT  45.36 53.285 64.674 53.555 ;
     RECT  2.268 53.213 44.478 53.941 ;
     RECT  45.36 53.555 58.986 53.941 ;
     RECT  2.268 53.941 58.986 54.481 ;
     RECT  59.76 53.555 64.674 54.481 ;
     RECT  66.132 54.445 66.15 54.605 ;
     RECT  2.268 54.481 64.674 54.707 ;
     RECT  2.268 54.707 64.566 55.445 ;
     RECT  66.816 54.763 66.87 55.481 ;
     RECT  44.424 55.445 64.566 55.561 ;
     RECT  66.168 55.723 66.186 56.065 ;
     RECT  44.424 55.561 64.674 56.219 ;
     RECT  44.424 56.219 64.602 56.237 ;
     RECT  2.268 55.445 43.578 56.291 ;
     RECT  30.42 56.291 43.578 56.605 ;
     RECT  44.424 56.237 57.762 56.605 ;
     RECT  30.42 56.605 57.762 56.669 ;
     RECT  66.132 56.065 66.186 56.813 ;
     RECT  0.108 56.299 0.126 56.827 ;
     RECT  0.108 56.827 0.27 56.839 ;
     RECT  2.268 56.291 29.697 56.911 ;
     RECT  2.232 56.911 29.697 57.053 ;
     RECT  0.108 56.839 0.378 57.067 ;
     RECT  0.108 57.067 0.558 57.101 ;
     RECT  2.268 57.053 29.697 57.109 ;
     RECT  30.42 56.669 43.614 57.109 ;
     RECT  44.424 56.669 57.762 57.115 ;
     RECT  58.572 56.237 64.602 57.115 ;
     RECT  44.424 57.115 64.602 57.145 ;
     RECT  0.144 57.101 0.558 57.389 ;
     RECT  2.268 57.109 43.614 57.415 ;
     RECT  44.424 57.145 64.674 57.415 ;
     RECT  0.216 57.389 0.558 57.541 ;
     RECT  66.852 57.067 66.87 57.605 ;
     RECT  65.556 57.541 65.574 57.629 ;
     RECT  2.268 57.415 64.674 57.875 ;
     RECT  0.216 57.541 1.134 58.061 ;
     RECT  1.116 58.061 1.134 58.219 ;
     RECT  1.116 58.219 1.242 58.253 ;
     RECT  1.152 58.253 1.242 58.445 ;
     RECT  0.216 58.061 0.342 58.459 ;
     RECT  66.06 57.691 66.114 58.621 ;
     RECT  0.144 58.459 0.342 58.637 ;
     RECT  2.304 57.875 64.674 58.729 ;
     RECT  2.268 58.729 64.674 58.829 ;
     RECT  65.556 58.621 66.114 58.919 ;
     RECT  2.304 58.829 64.674 58.955 ;
     RECT  1.152 58.445 1.17 58.973 ;
     RECT  65.556 58.919 65.574 58.973 ;
     RECT  66.852 58.603 66.87 59.099 ;
     RECT  2.304 58.955 46.242 59.459 ;
     RECT  0.18 58.637 0.342 59.467 ;
     RECT  14.976 59.459 46.242 59.495 ;
     RECT  0.108 59.467 0.342 59.531 ;
     RECT  15.012 59.495 46.242 59.729 ;
     RECT  2.304 59.459 14.166 59.737 ;
     RECT  2.124 59.737 14.166 59.755 ;
     RECT  45.144 59.729 46.242 59.809 ;
     RECT  46.98 58.955 64.674 59.809 ;
     RECT  1.98 59.755 14.166 59.885 ;
     RECT  0.18 59.531 0.342 59.947 ;
     RECT  15.012 59.729 42.822 59.999 ;
     RECT  43.848 59.729 43.974 60.035 ;
     RECT  43.848 60.035 43.938 60.071 ;
     RECT  0.18 59.947 0.378 60.077 ;
     RECT  0.18 60.077 0.306 60.125 ;
     RECT  43.884 60.071 43.938 60.179 ;
     RECT  66.096 59.851 66.114 60.235 ;
     RECT  65.556 60.235 66.114 60.269 ;
     RECT  0.18 60.125 0.198 60.317 ;
     RECT  15.012 59.999 36.63 60.379 ;
     RECT  37.368 59.999 42.642 60.413 ;
     RECT  2.304 59.885 14.166 60.511 ;
     RECT  14.976 60.379 36.63 60.511 ;
     RECT  66.852 60.523 66.87 60.575 ;
     RECT  43.92 60.179 43.938 60.809 ;
     RECT  66.096 60.269 66.114 60.845 ;
     RECT  2.304 60.511 36.63 60.955 ;
     RECT  37.368 60.413 40.878 60.955 ;
     RECT  41.652 60.413 42.642 61.195 ;
     RECT  2.304 60.955 40.878 61.231 ;
     RECT  41.652 61.195 42.93 61.231 ;
     RECT  2.304 61.231 40.914 61.385 ;
     RECT  41.652 61.231 43.578 61.385 ;
     RECT  65.556 61.159 65.574 61.421 ;
     RECT  66.096 61.627 66.114 61.661 ;
     RECT  66.852 61.771 66.87 61.961 ;
     RECT  41.652 61.385 43.506 62.041 ;
     RECT  45.144 59.809 64.674 62.155 ;
     RECT  41.616 62.041 43.506 62.159 ;
     RECT  45.144 62.155 64.962 62.159 ;
     RECT  54.576 62.159 64.962 62.195 ;
     RECT  45.144 62.159 53.838 62.429 ;
     RECT  50.22 62.429 53.838 62.537 ;
     RECT  2.304 61.385 40.878 62.581 ;
     RECT  41.616 62.159 43.29 62.581 ;
     RECT  2.304 62.581 43.29 62.699 ;
     RECT  2.304 62.699 36.378 62.735 ;
     RECT  66.096 62.539 66.114 62.827 ;
     RECT  66.06 62.827 66.114 63.005 ;
     RECT  50.256 62.537 53.838 63.211 ;
     RECT  54.576 62.195 64.674 63.211 ;
     RECT  45.144 62.429 49.482 63.391 ;
     RECT  50.256 63.211 64.674 63.391 ;
     RECT  66.096 63.005 66.114 63.451 ;
     RECT  66.852 62.683 66.87 63.451 ;
     RECT  2.304 62.735 36.306 63.547 ;
     RECT  37.152 62.699 43.11 63.547 ;
     RECT  66.096 63.451 66.87 63.581 ;
     RECT  2.304 63.547 43.11 63.625 ;
     RECT  45.144 63.391 64.674 63.815 ;
     RECT  2.304 63.625 43.29 63.859 ;
     RECT  45.144 63.815 59.598 63.895 ;
     RECT  66.852 63.581 66.87 63.923 ;
     RECT  2.304 63.859 43.362 64.049 ;
     RECT  45 63.895 59.598 64.049 ;
     RECT  66.096 63.581 66.114 64.085 ;
     RECT  45 64.049 59.382 64.109 ;
     RECT  50.364 64.109 59.382 64.157 ;
     RECT  36.792 64.049 43.362 64.165 ;
     RECT  50.364 64.157 59.31 64.193 ;
     RECT  36.792 64.165 43.578 64.205 ;
     RECT  36.792 64.205 43.506 64.229 ;
     RECT  45 64.109 49.626 64.229 ;
     RECT  60.552 63.815 64.674 64.229 ;
     RECT  2.304 64.049 35.097 64.319 ;
     RECT  35.892 64.049 36.054 64.319 ;
     RECT  36.792 64.229 43.362 64.319 ;
     RECT  50.364 64.193 58.194 64.319 ;
     RECT  2.304 64.319 14.382 64.355 ;
     RECT  36.792 64.319 36.81 64.355 ;
     RECT  37.656 64.319 43.29 64.355 ;
     RECT  45.615 64.229 49.626 64.355 ;
     RECT  58.968 64.193 59.31 64.355 ;
     RECT  60.552 64.229 62.097 64.355 ;
     RECT  52.308 64.319 58.194 64.391 ;
     RECT  66.132 64.363 66.15 64.397 ;
     RECT  2.304 64.355 13.626 64.427 ;
     RECT  37.656 64.355 41.238 64.427 ;
     RECT  41.976 64.355 42.822 64.499 ;
     RECT  60.696 64.355 62.097 64.499 ;
     RECT  15.228 64.319 35.097 64.547 ;
     RECT  54.612 64.391 58.194 64.547 ;
     RECT  61.776 64.499 62.097 64.547 ;
     RECT  2.304 64.427 13.59 64.589 ;
     RECT  14.364 64.355 14.382 64.589 ;
     RECT  35.928 64.319 36.054 64.589 ;
     RECT  37.656 64.427 41.166 64.589 ;
     RECT  42.408 64.499 42.822 64.589 ;
     RECT  45.615 64.355 49.446 64.589 ;
     RECT  50.364 64.319 51.354 64.589 ;
     RECT  52.308 64.391 53.838 64.589 ;
     RECT  54.612 64.547 56.505 64.589 ;
     RECT  57.24 64.547 58.194 64.589 ;
     RECT  61.776 64.547 61.974 64.589 ;
     RECT  62.856 64.229 64.674 64.589 ;
     RECT  2.304 64.589 13.554 64.625 ;
     RECT  15.228 64.547 34.938 64.625 ;
     RECT  35.928 64.589 35.946 64.625 ;
     RECT  37.836 64.589 41.022 64.625 ;
     RECT  42.804 64.589 42.822 64.625 ;
     RECT  45.615 64.589 49.23 64.625 ;
     RECT  50.508 64.589 51.105 64.625 ;
     RECT  52.308 64.589 53.622 64.625 ;
     RECT  60.696 64.499 60.858 64.625 ;
     RECT  62.964 64.589 64.458 64.625 ;
     RECT  60.84 64.625 60.858 64.637 ;
     RECT  15.228 64.625 34.905 64.697 ;
     RECT  62.964 64.625 62.982 64.697 ;
     RECT  2.415 64.625 13.554 64.733 ;
     RECT  50.796 64.625 51.105 64.733 ;
     RECT  52.524 64.625 53.622 64.733 ;
     RECT  61.815 64.589 61.974 64.733 ;
     RECT  64.368 64.625 64.386 64.733 ;
     RECT  45.615 64.625 48.726 64.769 ;
     RECT  53.1 64.733 53.118 64.769 ;
     RECT  59.292 64.355 59.31 64.769 ;
     RECT  2.415 64.733 13.305 64.817 ;
     RECT  28.692 64.697 34.905 64.817 ;
     RECT  45.615 64.769 46.314 64.817 ;
     RECT  51.015 64.733 51.105 64.817 ;
     RECT  56.415 64.589 56.505 64.817 ;
     RECT  61.815 64.733 61.905 64.817 ;
     RECT  15.372 64.697 27.918 64.973 ;
     RECT  15.372 64.973 25.866 65.021 ;
     RECT  37.872 64.625 40.878 65.021 ;
     RECT  47.268 64.769 48.726 65.021 ;
     RECT  2.808 64.817 13.122 65.549 ;
     RECT  15.372 65.021 25.83 65.549 ;
     RECT  26.604 64.973 27.918 65.549 ;
     RECT  28.692 64.817 34.758 65.549 ;
     RECT  37.872 65.021 40.842 65.549 ;
     RECT  16.74 65.549 23.598 65.597 ;
     RECT  47.268 65.021 48.618 65.597 ;
     RECT  15.372 65.549 15.966 65.645 ;
     RECT  18.144 65.597 20.502 65.645 ;
     RECT  38.376 65.549 40.842 65.645 ;
     RECT  48.168 65.597 48.618 65.645 ;
     RECT  45.972 64.817 46.314 65.837 ;
     RECT  2.808 65.549 11.718 66.077 ;
     RECT  26.604 65.549 27.738 66.077 ;
     RECT  2.808 66.077 7.182 66.125 ;
     RECT  16.74 65.597 17.334 66.125 ;
     RECT  18.252 65.645 20.502 66.125 ;
     RECT  21.276 65.597 23.598 66.125 ;
     RECT  24.444 65.549 25.83 66.125 ;
     RECT  33.012 65.549 34.758 66.125 ;
     RECT  38.556 65.645 40.842 66.125 ;
     RECT  47.268 65.597 47.286 66.125 ;
     RECT  48.168 65.645 48.33 66.125 ;
     RECT  3.6 66.125 3.69 66.173 ;
     RECT  9.18 66.077 11.718 66.173 ;
     RECT  15.372 65.645 15.93 66.173 ;
     RECT  18.252 66.125 19.026 66.173 ;
     RECT  20.448 66.125 20.502 66.173 ;
     RECT  21.492 66.125 22.23 66.173 ;
     RECT  26.748 66.077 27.738 66.173 ;
     RECT  2.808 66.125 2.826 66.221 ;
     RECT  24.912 66.125 25.434 66.221 ;
     RECT  33.048 66.125 33.426 66.221 ;
     RECT  39.852 66.125 40.41 66.221 ;
     RECT  10.764 66.173 11.718 66.269 ;
     RECT  34.524 66.125 34.758 66.269 ;
     RECT  25.2 66.221 25.434 66.701 ;
     RECT  5.148 66.125 7.182 66.749 ;
     RECT  12.456 65.549 13.122 66.749 ;
     RECT  6.264 66.749 7.182 66.797 ;
     RECT  7.956 66.077 8.334 66.797 ;
     RECT  9.18 66.173 9.846 66.797 ;
     RECT  12.564 66.749 13.122 66.797 ;
     RECT  15.732 66.173 15.93 66.797 ;
     RECT  19.008 66.173 19.026 66.797 ;
     RECT  26.964 66.173 27.738 66.797 ;
     RECT  28.692 65.549 32.238 66.797 ;
     RECT  3.672 66.173 3.69 66.845 ;
     RECT  5.148 66.749 5.166 66.845 ;
     RECT  6.264 66.797 6.282 66.845 ;
     RECT  8.316 66.797 8.334 66.845 ;
     RECT  9.18 66.797 9.666 66.845 ;
     RECT  11.304 66.269 11.718 66.845 ;
     RECT  13.104 66.797 13.122 66.845 ;
     RECT  15.912 66.797 15.93 66.845 ;
     RECT  18.252 66.173 18.27 66.845 ;
     RECT  20.484 66.173 20.502 66.845 ;
     RECT  21.996 66.173 22.014 66.845 ;
     RECT  23.4 66.125 23.418 66.845 ;
     RECT  25.416 66.701 25.434 66.845 ;
     RECT  27.072 66.797 27.738 66.845 ;
     RECT  28.692 66.797 28.71 66.845 ;
     RECT  29.736 66.797 30.114 66.845 ;
     RECT  31.032 66.797 32.238 66.845 ;
     RECT  33.264 66.221 33.282 66.845 ;
     RECT  34.524 66.269 34.542 66.845 ;
     RECT  40.392 66.221 40.41 66.845 ;
     RECT  46.296 65.837 46.314 66.845 ;
    LAYER M4 ;
     RECT  0.06 15.6 0.097 21.672 ;
     RECT  0.06 57.072 0.097 63.144 ;
     RECT  0.06 2.544 0.133 8.616 ;
     RECT  0.025 49.248 0.133 49.272 ;
     RECT  0.097 56.304 0.133 63.144 ;
     RECT  0.06 31.728 0.179 34.728 ;
     RECT  0.133 2.544 0.181 9.048 ;
     RECT  0.097 15.6 0.181 22.344 ;
     RECT  0.133 56.16 0.181 63.144 ;
     RECT  0.181 26.064 0.229 27.096 ;
     RECT  0.181 52.752 0.229 52.776 ;
     RECT  0.133 50.496 0.275 50.52 ;
     RECT  0.229 52.272 0.277 52.776 ;
     RECT  0.181 2.544 0.323 9.336 ;
     RECT  0.181 55.968 0.323 63.144 ;
     RECT  0.323 2.64 0.325 9.336 ;
     RECT  0.277 52.272 0.325 53.544 ;
     RECT  0.133 48.72 0.371 49.272 ;
     RECT  0.133 54.672 0.371 54.696 ;
     RECT  0.323 62.16 0.371 63.144 ;
     RECT  0.229 25.824 0.373 27.096 ;
     RECT  0.325 2.64 0.419 9.864 ;
     RECT  0.323 55.968 0.419 61.128 ;
     RECT  0.179 31.824 0.515 34.728 ;
     RECT  0.419 2.736 0.563 9.864 ;
     RECT  0.515 31.824 0.563 33.768 ;
     RECT  0.371 62.16 0.563 62.664 ;
     RECT  0.06 37.872 0.569 43.944 ;
     RECT  0.563 32.016 0.611 32.04 ;
     RECT  0.181 14.688 0.805 22.344 ;
     RECT  0.563 3.216 1.141 9.864 ;
     RECT  0.805 14.496 1.717 22.344 ;
     RECT  0.133 23.664 1.717 23.688 ;
     RECT  0.371 49.056 1.717 49.272 ;
     RECT  0.325 52.224 1.717 53.544 ;
     RECT  1.717 14.496 1.765 24.552 ;
     RECT  0.373 25.824 1.765 27.144 ;
     RECT  1.717 50.736 1.765 50.76 ;
     RECT  1.717 52.224 1.765 54.456 ;
     RECT  1.717 34.32 1.813 34.344 ;
     RECT  1.765 50.736 1.813 50.856 ;
     RECT  1.765 52.224 1.813 54.888 ;
     RECT  1.765 47.952 1.909 47.976 ;
     RECT  1.909 47.616 1.957 47.976 ;
     RECT  1.717 49.008 1.957 49.272 ;
     RECT  1.717 36.528 2.005 36.552 ;
     RECT  0.569 37.872 2.005 43.848 ;
     RECT  1.141 3.216 2.053 10.008 ;
     RECT  0.901 11.136 2.053 11.16 ;
     RECT  2.005 46.272 2.101 46.296 ;
     RECT  1.957 47.52 2.101 49.272 ;
     RECT  0.419 56.064 2.101 60.312 ;
     RECT  2.053 3.216 2.149 11.16 ;
     RECT  2.101 29.616 2.149 29.64 ;
     RECT  1.813 34.272 2.149 34.344 ;
     RECT  2.101 35.328 2.149 35.352 ;
     RECT  2.005 36.48 2.149 43.848 ;
     RECT  2.101 45.744 2.149 46.296 ;
     RECT  2.101 47.376 2.149 49.272 ;
     RECT  1.813 50.736 2.149 54.888 ;
     RECT  2.101 56.064 2.149 60.792 ;
     RECT  2.101 62.016 2.149 62.04 ;
     RECT  2.149 28.992 2.197 30.936 ;
     RECT  2.149 33.072 2.197 44.136 ;
     RECT  2.149 45.6 2.197 60.936 ;
     RECT  2.149 62.016 2.197 63.336 ;
     RECT  2.149 2.544 2.245 11.16 ;
     RECT  1.765 14.496 2.245 27.144 ;
     RECT  2.197 28.416 2.245 63.336 ;
     RECT  2.149 13.2 2.293 13.224 ;
     RECT  2.245 14.496 2.293 27.336 ;
     RECT  2.245 28.416 2.293 64.008 ;
     RECT  2.293 13.2 2.329 64.008 ;
     RECT  2.245 2.496 2.408 11.688 ;
     RECT  2.329 13.104 2.408 64.008 ;
     RECT  2.408 2.148 2.512 64.812 ;
     RECT  2.725 66.144 2.797 66.168 ;
     RECT  2.797 66.144 2.917 66.216 ;
     RECT  2.512 2.4 3.107 64.584 ;
     RECT  2.917 66.096 3.109 66.216 ;
     RECT  3.109 66.048 3.205 66.216 ;
     RECT  3.205 66 3.397 66.216 ;
     RECT  3.107 2.4 3.443 31.416 ;
     RECT  3.397 66 3.493 66.792 ;
     RECT  3.107 32.448 3.517 64.584 ;
     RECT  3.443 2.4 3.625 3 ;
     RECT  3.443 3.984 4.069 31.416 ;
     RECT  3.517 32.448 4.069 65.016 ;
     RECT  4.069 3.984 4.165 65.016 ;
     RECT  3.493 66 4.165 66.84 ;
     RECT  3.625 2.256 4.501 3 ;
     RECT  4.501 2.208 4.549 3 ;
     RECT  4.165 3.984 4.549 66.84 ;
     RECT  4.549 2.208 4.565 66.84 ;
     RECT  4.565 2.208 4.889 34.776 ;
     RECT  4.889 2.256 5.123 34.776 ;
     RECT  5.123 3.36 5.141 29.064 ;
     RECT  5.123 2.256 5.219 2.28 ;
     RECT  5.123 30.048 5.429 34.776 ;
     RECT  4.565 35.856 5.537 66.84 ;
     RECT  5.429 30.192 5.641 34.776 ;
     RECT  5.537 35.856 5.641 64.68 ;
     RECT  5.641 30.192 5.699 64.68 ;
     RECT  5.141 3.36 5.825 29.016 ;
     RECT  5.825 12.48 6.275 29.016 ;
     RECT  5.699 30.192 6.685 34.776 ;
     RECT  5.699 36.24 6.685 64.68 ;
     RECT  5.825 3.36 6.721 11.112 ;
     RECT  6.685 30.192 6.853 64.68 ;
     RECT  5.537 65.808 6.853 66.84 ;
     RECT  6.275 24.672 6.901 29.016 ;
     RECT  6.853 30.192 6.901 66.84 ;
     RECT  6.275 12.48 6.937 23.688 ;
     RECT  6.721 2.496 7.237 11.112 ;
     RECT  6.937 12.432 7.333 23.688 ;
     RECT  7.237 2.496 7.808 11.16 ;
     RECT  7.333 12.192 7.808 23.688 ;
     RECT  6.901 24.672 7.808 66.84 ;
     RECT  7.808 2.148 7.912 66.84 ;
     RECT  7.912 2.418 8.104 66.84 ;
     RECT  8.104 2.688 8.273 66.84 ;
     RECT  8.273 2.688 8.531 64.68 ;
     RECT  8.531 5.664 8.867 64.68 ;
     RECT  8.531 2.688 9.443 4.152 ;
     RECT  9.443 2.784 9.491 4.152 ;
     RECT  8.273 65.808 9.683 66.84 ;
     RECT  9.683 65.808 9.785 66.792 ;
     RECT  9.785 66.048 9.857 66.792 ;
     RECT  8.867 5.664 10.117 62.568 ;
     RECT  10.117 5.376 10.259 62.568 ;
     RECT  10.259 31.104 10.357 62.568 ;
     RECT  8.867 63.648 10.357 64.68 ;
     RECT  9.491 3.216 10.393 4.152 ;
     RECT  10.259 5.376 10.393 30.072 ;
     RECT  10.357 31.104 10.685 64.68 ;
     RECT  10.685 31.104 10.829 64.392 ;
     RECT  9.857 66.048 10.835 66.264 ;
     RECT  10.393 3.216 10.933 30.072 ;
     RECT  10.829 31.104 11.045 44.472 ;
     RECT  10.829 45.456 11.123 64.392 ;
     RECT  10.885 65.472 11.153 65.544 ;
     RECT  10.933 2.736 11.221 30.072 ;
     RECT  11.045 31.104 11.221 31.896 ;
     RECT  11.125 66.768 11.269 66.792 ;
     RECT  11.221 2.736 11.315 31.896 ;
     RECT  11.123 49.056 11.363 64.392 ;
     RECT  11.123 45.456 11.411 47.832 ;
     RECT  11.411 45.888 11.459 47.832 ;
     RECT  11.315 2.736 11.513 2.856 ;
     RECT  11.459 46.08 11.549 47.832 ;
     RECT  11.363 49.2 11.585 64.392 ;
     RECT  11.315 3.936 11.693 31.896 ;
     RECT  11.153 65.52 11.945 65.544 ;
     RECT  11.693 23.52 12.013 31.896 ;
     RECT  11.045 32.88 12.013 44.472 ;
     RECT  12.013 23.52 12.037 44.472 ;
     RECT  11.513 2.736 12.125 2.76 ;
     RECT  11.585 49.2 12.125 63.24 ;
     RECT  11.269 66.768 12.421 66.84 ;
     RECT  12.421 66.72 12.485 66.84 ;
     RECT  11.693 3.936 12.517 22.392 ;
     RECT  12.037 23.52 12.517 44.904 ;
     RECT  12.485 66.768 12.593 66.84 ;
     RECT  12.517 3.6 12.661 22.392 ;
     RECT  12.517 23.52 12.661 45 ;
     RECT  11.549 46.56 12.901 47.832 ;
     RECT  12.901 46.176 13.021 47.832 ;
     RECT  12.125 49.2 13.021 62.856 ;
     RECT  12.593 66.816 13.133 66.84 ;
     RECT  12.265 2.4 13.208 2.424 ;
     RECT  12.661 3.6 13.208 45 ;
     RECT  13.021 46.176 13.208 62.856 ;
     RECT  11.585 64.32 13.208 64.392 ;
     RECT  13.208 2.148 13.312 64.812 ;
     RECT  13.312 2.418 13.504 64.542 ;
     RECT  13.504 3.888 13.601 63.24 ;
     RECT  13.601 13.392 13.619 63.24 ;
     RECT  13.619 13.824 13.715 28.488 ;
     RECT  13.715 13.92 13.853 28.488 ;
     RECT  13.853 13.92 13.859 28.44 ;
     RECT  13.859 14.256 13.925 28.44 ;
     RECT  13.619 29.616 14.213 63.24 ;
     RECT  14.213 34.848 14.291 63.24 ;
     RECT  13.601 3.888 14.357 12.36 ;
     RECT  13.925 14.4 14.435 28.44 ;
     RECT  14.291 44.976 14.773 63.24 ;
     RECT  13.504 64.272 14.773 64.296 ;
     RECT  14.213 29.616 14.819 33.624 ;
     RECT  14.773 44.976 14.819 64.296 ;
     RECT  14.357 4.176 14.857 12.36 ;
     RECT  14.821 13.392 14.857 13.416 ;
     RECT  14.435 14.496 14.857 28.44 ;
     RECT  14.819 44.976 14.897 63.864 ;
     RECT  14.857 14.496 14.915 28.488 ;
     RECT  14.857 4.176 14.969 13.416 ;
     RECT  14.915 28.464 15.001 28.488 ;
     RECT  14.819 29.616 15.001 31.464 ;
     RECT  15.001 28.464 15.059 31.464 ;
     RECT  15.059 29.76 15.149 31.464 ;
     RECT  14.969 4.512 15.155 13.416 ;
     RECT  15.149 29.76 15.185 31.368 ;
     RECT  14.819 32.448 15.251 33.624 ;
     RECT  14.897 44.976 15.299 63.816 ;
     RECT  15.251 32.688 15.361 33.624 ;
     RECT  14.291 34.848 15.361 43.944 ;
     RECT  15.185 29.76 15.395 30.744 ;
     RECT  15.155 4.8 15.401 13.416 ;
     RECT  15.401 13.056 15.445 13.416 ;
     RECT  14.915 14.496 15.445 27.192 ;
     RECT  15.361 32.688 15.469 43.944 ;
     RECT  15.299 44.976 15.469 47.736 ;
     RECT  15.401 4.8 15.509 12.072 ;
     RECT  15.445 13.056 15.509 27.192 ;
     RECT  15.541 64.992 15.685 65.016 ;
     RECT  15.361 66.144 15.685 66.168 ;
     RECT  15.685 64.992 15.721 66.168 ;
     RECT  15.721 64.992 15.877 66.792 ;
     RECT  15.877 64.992 15.941 66.84 ;
     RECT  15.395 29.76 16.045 30.456 ;
     RECT  15.509 24.912 16.069 27.192 ;
     RECT  15.059 28.464 16.069 28.488 ;
     RECT  15.941 64.992 16.115 66.792 ;
     RECT  16.069 24.912 16.165 28.488 ;
     RECT  16.045 29.712 16.165 30.456 ;
     RECT  15.509 13.056 16.265 23.688 ;
     RECT  15.469 32.688 16.357 47.736 ;
     RECT  15.299 48.768 16.357 63.816 ;
     RECT  16.115 64.992 16.357 66.12 ;
     RECT  16.357 32.688 16.453 63.816 ;
     RECT  16.165 24.912 16.477 30.456 ;
     RECT  16.453 31.824 16.477 63.816 ;
     RECT  16.477 24.912 16.501 63.816 ;
     RECT  15.509 5.28 16.549 12.072 ;
     RECT  16.265 13.056 16.549 13.416 ;
     RECT  16.549 5.232 16.585 13.416 ;
     RECT  16.501 24.672 16.595 63.816 ;
     RECT  16.585 4.272 16.643 13.416 ;
     RECT  16.265 14.496 16.645 23.688 ;
     RECT  16.595 24.672 16.645 63.336 ;
     RECT  16.357 64.944 17.029 66.12 ;
     RECT  16.645 14.496 17.093 63.336 ;
     RECT  16.643 4.272 17.125 13.368 ;
     RECT  17.093 34.992 17.201 63.336 ;
     RECT  17.201 35.28 17.237 63.336 ;
     RECT  17.237 35.28 17.345 44.616 ;
     RECT  17.125 4.176 17.449 13.368 ;
     RECT  17.029 64.368 17.509 66.12 ;
     RECT  17.449 3.984 17.521 13.368 ;
     RECT  17.521 3.408 17.653 13.368 ;
     RECT  17.093 14.496 17.653 33.624 ;
     RECT  17.237 45.792 17.917 63.336 ;
     RECT  17.509 64.368 17.917 66.84 ;
     RECT  17.653 3.408 18.061 33.624 ;
     RECT  17.917 45.792 18.277 66.84 ;
     RECT  18.277 45.552 18.281 66.84 ;
     RECT  17.345 35.424 18.385 44.472 ;
     RECT  18.061 3.408 18.608 33.96 ;
     RECT  18.385 34.992 18.608 44.472 ;
     RECT  18.281 45.552 18.608 66.792 ;
     RECT  18.608 2.148 18.712 66.792 ;
     RECT  18.712 2.418 18.904 66.792 ;
     RECT  18.904 3.408 19.043 30.984 ;
     RECT  18.904 32.112 19.283 66.792 ;
     RECT  19.043 4.128 19.325 30.984 ;
     RECT  19.325 4.608 19.397 30.984 ;
     RECT  19.283 32.112 19.427 63.288 ;
     RECT  19.427 34.656 19.469 63.288 ;
     RECT  19.469 37.056 19.649 63.288 ;
     RECT  19.397 28.896 19.829 30.984 ;
     RECT  19.829 30.144 20.005 30.984 ;
     RECT  19.427 32.112 20.005 33.624 ;
     RECT  19.397 4.608 20.099 27.912 ;
     RECT  20.099 5.136 20.189 27.912 ;
     RECT  19.649 37.2 20.389 63.288 ;
     RECT  19.283 64.368 20.389 66.792 ;
     RECT  20.005 30.144 20.401 33.624 ;
     RECT  19.469 34.656 20.401 35.928 ;
     RECT  20.189 5.184 20.437 27.912 ;
     RECT  19.829 28.896 20.437 29.16 ;
     RECT  20.389 37.2 20.473 66.792 ;
     RECT  20.473 37.2 20.513 66.84 ;
     RECT  20.513 64.416 20.531 66.84 ;
     RECT  20.401 30.144 20.533 35.928 ;
     RECT  19.957 2.832 20.545 2.856 ;
     RECT  20.437 5.184 20.549 29.16 ;
     RECT  20.545 2.256 20.581 2.856 ;
     RECT  20.533 30.144 20.821 36.12 ;
     RECT  20.513 37.2 20.821 63 ;
     RECT  20.549 5.184 20.837 29.064 ;
     RECT  20.837 23.616 20.909 29.064 ;
     RECT  20.581 2.256 21.013 3.432 ;
     RECT  20.821 30.144 21.017 63 ;
     RECT  21.017 30.24 21.089 63 ;
     RECT  20.837 5.184 21.161 22.44 ;
     RECT  21.161 13.92 21.197 22.44 ;
     RECT  21.161 5.184 21.301 12.024 ;
     RECT  21.089 30.816 21.341 63 ;
     RECT  21.341 30.816 21.347 60.696 ;
     RECT  21.013 2.256 21.409 3.96 ;
     RECT  21.301 5.088 21.409 12.024 ;
     RECT  21.409 2.256 21.443 4.008 ;
     RECT  21.443 2.832 21.445 4.008 ;
     RECT  21.409 4.992 21.445 12.024 ;
     RECT  21.347 30.816 21.449 60.168 ;
     RECT  21.445 2.832 21.635 12.024 ;
     RECT  21.635 3.264 21.683 12.024 ;
     RECT  21.341 61.872 21.809 63 ;
     RECT  21.683 3.264 21.845 11.976 ;
     RECT  20.909 23.616 21.913 27.768 ;
     RECT  20.909 28.944 21.913 29.064 ;
     RECT  21.913 23.376 21.973 27.768 ;
     RECT  20.531 64.416 21.985 66.168 ;
     RECT  21.973 23.376 22.057 27.816 ;
     RECT  21.913 28.944 22.057 29.112 ;
     RECT  22.057 23.376 22.165 29.112 ;
     RECT  22.165 23.376 22.211 29.688 ;
     RECT  21.985 64.416 22.355 66.84 ;
     RECT  21.449 30.816 22.357 45 ;
     RECT  21.197 13.92 22.417 22.344 ;
     RECT  22.211 23.376 22.417 29.064 ;
     RECT  21.809 62.256 22.565 63 ;
     RECT  22.357 30.768 22.597 45 ;
     RECT  21.449 46.128 22.597 60.168 ;
     RECT  22.777 61.2 22.789 61.224 ;
     RECT  22.565 62.256 22.789 62.664 ;
     RECT  22.597 30.768 22.813 60.168 ;
     RECT  21.845 3.312 22.885 11.976 ;
     RECT  22.355 64.416 22.981 66.168 ;
     RECT  22.885 3.312 23.101 12.792 ;
     RECT  23.101 2.592 23.173 12.792 ;
     RECT  22.981 64.368 23.173 66.168 ;
     RECT  22.417 13.92 23.209 29.064 ;
     RECT  22.813 30.144 23.209 60.168 ;
     RECT  23.173 64.32 23.365 66.168 ;
     RECT  23.365 64.32 23.429 66.84 ;
     RECT  23.209 13.92 23.461 60.168 ;
     RECT  22.789 61.2 23.461 62.664 ;
     RECT  23.173 2.256 23.497 12.792 ;
     RECT  23.461 13.92 23.569 62.664 ;
     RECT  23.569 13.92 23.749 62.856 ;
     RECT  23.749 13.92 23.821 62.904 ;
     RECT  23.497 2.256 24.008 12.936 ;
     RECT  23.821 13.92 24.008 63.288 ;
     RECT  23.429 64.32 24.008 66.792 ;
     RECT  24.008 2.148 24.112 66.792 ;
     RECT  24.112 2.418 24.304 66.792 ;
     RECT  24.304 4.848 24.419 66.792 ;
     RECT  24.419 4.848 24.473 66.696 ;
     RECT  24.473 30.048 25.043 66.696 ;
     RECT  25.043 66.048 25.381 66.696 ;
     RECT  25.381 66.048 25.445 66.84 ;
     RECT  25.445 66.048 25.517 66.648 ;
     RECT  24.304 2.592 25.549 3.144 ;
     RECT  24.473 4.848 25.667 28.488 ;
     RECT  25.667 24.768 25.717 28.488 ;
     RECT  25.043 30.048 25.717 65.016 ;
     RECT  25.717 24.768 25.733 65.016 ;
     RECT  25.733 24.768 25.805 44.76 ;
     RECT  25.805 24.768 26.021 44.616 ;
     RECT  25.733 45.792 26.129 65.016 ;
     RECT  25.667 4.848 26.437 23.688 ;
     RECT  25.517 66.096 26.437 66.648 ;
     RECT  26.021 29.472 26.489 44.616 ;
     RECT  25.549 2.592 26.561 3.192 ;
     RECT  26.129 45.792 26.561 64.392 ;
     RECT  26.437 66.096 26.581 66.792 ;
     RECT  26.581 66.048 26.629 66.792 ;
     RECT  26.489 29.568 26.633 44.616 ;
     RECT  26.561 2.592 26.669 3.048 ;
     RECT  26.437 4.512 26.701 23.688 ;
     RECT  26.021 24.768 26.771 28.44 ;
     RECT  26.629 65.52 26.777 66.792 ;
     RECT  26.633 30.144 26.809 44.616 ;
     RECT  26.561 45.792 26.809 50.424 ;
     RECT  26.777 66.768 26.821 66.792 ;
     RECT  26.773 2.352 26.881 2.568 ;
     RECT  26.821 66.768 26.993 66.84 ;
     RECT  26.561 51.408 27.065 64.392 ;
     RECT  26.881 2.304 27.277 2.568 ;
     RECT  26.701 4.032 27.349 23.688 ;
     RECT  26.771 25.2 27.493 28.44 ;
     RECT  26.809 30.144 27.541 50.424 ;
     RECT  27.065 51.408 27.541 63.96 ;
     RECT  27.277 2.16 27.565 2.568 ;
     RECT  26.777 65.52 27.589 65.544 ;
     RECT  27.493 25.2 27.673 28.776 ;
     RECT  27.565 2.064 27.709 2.568 ;
     RECT  27.349 4.032 27.709 23.976 ;
     RECT  27.589 64.944 27.893 65.544 ;
     RECT  27.709 2.064 27.923 23.976 ;
     RECT  27.923 2.256 27.925 23.976 ;
     RECT  27.673 25.2 27.925 28.824 ;
     RECT  27.541 30.144 27.929 63.96 ;
     RECT  27.893 65.52 27.929 65.544 ;
     RECT  27.925 2.256 28.165 28.824 ;
     RECT  27.929 30.144 28.165 44.472 ;
     RECT  28.165 2.256 28.217 44.472 ;
     RECT  28.217 2.256 28.307 30.168 ;
     RECT  27.929 45.456 28.321 63.96 ;
     RECT  28.321 45.456 29.077 64.536 ;
     RECT  26.993 66.816 29.125 66.84 ;
     RECT  28.217 31.2 29.173 44.472 ;
     RECT  29.077 45.456 29.173 64.632 ;
     RECT  28.307 2.4 29.269 30.168 ;
     RECT  29.173 31.2 29.269 64.632 ;
     RECT  29.269 2.4 29.408 64.632 ;
     RECT  29.408 2.148 29.512 64.812 ;
     RECT  29.512 2.256 29.704 64.812 ;
     RECT  29.704 34.944 30.121 64.812 ;
     RECT  29.704 2.256 30.227 33.96 ;
     RECT  30.121 34.944 30.515 65.016 ;
     RECT  30.227 2.304 30.629 33.96 ;
     RECT  30.515 34.944 30.737 64.968 ;
     RECT  30.629 2.304 30.845 22.632 ;
     RECT  30.737 34.944 30.947 64.584 ;
     RECT  30.947 51.456 31.025 64.584 ;
     RECT  30.481 0.048 31.129 0.072 ;
     RECT  30.629 23.808 31.165 33.96 ;
     RECT  30.947 34.944 31.165 50.472 ;
     RECT  31.165 23.808 31.331 50.472 ;
     RECT  31.129 0.048 31.381 0.216 ;
     RECT  31.331 23.808 31.385 23.832 ;
     RECT  31.025 55.488 31.427 64.584 ;
     RECT  31.331 25.104 31.493 50.472 ;
     RECT  31.427 55.488 31.493 64.488 ;
     RECT  30.845 2.304 31.849 12.552 ;
     RECT  30.845 13.68 31.849 22.632 ;
     RECT  31.849 2.304 31.921 22.632 ;
     RECT  31.493 55.488 31.997 63.816 ;
     RECT  31.493 36.096 32.101 50.472 ;
     RECT  31.025 51.456 32.101 54.504 ;
     RECT  32.101 36.096 32.147 54.504 ;
     RECT  31.997 55.488 32.249 61.56 ;
     RECT  32.147 51.312 32.281 54.504 ;
     RECT  32.249 55.488 32.281 61.272 ;
     RECT  32.281 51.312 32.291 61.272 ;
     RECT  32.147 36.096 32.485 50.136 ;
     RECT  29.125 66.096 32.485 66.84 ;
     RECT  31.921 2.304 32.497 22.824 ;
     RECT  31.997 62.688 32.573 63.816 ;
     RECT  32.573 62.736 32.581 63.816 ;
     RECT  32.497 2.304 32.641 23.16 ;
     RECT  31.493 25.104 32.713 34.968 ;
     RECT  32.485 36 32.713 50.136 ;
     RECT  32.641 2.304 32.821 23.832 ;
     RECT  31.381 0.048 32.869 0.264 ;
     RECT  32.581 62.736 32.893 64.44 ;
     RECT  32.485 65.52 32.893 66.84 ;
     RECT  32.821 2.304 32.917 23.976 ;
     RECT  32.713 25.104 32.917 50.136 ;
     RECT  32.869 0.048 33.011 0.312 ;
     RECT  32.917 2.304 33.059 50.136 ;
     RECT  33.011 0.048 33.077 0.264 ;
     RECT  32.893 62.736 33.293 66.84 ;
     RECT  33.059 29.76 33.329 50.136 ;
     RECT  32.291 51.312 33.361 61.08 ;
     RECT  33.329 29.904 33.433 50.136 ;
     RECT  33.361 51.312 33.433 61.128 ;
     RECT  33.293 62.736 33.491 66.216 ;
     RECT  33.433 29.904 33.509 61.128 ;
     RECT  33.509 29.904 33.581 48.264 ;
     RECT  33.491 62.736 33.683 66.12 ;
     RECT  33.059 2.304 33.725 28.584 ;
     RECT  33.725 2.304 33.761 23.976 ;
     RECT  33.077 0.096 33.779 0.264 ;
     RECT  33.581 29.952 33.797 48.264 ;
     RECT  33.683 62.736 34.081 64.44 ;
     RECT  33.779 0.096 34.259 0.168 ;
     RECT  33.683 65.52 34.265 66.12 ;
     RECT  33.509 49.248 34.405 61.128 ;
     RECT  34.081 62.304 34.405 64.44 ;
     RECT  34.265 66.096 34.501 66.12 ;
     RECT  34.501 66.096 34.517 66.84 ;
     RECT  34.517 66.144 34.553 66.84 ;
     RECT  33.797 30.192 34.585 48.264 ;
     RECT  34.405 49.248 34.585 64.44 ;
     RECT  33.761 2.304 34.729 23.736 ;
     RECT  34.553 66.144 34.733 66.264 ;
     RECT  33.725 25.056 34.765 28.584 ;
     RECT  34.733 66.24 34.769 66.264 ;
     RECT  34.729 2.016 34.808 23.736 ;
     RECT  34.765 25.056 34.808 28.776 ;
     RECT  34.585 30.192 34.808 64.44 ;
     RECT  34.808 2.016 34.912 64.812 ;
     RECT  34.912 2.016 34.985 64.542 ;
     RECT  34.259 0.144 35.077 0.168 ;
     RECT  34.985 2.208 35.104 64.542 ;
     RECT  35.077 0.144 35.219 0.264 ;
     RECT  35.219 0.144 35.267 0.168 ;
     RECT  35.104 46.944 35.345 48.264 ;
     RECT  35.104 2.208 35.363 45.816 ;
     RECT  35.363 33.36 35.597 45.816 ;
     RECT  35.363 2.208 35.747 32.376 ;
     RECT  35.747 2.256 35.891 32.376 ;
     RECT  35.345 46.944 35.891 47.88 ;
     RECT  35.104 49.248 35.993 64.008 ;
     RECT  35.891 24.576 36.035 30.6 ;
     RECT  35.891 2.256 36.137 23.592 ;
     RECT  36.035 24.72 36.227 30.6 ;
     RECT  35.891 31.584 36.373 32.376 ;
     RECT  35.597 33.36 36.373 44.568 ;
     RECT  35.891 47.184 36.469 47.88 ;
     RECT  35.993 49.248 36.469 63.816 ;
     RECT  36.373 31.584 36.709 44.568 ;
     RECT  36.227 30.096 36.961 30.6 ;
     RECT  36.709 31.584 36.961 44.664 ;
     RECT  35.597 45.792 36.997 45.816 ;
     RECT  36.997 45.648 37.033 45.816 ;
     RECT  36.469 47.184 37.033 63.816 ;
     RECT  36.137 2.352 37.045 23.592 ;
     RECT  36.227 24.72 37.045 29.112 ;
     RECT  36.961 30.096 37.105 44.664 ;
     RECT  37.033 45.648 37.105 63.816 ;
     RECT  37.045 2.352 37.181 29.112 ;
     RECT  37.181 24.24 37.237 29.112 ;
     RECT  37.105 30.096 37.237 63.816 ;
     RECT  37.237 24.24 37.331 63.816 ;
     RECT  37.181 2.352 37.429 23.16 ;
     RECT  37.331 47.184 37.429 63.816 ;
     RECT  37.331 24.24 37.541 44.664 ;
     RECT  37.541 24.24 37.619 43.704 ;
     RECT  37.429 47.184 37.645 64.056 ;
     RECT  37.645 47.184 37.685 64.584 ;
     RECT  37.685 48.432 37.861 64.584 ;
     RECT  37.429 2.208 37.973 23.16 ;
     RECT  37.861 48.432 38.153 65.544 ;
     RECT  37.973 2.208 38.195 22.68 ;
     RECT  37.331 45.648 38.225 46.2 ;
     RECT  38.153 51.648 38.225 65.544 ;
     RECT  38.225 64.992 38.341 65.544 ;
     RECT  37.619 24.24 38.437 30.264 ;
     RECT  37.619 31.296 38.441 43.704 ;
     RECT  38.341 64.992 38.533 65.64 ;
     RECT  38.225 45.648 38.653 45.816 ;
     RECT  38.437 24.144 38.773 30.264 ;
     RECT  37.685 47.184 38.773 47.448 ;
     RECT  38.773 46.8 38.905 47.448 ;
     RECT  38.153 48.432 38.905 50.664 ;
     RECT  38.441 31.44 38.941 43.704 ;
     RECT  38.653 44.688 38.941 45.816 ;
     RECT  38.195 2.256 39.301 22.68 ;
     RECT  38.773 24.048 39.301 30.264 ;
     RECT  38.869 0.096 39.373 0.12 ;
     RECT  38.941 31.44 39.373 45.816 ;
     RECT  38.905 46.8 39.373 50.664 ;
     RECT  39.301 2.256 39.397 30.264 ;
     RECT  39.373 0.096 39.445 0.168 ;
     RECT  39.397 2.208 39.553 30.264 ;
     RECT  39.373 31.44 39.553 50.664 ;
     RECT  39.553 2.208 39.769 50.664 ;
     RECT  38.225 51.648 39.769 63.816 ;
     RECT  38.533 64.992 39.769 66.12 ;
     RECT  39.769 64.944 39.841 66.12 ;
     RECT  39.445 0.096 39.973 0.216 ;
     RECT  39.973 0.096 40.021 0.36 ;
     RECT  39.769 2.208 40.208 63.816 ;
     RECT  39.841 64.944 40.208 66.216 ;
     RECT  40.208 2.148 40.312 66.216 ;
     RECT  40.312 2.304 40.357 66.216 ;
     RECT  40.357 2.304 40.421 66.84 ;
     RECT  40.021 0.096 40.453 0.456 ;
     RECT  40.421 2.304 40.504 66.12 ;
     RECT  40.453 0.096 40.565 0.552 ;
     RECT  40.504 64.944 40.817 66.12 ;
     RECT  40.504 62.16 40.853 63.912 ;
     RECT  40.817 66.096 40.853 66.12 ;
     RECT  40.504 2.304 40.889 61.032 ;
     RECT  40.817 64.944 40.889 65.016 ;
     RECT  40.889 2.304 41.105 60.456 ;
     RECT  40.853 62.736 41.141 63.912 ;
     RECT  41.105 2.304 41.573 49.368 ;
     RECT  41.141 62.784 41.605 63.912 ;
     RECT  41.573 2.304 41.825 30.408 ;
     RECT  41.825 2.304 42.077 30.264 ;
     RECT  41.605 62.784 42.113 64.344 ;
     RECT  42.077 2.304 42.227 30.216 ;
     RECT  40.565 0.096 42.253 0.12 ;
     RECT  41.105 50.352 42.289 60.456 ;
     RECT  42.253 0.096 42.325 0.168 ;
     RECT  41.573 31.392 42.329 49.368 ;
     RECT  42.289 50.352 42.373 60.84 ;
     RECT  42.329 31.392 42.437 48.168 ;
     RECT  42.325 0.096 42.515 0.264 ;
     RECT  42.113 62.784 42.577 64.008 ;
     RECT  42.577 62.688 42.659 64.008 ;
     RECT  42.329 49.344 42.721 49.368 ;
     RECT  42.373 50.352 42.721 61.656 ;
     RECT  42.721 49.344 42.797 61.656 ;
     RECT  42.437 31.392 42.869 47.448 ;
     RECT  42.515 0.096 42.899 0.216 ;
     RECT  42.797 49.344 42.941 61.224 ;
     RECT  42.659 62.784 43.049 64.008 ;
     RECT  42.899 0.096 43.187 0.168 ;
     RECT  42.227 23.664 43.331 30.216 ;
     RECT  42.227 2.304 43.333 22.632 ;
     RECT  43.331 23.664 43.333 30.12 ;
     RECT  42.941 49.344 43.441 60.408 ;
     RECT  42.869 31.392 43.573 32.328 ;
     RECT  43.477 64.176 43.589 64.2 ;
     RECT  42.869 33.36 43.625 47.448 ;
     RECT  43.625 33.36 43.805 44.424 ;
     RECT  43.625 45.456 43.805 47.448 ;
     RECT  43.333 2.304 43.907 30.12 ;
     RECT  43.907 2.304 43.909 22.248 ;
     RECT  43.573 31.296 43.909 32.328 ;
     RECT  43.805 33.36 43.909 43.8 ;
     RECT  43.909 2.256 43.985 22.248 ;
     RECT  43.441 48.768 44.483 60.408 ;
     RECT  43.907 23.328 44.485 30.12 ;
     RECT  43.909 31.296 44.485 43.8 ;
     RECT  43.805 45.792 44.737 47.448 ;
     RECT  44.483 48.768 44.737 50.568 ;
     RECT  44.485 23.328 44.809 43.8 ;
     RECT  44.737 45.792 44.917 50.568 ;
     RECT  43.187 0.096 44.965 0.12 ;
     RECT  43.985 2.304 45.025 22.248 ;
     RECT  44.809 23.328 45.025 44.52 ;
     RECT  44.965 0.096 45.029 0.168 ;
     RECT  43.049 62.784 45.157 62.856 ;
     RECT  45.029 0.144 45.317 0.168 ;
     RECT  45.025 2.304 45.608 44.52 ;
     RECT  44.917 45.552 45.608 50.568 ;
     RECT  44.483 51.648 45.608 60.408 ;
     RECT  45.157 62.64 45.608 62.856 ;
     RECT  45.608 2.148 45.712 64.812 ;
     RECT  45.712 2.304 45.904 64.542 ;
     RECT  45.904 2.304 46.067 63.72 ;
     RECT  46.067 2.304 46.115 50.52 ;
     RECT  46.067 51.696 46.181 63.72 ;
     RECT  46.115 2.304 47.045 50.472 ;
     RECT  47.045 2.304 47.117 43.896 ;
     RECT  46.741 0.144 47.123 0.168 ;
     RECT  47.045 44.976 47.221 50.472 ;
     RECT  46.181 51.696 47.221 63.288 ;
     RECT  45.961 65.808 47.257 65.832 ;
     RECT  46.285 66.816 47.257 66.84 ;
     RECT  47.221 44.976 47.261 63.336 ;
     RECT  47.261 50.4 47.267 63.336 ;
     RECT  47.257 65.808 47.315 66.84 ;
     RECT  47.261 44.976 47.369 49.368 ;
     RECT  47.267 50.4 47.555 63 ;
     RECT  47.461 64.368 47.557 64.392 ;
     RECT  47.117 2.304 47.581 43.8 ;
     RECT  47.581 2.256 47.651 43.8 ;
     RECT  47.557 64.32 47.653 64.392 ;
     RECT  47.315 65.808 47.653 66.12 ;
     RECT  47.653 64.32 47.699 66.12 ;
     RECT  47.699 64.32 47.749 64.392 ;
     RECT  47.651 2.304 48.181 43.8 ;
     RECT  47.369 44.976 48.181 45.816 ;
     RECT  47.555 61.968 48.301 63 ;
     RECT  47.749 64.176 48.301 64.392 ;
     RECT  47.699 65.52 48.371 66.12 ;
     RECT  48.181 2.304 48.517 45.816 ;
     RECT  47.369 46.992 48.517 49.368 ;
     RECT  48.301 61.968 48.553 64.392 ;
     RECT  47.555 50.4 48.613 60.84 ;
     RECT  48.613 50.352 48.661 60.84 ;
     RECT  48.553 61.824 48.661 64.392 ;
     RECT  48.661 50.352 48.697 64.392 ;
     RECT  48.371 65.52 48.697 65.832 ;
     RECT  48.697 0.096 48.755 0.12 ;
     RECT  48.697 50.352 48.755 65.832 ;
     RECT  48.755 65.808 48.947 65.832 ;
     RECT  48.755 50.352 49.133 64.344 ;
     RECT  48.997 1.152 49.187 1.176 ;
     RECT  49.133 62.784 49.277 64.344 ;
     RECT  48.517 2.304 49.457 49.368 ;
     RECT  49.133 50.352 49.673 61.608 ;
     RECT  49.457 2.304 50.101 47.448 ;
     RECT  49.457 48.768 50.101 49.368 ;
     RECT  49.673 50.352 50.101 60.408 ;
     RECT  49.673 61.536 50.101 61.608 ;
     RECT  49.277 62.784 50.101 64.2 ;
     RECT  49.993 0.528 50.195 0.552 ;
     RECT  50.341 0.096 50.393 0.216 ;
     RECT  50.101 61.536 50.461 64.2 ;
     RECT  50.101 48.768 50.713 60.408 ;
     RECT  50.101 2.256 50.749 47.448 ;
     RECT  50.713 48.672 50.821 60.408 ;
     RECT  50.461 61.536 50.821 64.392 ;
     RECT  50.821 48.672 50.869 64.392 ;
     RECT  50.749 1.968 51.008 47.688 ;
     RECT  50.869 48.672 51.008 64.44 ;
     RECT  51.008 1.968 51.112 64.812 ;
     RECT  50.393 0.192 51.301 0.216 ;
     RECT  51.112 1.968 51.304 64.542 ;
     RECT  51.304 62.16 51.329 64.2 ;
     RECT  51.301 0.192 51.397 0.312 ;
     RECT  51.397 0.096 51.433 0.312 ;
     RECT  51.433 0.096 51.637 0.504 ;
     RECT  51.304 1.968 51.637 61.128 ;
     RECT  51.637 0.096 51.653 61.128 ;
     RECT  51.653 0.144 51.779 61.128 ;
     RECT  51.779 2.064 51.875 61.128 ;
     RECT  51.329 62.16 51.923 63.864 ;
     RECT  51.875 2.688 52.121 61.128 ;
     RECT  52.121 23.424 52.357 61.128 ;
     RECT  51.923 62.16 52.357 63.816 ;
     RECT  52.357 23.424 52.589 63.816 ;
     RECT  52.589 47.184 52.949 63.816 ;
     RECT  52.949 61.728 53.027 63.816 ;
     RECT  52.121 2.688 53.125 22.344 ;
     RECT  52.589 23.424 53.125 45.816 ;
     RECT  53.027 62.304 53.129 63.816 ;
     RECT  53.125 2.688 53.197 45.816 ;
     RECT  51.779 0.144 53.509 0.552 ;
     RECT  53.129 62.4 53.633 63.816 ;
     RECT  52.949 47.184 53.669 60.552 ;
     RECT  53.197 2.352 53.845 45.816 ;
     RECT  53.845 2.352 53.941 46.008 ;
     RECT  53.669 47.184 53.941 49.368 ;
     RECT  53.669 50.352 53.989 60.552 ;
     RECT  53.941 2.352 54.025 49.368 ;
     RECT  53.633 62.784 54.131 63.816 ;
     RECT  53.509 0.096 54.227 0.552 ;
     RECT  54.227 0.096 54.323 0.456 ;
     RECT  53.989 50.352 54.601 61.272 ;
     RECT  54.131 62.784 54.601 63.768 ;
     RECT  54.601 50.352 54.785 63.768 ;
     RECT  54.785 62.256 55.093 63.768 ;
     RECT  55.093 62.256 55.145 64.2 ;
     RECT  54.025 2.304 55.285 49.368 ;
     RECT  54.785 50.352 55.285 61.032 ;
     RECT  55.145 62.256 55.861 64.104 ;
     RECT  54.323 0.096 56.245 0.216 ;
     RECT  55.285 2.304 56.408 61.032 ;
     RECT  55.861 62.16 56.408 64.104 ;
     RECT  56.408 2.148 56.485 64.812 ;
     RECT  56.485 2.016 56.512 64.812 ;
     RECT  56.512 2.016 56.585 64.542 ;
     RECT  56.585 2.256 56.704 64.542 ;
     RECT  56.704 2.256 56.765 60.936 ;
     RECT  56.245 0.096 56.819 0.312 ;
     RECT  56.819 0.144 56.915 0.216 ;
     RECT  56.915 0.192 57.011 0.216 ;
     RECT  56.765 2.304 57.733 60.936 ;
     RECT  56.704 61.968 57.733 64.536 ;
     RECT  57.733 2.256 57.875 64.536 ;
     RECT  57.875 2.256 57.877 64.44 ;
     RECT  57.877 2.208 57.989 64.44 ;
     RECT  57.989 2.208 58.133 43.944 ;
     RECT  58.133 2.208 58.169 38.328 ;
     RECT  57.989 44.976 58.205 64.44 ;
     RECT  58.309 0.096 58.381 0.12 ;
     RECT  58.169 2.256 58.385 38.328 ;
     RECT  58.133 39.36 58.421 43.944 ;
     RECT  58.381 0.096 58.451 0.168 ;
     RECT  58.205 44.976 58.499 64.008 ;
     RECT  58.499 45.024 58.997 64.008 ;
     RECT  58.997 45.024 59.321 63.864 ;
     RECT  58.421 39.36 59.389 43.656 ;
     RECT  58.451 0.096 59.507 0.12 ;
     RECT  58.385 2.304 59.533 38.328 ;
     RECT  59.389 39.36 59.533 43.944 ;
     RECT  59.533 2.304 59.713 43.944 ;
     RECT  59.321 45.024 59.713 63.768 ;
     RECT  59.713 2.304 59.785 63.768 ;
     RECT  59.785 2.208 59.969 63.768 ;
     RECT  59.969 24.528 60.473 63.768 ;
     RECT  60.473 62.208 60.829 63.768 ;
     RECT  60.473 24.528 60.997 61.128 ;
     RECT  60.829 0.096 61.093 0.12 ;
     RECT  60.997 24.48 61.261 61.128 ;
     RECT  61.093 0.096 61.337 0.264 ;
     RECT  59.969 2.304 61.369 23.304 ;
     RECT  61.261 24.336 61.369 61.128 ;
     RECT  61.369 2.304 61.573 61.128 ;
     RECT  60.829 62.208 61.573 64.632 ;
     RECT  61.573 2.304 61.729 64.632 ;
     RECT  61.729 2.016 61.808 64.632 ;
     RECT  61.337 0.096 61.907 0.168 ;
     RECT  61.808 2.016 61.912 64.812 ;
     RECT  61.912 2.016 61.949 64.632 ;
     RECT  61.949 2.016 62.003 64.542 ;
     RECT  62.003 2.256 62.099 64.542 ;
     RECT  62.099 2.304 62.104 64.542 ;
     RECT  61.907 0.096 62.777 0.12 ;
     RECT  62.104 2.304 63.253 64.008 ;
     RECT  63.253 2.304 63.281 64.344 ;
     RECT  63.281 2.304 63.461 19.368 ;
     RECT  63.281 20.352 63.829 64.344 ;
     RECT  63.829 20.352 63.961 64.44 ;
     RECT  63.461 2.304 64.253 19.176 ;
     RECT  63.961 20.352 64.253 64.488 ;
     RECT  64.253 3.984 64.289 19.176 ;
     RECT  64.253 2.304 64.325 2.856 ;
     RECT  64.253 21.12 64.325 64.488 ;
     RECT  64.325 2.4 64.361 2.856 ;
     RECT  63.781 0.096 64.403 0.12 ;
     RECT  64.289 3.984 64.403 13.8 ;
     RECT  64.325 21.12 64.403 33.576 ;
     RECT  64.325 34.704 64.403 64.488 ;
     RECT  64.403 34.752 64.451 42.36 ;
     RECT  64.403 49.584 64.451 55.944 ;
     RECT  64.403 3.984 64.469 10.296 ;
     RECT  64.403 11.376 64.469 13.8 ;
     RECT  64.451 49.968 64.469 55.944 ;
     RECT  64.403 33.552 64.499 33.576 ;
     RECT  64.403 56.928 64.499 62.616 ;
     RECT  64.469 3.984 64.505 5.832 ;
     RECT  64.361 2.832 64.541 2.856 ;
     RECT  64.499 56.928 64.541 62.28 ;
     RECT  64.505 4.56 64.547 5.832 ;
     RECT  64.469 11.376 64.577 13.656 ;
     RECT  64.289 14.832 64.577 19.176 ;
     RECT  64.469 53.088 64.577 55.944 ;
     RECT  64.547 5.088 64.613 5.832 ;
     RECT  64.451 34.752 64.613 42.168 ;
     RECT  64.577 55.872 64.613 55.944 ;
     RECT  64.541 56.928 64.613 60.888 ;
     RECT  64.469 49.968 64.649 51.912 ;
     RECT  64.469 7.728 64.685 10.296 ;
     RECT  64.577 11.472 64.685 13.656 ;
     RECT  64.403 21.12 64.685 32.52 ;
     RECT  64.613 34.752 64.685 41.592 ;
     RECT  64.403 43.344 64.685 48.6 ;
     RECT  64.577 53.088 64.685 54.696 ;
     RECT  64.541 62.16 64.685 62.28 ;
     RECT  64.613 5.088 64.691 5.112 ;
     RECT  64.685 35.232 64.691 41.592 ;
     RECT  64.613 55.872 64.691 55.896 ;
     RECT  64.613 57.264 64.691 60.888 ;
     RECT  64.577 14.832 64.739 18.888 ;
     RECT  64.691 35.232 64.739 35.256 ;
     RECT  64.685 53.088 64.787 54.072 ;
     RECT  64.685 11.52 64.793 13.272 ;
     RECT  64.739 14.928 64.931 18.888 ;
     RECT  64.685 43.344 64.931 43.848 ;
     RECT  64.685 45.072 64.931 47.784 ;
     RECT  64.691 36.48 64.979 41.592 ;
     RECT  64.931 45.072 64.979 47.352 ;
     RECT  64.787 53.088 64.979 53.208 ;
     RECT  64.685 62.16 64.979 62.184 ;
     RECT  64.403 64.416 64.979 64.44 ;
     RECT  64.979 38.64 65.027 41.592 ;
     RECT  64.691 60.096 65.027 60.888 ;
     RECT  64.649 51.312 65.437 51.912 ;
     RECT  64.685 7.728 65.545 9.48 ;
     RECT  65.041 19.92 65.545 19.944 ;
     RECT  64.685 21.12 65.545 32.088 ;
     RECT  65.027 60.24 65.545 60.888 ;
     RECT  65.027 38.784 65.549 41.592 ;
     RECT  65.549 39.216 65.555 41.592 ;
     RECT  65.545 60.24 65.603 61.416 ;
     RECT  65.545 7.344 66.013 9.48 ;
     RECT  64.931 14.976 66.049 18.888 ;
     RECT  65.545 19.92 66.083 32.088 ;
     RECT  64.793 11.52 66.085 12.936 ;
     RECT  66.049 14.928 66.085 18.888 ;
     RECT  65.545 34.032 66.085 34.056 ;
     RECT  64.979 37.008 66.085 37.032 ;
     RECT  65.545 42.912 66.085 42.936 ;
     RECT  64.979 45.936 66.085 47.352 ;
     RECT  65.545 48.816 66.085 48.84 ;
     RECT  65.437 51.312 66.085 52.392 ;
     RECT  64.691 57.264 66.085 58.968 ;
     RECT  65.603 60.24 66.085 60.648 ;
     RECT  66.049 62.832 66.085 62.856 ;
     RECT  66.013 7.344 66.121 9.672 ;
     RECT  66.085 11.52 66.121 18.888 ;
     RECT  66.083 21.12 66.121 32.088 ;
     RECT  66.085 42.672 66.121 42.936 ;
     RECT  66.085 44.352 66.121 44.376 ;
     RECT  66.085 45.408 66.121 48.984 ;
     RECT  66.085 57.264 66.121 60.648 ;
     RECT  66.085 63.84 66.121 63.864 ;
     RECT  66.083 19.92 66.131 19.944 ;
     RECT  66.121 21.12 66.131 32.808 ;
     RECT  66.121 42.672 66.131 48.984 ;
     RECT  66.121 56.304 66.131 60.648 ;
     RECT  66.085 61.632 66.131 62.856 ;
     RECT  66.121 7.152 66.133 18.888 ;
     RECT  66.131 22.848 66.133 32.808 ;
     RECT  66.085 33.936 66.133 34.056 ;
     RECT  66.085 35.376 66.133 35.4 ;
     RECT  66.085 37.008 66.133 37.608 ;
     RECT  64.649 49.968 66.133 49.992 ;
     RECT  66.085 51.312 66.133 52.488 ;
     RECT  66.121 54.576 66.133 54.6 ;
     RECT  66.131 56.304 66.133 58.632 ;
     RECT  66.131 21.12 66.179 21.864 ;
     RECT  65.555 39.216 66.179 41.208 ;
     RECT  66.131 42.672 66.179 43.464 ;
     RECT  66.131 44.448 66.179 48.984 ;
     RECT  66.121 63.84 66.179 64.392 ;
     RECT  66.179 21.648 66.227 21.864 ;
     RECT  66.179 41.184 66.227 41.208 ;
     RECT  66.179 45.024 66.227 48.984 ;
     RECT  66.227 46.032 66.275 48.984 ;
     RECT  66.275 48.336 66.325 48.984 ;
     RECT  66.133 49.968 66.325 52.488 ;
     RECT  66.133 22.848 66.565 37.608 ;
     RECT  66.179 39.216 66.709 39.912 ;
     RECT  66.565 22.848 66.733 37.8 ;
     RECT  66.709 38.784 66.733 39.912 ;
     RECT  66.733 22.848 66.803 39.912 ;
     RECT  66.133 7.152 66.805 19.08 ;
     RECT  66.133 54.576 66.805 58.632 ;
     RECT  66.131 61.776 66.805 62.856 ;
     RECT  66.805 6.96 66.841 19.08 ;
     RECT  66.803 22.896 66.845 39.912 ;
     RECT  66.227 21.84 66.851 21.864 ;
     RECT  66.845 22.992 66.851 39.912 ;
     RECT  66.805 42.528 66.851 42.552 ;
     RECT  66.275 46.032 66.851 46.728 ;
     RECT  66.805 54.48 66.851 58.632 ;
     RECT  66.851 58.608 66.899 58.632 ;
     RECT  66.131 59.856 66.899 60.552 ;
     RECT  66.805 61.776 66.899 63.48 ;
     RECT  66.841 6.864 66.924 19.08 ;
     RECT  66.851 22.992 66.924 38.28 ;
     RECT  66.325 48.336 66.924 52.488 ;
     RECT  66.851 54.48 66.924 57.48 ;
     RECT  66.924 25.536 66.953 25.56 ;
    LAYER M5 ;
     RECT  32.208 0.016 35.208 0.117 ;
     RECT  48.336 0.016 64.392 0.131 ;
     RECT  46.992 0.016 47.304 0.133 ;
     RECT  48.336 0.131 64.296 0.179 ;
     RECT  32.208 0.117 35.304 1.973 ;
     RECT  27.888 2.037 27.912 2.101 ;
     RECT  37.68 1.973 37.704 2.101 ;
     RECT  39.12 0.016 45.288 2.101 ;
     RECT  30.288 2.037 30.312 2.137 ;
     RECT  38.784 2.101 45.288 2.137 ;
     RECT  37.44 2.101 37.704 2.197 ;
     RECT  38.784 2.137 45.72 2.197 ;
     RECT  48.336 0.179 57.48 2.197 ;
     RECT  58.512 0.179 64.296 2.197 ;
     RECT  4.512 2.197 4.536 2.229 ;
     RECT  27.312 2.101 27.912 2.229 ;
     RECT  32.208 1.973 35.736 2.229 ;
     RECT  3.648 2.229 4.584 2.245 ;
     RECT  31.344 2.229 35.736 2.245 ;
     RECT  46.752 0.133 47.304 2.245 ;
     RECT  48.336 2.197 64.296 2.245 ;
     RECT  27.312 2.229 28.296 2.291 ;
     RECT  2.4 2.137 2.52 2.293 ;
     RECT  29.4 2.137 30.312 2.293 ;
     RECT  31.344 2.245 36.024 2.293 ;
     RECT  29.4 2.293 36.024 2.341 ;
     RECT  37.44 2.197 45.72 2.341 ;
     RECT  29.4 2.341 45.72 2.357 ;
     RECT  2.304 2.293 2.52 2.389 ;
     RECT  3.648 2.245 5.208 2.389 ;
     RECT  13.2 2.137 13.32 2.389 ;
     RECT  46.752 2.245 64.296 2.389 ;
     RECT  7.8 2.137 7.92 2.407 ;
     RECT  12.528 2.389 13.32 2.407 ;
     RECT  18.6 2.137 18.72 2.407 ;
     RECT  24 2.137 24.12 2.407 ;
     RECT  28.944 2.357 45.72 2.407 ;
     RECT  46.752 2.389 64.344 2.407 ;
     RECT  0.144 2.293 0.168 2.421 ;
     RECT  2.304 2.389 5.208 2.421 ;
     RECT  27.312 2.291 27.768 2.533 ;
     RECT  27.168 2.533 27.768 2.603 ;
     RECT  9.456 2.613 9.48 2.677 ;
     RECT  11.28 2.613 11.304 2.725 ;
     RECT  24 2.407 24.312 2.773 ;
     RECT  26.112 2.677 26.136 2.773 ;
     RECT  28.944 2.407 64.344 2.805 ;
     RECT  20.592 2.245 21.432 2.821 ;
     RECT  24 2.773 26.136 3.109 ;
     RECT  27.744 2.603 27.768 3.115 ;
     RECT  10.944 2.725 11.304 3.205 ;
     RECT  9.408 2.677 9.48 3.301 ;
     RECT  1.872 2.421 5.208 3.349 ;
     RECT  18.6 2.407 18.912 3.381 ;
     RECT  19.968 2.821 21.624 3.381 ;
     RECT  22.752 3.301 22.776 3.397 ;
     RECT  24 3.109 26.472 3.397 ;
     RECT  18.6 3.381 21.624 3.435 ;
     RECT  20.592 3.435 21.624 3.443 ;
     RECT  0.144 2.421 0.552 3.493 ;
     RECT  21.408 3.443 21.624 3.587 ;
     RECT  1.872 3.349 5.88 3.589 ;
     RECT  12.528 2.407 13.512 3.635 ;
     RECT  0.144 3.493 0.84 3.637 ;
     RECT  1.872 3.589 6.792 3.637 ;
     RECT  21.456 3.587 21.624 3.731 ;
     RECT  7.8 2.407 8.112 3.925 ;
     RECT  9.408 3.301 9.672 3.925 ;
     RECT  10.8 3.205 11.304 3.925 ;
     RECT  28.944 2.805 64.536 3.925 ;
     RECT  28.8 3.925 64.536 4.019 ;
     RECT  28.8 4.019 30.264 4.067 ;
     RECT  18.6 3.435 19.368 4.453 ;
     RECT  0.144 3.637 6.792 4.501 ;
     RECT  7.8 3.925 9.672 4.501 ;
     RECT  22.752 3.397 26.472 4.501 ;
     RECT  28.8 4.067 30.216 4.549 ;
     RECT  13.2 3.635 13.512 4.789 ;
     RECT  15.12 4.501 15.144 4.789 ;
     RECT  17.952 4.453 19.368 4.789 ;
     RECT  21.456 3.731 21.48 4.789 ;
     RECT  22.704 4.501 26.472 4.789 ;
     RECT  14.88 4.789 15.384 4.885 ;
     RECT  13.2 4.789 13.608 4.933 ;
     RECT  21.456 4.789 26.472 4.933 ;
     RECT  27.888 4.549 30.216 4.933 ;
     RECT  21.456 4.933 30.216 5.077 ;
     RECT  31.296 4.019 64.536 5.077 ;
     RECT  0.144 4.501 9.672 5.171 ;
     RECT  17.52 4.789 20.088 5.171 ;
     RECT  21.456 5.077 64.68 5.171 ;
     RECT  17.52 5.171 19.368 5.221 ;
     RECT  22.176 5.171 64.68 5.267 ;
     RECT  14.784 4.885 15.384 5.269 ;
     RECT  6.768 5.171 9.672 5.365 ;
     RECT  10.8 3.925 12.072 5.365 ;
     RECT  13.104 4.933 13.608 5.557 ;
     RECT  13.104 5.557 13.656 5.621 ;
     RECT  14.784 5.269 15.528 5.621 ;
     RECT  20.496 5.301 20.568 5.747 ;
     RECT  16.56 5.221 19.368 6.133 ;
     RECT  0.144 5.171 5.736 6.181 ;
     RECT  6.768 5.365 12.072 6.181 ;
     RECT  16.512 6.133 19.992 6.227 ;
     RECT  21.072 6.181 21.096 6.229 ;
     RECT  22.176 5.267 49.08 6.229 ;
     RECT  0.144 6.181 12.072 6.261 ;
     RECT  13.104 5.621 15.528 6.261 ;
     RECT  16.512 6.227 19.848 6.275 ;
     RECT  0.144 6.261 15.528 6.277 ;
     RECT  16.512 6.275 19.128 6.277 ;
     RECT  0.144 6.277 19.128 6.515 ;
     RECT  0.144 6.515 17.16 6.635 ;
     RECT  16.896 6.635 17.16 6.755 ;
     RECT  21.072 6.229 49.08 6.805 ;
     RECT  50.112 5.267 64.68 6.805 ;
     RECT  0.144 6.635 15.816 6.827 ;
     RECT  18.192 6.515 19.128 6.851 ;
     RECT  21.072 6.805 64.68 6.947 ;
     RECT  24 6.947 64.68 7.275 ;
     RECT  21.072 6.947 22.824 7.381 ;
     RECT  20.976 7.381 22.824 7.403 ;
     RECT  16.896 6.755 17.064 7.797 ;
     RECT  16.896 7.797 17.208 7.909 ;
     RECT  18.192 6.851 18.912 7.909 ;
     RECT  16.896 7.909 18.912 7.989 ;
     RECT  16.896 7.989 19.032 8.117 ;
     RECT  16.896 8.117 19.128 8.181 ;
     RECT  0.144 6.827 10.824 8.437 ;
     RECT  12 6.827 15.816 8.437 ;
     RECT  20.976 7.403 22.392 8.437 ;
     RECT  24 7.275 37.272 8.437 ;
     RECT  20.976 8.437 37.272 8.485 ;
     RECT  38.304 7.275 64.68 8.485 ;
     RECT  0.144 8.437 15.816 8.579 ;
     RECT  66.816 6.901 66.84 8.581 ;
     RECT  16.896 8.181 19.176 8.629 ;
     RECT  20.976 8.485 64.68 8.629 ;
     RECT  15.312 8.579 15.816 8.677 ;
     RECT  16.896 8.629 64.68 8.677 ;
     RECT  0.144 8.579 13.896 8.771 ;
     RECT  15.312 8.677 64.68 8.875 ;
     RECT  0.144 8.771 10.2 8.939 ;
     RECT  66.768 8.581 66.84 9.077 ;
     RECT  36.48 8.875 64.68 9.155 ;
     RECT  66.192 9.077 66.84 9.653 ;
     RECT  15.312 8.875 35.352 9.779 ;
     RECT  11.376 8.771 13.896 9.781 ;
     RECT  21.648 9.779 35.352 9.909 ;
     RECT  66.144 9.653 66.84 9.971 ;
     RECT  11.376 9.781 14.088 10.069 ;
     RECT  66.192 9.971 66.84 10.163 ;
     RECT  0.192 8.939 10.2 10.165 ;
     RECT  11.184 10.069 14.088 10.165 ;
     RECT  21.648 9.909 35.4 10.293 ;
     RECT  36.624 9.155 64.68 10.293 ;
     RECT  0.192 10.165 14.088 10.485 ;
     RECT  21.648 10.293 64.68 10.667 ;
     RECT  15.312 9.779 19.992 10.693 ;
     RECT  0.192 10.485 14.232 10.795 ;
     RECT  2.16 10.795 14.232 10.805 ;
     RECT  15.264 10.693 19.992 10.805 ;
     RECT  21.648 10.667 26.376 10.883 ;
     RECT  27.36 10.667 64.68 10.883 ;
     RECT  0.192 10.795 0.936 11.171 ;
     RECT  66.672 10.163 66.84 11.219 ;
     RECT  21.648 10.883 22.2 11.253 ;
     RECT  2.16 10.805 19.992 11.365 ;
     RECT  21.12 11.253 22.2 11.365 ;
     RECT  29.088 10.883 64.68 11.381 ;
     RECT  2.16 11.365 22.2 11.411 ;
     RECT  2.16 11.411 21.672 11.459 ;
     RECT  23.184 10.883 26.376 11.555 ;
     RECT  2.16 11.459 20.616 11.603 ;
     RECT  17.856 11.603 20.616 11.651 ;
     RECT  27.456 10.883 27.768 11.957 ;
     RECT  21.648 11.459 21.672 12.035 ;
     RECT  27.456 11.957 27.96 12.035 ;
     RECT  2.16 11.603 16.68 12.179 ;
     RECT  66.768 11.219 66.84 12.277 ;
     RECT  23.28 11.555 26.376 12.325 ;
     RECT  27.456 12.035 27.816 12.325 ;
     RECT  29.088 11.381 64.968 12.371 ;
     RECT  66.576 12.277 66.84 12.405 ;
     RECT  66.528 12.405 66.84 12.469 ;
     RECT  12 12.179 16.68 12.523 ;
     RECT  2.16 12.179 10.872 12.563 ;
     RECT  29.088 12.371 64.68 12.715 ;
     RECT  17.856 11.651 18.912 12.917 ;
     RECT  19.92 11.651 20.616 12.917 ;
     RECT  33.312 12.715 64.68 13.139 ;
     RECT  2.16 12.563 5.16 13.235 ;
     RECT  14.64 12.523 16.68 13.333 ;
     RECT  17.856 12.917 20.616 13.333 ;
     RECT  66.48 12.469 66.84 13.381 ;
     RECT  6.288 12.563 10.872 13.621 ;
     RECT  12 12.523 13.656 13.621 ;
     RECT  29.088 12.715 32.28 13.621 ;
     RECT  28.896 13.621 32.28 13.675 ;
     RECT  6.288 13.621 13.656 13.685 ;
     RECT  14.64 13.333 20.616 13.685 ;
     RECT  2.304 13.235 5.16 13.715 ;
     RECT  23.28 12.325 27.816 13.941 ;
     RECT  28.896 13.675 30.552 13.941 ;
     RECT  6.288 13.685 20.616 14.005 ;
     RECT  21.696 13.941 21.72 14.005 ;
     RECT  31.872 13.675 32.28 14.069 ;
     RECT  33.312 13.139 33.336 14.069 ;
     RECT  6.288 14.005 21.72 14.099 ;
     RECT  34.368 13.139 64.68 14.147 ;
     RECT  23.28 13.941 30.552 14.197 ;
     RECT  2.4 13.715 5.16 14.261 ;
     RECT  6.288 14.099 19.032 14.261 ;
     RECT  34.368 14.147 35.928 14.315 ;
     RECT  31.872 14.069 33.336 14.389 ;
     RECT  34.368 14.315 35.88 14.389 ;
     RECT  22.896 14.197 30.552 14.485 ;
     RECT  0.192 11.171 0.84 14.531 ;
     RECT  22.704 14.485 30.552 14.645 ;
     RECT  31.872 14.389 35.88 14.645 ;
     RECT  2.4 14.261 19.032 14.699 ;
     RECT  0.192 14.531 0.216 14.723 ;
     RECT  22.704 14.645 35.88 14.819 ;
     RECT  37.008 14.147 64.68 14.821 ;
     RECT  37.008 14.821 64.728 14.901 ;
     RECT  2.4 14.699 5.784 14.915 ;
     RECT  22.704 14.819 30.744 15.299 ;
     RECT  6.816 14.699 19.032 15.349 ;
     RECT  20.016 14.099 21.72 15.349 ;
     RECT  37.008 14.901 64.92 15.413 ;
     RECT  6.816 15.349 21.72 15.443 ;
     RECT  22.704 15.299 26.808 15.443 ;
     RECT  31.92 14.819 35.88 15.541 ;
     RECT  37.008 15.413 64.968 15.541 ;
     RECT  66.144 13.381 66.84 15.659 ;
     RECT  17.76 15.443 21.72 15.781 ;
     RECT  31.92 15.541 64.968 15.787 ;
     RECT  27.936 15.299 30.744 15.877 ;
     RECT  31.92 15.787 32.184 15.877 ;
     RECT  33.216 15.787 64.968 16.019 ;
     RECT  33.264 16.019 64.968 16.067 ;
     RECT  17.76 15.781 21.768 16.163 ;
     RECT  6.816 15.443 16.104 16.405 ;
     RECT  2.4 14.915 5.736 16.499 ;
     RECT  23.28 15.443 26.808 16.501 ;
     RECT  6.816 16.405 16.152 16.549 ;
     RECT  22.8 16.501 26.808 16.565 ;
     RECT  27.936 15.877 32.184 16.565 ;
     RECT  18.192 16.163 21.768 16.739 ;
     RECT  66.48 15.659 66.84 16.787 ;
     RECT  18.336 16.739 21.768 16.811 ;
     RECT  6.816 16.549 16.68 16.837 ;
     RECT  18.48 16.811 21.768 16.933 ;
     RECT  22.8 16.565 32.184 16.933 ;
     RECT  18.48 16.933 32.184 16.939 ;
     RECT  18.6 16.939 32.184 16.981 ;
     RECT  33.264 16.067 64.68 16.981 ;
     RECT  2.4 16.499 5.592 17.075 ;
     RECT  18.6 16.981 64.68 17.075 ;
     RECT  66.72 16.787 66.84 17.131 ;
     RECT  66.72 17.131 66.792 17.195 ;
     RECT  26.784 17.075 64.68 17.387 ;
     RECT  27.696 17.387 64.68 17.411 ;
     RECT  18.6 17.075 25.656 17.643 ;
     RECT  66.72 17.195 66.744 17.707 ;
     RECT  2.4 17.075 4.968 17.797 ;
     RECT  23.376 17.643 25.656 17.843 ;
     RECT  2.304 17.797 4.968 18.037 ;
     RECT  6.816 16.837 17.208 18.133 ;
     RECT  6.576 18.133 17.208 18.181 ;
     RECT  2.304 18.037 5.112 18.485 ;
     RECT  6.48 18.181 17.208 18.485 ;
     RECT  27.696 17.411 44.472 18.707 ;
     RECT  2.304 18.485 17.208 18.755 ;
     RECT  18.6 17.643 22.008 18.757 ;
     RECT  23.376 17.843 24.84 18.757 ;
     RECT  27.696 18.707 29.832 18.757 ;
     RECT  27.648 18.757 29.832 18.803 ;
     RECT  42.624 18.707 44.472 18.805 ;
     RECT  45.504 17.411 64.68 18.805 ;
     RECT  0.144 18.805 0.168 18.995 ;
     RECT  30.864 18.707 41.64 18.995 ;
     RECT  66.144 18.677 66.168 18.995 ;
     RECT  18.6 18.757 24.84 18.997 ;
     RECT  18.6 18.997 24.936 19.045 ;
     RECT  27.648 18.803 29.712 19.045 ;
     RECT  2.4 18.755 17.208 19.141 ;
     RECT  18.288 19.045 24.936 19.141 ;
     RECT  30.912 18.995 41.64 19.283 ;
     RECT  32.256 19.283 41.64 19.427 ;
     RECT  26.784 19.045 29.712 19.477 ;
     RECT  26.208 19.477 29.712 19.523 ;
     RECT  26.208 19.523 27.336 19.563 ;
     RECT  32.256 19.427 35.352 19.691 ;
     RECT  2.4 19.141 24.936 19.717 ;
     RECT  26.736 19.563 27.336 19.763 ;
     RECT  2.256 19.717 24.936 19.813 ;
     RECT  36.336 19.427 41.64 20.003 ;
     RECT  2.16 19.813 24.936 20.051 ;
     RECT  14.928 20.051 24.936 20.085 ;
     RECT  30.912 19.283 31.272 20.405 ;
     RECT  2.16 20.051 13.896 20.459 ;
     RECT  0.144 20.053 0.168 20.469 ;
     RECT  14.928 20.085 25.704 20.483 ;
     RECT  30.912 20.405 31.368 20.483 ;
     RECT  32.448 19.691 35.352 20.485 ;
     RECT  36.432 20.003 41.64 20.485 ;
     RECT  42.624 18.805 64.68 20.485 ;
     RECT  66.096 19.909 66.12 20.485 ;
     RECT  0.144 20.469 0.216 20.531 ;
     RECT  15.264 20.483 25.704 20.579 ;
     RECT  30.912 20.483 31.032 20.579 ;
     RECT  15.264 20.579 25.608 20.627 ;
     RECT  17.184 20.627 25.608 20.651 ;
     RECT  32.448 20.485 35.4 20.725 ;
     RECT  30.912 20.579 30.936 20.773 ;
     RECT  32.256 20.725 35.4 20.819 ;
     RECT  32.592 20.819 35.4 20.965 ;
     RECT  36.432 20.485 64.68 20.965 ;
     RECT  32.592 20.965 64.68 21.109 ;
     RECT  66.048 20.485 66.12 21.109 ;
     RECT  26.784 19.763 27.336 21.155 ;
     RECT  2.16 20.459 13.608 21.203 ;
     RECT  32.592 21.109 66.168 21.299 ;
     RECT  27.312 21.155 27.336 21.301 ;
     RECT  28.416 19.523 29.712 21.301 ;
     RECT  30.816 20.773 30.936 21.301 ;
     RECT  27.312 21.301 30.936 21.483 ;
     RECT  0.144 20.531 0.168 21.491 ;
     RECT  17.184 20.651 25.56 21.621 ;
     RECT  39.36 21.299 66.168 21.637 ;
     RECT  39.36 21.637 66.216 21.683 ;
     RECT  2.16 21.203 10.872 21.685 ;
     RECT  15.264 20.627 16.104 21.685 ;
     RECT  15.216 21.685 16.104 21.739 ;
     RECT  42.144 21.683 66.216 21.829 ;
     RECT  32.592 21.299 37.896 21.877 ;
     RECT  15.264 21.739 16.104 22.059 ;
     RECT  32.352 21.877 37.896 22.059 ;
     RECT  17.184 21.621 25.656 22.117 ;
     RECT  27.312 21.483 30.888 22.163 ;
     RECT  17.136 22.117 25.656 22.197 ;
     RECT  1.728 21.685 10.872 22.211 ;
     RECT  17.136 22.197 25.704 22.251 ;
     RECT  17.184 22.251 25.704 22.259 ;
     RECT  12 21.203 13.608 22.309 ;
     RECT  11.952 22.309 13.608 22.549 ;
     RECT  42.144 21.829 66.84 22.635 ;
     RECT  32.592 22.059 37.896 22.645 ;
     RECT  39.552 21.683 41.064 22.645 ;
     RECT  32.592 22.645 41.064 22.699 ;
     RECT  39.312 22.699 41.064 22.741 ;
     RECT  42.144 22.635 64.968 22.741 ;
     RECT  17.184 22.259 25.656 22.763 ;
     RECT  66.096 22.635 66.84 22.763 ;
     RECT  17.184 22.763 20.472 22.835 ;
     RECT  7.008 22.211 10.872 23.027 ;
     RECT  7.392 23.027 10.872 23.029 ;
     RECT  11.952 22.549 13.704 23.029 ;
     RECT  7.392 23.029 13.704 23.075 ;
     RECT  7.584 23.075 13.704 23.093 ;
     RECT  15.312 22.059 16.104 23.093 ;
     RECT  32.592 22.699 37.896 23.125 ;
     RECT  21.936 22.763 25.656 23.269 ;
     RECT  27.408 22.163 30.888 23.285 ;
     RECT  7.584 23.093 16.104 23.315 ;
     RECT  1.728 22.211 5.88 23.317 ;
     RECT  32.544 23.125 37.896 23.339 ;
     RECT  21.936 23.269 25.704 23.411 ;
     RECT  27.264 23.285 30.888 23.411 ;
     RECT  66.144 22.763 66.84 23.459 ;
     RECT  7.8 23.315 16.104 23.541 ;
     RECT  17.184 22.835 20.328 23.541 ;
     RECT  32.832 23.339 37.896 23.603 ;
     RECT  22.464 23.411 25.704 23.605 ;
     RECT  22.464 23.605 26.232 23.653 ;
     RECT  27.264 23.411 28.152 23.653 ;
     RECT  39.312 22.741 64.968 23.851 ;
     RECT  29.28 23.411 30.888 23.861 ;
     RECT  22.464 23.653 28.152 23.915 ;
     RECT  42.192 23.851 64.968 23.941 ;
     RECT  32.832 23.603 36.024 23.987 ;
     RECT  37.056 23.603 37.896 23.989 ;
     RECT  39.312 23.851 41.064 23.989 ;
     RECT  66.672 23.459 66.84 24.043 ;
     RECT  66.768 24.043 66.84 24.171 ;
     RECT  42.192 23.941 65.064 24.501 ;
     RECT  1.728 23.317 6.312 24.563 ;
     RECT  26.736 23.915 28.152 24.565 ;
     RECT  29.28 23.861 31.848 24.565 ;
     RECT  42.192 24.501 65.592 24.613 ;
     RECT  7.8 23.541 20.328 24.709 ;
     RECT  32.928 23.987 36.024 24.709 ;
     RECT  37.056 23.989 41.064 24.709 ;
     RECT  26.736 24.565 31.848 24.811 ;
     RECT  66.816 24.171 66.84 24.939 ;
     RECT  1.776 24.563 6.312 24.947 ;
     RECT  1.92 24.947 6.312 24.997 ;
     RECT  7.68 24.709 20.328 24.997 ;
     RECT  27.024 24.811 31.848 25.067 ;
     RECT  0.144 23.653 0.168 25.077 ;
     RECT  1.92 24.997 20.328 25.139 ;
     RECT  32.928 24.709 41.064 25.139 ;
     RECT  1.92 25.139 4.296 25.187 ;
     RECT  42.192 24.613 65.64 25.237 ;
     RECT  5.28 25.139 20.328 25.259 ;
     RECT  42.192 25.237 66.12 25.323 ;
     RECT  42.192 25.323 65.592 25.451 ;
     RECT  29.4 25.067 31.848 25.475 ;
     RECT  32.928 25.139 40.872 25.515 ;
     RECT  2.016 25.187 4.296 25.523 ;
     RECT  29.4 25.475 31.752 25.523 ;
     RECT  6.096 25.259 20.328 25.715 ;
     RECT  22.464 23.915 25.656 25.715 ;
     RECT  29.4 25.523 31.272 25.715 ;
     RECT  2.016 25.523 4.2 25.763 ;
     RECT  0.144 25.077 0.216 25.813 ;
     RECT  22.464 25.715 25.176 25.861 ;
     RECT  27.024 25.067 28.392 25.861 ;
     RECT  26.304 25.861 28.392 26.003 ;
     RECT  34.224 25.515 40.872 26.003 ;
     RECT  42.192 25.451 64.92 26.099 ;
     RECT  34.224 26.003 37.368 26.195 ;
     RECT  7.44 25.715 20.328 26.197 ;
     RECT  38.4 26.003 40.872 26.243 ;
     RECT  0.144 25.813 0.264 26.293 ;
     RECT  42.192 26.099 64.68 26.341 ;
     RECT  38.928 26.243 40.872 26.389 ;
     RECT  32.928 25.515 33.048 26.475 ;
     RECT  38.928 26.389 41.064 26.483 ;
     RECT  6.096 25.715 6.12 26.485 ;
     RECT  39.024 26.483 41.064 26.533 ;
     RECT  42.048 26.341 64.68 26.533 ;
     RECT  26.4 26.003 28.392 26.581 ;
     RECT  29.4 25.715 31.032 26.581 ;
     RECT  2.304 25.763 4.2 26.613 ;
     RECT  5.232 26.485 6.12 26.613 ;
     RECT  22.176 25.861 25.176 26.725 ;
     RECT  39.024 26.533 64.68 26.795 ;
     RECT  2.304 26.613 6.12 26.805 ;
     RECT  39.024 26.795 63.72 26.867 ;
     RECT  26.4 26.581 31.032 26.915 ;
     RECT  0.144 26.293 0.312 26.923 ;
     RECT  0.192 26.923 0.312 26.933 ;
     RECT  26.4 26.915 29.712 26.963 ;
     RECT  26.544 26.963 29.712 27.059 ;
     RECT  0.192 26.933 0.36 27.109 ;
     RECT  30.72 26.915 31.032 27.109 ;
     RECT  0.192 27.109 0.408 27.115 ;
     RECT  26.784 27.059 29.712 27.115 ;
     RECT  2.256 26.805 6.12 27.157 ;
     RECT  7.44 26.197 20.616 27.157 ;
     RECT  30.72 27.109 31.08 27.179 ;
     RECT  34.368 26.195 37.368 27.301 ;
     RECT  0.336 27.115 0.408 27.371 ;
     RECT  22.176 26.725 25.32 27.371 ;
     RECT  66.768 26.037 66.84 27.381 ;
     RECT  22.176 27.371 22.824 27.395 ;
     RECT  0.384 27.371 0.408 27.445 ;
     RECT  0.384 27.445 0.504 27.499 ;
     RECT  33.072 27.109 33.24 27.733 ;
     RECT  34.224 27.301 37.656 27.733 ;
     RECT  22.176 27.395 22.776 27.781 ;
     RECT  41.856 26.867 63.72 27.875 ;
     RECT  2.256 27.157 20.616 27.877 ;
     RECT  26.832 27.115 29.712 27.877 ;
     RECT  30.72 27.179 30.744 27.877 ;
     RECT  39.024 26.867 40.632 27.877 ;
     RECT  0.48 27.499 0.504 27.883 ;
     RECT  38.784 27.877 40.632 27.893 ;
     RECT  41.856 27.875 55.08 27.893 ;
     RECT  66.72 27.381 66.84 27.957 ;
     RECT  66.672 27.957 66.84 28.115 ;
     RECT  23.904 27.371 25.32 28.149 ;
     RECT  26.832 27.877 30.744 28.213 ;
     RECT  33.072 27.733 37.656 28.213 ;
     RECT  23.904 28.149 25.752 28.261 ;
     RECT  26.832 28.213 31.08 28.261 ;
     RECT  23.904 28.261 31.08 28.267 ;
     RECT  32.448 28.213 37.656 28.267 ;
     RECT  2.256 27.877 20.856 28.405 ;
     RECT  66.768 28.115 66.84 28.459 ;
     RECT  21.984 27.781 22.776 28.469 ;
     RECT  23.904 28.267 29.712 28.469 ;
     RECT  30.72 28.267 31.08 28.469 ;
     RECT  21.984 28.469 29.712 28.523 ;
     RECT  34.224 28.267 37.656 28.523 ;
     RECT  34.8 28.523 37.656 28.533 ;
     RECT  38.784 27.893 55.08 28.533 ;
     RECT  30.72 28.469 31.272 28.547 ;
     RECT  32.448 28.267 33.096 28.547 ;
     RECT  34.8 28.533 55.08 28.739 ;
     RECT  31.248 28.547 31.272 28.917 ;
     RECT  31.248 28.917 31.368 28.979 ;
     RECT  2.208 28.405 20.856 28.981 ;
     RECT  31.344 28.979 31.368 29.029 ;
     RECT  32.448 28.547 33.048 29.029 ;
     RECT  66.768 28.459 66.792 29.035 ;
     RECT  21.984 28.523 24.552 29.123 ;
     RECT  25.728 28.523 28.2 29.493 ;
     RECT  29.28 28.523 29.712 29.493 ;
     RECT  31.344 29.029 33.048 29.547 ;
     RECT  25.728 29.493 29.712 29.555 ;
     RECT  2.16 28.981 20.856 29.605 ;
     RECT  44.496 28.739 55.08 29.605 ;
     RECT  56.16 27.875 63.72 29.605 ;
     RECT  22.176 29.123 24.552 29.611 ;
     RECT  23.904 29.611 24.552 29.685 ;
     RECT  25.728 29.555 28.248 29.685 ;
     RECT  22.176 29.611 22.776 29.699 ;
     RECT  29.28 29.555 29.712 29.699 ;
     RECT  2.112 29.605 20.856 29.803 ;
     RECT  32.784 29.547 33.048 29.813 ;
     RECT  29.4 29.699 29.712 29.845 ;
     RECT  34.8 28.739 43.32 29.893 ;
     RECT  44.496 29.605 63.72 29.893 ;
     RECT  31.344 29.547 31.8 29.941 ;
     RECT  32.784 29.813 33.528 29.941 ;
     RECT  29.4 29.845 29.832 30.037 ;
     RECT  34.8 29.893 63.72 30.083 ;
     RECT  2.16 29.803 20.856 30.123 ;
     RECT  32.784 29.941 33.72 30.133 ;
     RECT  34.8 30.083 43.32 30.133 ;
     RECT  44.496 30.083 63.72 30.133 ;
     RECT  32.784 30.133 43.32 30.227 ;
     RECT  32.784 30.227 38.424 30.275 ;
     RECT  39.888 30.227 43.224 30.443 ;
     RECT  44.496 30.133 63.816 30.469 ;
     RECT  43.2 30.443 43.224 30.571 ;
     RECT  29.4 30.037 30.216 30.661 ;
     RECT  22.464 29.699 22.776 30.757 ;
     RECT  23.904 29.685 28.248 30.773 ;
     RECT  29.4 30.661 30.312 30.773 ;
     RECT  31.296 29.941 31.8 30.837 ;
     RECT  32.784 30.275 38.184 30.837 ;
     RECT  11.28 30.123 20.856 30.853 ;
     RECT  23.904 30.773 30.312 30.995 ;
     RECT  31.296 30.837 38.184 31.019 ;
     RECT  2.16 30.123 10.248 31.093 ;
     RECT  11.28 30.853 20.952 31.093 ;
     RECT  66.624 30.133 66.648 31.093 ;
     RECT  44.496 30.469 64.584 31.187 ;
     RECT  22.368 30.757 22.776 31.189 ;
     RECT  2.16 31.093 20.952 31.275 ;
     RECT  26.736 30.995 30.312 31.275 ;
     RECT  23.904 30.995 25.368 31.285 ;
     RECT  39.888 30.443 42.216 31.349 ;
     RECT  66.624 31.093 66.84 31.349 ;
     RECT  21.984 31.189 22.776 31.379 ;
     RECT  39.6 31.349 42.216 31.413 ;
     RECT  45.216 31.187 64.584 31.531 ;
     RECT  66.24 31.349 66.84 31.605 ;
     RECT  23.856 31.285 25.368 31.667 ;
     RECT  0.528 31.605 0.552 31.717 ;
     RECT  26.88 31.275 30.312 31.765 ;
     RECT  31.296 31.019 32.952 31.765 ;
     RECT  2.16 31.275 5.112 31.797 ;
     RECT  39.216 31.413 42.216 31.861 ;
     RECT  43.584 31.285 44.136 31.861 ;
     RECT  6.144 31.275 20.952 31.925 ;
     RECT  21.984 31.379 22.728 31.925 ;
     RECT  34.176 31.019 38.184 31.925 ;
     RECT  34.176 31.925 38.232 31.955 ;
     RECT  36.384 31.955 38.232 32.003 ;
     RECT  0.144 31.717 0.552 32.005 ;
     RECT  26.88 31.765 32.952 32.005 ;
     RECT  34.176 31.955 35.208 32.005 ;
     RECT  6.144 31.925 22.728 32.051 ;
     RECT  0.144 32.005 0.6 32.107 ;
     RECT  36.384 32.003 37.608 32.243 ;
     RECT  45.216 31.531 64.536 32.299 ;
     RECT  39.216 31.861 44.136 32.309 ;
     RECT  45.216 32.299 64.44 32.309 ;
     RECT  26.88 32.005 35.208 32.339 ;
     RECT  22.176 32.051 22.728 32.373 ;
     RECT  23.856 31.667 25.128 32.373 ;
     RECT  14.64 32.051 21.096 32.387 ;
     RECT  39.216 32.309 64.44 32.437 ;
     RECT  22.176 32.373 25.128 32.483 ;
     RECT  36.384 32.243 37.368 32.491 ;
     RECT  14.688 32.387 21.096 32.531 ;
     RECT  36.576 32.491 37.368 32.531 ;
     RECT  38.64 32.437 64.44 32.531 ;
     RECT  6.144 32.051 13.512 32.555 ;
     RECT  37.2 32.531 37.368 32.579 ;
     RECT  26.88 32.339 32.04 32.771 ;
     RECT  14.688 32.531 17.349 32.875 ;
     RECT  33.024 32.339 35.208 32.949 ;
     RECT  22.224 32.483 25.128 33.013 ;
     RECT  26.88 32.771 31.464 33.013 ;
     RECT  18.432 32.531 21.096 33.077 ;
     RECT  33.024 32.949 35.352 33.333 ;
     RECT  37.2 32.579 37.224 33.525 ;
     RECT  38.784 32.531 64.392 33.525 ;
     RECT  66.144 31.605 66.84 33.587 ;
     RECT  14.88 32.875 17.349 33.589 ;
     RECT  18.432 33.077 21.144 33.589 ;
     RECT  36.528 33.525 37.224 33.589 ;
     RECT  38.784 33.525 64.488 33.589 ;
     RECT  11.808 32.555 13.512 33.653 ;
     RECT  14.88 33.589 21.144 33.781 ;
     RECT  22.224 33.013 31.464 33.781 ;
     RECT  11.808 33.653 13.608 33.845 ;
     RECT  11.52 33.845 13.608 33.925 ;
     RECT  14.88 33.781 31.464 33.925 ;
     RECT  1.728 31.797 5.112 34.037 ;
     RECT  6.144 32.555 10.536 34.037 ;
     RECT  11.52 33.925 31.464 34.037 ;
     RECT  32.448 33.333 35.352 34.037 ;
     RECT  11.52 34.037 35.352 34.115 ;
     RECT  36.528 33.589 64.488 34.165 ;
     RECT  1.728 34.037 10.536 34.213 ;
     RECT  11.52 34.115 31.464 34.213 ;
     RECT  36.528 34.165 64.68 34.219 ;
     RECT  32.448 34.115 35.352 34.259 ;
     RECT  32.592 34.259 35.352 34.293 ;
     RECT  36.528 34.219 41.928 34.293 ;
     RECT  66.192 33.587 66.84 34.741 ;
     RECT  0.144 32.107 0.552 35.051 ;
     RECT  0.144 35.051 0.456 35.179 ;
     RECT  42.96 34.219 64.68 35.221 ;
     RECT  32.592 34.293 41.928 35.253 ;
     RECT  42.96 35.221 64.728 35.253 ;
     RECT  32.592 35.253 64.728 35.307 ;
     RECT  32.592 35.307 64.68 35.315 ;
     RECT  42.624 35.315 64.68 35.499 ;
     RECT  32.592 35.315 41.592 35.939 ;
     RECT  32.592 35.939 35.976 35.989 ;
     RECT  1.728 34.213 31.464 36.083 ;
     RECT  23.856 36.083 31.464 36.085 ;
     RECT  32.496 35.989 35.976 36.085 ;
     RECT  45.024 35.499 64.68 36.139 ;
     RECT  45.12 36.139 64.68 36.203 ;
     RECT  45.264 36.203 64.68 36.275 ;
     RECT  37.152 35.939 41.592 36.277 ;
     RECT  42.624 35.499 44.04 36.277 ;
     RECT  37.152 36.277 44.04 36.331 ;
     RECT  58.512 36.275 64.68 36.469 ;
     RECT  37.152 36.331 41.832 36.515 ;
     RECT  0.144 35.179 0.408 36.523 ;
     RECT  58.512 36.469 64.968 36.523 ;
     RECT  1.728 36.083 22.824 36.563 ;
     RECT  58.512 36.523 64.92 36.659 ;
     RECT  23.856 36.085 35.976 36.851 ;
     RECT  2.016 36.563 22.824 36.947 ;
     RECT  23.856 36.851 35.88 36.995 ;
     RECT  23.856 36.995 29.712 37.045 ;
     RECT  0.192 36.523 0.408 37.099 ;
     RECT  2.016 36.947 22.488 37.099 ;
     RECT  37.152 36.515 37.608 37.173 ;
     RECT  43.776 36.331 44.04 37.189 ;
     RECT  45.264 36.275 57.432 37.189 ;
     RECT  0.192 37.099 0.216 37.227 ;
     RECT  2.208 37.099 22.488 37.235 ;
     RECT  39.024 36.515 41.832 37.301 ;
     RECT  58.512 36.659 64.632 37.365 ;
     RECT  39.024 37.301 42.168 37.379 ;
     RECT  37.104 37.173 37.608 37.557 ;
     RECT  43.776 37.189 57.432 37.619 ;
     RECT  58.464 37.365 64.632 37.669 ;
     RECT  37.008 37.557 37.608 37.715 ;
     RECT  37.488 37.715 37.608 37.717 ;
     RECT  66.144 34.741 66.84 37.739 ;
     RECT  39.024 37.379 41.208 37.749 ;
     RECT  37.488 37.717 37.704 37.813 ;
     RECT  38.88 37.749 41.208 37.813 ;
     RECT  44.928 37.619 57.432 37.813 ;
     RECT  66.24 37.739 66.84 37.931 ;
     RECT  23.76 37.045 29.712 37.957 ;
     RECT  30.72 36.995 35.88 37.957 ;
     RECT  43.776 37.619 43.944 38.149 ;
     RECT  44.928 37.813 57.48 38.149 ;
     RECT  58.464 37.669 64.968 38.149 ;
     RECT  43.584 38.149 43.944 38.187 ;
     RECT  43.584 38.187 43.608 38.325 ;
     RECT  66.288 37.931 66.84 38.379 ;
     RECT  2.256 37.235 22.488 38.389 ;
     RECT  23.76 37.957 35.88 38.389 ;
     RECT  1.152 38.325 1.176 38.453 ;
     RECT  42.624 38.325 43.608 38.453 ;
     RECT  0.528 38.453 1.176 38.517 ;
     RECT  2.256 38.389 35.88 38.579 ;
     RECT  42.528 38.453 43.608 38.581 ;
     RECT  44.928 38.149 64.968 38.629 ;
     RECT  42.384 38.581 43.608 38.675 ;
     RECT  0.192 38.517 1.272 38.699 ;
     RECT  0.192 38.699 1.176 38.709 ;
     RECT  44.928 38.629 65.016 38.709 ;
     RECT  42.48 38.675 43.608 38.763 ;
     RECT  43.296 38.763 43.32 38.771 ;
     RECT  2.256 38.579 22.776 38.819 ;
     RECT  23.76 38.579 35.88 38.819 ;
     RECT  0.144 38.709 1.176 38.867 ;
     RECT  37.488 37.813 41.208 38.965 ;
     RECT  23.76 38.819 30.456 39.011 ;
     RECT  31.632 38.819 35.88 39.093 ;
     RECT  1.152 38.867 1.176 39.107 ;
     RECT  44.736 38.709 65.016 39.147 ;
     RECT  31.632 39.093 36.456 39.155 ;
     RECT  0.144 38.867 0.168 39.203 ;
     RECT  2.256 38.819 6.168 39.253 ;
     RECT  37.44 38.965 41.208 39.539 ;
     RECT  44.736 39.147 64.968 39.683 ;
     RECT  66.528 38.379 66.84 39.685 ;
     RECT  44.736 39.683 64.92 39.915 ;
     RECT  66.144 39.685 66.84 39.923 ;
     RECT  2.16 39.253 6.168 39.925 ;
     RECT  7.152 38.819 22.776 39.925 ;
     RECT  28.368 39.011 30.456 39.925 ;
     RECT  31.632 39.155 36.168 39.925 ;
     RECT  2.16 39.925 22.776 39.971 ;
     RECT  66.144 39.923 66.744 39.979 ;
     RECT  44.736 39.915 64.872 40.019 ;
     RECT  44.736 40.019 64.584 40.021 ;
     RECT  23.76 39.011 27.144 40.043 ;
     RECT  2.16 39.971 21.192 40.069 ;
     RECT  42.72 40.021 42.744 40.107 ;
     RECT  44.352 40.021 64.584 40.107 ;
     RECT  22.56 39.971 22.776 40.117 ;
     RECT  23.76 40.043 27.048 40.117 ;
     RECT  1.248 40.069 21.192 40.403 ;
     RECT  28.368 39.925 36.168 40.501 ;
     RECT  28.368 40.501 36.408 40.565 ;
     RECT  28.032 40.565 36.408 40.597 ;
     RECT  37.44 39.539 41.064 40.597 ;
     RECT  0.144 40.213 0.168 40.691 ;
     RECT  28.032 40.597 41.4 40.747 ;
     RECT  28.032 40.747 38.808 40.787 ;
     RECT  40.08 40.747 41.4 40.811 ;
     RECT  34.8 40.787 38.808 40.931 ;
     RECT  40.2 40.811 41.4 40.931 ;
     RECT  28.032 40.787 33.768 40.939 ;
     RECT  31.872 40.939 33.768 40.979 ;
     RECT  45.168 40.107 64.584 40.981 ;
     RECT  45.168 40.981 64.968 41.013 ;
     RECT  66.144 39.979 66.216 41.013 ;
     RECT  1.728 40.403 21.192 41.075 ;
     RECT  31.872 40.979 32.04 41.075 ;
     RECT  36.96 40.931 38.76 41.123 ;
     RECT  22.56 40.117 27.048 41.125 ;
     RECT  28.032 40.939 30.744 41.125 ;
     RECT  37.056 41.123 38.76 41.131 ;
     RECT  45.168 41.013 66.216 41.171 ;
     RECT  37.056 41.131 37.896 41.195 ;
     RECT  22.56 41.125 30.744 41.219 ;
     RECT  50.64 41.171 66.216 41.219 ;
     RECT  34.8 40.931 35.976 41.267 ;
     RECT  1.728 41.075 20.856 41.579 ;
     RECT  50.64 41.219 65.544 41.603 ;
     RECT  0.192 41.269 0.216 41.701 ;
     RECT  30.72 41.219 30.744 41.771 ;
     RECT  33.072 40.979 33.768 41.795 ;
     RECT  34.8 41.267 35.832 41.795 ;
     RECT  42.864 40.405 42.888 41.893 ;
     RECT  42.864 41.893 43.176 41.939 ;
     RECT  45.168 41.171 49.416 42.181 ;
     RECT  50.64 41.603 64.968 42.219 ;
     RECT  1.776 41.579 20.856 42.277 ;
     RECT  0.144 41.701 0.216 42.357 ;
     RECT  44.88 42.181 49.416 42.421 ;
     RECT  50.64 42.219 64.584 42.421 ;
     RECT  66.816 42.517 66.84 42.603 ;
     RECT  33.552 41.795 33.768 42.661 ;
     RECT  34.8 41.795 35.208 42.661 ;
     RECT  1.776 42.277 21.144 42.667 ;
     RECT  40.2 40.931 40.776 42.677 ;
     RECT  44.88 42.421 64.584 42.731 ;
     RECT  22.56 41.219 29.712 42.741 ;
     RECT  22.56 42.741 30.408 42.755 ;
     RECT  38.16 42.677 38.184 42.755 ;
     RECT  22.56 42.755 22.584 42.803 ;
     RECT  43.056 41.939 43.176 42.803 ;
     RECT  47.424 42.731 64.584 42.803 ;
     RECT  32.016 41.075 32.04 42.805 ;
     RECT  31.824 42.805 32.04 42.853 ;
     RECT  66.096 42.661 66.168 42.901 ;
     RECT  65.568 42.901 66.168 42.987 ;
     RECT  23.856 42.755 30.408 42.997 ;
     RECT  31.728 42.853 32.04 42.997 ;
     RECT  23.856 42.997 32.568 43.051 ;
     RECT  39.072 42.997 39.096 43.051 ;
     RECT  31.872 43.051 32.568 43.115 ;
     RECT  0.144 42.357 0.264 43.125 ;
     RECT  32.448 43.115 32.568 43.285 ;
     RECT  33.552 42.661 35.208 43.285 ;
     RECT  40.2 42.677 41.016 43.285 ;
     RECT  44.88 42.731 46.44 43.307 ;
     RECT  0.144 43.125 0.312 43.381 ;
     RECT  32.448 43.285 35.4 43.523 ;
     RECT  43.152 42.803 43.176 43.523 ;
     RECT  47.424 42.803 49.416 43.571 ;
     RECT  2.16 42.667 21.144 43.573 ;
     RECT  50.64 42.803 64.584 43.765 ;
     RECT  23.856 43.051 30.792 43.813 ;
     RECT  0.144 43.381 0.36 43.819 ;
     RECT  0.144 43.819 0.264 43.859 ;
     RECT  40.2 43.285 41.112 43.861 ;
     RECT  22.752 43.813 30.792 43.883 ;
     RECT  47.472 43.571 49.416 44.005 ;
     RECT  50.64 43.765 64.92 44.005 ;
     RECT  47.472 44.005 64.92 44.075 ;
     RECT  23.136 43.883 30.792 44.147 ;
     RECT  50.64 44.075 64.92 44.213 ;
     RECT  66.144 42.987 66.168 44.341 ;
     RECT  66.096 44.341 66.168 44.395 ;
     RECT  32.448 43.523 33.768 44.437 ;
     RECT  44.88 43.307 46.248 44.531 ;
     RECT  34.8 43.523 35.4 44.533 ;
     RECT  36.432 42.997 36.456 44.533 ;
     RECT  34.8 44.533 36.456 44.579 ;
     RECT  0.144 43.859 0.216 44.587 ;
     RECT  2.16 43.573 21.672 44.627 ;
     RECT  23.136 44.147 30.744 44.627 ;
     RECT  45.6 44.531 46.248 44.629 ;
     RECT  47.472 44.075 49.56 44.629 ;
     RECT  31.872 44.437 33.768 44.725 ;
     RECT  34.8 44.579 36.072 44.725 ;
     RECT  23.136 44.627 25.992 45.011 ;
     RECT  66.144 44.395 66.168 45.013 ;
     RECT  26.976 44.627 30.744 45.035 ;
     RECT  2.16 44.627 21.432 45.059 ;
     RECT  28.224 45.035 30.744 45.059 ;
     RECT  2.16 45.059 13.608 45.109 ;
     RECT  50.64 44.213 64.968 45.155 ;
     RECT  45.6 44.629 49.56 45.173 ;
     RECT  50.64 45.155 52.776 45.173 ;
     RECT  40.2 43.861 41.16 45.205 ;
     RECT  42.288 45.157 42.312 45.205 ;
     RECT  45.6 45.173 52.776 45.251 ;
     RECT  26.976 45.035 27 45.355 ;
     RECT  66.144 45.013 66.216 45.365 ;
     RECT  39.024 44.389 39.048 45.429 ;
     RECT  40.2 45.205 42.312 45.429 ;
     RECT  45.6 45.251 49.416 45.541 ;
     RECT  39.024 45.429 42.312 45.611 ;
     RECT  53.76 45.155 64.968 45.635 ;
     RECT  14.592 45.059 21.432 45.683 ;
     RECT  31.872 44.725 36.072 45.683 ;
     RECT  53.76 45.635 64.872 45.683 ;
     RECT  39.024 45.611 41.592 45.731 ;
     RECT  23.664 45.011 25.992 45.779 ;
     RECT  23.76 45.779 25.992 45.827 ;
     RECT  66.096 45.365 66.216 46.005 ;
     RECT  0.192 44.587 0.216 46.123 ;
     RECT  15.216 45.683 21.432 46.163 ;
     RECT  31.872 45.683 33.192 46.187 ;
     RECT  32.976 46.187 33.192 46.211 ;
     RECT  44.976 45.541 49.416 46.213 ;
     RECT  2.112 45.109 13.608 46.261 ;
     RECT  28.224 45.059 30.504 46.261 ;
     RECT  66.096 46.005 66.84 46.389 ;
     RECT  15.216 46.163 21.24 46.443 ;
     RECT  31.872 46.187 31.896 46.499 ;
     RECT  44.736 46.213 49.416 46.499 ;
     RECT  47.28 46.499 49.416 46.645 ;
     RECT  28.224 46.261 30.888 46.693 ;
     RECT  43.296 45.557 43.32 46.739 ;
     RECT  66.048 46.389 66.84 46.739 ;
     RECT  2.016 46.261 13.608 46.741 ;
     RECT  47.28 46.645 49.608 46.763 ;
     RECT  44.736 46.499 46.248 46.773 ;
     RECT  53.76 45.683 64.824 46.773 ;
     RECT  15.216 46.443 21.144 46.787 ;
     RECT  23.808 45.827 25.992 46.827 ;
     RECT  37.296 45.541 37.32 46.827 ;
     RECT  39.888 45.731 41.592 46.827 ;
     RECT  38.784 46.773 38.808 46.835 ;
     RECT  2.016 46.741 13.992 46.837 ;
     RECT  50.64 45.251 52.776 46.837 ;
     RECT  53.76 46.773 64.92 46.837 ;
     RECT  66.048 46.739 66.264 46.901 ;
     RECT  34.224 45.683 36.072 47.019 ;
     RECT  15.216 46.787 20.856 47.027 ;
     RECT  47.664 46.763 49.608 47.027 ;
     RECT  2.016 46.837 14.136 47.083 ;
     RECT  50.64 46.837 64.92 47.221 ;
     RECT  65.904 46.901 66.264 47.221 ;
     RECT  2.016 47.083 14.088 47.285 ;
     RECT  28.224 46.693 31.512 47.363 ;
     RECT  44.448 46.773 46.248 47.363 ;
     RECT  47.76 47.027 49.608 47.363 ;
     RECT  50.64 47.221 66.264 47.363 ;
     RECT  1.968 47.285 14.088 47.413 ;
     RECT  29.088 47.363 31.512 47.461 ;
     RECT  1.92 47.413 14.088 47.541 ;
     RECT  47.76 47.363 49.56 47.651 ;
     RECT  23.808 46.827 25.752 47.797 ;
     RECT  26.736 47.701 26.76 47.797 ;
     RECT  23.808 47.797 26.76 47.843 ;
     RECT  37.056 46.965 37.08 47.845 ;
     RECT  50.688 47.363 66.264 47.851 ;
     RECT  65.568 47.851 66.264 47.925 ;
     RECT  23.808 47.843 26.232 47.939 ;
     RECT  22.56 47.269 22.584 47.941 ;
     RECT  23.808 47.939 25.512 47.941 ;
     RECT  32.976 46.211 33.096 47.989 ;
     RECT  36.48 47.845 37.08 47.989 ;
     RECT  39.12 47.749 39.144 47.989 ;
     RECT  40.2 46.827 41.592 47.989 ;
     RECT  15.216 47.027 15.288 48.043 ;
     RECT  50.688 47.851 64.44 48.043 ;
     RECT  39.12 47.989 41.592 48.171 ;
     RECT  32.832 47.989 33.096 48.229 ;
     RECT  34.224 47.019 35.112 48.229 ;
     RECT  65.568 47.925 66.792 48.235 ;
     RECT  29.088 47.461 31.848 48.245 ;
     RECT  32.832 48.229 35.112 48.245 ;
     RECT  1.728 47.541 14.088 48.373 ;
     RECT  15.216 48.043 15.24 48.373 ;
     RECT  27.936 47.845 27.96 48.421 ;
     RECT  29.088 48.245 35.112 48.421 ;
     RECT  22.56 47.941 25.512 48.515 ;
     RECT  0.336 48.437 0.36 48.565 ;
     RECT  16.32 47.027 20.856 48.629 ;
     RECT  66.096 48.235 66.792 48.661 ;
     RECT  0.24 48.565 0.36 48.693 ;
     RECT  0.144 48.693 0.36 48.875 ;
     RECT  27.936 48.421 35.112 48.949 ;
     RECT  36.48 47.989 37.224 48.949 ;
     RECT  39.12 48.171 40.512 48.949 ;
     RECT  48.576 47.651 49.56 48.949 ;
     RECT  50.688 48.043 54.072 48.949 ;
     RECT  0.144 48.875 0.264 49.003 ;
     RECT  47.808 48.949 54.072 49.003 ;
     RECT  66.096 48.661 66.84 49.003 ;
     RECT  44.736 47.363 46.248 49.077 ;
     RECT  0.144 49.003 0.168 49.091 ;
     RECT  43.872 49.077 46.248 49.139 ;
     RECT  27.024 48.949 35.112 49.141 ;
     RECT  26.592 49.141 35.112 49.235 ;
     RECT  48.624 49.003 54.072 49.235 ;
     RECT  23.184 48.515 25.512 49.237 ;
     RECT  23.184 49.237 25.656 49.323 ;
     RECT  36.48 48.949 37.608 49.333 ;
     RECT  38.736 48.949 40.512 49.333 ;
     RECT  36.48 49.333 40.512 49.397 ;
     RECT  41.568 48.171 41.592 49.397 ;
     RECT  1.728 48.373 15.24 49.717 ;
     RECT  16.32 48.629 21.912 49.717 ;
     RECT  52.752 49.235 54.072 49.973 ;
     RECT  55.344 48.043 64.44 49.973 ;
     RECT  1.728 49.717 21.912 50.037 ;
     RECT  23.184 49.323 25.512 50.037 ;
     RECT  66.24 49.003 66.84 50.101 ;
     RECT  43.296 50.053 43.32 50.155 ;
     RECT  26.784 49.235 35.112 50.291 ;
     RECT  36.48 49.397 41.592 50.293 ;
     RECT  1.728 50.037 25.512 50.339 ;
     RECT  36.432 50.293 41.592 50.341 ;
     RECT  23.856 50.339 25.512 50.389 ;
     RECT  27.552 50.291 35.112 50.389 ;
     RECT  36.432 50.341 42.312 50.389 ;
     RECT  52.752 49.973 64.44 50.437 ;
     RECT  0.336 50.357 0.36 50.485 ;
     RECT  27.552 50.389 42.312 50.485 ;
     RECT  27.552 50.485 42.36 50.579 ;
     RECT  0.144 50.485 0.36 50.603 ;
     RECT  39.264 50.579 42.36 50.667 ;
     RECT  0.144 50.603 0.264 50.731 ;
     RECT  39.264 50.667 42.216 50.731 ;
     RECT  44.736 49.139 46.248 50.741 ;
     RECT  48.624 49.235 51.768 50.741 ;
     RECT  52.752 50.437 64.632 50.741 ;
     RECT  23.856 50.389 26.184 50.795 ;
     RECT  1.728 50.339 22.824 50.859 ;
     RECT  48.624 50.741 64.92 50.997 ;
     RECT  66.144 50.101 66.84 50.997 ;
     RECT  48.624 50.997 66.84 51.061 ;
     RECT  0.144 50.731 0.168 51.115 ;
     RECT  47.28 51.061 66.84 51.317 ;
     RECT  47.232 51.317 66.84 51.347 ;
     RECT  15.072 50.859 22.824 51.381 ;
     RECT  23.856 50.795 25.512 51.381 ;
     RECT  47.232 51.347 64.968 51.395 ;
     RECT  27.552 50.579 37.704 51.397 ;
     RECT  43.872 50.741 46.248 51.445 ;
     RECT  47.664 51.395 64.92 51.491 ;
     RECT  43.296 51.445 46.248 51.539 ;
     RECT  26.784 51.397 37.704 51.573 ;
     RECT  47.664 51.491 64.44 51.635 ;
     RECT  26.784 51.573 38.136 51.765 ;
     RECT  15.072 51.381 25.512 51.781 ;
     RECT  26.784 51.765 38.28 51.781 ;
     RECT  43.536 51.539 46.248 51.781 ;
     RECT  47.664 51.635 64.392 51.827 ;
     RECT  15.072 51.781 38.28 51.923 ;
     RECT  15.072 51.923 26.856 51.925 ;
     RECT  27.888 51.923 38.28 51.947 ;
     RECT  1.728 50.859 13.656 51.957 ;
     RECT  47.664 51.827 49.704 51.971 ;
     RECT  14.832 51.925 26.856 52.011 ;
     RECT  36.48 51.947 38.28 52.021 ;
     RECT  39.408 50.731 42.168 52.021 ;
     RECT  27.888 51.947 35.256 52.211 ;
     RECT  0.336 52.213 0.36 52.261 ;
     RECT  66.144 51.347 66.84 52.331 ;
     RECT  14.832 52.011 26.808 52.459 ;
     RECT  66.144 52.331 66.792 52.459 ;
     RECT  27.888 52.211 35.112 52.499 ;
     RECT  36.48 52.021 42.168 52.499 ;
     RECT  43.536 51.781 46.344 52.597 ;
     RECT  14.832 52.459 26.76 52.715 ;
     RECT  36.48 52.499 40.512 52.739 ;
     RECT  0.24 52.261 0.36 52.741 ;
     RECT  66.144 52.459 66.744 52.779 ;
     RECT  36.72 52.739 40.512 52.787 ;
     RECT  50.88 51.827 64.392 52.789 ;
     RECT  1.728 51.957 13.752 52.837 ;
     RECT  14.832 52.715 25.512 52.837 ;
     RECT  50.736 52.789 64.392 52.853 ;
     RECT  47.856 51.971 49.704 52.885 ;
     RECT  50.736 52.853 64.488 52.885 ;
     RECT  27.888 52.499 31.32 52.979 ;
     RECT  41.568 52.499 42.168 52.981 ;
     RECT  47.856 52.885 64.488 53.045 ;
     RECT  1.728 52.837 25.512 53.075 ;
     RECT  43.536 52.597 46.728 53.075 ;
     RECT  47.856 53.045 64.968 53.163 ;
     RECT  55.872 53.163 64.968 53.227 ;
     RECT  66.144 52.779 66.648 53.227 ;
     RECT  32.4 52.499 35.112 53.237 ;
     RECT  32.4 53.237 35.352 53.291 ;
     RECT  47.856 53.163 54.888 53.363 ;
     RECT  1.728 53.075 25.416 53.555 ;
     RECT  0.192 52.741 0.36 53.557 ;
     RECT  26.736 52.715 26.76 53.557 ;
     RECT  27.888 52.979 31.272 53.557 ;
     RECT  44.16 53.075 46.728 53.557 ;
     RECT  47.856 53.363 54.84 53.557 ;
     RECT  26.736 53.557 31.272 53.651 ;
     RECT  36.72 52.787 37.368 53.749 ;
     RECT  66.576 53.227 66.648 53.813 ;
     RECT  1.728 53.555 13.752 53.939 ;
     RECT  41.568 52.981 42.216 54.037 ;
     RECT  14.832 53.555 25.416 54.059 ;
     RECT  26.736 53.651 27.432 54.069 ;
     RECT  41.52 54.037 42.216 54.069 ;
     RECT  66.576 53.813 66.792 54.069 ;
     RECT  55.872 53.227 64.776 54.083 ;
     RECT  38.736 52.787 40.512 54.123 ;
     RECT  28.512 53.651 31.272 54.131 ;
     RECT  41.52 54.069 42.792 54.131 ;
     RECT  14.88 54.059 25.416 54.133 ;
     RECT  26.64 54.069 27.432 54.133 ;
     RECT  34.08 53.291 35.352 54.261 ;
     RECT  36.432 53.749 37.368 54.261 ;
     RECT  34.08 54.261 37.368 54.373 ;
     RECT  44.16 53.557 54.84 54.389 ;
     RECT  55.872 54.083 64.68 54.389 ;
     RECT  34.08 54.373 37.464 54.443 ;
     RECT  1.728 53.939 13.656 54.467 ;
     RECT  32.4 53.291 32.424 54.517 ;
     RECT  38.784 54.123 40.512 54.563 ;
     RECT  32.4 54.517 32.616 54.645 ;
     RECT  66.576 54.069 66.84 54.645 ;
     RECT  28.512 54.131 30.936 54.659 ;
     RECT  0.144 53.557 0.36 54.707 ;
     RECT  41.52 54.131 42.696 54.755 ;
     RECT  1.776 54.467 13.656 54.899 ;
     RECT  2.16 54.899 13.656 54.965 ;
     RECT  32.4 54.645 33.096 55.221 ;
     RECT  34.08 54.443 36.744 55.221 ;
     RECT  40.08 54.563 40.512 55.237 ;
     RECT  41.52 54.755 42.456 55.237 ;
     RECT  32.4 55.221 36.744 55.283 ;
     RECT  2.16 54.965 13.704 55.379 ;
     RECT  2.304 55.379 13.704 55.477 ;
     RECT  14.88 54.133 27.432 55.477 ;
     RECT  34.08 55.283 36.744 55.541 ;
     RECT  44.16 54.389 64.68 55.659 ;
     RECT  44.16 55.659 54.888 55.787 ;
     RECT  34.08 55.541 38.088 55.813 ;
     RECT  28.512 54.659 30.888 55.851 ;
     RECT  32.4 55.283 33.096 55.861 ;
     RECT  34.08 55.813 38.184 55.907 ;
     RECT  55.968 55.659 64.68 55.907 ;
     RECT  0.144 54.707 0.312 55.957 ;
     RECT  40.08 55.237 42.456 56.005 ;
     RECT  0.144 55.957 0.408 56.053 ;
     RECT  39.984 56.005 42.456 56.053 ;
     RECT  34.8 55.907 38.184 56.101 ;
     RECT  31.872 55.861 33.096 56.107 ;
     RECT  44.16 55.787 54.792 56.147 ;
     RECT  39.984 56.053 42.888 56.149 ;
     RECT  44.16 56.147 53.064 56.149 ;
     RECT  39.984 56.149 53.064 56.235 ;
     RECT  2.304 55.477 27.432 56.245 ;
     RECT  28.512 55.851 30.84 56.245 ;
     RECT  39.984 56.235 43.752 56.341 ;
     RECT  32.256 56.107 33.096 56.389 ;
     RECT  2.304 56.245 30.84 56.427 ;
     RECT  39.888 56.341 43.752 56.427 ;
     RECT  34.8 56.101 38.568 56.437 ;
     RECT  39.888 56.427 42.12 56.437 ;
     RECT  45.024 56.235 53.064 56.491 ;
     RECT  34.8 56.437 42.12 56.531 ;
     RECT  0.144 56.053 0.552 56.555 ;
     RECT  45.024 56.491 51.312 56.747 ;
     RECT  34.8 56.531 40.776 56.915 ;
     RECT  54.048 56.147 54.792 56.949 ;
     RECT  55.968 55.907 64.632 56.949 ;
     RECT  34.8 56.915 40.68 57.059 ;
     RECT  0.192 56.555 0.552 57.195 ;
     RECT  54.048 56.949 64.632 57.203 ;
     RECT  58.656 57.203 64.632 57.301 ;
     RECT  66.144 54.645 66.84 57.301 ;
     RECT  0.192 57.195 0.408 57.323 ;
     RECT  43.296 56.427 43.752 57.443 ;
     RECT  0.192 57.323 0.264 57.451 ;
     RECT  2.304 56.427 29.712 57.493 ;
     RECT  34.8 57.059 37.176 57.515 ;
     RECT  38.208 57.059 40.68 57.539 ;
     RECT  45.12 56.747 51.312 57.539 ;
     RECT  32.256 56.389 33.72 57.541 ;
     RECT  1.728 57.493 29.712 57.579 ;
     RECT  34.8 57.515 36.936 57.587 ;
     RECT  2.256 57.579 29.712 57.589 ;
     RECT  30.816 56.427 30.84 57.589 ;
     RECT  31.872 57.541 33.72 57.589 ;
     RECT  54.048 57.203 57.528 57.635 ;
     RECT  49.152 57.539 51.312 57.653 ;
     RECT  52.464 56.491 53.064 57.653 ;
     RECT  54.048 57.635 54.744 57.653 ;
     RECT  2.256 57.589 30.84 57.685 ;
     RECT  31.824 57.589 33.72 57.685 ;
     RECT  2.256 57.685 33.72 57.717 ;
     RECT  34.8 57.587 36.84 57.717 ;
     RECT  2.256 57.717 36.84 57.771 ;
     RECT  49.152 57.653 54.744 57.827 ;
     RECT  0.144 57.685 0.168 57.875 ;
     RECT  21.984 57.771 36.84 57.923 ;
     RECT  33.648 57.923 36.84 58.211 ;
     RECT  33.648 58.211 36.552 58.307 ;
     RECT  21.984 57.923 32.664 58.403 ;
     RECT  34.8 58.307 36.408 58.451 ;
     RECT  40.2 57.539 40.68 58.501 ;
     RECT  42 57.845 42.024 58.501 ;
     RECT  49.152 57.827 51.528 58.547 ;
     RECT  40.2 58.501 42.024 58.549 ;
     RECT  43.296 57.443 43.656 58.549 ;
     RECT  58.656 57.301 66.84 58.549 ;
     RECT  40.2 58.549 43.656 58.643 ;
     RECT  58.656 58.549 66.888 58.643 ;
     RECT  2.256 57.771 21 58.645 ;
     RECT  36.384 58.451 36.408 58.739 ;
     RECT  58.656 58.643 66.792 58.883 ;
     RECT  0.336 58.869 0.36 58.885 ;
     RECT  2.16 58.645 21 58.933 ;
     RECT  21.984 58.403 25.32 58.933 ;
     RECT  38.208 57.539 38.76 58.933 ;
     RECT  58.656 58.883 64.68 58.981 ;
     RECT  66.096 58.883 66.792 58.987 ;
     RECT  52.608 57.827 54.744 58.997 ;
     RECT  55.728 57.635 57.528 58.997 ;
     RECT  38.208 58.933 39.144 59.029 ;
     RECT  52.608 58.997 57.528 59.029 ;
     RECT  58.608 58.981 64.68 59.029 ;
     RECT  37.632 59.029 39.144 59.075 ;
     RECT  0.336 58.885 0.408 59.077 ;
     RECT  49.296 58.547 51.528 59.077 ;
     RECT  52.608 59.029 64.68 59.077 ;
     RECT  26.592 58.403 32.664 59.115 ;
     RECT  40.2 58.643 41.16 59.173 ;
     RECT  2.16 58.933 25.32 59.221 ;
     RECT  45.12 57.539 48.024 59.267 ;
     RECT  42.288 58.643 43.656 59.269 ;
     RECT  42.288 59.269 43.992 59.363 ;
     RECT  43.968 59.363 43.992 59.411 ;
     RECT  26.736 59.115 32.664 59.413 ;
     RECT  33.648 58.307 33.672 59.413 ;
     RECT  2.064 59.221 25.32 59.603 ;
     RECT  49.296 59.077 64.68 59.605 ;
     RECT  37.632 59.075 39.048 59.653 ;
     RECT  37.056 59.653 39.048 59.795 ;
     RECT  40.032 59.173 41.16 59.795 ;
     RECT  66.288 58.987 66.792 59.829 ;
     RECT  23.232 59.603 25.32 59.891 ;
     RECT  2.064 59.603 22.008 59.947 ;
     RECT  42.288 59.363 42.408 60.085 ;
     RECT  48.96 59.605 64.68 60.085 ;
     RECT  23.472 59.891 25.32 60.131 ;
     RECT  34.8 58.451 35.352 60.133 ;
     RECT  37.584 59.795 39.048 60.181 ;
     RECT  40.032 59.795 40.632 60.181 ;
     RECT  48.96 60.085 65.016 60.213 ;
     RECT  66.288 59.829 66.888 60.213 ;
     RECT  48.96 60.213 66.888 60.275 ;
     RECT  37.584 60.181 40.632 60.323 ;
     RECT  2.112 59.947 22.008 60.395 ;
     RECT  45.12 59.267 47.832 60.405 ;
     RECT  48.96 60.275 53.4 60.405 ;
     RECT  26.736 59.413 33.672 60.467 ;
     RECT  41.616 60.085 42.408 60.467 ;
     RECT  54.576 60.275 66.888 60.467 ;
     RECT  6.288 60.395 22.008 60.523 ;
     RECT  23.568 60.131 25.32 60.563 ;
     RECT  56.4 60.467 66.888 60.563 ;
     RECT  34.8 60.133 36.504 60.611 ;
     RECT  56.4 60.563 66.12 60.659 ;
     RECT  26.736 60.467 33.24 60.707 ;
     RECT  2.112 60.395 5.064 60.843 ;
     RECT  45.12 60.405 53.4 60.843 ;
     RECT  42.336 60.467 42.408 60.851 ;
     RECT  23.76 60.563 25.32 60.853 ;
     RECT  56.4 60.659 65.592 60.907 ;
     RECT  2.16 60.843 5.064 60.971 ;
     RECT  45.504 60.843 53.4 60.971 ;
     RECT  0.144 59.077 0.408 61.139 ;
     RECT  26.736 60.707 33.144 61.189 ;
     RECT  42.384 60.851 42.408 61.189 ;
     RECT  45.6 60.971 53.4 61.237 ;
     RECT  54.576 60.467 55.272 61.237 ;
     RECT  26.352 61.189 33.144 61.291 ;
     RECT  2.208 60.971 5.064 61.365 ;
     RECT  6.288 60.523 21.672 61.365 ;
     RECT  45.6 61.237 55.272 61.419 ;
     RECT  23.76 60.853 25.368 61.525 ;
     RECT  61.584 60.907 65.592 61.547 ;
     RECT  22.8 61.525 25.368 61.557 ;
     RECT  26.352 61.291 32.376 61.557 ;
     RECT  42.384 61.189 42.648 61.667 ;
     RECT  45.6 61.419 53.496 61.739 ;
     RECT  66.096 61.621 66.12 61.749 ;
     RECT  37.584 60.323 39.048 61.765 ;
     RECT  40.08 60.323 40.512 61.765 ;
     RECT  37.584 61.765 40.512 61.813 ;
     RECT  36.096 60.611 36.504 61.861 ;
     RECT  37.584 61.813 40.632 61.861 ;
     RECT  36.096 61.861 40.632 61.867 ;
     RECT  50.112 61.739 53.496 61.867 ;
     RECT  22.8 61.557 32.376 61.995 ;
     RECT  2.208 61.365 21.672 62.005 ;
     RECT  0.144 61.139 0.312 62.149 ;
     RECT  56.4 60.907 60.456 62.149 ;
     RECT  2.112 62.005 21.672 62.187 ;
     RECT  61.584 61.547 64.968 62.195 ;
     RECT  23.52 61.995 32.376 62.243 ;
     RECT  54.672 61.419 55.272 62.245 ;
     RECT  56.304 62.149 60.456 62.245 ;
     RECT  61.584 62.195 64.68 62.261 ;
     RECT  50.16 61.867 53.496 62.389 ;
     RECT  45.6 61.739 49.032 62.453 ;
     RECT  54.672 62.245 60.456 62.517 ;
     RECT  61.536 62.261 64.68 62.517 ;
     RECT  40.2 61.867 40.632 62.571 ;
     RECT  23.76 62.243 32.376 62.635 ;
     RECT  0.144 62.149 0.552 62.675 ;
     RECT  45.168 62.453 49.032 62.675 ;
     RECT  26.352 62.635 32.376 62.677 ;
     RECT  34.8 60.611 35.112 62.677 ;
     RECT  14.784 62.187 21.672 62.723 ;
     RECT  2.16 62.187 13.512 62.763 ;
     RECT  54.672 62.517 64.68 62.763 ;
     RECT  45.6 62.675 49.032 62.771 ;
     RECT  23.76 62.635 25.32 62.915 ;
     RECT  16.32 62.723 21.672 62.955 ;
     RECT  16.32 62.955 21.096 62.963 ;
     RECT  34.176 62.677 35.112 62.965 ;
     RECT  36.096 61.867 39.048 62.965 ;
     RECT  47.232 62.771 49.032 63.093 ;
     RECT  50.16 62.389 53.592 63.093 ;
     RECT  54.672 62.763 64.488 63.093 ;
     RECT  47.232 63.093 64.488 63.147 ;
     RECT  13.2 62.763 13.512 63.205 ;
     RECT  14.784 62.723 15.24 63.205 ;
     RECT  0.144 62.675 0.36 63.211 ;
     RECT  13.2 63.205 15.24 63.275 ;
     RECT  14.784 63.275 15.24 63.299 ;
     RECT  16.32 62.963 20.952 63.299 ;
     RECT  23.856 62.915 25.32 63.299 ;
     RECT  34.176 62.965 39.048 63.299 ;
     RECT  0.144 63.211 0.264 63.339 ;
     RECT  2.16 62.763 12.168 63.347 ;
     RECT  16.56 63.299 17.112 63.347 ;
     RECT  47.232 63.147 47.4 63.347 ;
     RECT  40.2 62.571 40.512 63.349 ;
     RECT  48.432 63.147 64.488 63.395 ;
     RECT  39.456 63.349 40.512 63.403 ;
     RECT  66.096 61.749 66.888 63.491 ;
     RECT  47.376 63.347 47.4 63.723 ;
     RECT  45.6 62.771 46.152 63.731 ;
     RECT  26.352 62.677 32.424 63.733 ;
     RECT  34.176 63.299 38.184 63.733 ;
     RECT  48.432 63.395 58.968 63.779 ;
     RECT  60.192 63.395 64.488 63.779 ;
     RECT  26.352 63.733 32.712 63.781 ;
     RECT  34.128 63.733 38.184 63.781 ;
     RECT  42.624 61.667 42.648 63.781 ;
     RECT  26.352 63.781 38.184 63.827 ;
     RECT  48.432 63.779 54.12 63.827 ;
     RECT  24 63.299 25.32 63.829 ;
     RECT  26.352 63.827 35.976 63.829 ;
     RECT  0.24 63.339 0.264 63.851 ;
     RECT  14.784 63.299 14.856 63.875 ;
     RECT  48.432 63.827 52.536 63.875 ;
     RECT  60.864 63.779 64.488 63.875 ;
     RECT  66.096 63.491 66.168 63.875 ;
     RECT  42.624 63.781 42.84 63.915 ;
     RECT  54.096 63.827 54.12 63.915 ;
     RECT  37.44 63.827 38.184 63.923 ;
     RECT  41.568 63.861 41.592 63.923 ;
     RECT  60.96 63.875 64.488 63.925 ;
     RECT  2.256 63.347 12.168 64.019 ;
     RECT  24 63.829 35.976 64.019 ;
     RECT  42.624 63.915 42.648 64.019 ;
     RECT  55.104 63.779 58.968 64.019 ;
     RECT  60.96 63.925 64.968 64.019 ;
     RECT  48.432 63.875 51.312 64.115 ;
     RECT  55.104 64.019 57.912 64.115 ;
     RECT  48.432 64.115 49.224 64.165 ;
     RECT  14.784 63.875 14.808 64.307 ;
     RECT  24 64.019 35.112 64.309 ;
     RECT  47.472 64.165 49.224 64.355 ;
     RECT  2.4 64.019 12.168 64.357 ;
     RECT  13.2 63.275 13.512 64.357 ;
     RECT  16.56 63.347 16.584 64.357 ;
     RECT  18.096 63.299 20.952 64.357 ;
     RECT  23.184 64.309 35.112 64.357 ;
     RECT  60.96 64.019 62.112 64.363 ;
     RECT  63.264 64.019 64.968 64.363 ;
     RECT  66.144 63.875 66.168 64.403 ;
     RECT  16.56 64.357 20.952 64.405 ;
     RECT  22.992 64.357 35.112 64.405 ;
     RECT  50.496 64.115 51.312 64.427 ;
     RECT  52.512 63.875 52.536 64.427 ;
     RECT  55.104 64.115 55.128 64.427 ;
     RECT  56.4 64.115 57.912 64.427 ;
     RECT  2.4 64.357 13.512 64.451 ;
     RECT  50.88 64.427 51.312 64.451 ;
     RECT  57.84 64.427 57.912 64.451 ;
     RECT  61.584 64.363 62.112 64.451 ;
     RECT  63.84 64.363 64.968 64.451 ;
     RECT  64.368 64.451 64.392 64.499 ;
     RECT  57.84 64.451 57.864 64.547 ;
     RECT  9.456 64.451 13.512 64.553 ;
     RECT  16.56 64.405 35.112 64.553 ;
     RECT  45.6 63.731 45.912 64.553 ;
     RECT  51 64.451 51.312 64.553 ;
     RECT  56.4 64.427 56.712 64.553 ;
     RECT  61.8 64.451 62.112 64.553 ;
     RECT  37.728 63.923 38.184 64.595 ;
     RECT  2.4 64.451 8.328 64.823 ;
     RECT  9.456 64.553 13.32 64.823 ;
     RECT  16.56 64.553 34.92 64.823 ;
     RECT  45.6 64.553 45.72 64.823 ;
     RECT  51 64.553 51.12 64.823 ;
     RECT  56.4 64.553 56.52 64.823 ;
     RECT  61.8 64.553 61.92 64.823 ;
     RECT  16.56 64.823 34.344 64.933 ;
     RECT  40.2 63.403 40.512 64.933 ;
     RECT  16.368 64.933 34.344 64.981 ;
     RECT  37.872 64.595 38.184 64.981 ;
     RECT  39.792 64.933 40.584 64.981 ;
     RECT  47.472 64.355 48.84 65.797 ;
     RECT  3.024 64.823 8.328 66.037 ;
     RECT  9.456 64.823 12.36 66.037 ;
     RECT  3.024 66.037 12.36 66.085 ;
     RECT  15.6 64.981 34.344 66.085 ;
     RECT  47.472 65.797 48.936 66.085 ;
     RECT  2.928 66.085 12.36 66.133 ;
     RECT  15.6 66.085 34.44 66.133 ;
     RECT  15.6 66.133 34.632 66.229 ;
     RECT  2.736 66.133 12.36 66.485 ;
     RECT  2.544 66.485 12.36 66.709 ;
     RECT  47.376 66.085 48.936 66.805 ;
     RECT  2.544 66.709 12.456 66.896 ;
     RECT  15.6 66.229 34.728 66.896 ;
     RECT  37.872 64.981 40.872 66.896 ;
     RECT  47.28 66.805 48.936 66.896 ;
    LAYER M6 ;
     RECT  0.016 2.496 0.133 10.592 ;
     RECT  0.016 19.904 0.133 32.096 ;
     RECT  0.016 41.408 0.133 53.6 ;
     RECT  0.133 36.48 0.181 36.512 ;
     RECT  0.133 38.72 0.181 38.752 ;
     RECT  0.133 2.304 0.229 10.592 ;
     RECT  0.181 36.48 0.229 37.216 ;
     RECT  0.133 59.136 0.229 63.328 ;
     RECT  0.016 56.256 0.275 57.696 ;
     RECT  0.275 56.384 0.325 57.696 ;
     RECT  0.229 59.136 0.325 63.84 ;
     RECT  0.133 19.904 0.373 34.272 ;
     RECT  0.373 19.904 0.421 34.464 ;
     RECT  0.229 35.904 0.421 37.216 ;
     RECT  0.421 19.904 0.517 37.216 ;
     RECT  0.181 38.528 0.517 38.752 ;
     RECT  0.229 2.304 1.283 10.784 ;
     RECT  0.517 19.904 2.243 38.752 ;
     RECT  2.243 20.032 2.245 38.752 ;
     RECT  2.245 20.032 2.293 39.968 ;
     RECT  0.133 41.408 2.293 53.856 ;
     RECT  1.283 2.304 2.339 10.592 ;
     RECT  2.293 20.032 2.339 53.856 ;
     RECT  2.533 66.496 2.629 66.528 ;
     RECT  2.16 14.816 2.773 15.488 ;
     RECT  0.325 56.384 2.773 63.84 ;
     RECT  2.773 14.4 2.821 15.488 ;
     RECT  2.773 56.384 2.821 64.48 ;
     RECT  2.339 20.288 2.867 53.856 ;
     RECT  2.339 2.432 3.013 10.592 ;
     RECT  2.821 11.968 3.013 15.488 ;
     RECT  2.867 20.352 3.349 53.856 ;
     RECT  3.013 2.432 3.397 15.488 ;
     RECT  3.349 20.352 3.397 53.984 ;
     RECT  2.821 55.424 3.397 64.608 ;
     RECT  2.629 66.496 3.587 66.656 ;
     RECT  3.587 66.624 3.589 66.656 ;
     RECT  3.397 20.352 3.635 64.608 ;
     RECT  3.397 2.432 3.637 17.376 ;
     RECT  3.635 21.824 4.451 64.608 ;
     RECT  3.925 18.88 4.501 18.912 ;
     RECT  3.635 20.352 4.501 20.512 ;
     RECT  3.637 2.24 4.595 17.376 ;
     RECT  3.589 66.624 4.643 66.784 ;
     RECT  4.595 2.752 4.739 17.376 ;
     RECT  4.501 18.88 4.741 20.512 ;
     RECT  4.739 14.208 4.933 17.376 ;
     RECT  4.741 18.752 4.933 20.512 ;
     RECT  4.933 14.208 5.029 20.512 ;
     RECT  4.451 21.824 5.029 63.904 ;
     RECT  4.643 66.752 5.075 66.784 ;
     RECT  4.739 2.752 5.555 12.768 ;
     RECT  5.029 14.208 5.747 63.904 ;
     RECT  5.555 6.4 6.515 12.768 ;
     RECT  6.515 6.4 6.899 12.512 ;
     RECT  5.555 2.752 6.949 5.088 ;
     RECT  6.899 6.4 6.949 11.36 ;
     RECT  5.747 14.208 7.669 63.52 ;
     RECT  7.669 14.208 9.013 63.904 ;
     RECT  9.013 13.056 9.061 63.904 ;
     RECT  6.949 2.752 9.251 11.36 ;
     RECT  9.251 2.752 9.445 10.784 ;
     RECT  9.061 12.864 9.923 63.904 ;
     RECT  9.923 12.864 10.307 52.896 ;
     RECT  10.307 13.632 10.403 52.896 ;
     RECT  10.403 32 10.883 52.896 ;
     RECT  9.923 54.592 10.883 63.904 ;
     RECT  10.403 13.632 10.931 30.112 ;
     RECT  10.883 32.512 11.123 52.896 ;
     RECT  9.445 2.624 11.219 10.784 ;
     RECT  11.219 4.016 11.221 10.784 ;
     RECT  11.219 2.624 11.315 2.656 ;
     RECT  11.221 4.016 11.459 12.128 ;
     RECT  10.931 20.48 11.893 30.112 ;
     RECT  10.883 54.848 12.035 63.904 ;
     RECT  11.123 33.472 12.277 52.896 ;
     RECT  12.035 54.848 12.277 63.52 ;
     RECT  11.459 6.272 12.421 12.128 ;
     RECT  10.931 13.632 12.421 18.976 ;
     RECT  12.421 6.272 12.563 18.976 ;
     RECT  12.277 33.472 12.565 63.52 ;
     RECT  11.893 20.48 12.995 31.072 ;
     RECT  12.995 22.144 13.043 31.072 ;
     RECT  13.043 22.4 13.045 31.072 ;
     RECT  12.563 18.88 13.093 18.976 ;
     RECT  12.995 20.48 13.093 20.512 ;
     RECT  13.045 22.4 13.139 31.2 ;
     RECT  12.565 32.832 13.139 63.52 ;
     RECT  11.459 4.016 13.573 4.688 ;
     RECT  13.573 4.016 13.621 4.832 ;
     RECT  12.563 6.272 13.621 17.376 ;
     RECT  13.139 23.104 14.197 31.2 ;
     RECT  13.139 32.832 14.197 34.208 ;
     RECT  14.197 23.104 14.387 34.208 ;
     RECT  14.387 23.488 14.483 34.208 ;
     RECT  13.621 4.016 14.677 17.376 ;
     RECT  13.093 18.88 14.677 20.512 ;
     RECT  14.677 4.016 14.771 20.512 ;
     RECT  13.139 35.648 14.773 53.024 ;
     RECT  14.773 35.648 14.821 53.344 ;
     RECT  13.139 54.976 14.821 63.52 ;
     RECT  14.821 35.648 15.059 63.52 ;
     RECT  14.771 12.48 15.205 20.512 ;
     RECT  15.205 12.48 15.253 21.728 ;
     RECT  14.483 23.488 15.539 33.696 ;
     RECT  15.253 12.48 15.685 22.176 ;
     RECT  15.539 23.488 15.685 33.568 ;
     RECT  15.685 12.48 15.875 33.568 ;
     RECT  15.875 22.016 16.211 33.568 ;
     RECT  15.059 35.648 16.261 60.256 ;
     RECT  14.771 4.016 16.307 10.848 ;
     RECT  15.059 61.568 16.451 63.52 ;
     RECT  16.211 30.72 16.595 33.568 ;
     RECT  15.875 12.48 16.691 20.576 ;
     RECT  16.211 22.016 16.691 29.024 ;
     RECT  16.595 30.848 16.883 33.568 ;
     RECT  16.883 30.848 16.979 32.032 ;
     RECT  16.691 22.016 17.267 28 ;
     RECT  16.883 33.536 17.317 33.568 ;
     RECT  16.261 35.136 17.317 60.256 ;
     RECT  16.691 13.056 17.461 20.576 ;
     RECT  17.267 22.016 17.461 22.24 ;
     RECT  17.317 33.536 18.181 60.256 ;
     RECT  16.307 4.016 18.229 10.784 ;
     RECT  17.461 13.056 18.229 22.24 ;
     RECT  18.229 4.016 18.997 22.24 ;
     RECT  18.181 33.536 19.237 60.64 ;
     RECT  16.451 61.952 19.237 63.52 ;
     RECT  19.237 33.536 19.285 63.52 ;
     RECT  17.267 23.936 19.333 28 ;
     RECT  16.979 30.848 19.427 30.88 ;
     RECT  18.997 3.392 19.859 22.24 ;
     RECT  19.285 33.216 19.861 63.52 ;
     RECT  19.859 13.952 19.909 22.24 ;
     RECT  19.333 23.936 19.909 28.064 ;
     RECT  19.859 3.392 20.003 12 ;
     RECT  19.861 32.32 20.485 63.52 ;
     RECT  20.485 31.744 20.867 63.52 ;
     RECT  20.867 31.744 21.683 63.328 ;
     RECT  19.909 13.952 21.731 28.064 ;
     RECT  21.731 14.016 22.165 28.064 ;
     RECT  21.683 54.592 22.211 63.328 ;
     RECT  21.683 31.744 22.931 52.832 ;
     RECT  20.003 4.016 23.317 11.872 ;
     RECT  22.165 14.016 23.555 29.6 ;
     RECT  23.317 4.016 23.557 12 ;
     RECT  22.211 55.232 23.701 63.328 ;
     RECT  23.555 18.88 23.893 29.6 ;
     RECT  22.931 31.744 23.893 50.912 ;
     RECT  23.893 18.88 24.419 50.912 ;
     RECT  23.701 54.656 24.419 63.328 ;
     RECT  22.931 52.288 24.709 52.832 ;
     RECT  23.555 14.016 24.949 17.568 ;
     RECT  24.949 13.888 24.997 17.568 ;
     RECT  24.709 52.288 25.045 53.152 ;
     RECT  24.419 54.656 25.045 62.624 ;
     RECT  24.419 18.88 25.091 50.464 ;
     RECT  24.997 13.76 25.621 17.568 ;
     RECT  25.091 18.88 25.621 28.96 ;
     RECT  25.621 13.76 25.715 28.96 ;
     RECT  23.557 4.016 25.811 12.064 ;
     RECT  25.091 30.272 26.149 50.464 ;
     RECT  25.045 52.288 26.437 62.624 ;
     RECT  26.437 52.288 26.629 62.816 ;
     RECT  26.149 30.272 26.821 50.784 ;
     RECT  26.629 52.288 26.821 63.2 ;
     RECT  27.157 2.56 27.301 2.592 ;
     RECT  25.715 13.76 27.301 21.664 ;
     RECT  25.715 23.104 27.301 28.96 ;
     RECT  26.821 30.272 27.395 63.2 ;
     RECT  27.301 13.76 27.443 28.96 ;
     RECT  25.811 4.016 27.445 12 ;
     RECT  27.301 2.112 27.733 2.592 ;
     RECT  27.445 4.016 27.733 12.256 ;
     RECT  27.395 30.336 27.829 63.2 ;
     RECT  27.733 2.112 27.877 12.256 ;
     RECT  27.443 23.488 27.971 28.96 ;
     RECT  27.829 30.336 28.981 63.264 ;
     RECT  27.443 13.76 29.029 22.112 ;
     RECT  27.971 23.936 29.029 28.96 ;
     RECT  28.981 30.336 29.029 63.904 ;
     RECT  29.029 23.936 29.987 63.904 ;
     RECT  27.877 2.048 30.275 12.256 ;
     RECT  30.275 2.048 30.323 11.68 ;
     RECT  29.029 13.76 30.517 22.432 ;
     RECT  29.987 23.936 30.517 63.2 ;
     RECT  30.517 13.632 30.997 63.2 ;
     RECT  29.413 66.752 31.043 66.784 ;
     RECT  30.997 13.12 31.379 63.2 ;
     RECT  31.379 13.12 31.955 31.008 ;
     RECT  31.379 32.384 32.147 63.2 ;
     RECT  30.323 2.112 32.437 11.68 ;
     RECT  32.437 2.112 33.107 12.704 ;
     RECT  33.107 2.304 33.589 12.704 ;
     RECT  31.955 14.016 33.589 31.008 ;
     RECT  33.589 2.304 33.731 31.008 ;
     RECT  32.147 32.384 34.165 50.464 ;
     RECT  32.147 52.032 34.165 63.2 ;
     RECT  34.165 32.384 34.597 63.2 ;
     RECT  33.731 2.304 35.221 30.624 ;
     RECT  35.173 0.128 35.315 0.16 ;
     RECT  35.221 2.304 35.317 30.944 ;
     RECT  35.317 2.24 35.701 30.944 ;
     RECT  35.701 1.984 35.845 30.944 ;
     RECT  34.597 32.384 35.845 63.328 ;
     RECT  35.845 1.984 36.515 63.328 ;
     RECT  36.515 51.904 36.565 63.328 ;
     RECT  36.515 1.984 37.715 50.464 ;
     RECT  37.715 2.112 38.101 50.464 ;
     RECT  36.565 51.904 38.101 63.776 ;
     RECT  38.101 2.112 38.819 63.776 ;
     RECT  38.819 2.24 39.011 63.776 ;
     RECT  39.011 2.24 39.443 28.768 ;
     RECT  39.011 30.08 39.683 63.776 ;
     RECT  39.443 2.88 39.923 28.768 ;
     RECT  39.923 3.008 40.067 28.64 ;
     RECT  40.067 3.072 40.115 28.64 ;
     RECT  39.683 30.08 40.933 50.72 ;
     RECT  40.115 3.072 41.557 28.128 ;
     RECT  39.683 52.16 41.557 63.776 ;
     RECT  41.557 2.624 42.085 28.128 ;
     RECT  40.933 30.016 42.133 50.72 ;
     RECT  41.557 52.16 42.133 63.904 ;
     RECT  42.133 30.016 42.227 63.904 ;
     RECT  42.085 2.624 42.229 28.704 ;
     RECT  42.227 30.016 42.229 30.56 ;
     RECT  42.229 2.624 42.275 30.56 ;
     RECT  42.275 2.752 42.323 30.56 ;
     RECT  42.227 31.872 42.851 63.904 ;
     RECT  42.323 2.88 42.995 30.56 ;
     RECT  42.995 3.072 43.475 30.56 ;
     RECT  43.475 3.456 43.955 30.56 ;
     RECT  42.851 31.872 44.147 63.776 ;
     RECT  44.147 32.32 44.675 63.776 ;
     RECT  43.955 3.84 45.011 30.56 ;
     RECT  45.011 3.84 45.107 30.432 ;
     RECT  45.107 3.84 45.445 30.368 ;
     RECT  45.445 2.88 46.693 30.368 ;
     RECT  44.675 32.384 46.693 63.776 ;
     RECT  46.693 2.816 47.363 30.368 ;
     RECT  46.693 32.064 47.845 63.776 ;
     RECT  47.363 2.816 47.939 22.752 ;
     RECT  47.939 18.944 48.515 22.752 ;
     RECT  47.845 31.36 48.661 63.776 ;
     RECT  47.363 24.512 48.757 29.216 ;
     RECT  48.757 24.512 49.093 29.728 ;
     RECT  47.939 2.816 49.525 17.568 ;
     RECT  49.093 24.512 49.525 29.856 ;
     RECT  48.661 31.36 49.525 63.84 ;
     RECT  48.515 18.944 49.909 22.688 ;
     RECT  49.525 24.512 49.909 63.84 ;
     RECT  49.525 2.56 50.195 17.568 ;
     RECT  49.909 18.944 50.485 63.84 ;
     RECT  50.195 2.688 51.397 17.568 ;
     RECT  50.485 18.944 51.397 64.416 ;
     RECT  51.397 2.688 51.443 64.416 ;
     RECT  51.443 2.688 51.829 30.752 ;
     RECT  51.829 2.048 52.933 30.752 ;
     RECT  51.443 32.128 52.933 64.416 ;
     RECT  52.933 2.048 53.075 64.416 ;
     RECT  53.075 24.576 53.267 64.416 ;
     RECT  53.075 2.176 54.179 23.264 ;
     RECT  54.179 2.304 54.757 23.264 ;
     RECT  54.757 2.304 55.379 23.392 ;
     RECT  53.267 25.024 55.907 64.416 ;
     RECT  55.379 2.432 56.293 23.392 ;
     RECT  56.293 2.432 57.445 23.968 ;
     RECT  55.907 25.408 57.445 64.416 ;
     RECT  57.445 2.432 57.491 64.416 ;
     RECT  57.491 2.816 57.683 63.84 ;
     RECT  57.683 32.256 58.979 63.84 ;
     RECT  57.683 2.816 59.797 30.88 ;
     RECT  59.797 2.24 59.891 30.88 ;
     RECT  58.979 32.256 60.949 63.776 ;
     RECT  59.891 2.24 61.091 30.688 ;
     RECT  61.091 2.688 61.187 30.688 ;
     RECT  61.187 2.688 61.667 8.992 ;
     RECT  61.667 2.688 62.291 2.72 ;
     RECT  61.187 10.368 62.483 30.496 ;
     RECT  62.483 25.616 62.629 30.496 ;
     RECT  60.949 32.256 62.629 64.352 ;
     RECT  62.483 10.368 62.771 23.904 ;
     RECT  62.771 10.368 63.059 23.392 ;
     RECT  62.629 25.616 63.299 64.352 ;
     RECT  61.667 4.016 63.685 8.992 ;
     RECT  63.685 2.816 63.781 8.992 ;
     RECT  63.059 10.368 63.781 19.744 ;
     RECT  63.299 25.616 63.781 64.224 ;
     RECT  63.781 2.816 63.971 19.744 ;
     RECT  63.971 2.816 64.067 19.552 ;
     RECT  64.067 6.336 64.115 19.552 ;
     RECT  64.115 6.336 64.211 19.296 ;
     RECT  63.059 21.312 64.355 23.392 ;
     RECT  64.355 21.44 64.357 23.392 ;
     RECT  63.781 25.024 64.357 64.224 ;
     RECT  64.211 6.336 64.451 18.72 ;
     RECT  64.067 2.816 64.547 4.688 ;
     RECT  64.547 4.016 64.8 4.688 ;
     RECT  64.357 21.44 66.133 64.224 ;
     RECT  64.451 6.912 66.179 18.72 ;
     RECT  66.133 21.44 66.659 64.352 ;
     RECT  66.179 6.912 66.755 17.696 ;
     RECT  66.659 31.104 66.755 64.352 ;
     RECT  66.755 6.912 66.803 17.184 ;
     RECT  66.659 21.44 66.803 29.024 ;
     RECT  66.755 31.104 66.803 52.448 ;
     RECT  66.755 53.824 66.803 64.352 ;
     RECT  66.803 6.912 66.851 8.992 ;
     RECT  66.803 10.304 66.851 13.6 ;
     RECT  66.803 14.912 66.851 14.944 ;
     RECT  66.803 17.088 66.851 17.12 ;
     RECT  66.803 21.44 66.851 28.448 ;
     RECT  66.803 31.104 66.851 31.136 ;
     RECT  66.803 32.448 66.851 33.056 ;
     RECT  66.803 34.88 66.851 37.216 ;
     RECT  66.803 38.848 66.851 52.32 ;
     RECT  66.803 54.08 66.851 64.352 ;
     RECT  66.851 21.44 66.925 25.44 ;
     RECT  66.851 38.848 66.925 51.04 ;
     RECT  66.851 56.256 66.925 64.352 ;
  END
END ot_vms_rcl
END LIBRARY
